Omron CX-Programmer project NewProject (CX-Programmer 9.75)

# PLC NewPLC1: CS1H-H CPU65
I/O table (CPU CS1W-SCB41-V1, CS1H-CPU65H): rack 0 slot 9 CS1W-CLK23

## Global symbols (name address type ; comment)
W134.05 BOOL  ; Kaeser BYPASS

## Program MainProgram (cyclic task 0)

### Section Section1

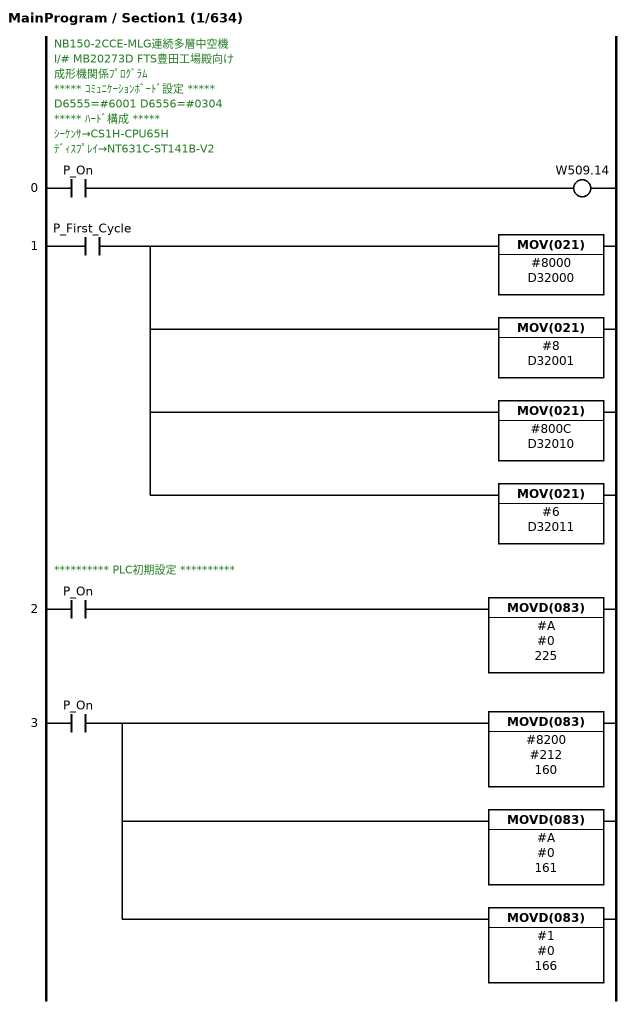
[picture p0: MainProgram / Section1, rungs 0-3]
; rung 0: NB150-2CCE-MLG連続多層中空機 / I/# MB20273D FTS豊田工場殿向け / 成形機関係ﾌﾟﾛｸﾞﾗﾑ / ***** ｺﾐｭﾆｹｰｼｮﾝﾎﾞｰﾄﾞ設定 ***** / D6555=#6001 D6556=#0304 / ***** ﾊｰﾄﾞ構成 ***** / ｼｰｹﾝｻ→CS1H-CPU65H / ﾃﾞｨｽﾌﾟﾚｲ→NT631C-ST141B-V2
LD P_On
OUT W509.14
; rung 1
LD P_First_Cycle
MOV(021) #8000 D32000
MOV(021) #8 D32001
MOV(021) #800C D32010  // 変更前　#851C
MOV(021) #6 D32011  // 変更前　#0000
; rung 2: ********** PLC初期設定 **********
LD P_On
MOVD(083) #A #0 225  // 瞬停検出 10ms
; rung 3
LD P_On
MOVD(083) #8200 #212 160  // NTﾘﾝｸﾓｰﾄﾞ
MOVD(083) #A #0 161  // 高速NTﾘﾝｸ
MOVD(083) #1 #0 166  // 号機数

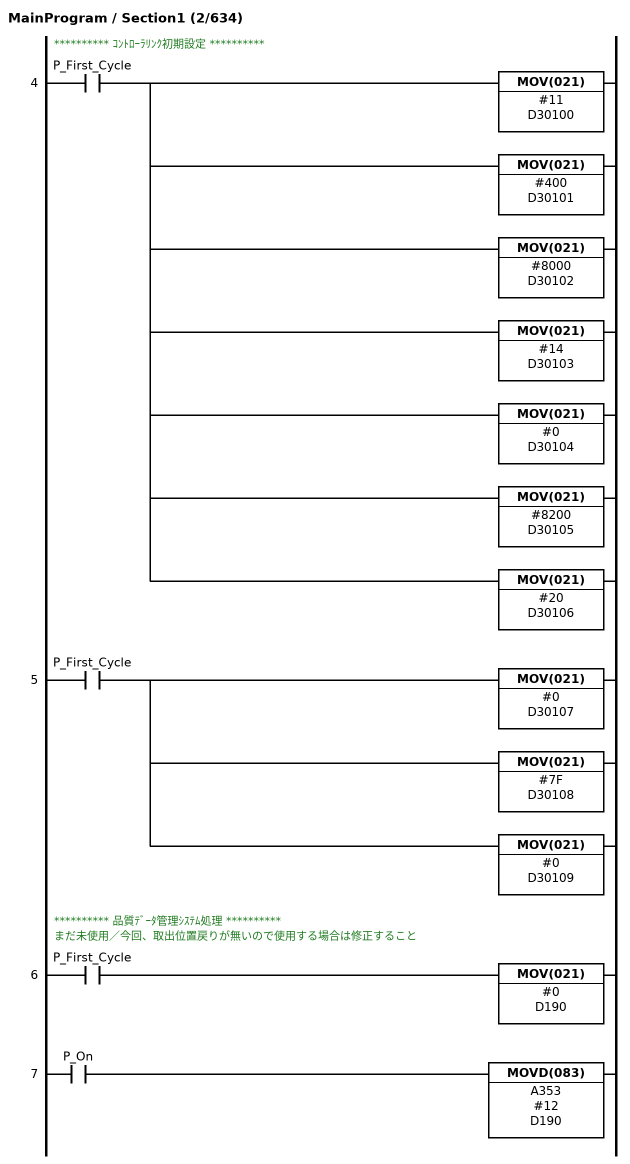
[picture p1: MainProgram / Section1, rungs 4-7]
; rung 4: ********** ｺﾝﾄﾛｰﾗﾘﾝｸ初期設定 **********
LD P_First_Cycle
MOV(021) #11 D30100
MOV(021) #400 D30101
MOV(021) #8000 D30102
MOV(021) #14 D30103
MOV(021) #0 D30104
MOV(021) #8200 D30105
MOV(021) #20 D30106
; rung 5
LD P_First_Cycle
MOV(021) #0 D30107
MOV(021) #7F D30108
MOV(021) #0 D30109
; rung 6: ********** 品質ﾃﾞｰﾀ管理ｼｽﾃﾑ処理 ********** / まだ未使用／今回、取出位置戻りが無いので使用する場合は修正すること
LD P_First_Cycle
MOV(021) #0 D190
; rung 7
LD P_On
MOVD(083) A353 #12 D190

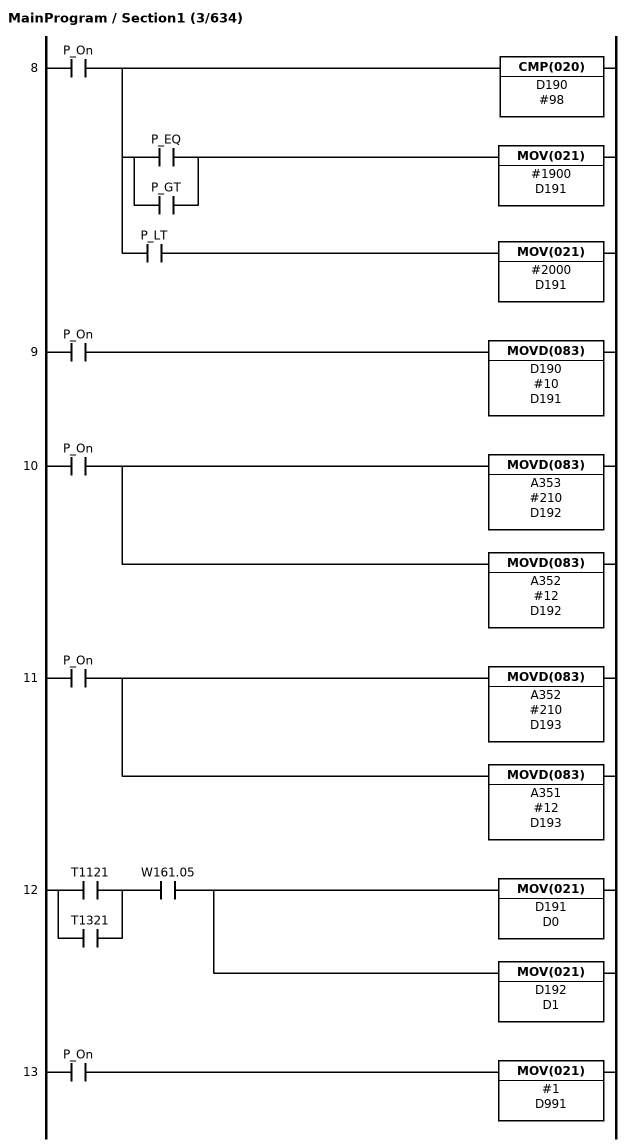
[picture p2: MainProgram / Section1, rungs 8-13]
; rung 8
LD P_On
OUT TR0
CMP(020) D190 #98
LD P_EQ
OR P_GT
ANDLD
MOV(021) #1900 D191
LD TR0
AND P_LT
MOV(021) #2000 D191
; rung 9
LD P_On
MOVD(083) D190 #10 D191
; rung 10
LD P_On
MOVD(083) A353 #210 D192
MOVD(083) A352 #12 D192
; rung 11
LD P_On
MOVD(083) A352 #210 D193
MOVD(083) A351 #12 D193
; rung 12
LD T1121
OR T1321
AND W161.05
MOV(021) D191 D0
MOV(021) D192 D1
; rung 13
LD P_On
MOV(021) #1 D991

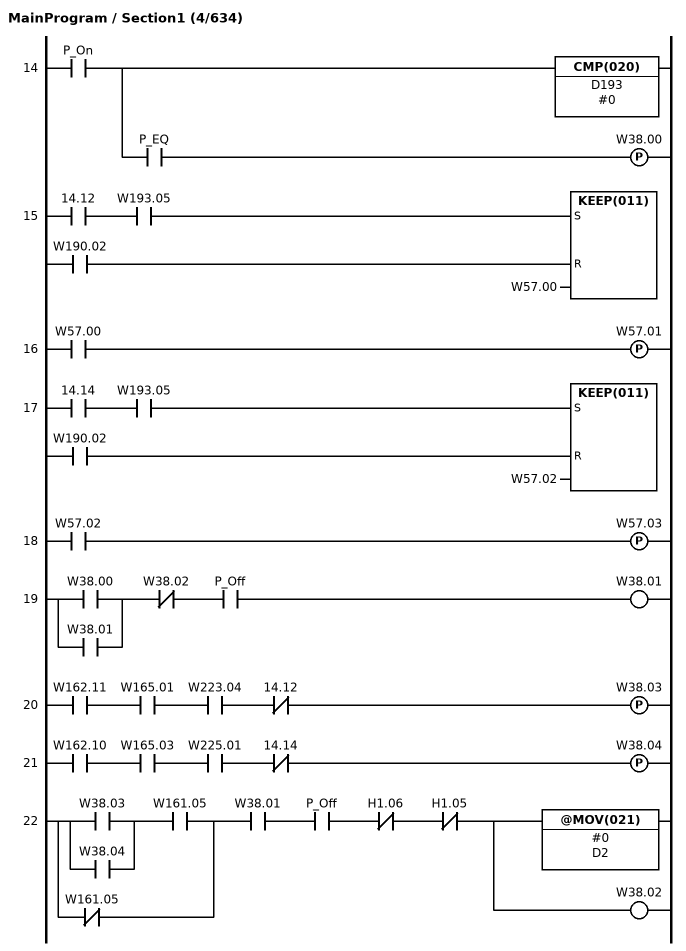
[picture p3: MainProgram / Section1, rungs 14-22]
; rung 14
LD P_On
CMP(020) D193 #0
AND P_EQ
DIFU(013) W38.00
; rung 15
LD 14.12
AND W193.05
LD W190.02
KEEP(011) W57.00
; rung 16
LD W57.00
DIFU(013) W57.01
; rung 17
LD 14.14
AND W193.05
LD W190.02
KEEP(011) W57.02
; rung 18
LD W57.02
DIFU(013) W57.03
; rung 19
LD W38.00
OR W38.01
ANDNOT W38.02
AND P_Off
OUT W38.01
; rung 20
LD W162.11
AND W165.01
AND W223.04
ANDNOT 14.12
DIFU(013) W38.03
; rung 21
LD W162.10
AND W165.03
AND W225.01
ANDNOT 14.14
DIFU(013) W38.04
; rung 22
LD W38.03
OR W38.04
AND W161.05
ORNOT W161.05
AND W38.01
AND P_Off
ANDNOT H1.06
ANDNOT H1.05
@MOV(021) #0 D2
OUT W38.02

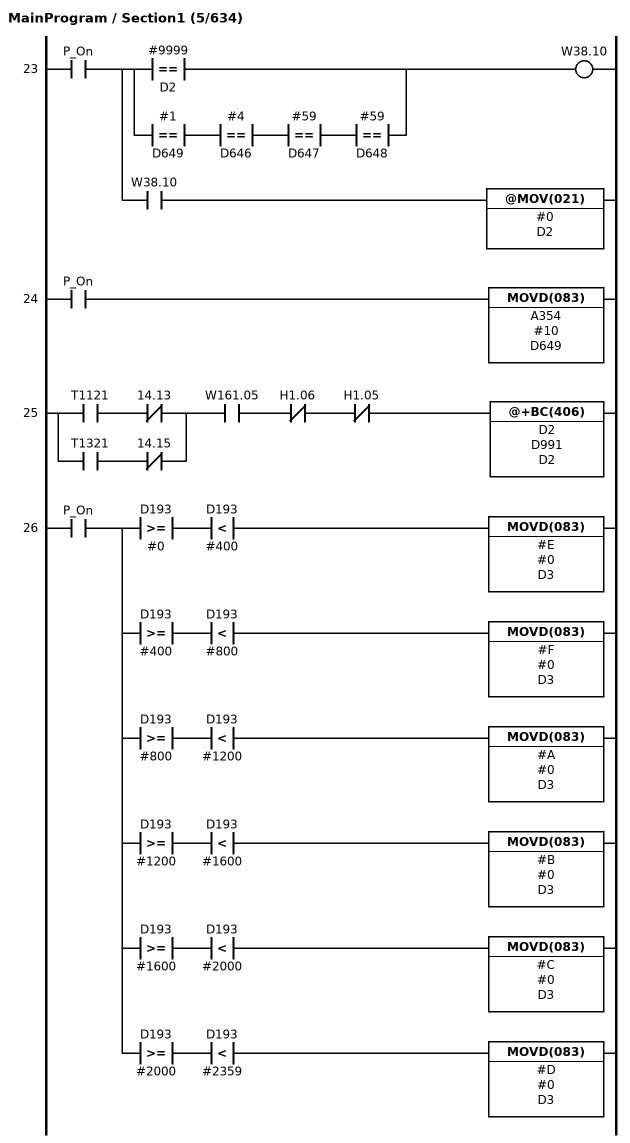
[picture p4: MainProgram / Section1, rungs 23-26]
; rung 23
LD P_On
OUT TR0
LD=(300) #9999 D2
LD=(300) #1 D649
AND=(300) #4 D646
AND=(300) #59 D647
AND=(300) #59 D648
ORLD
ANDLD
OUT W38.10
LD TR0
AND W38.10
@MOV(021) #0 D2
; rung 24
LD P_On
MOVD(083) A354 #10 D649
; rung 25
LD T1121
ANDNOT 14.13
LD T1321
ANDNOT 14.15
ORLD
AND W161.05
ANDNOT H1.06
ANDNOT H1.05
@+BC(406) D2 D991 D2
; rung 26
LD P_On
OUT TR0
AND>=(325) D193 #0
AND<(310) D193 #400
MOVD(083) #E #0 D3
LD TR0
AND>=(325) D193 #400
AND<(310) D193 #800
MOVD(083) #F #0 D3
LD TR0
AND>=(325) D193 #800
AND<(310) D193 #1200
MOVD(083) #A #0 D3
LD TR0
AND>=(325) D193 #1200
AND<(310) D193 #1600
MOVD(083) #B #0 D3
LD TR0
AND>=(325) D193 #1600
AND<(310) D193 #2000
MOVD(083) #C #0 D3
LD TR0
AND>=(325) D193 #2000
AND<(310) D193 #2359
MOVD(083) #D #0 D3

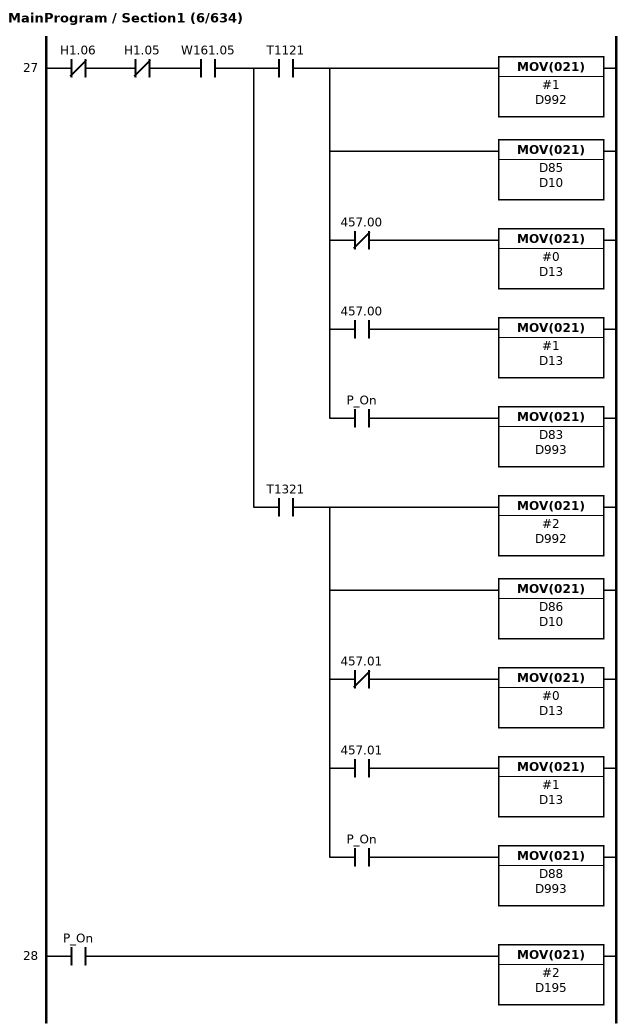
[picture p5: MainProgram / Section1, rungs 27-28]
; rung 27
LDNOT H1.06
ANDNOT H1.05
AND W161.05
OUT TR0
AND T1121
OUT TR1
MOV(021) #1 D992
MOV(021) D85 D10
ANDNOT 457.00
MOV(021) #0 D13
LD TR1
AND 457.00
MOV(021) #1 D13
LD TR1
AND P_On
MOV(021) D83 D993
LD TR0
AND T1321
OUT TR0
MOV(021) #2 D992
MOV(021) D86 D10
ANDNOT 457.01
MOV(021) #0 D13
LD TR0
AND 457.01
MOV(021) #1 D13
LD TR0
AND P_On
MOV(021) D88 D993
; rung 28
LD P_On
MOV(021) #2 D195  // 成型機№　追加　AHT#2　→#2

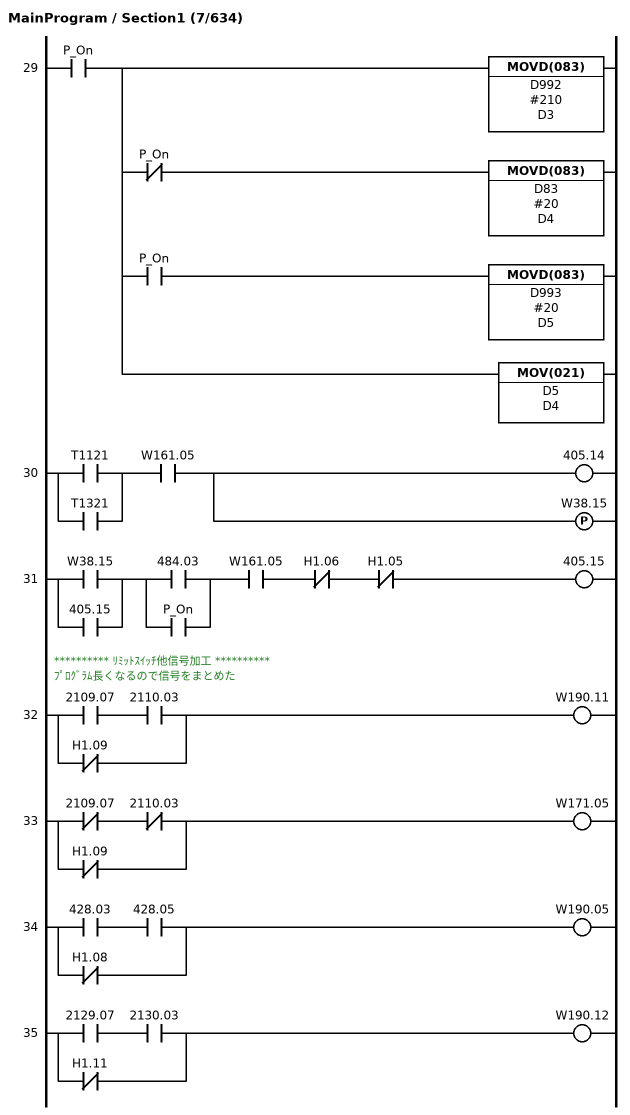
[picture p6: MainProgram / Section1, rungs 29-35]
; rung 29
LD P_On
OUT TR0
MOVD(083) D992 #210 D3
ANDNOT P_On
MOVD(083) D83 #20 D4
LD TR0
AND P_On
MOVD(083) D993 #20 D5  // 変更前　D4　　　変更後D5
LD TR0
MOV(021) D5 D4
; rung 30
LD T1121
OR T1321
AND W161.05
OUT 405.14
DIFU(013) W38.15
; rung 31
LD W38.15
OR 405.15
LD 484.03
OR P_On  // ﾊﾞﾘ切ﾛﾎﾞｯﾄCL無くなるのでﾊﾞｲﾊﾟｽ
ANDLD
AND W161.05
ANDNOT H1.06
ANDNOT H1.05
OUT 405.15
; rung 32: ********** ﾘﾐｯﾄｽｲｯﾁ他信号加工 ********** / ﾌﾟﾛｸﾞﾗﾑ長くなるので信号をまとめた
LD 2109.07
AND 2110.03
ORNOT H1.09
OUT W190.11
; rung 33
LDNOT 2109.07
ANDNOT 2110.03
ORNOT H1.09
OUT W171.05
; rung 34
LD 428.03
AND 428.05
ORNOT H1.08
OUT W190.05
; rung 35
LD 2129.07
AND 2130.03
ORNOT H1.11
OUT W190.12

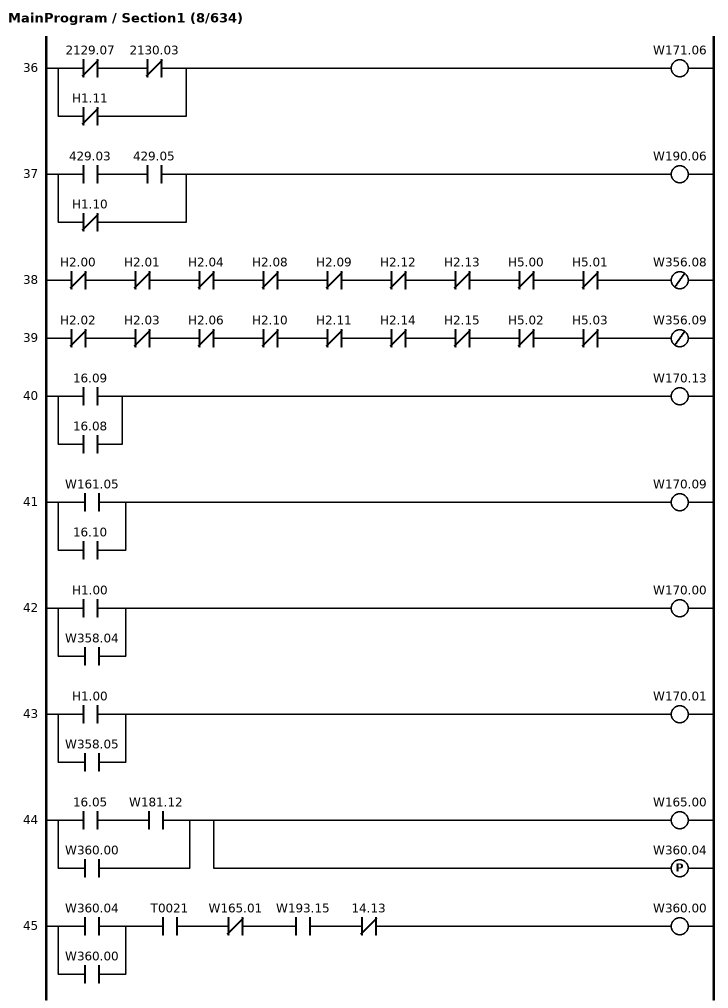
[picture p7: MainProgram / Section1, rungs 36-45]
; rung 36
LDNOT 2129.07
ANDNOT 2130.03
ORNOT H1.11
OUT W171.06
; rung 37
LD 429.03
AND 429.05
ORNOT H1.10
OUT W190.06
; rung 38
LDNOT H2.00
ANDNOT H2.01
ANDNOT H2.04
ANDNOT H2.08
ANDNOT H2.09
ANDNOT H2.12
ANDNOT H2.13
ANDNOT H5.00
ANDNOT H5.01
OUTNOT W356.08
; rung 39
LDNOT H2.02
ANDNOT H2.03
ANDNOT H2.06
ANDNOT H2.10
ANDNOT H2.11
ANDNOT H2.14
ANDNOT H2.15
ANDNOT H5.02
ANDNOT H5.03
OUTNOT W356.09
; rung 40
LD 16.09
OR 16.08
OUT W170.13
; rung 41
LD W161.05
OR 16.10
OUT W170.09
; rung 42
LD H1.00
OR W358.04
OUT W170.00
; rung 43
LD H1.00
OR W358.05
OUT W170.01
; rung 44
LD 16.05
AND W181.12
OR W360.00
OUT W165.00
DIFU(013) W360.04
; rung 45
LD W360.04
OR W360.00
AND T0021
ANDNOT W165.01
AND W193.15
ANDNOT 14.13
OUT W360.00

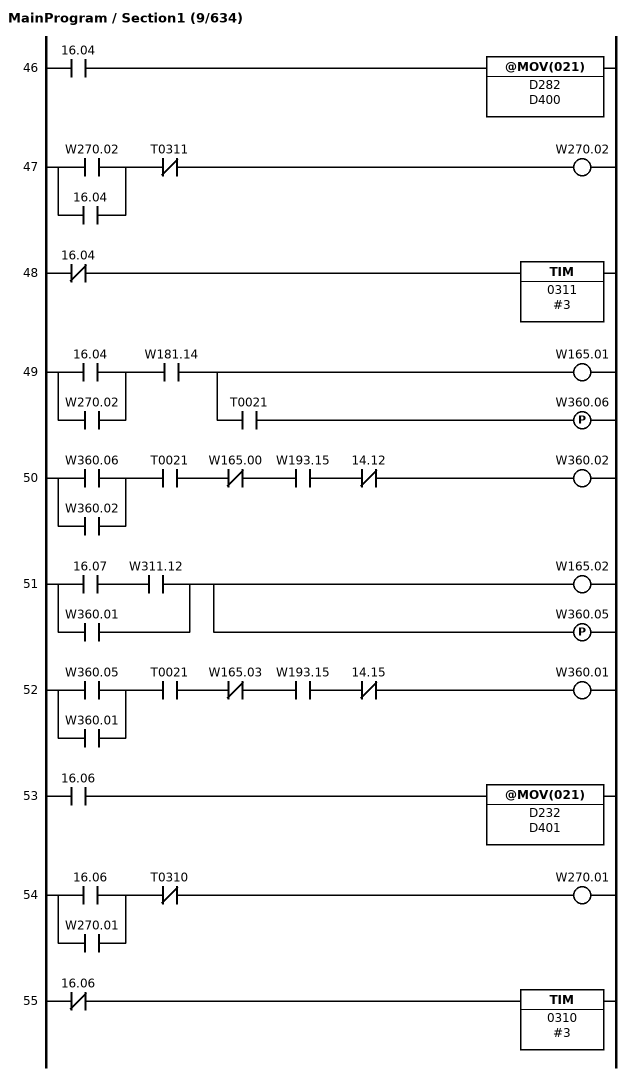
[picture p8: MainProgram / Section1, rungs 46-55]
; rung 46
LD 16.04
@MOV(021) D282 D400
; rung 47
LD W270.02
OR 16.04
ANDNOT T0311
OUT W270.02
; rung 48
LDNOT 16.04
TIM 0311 #3
; rung 49
LD 16.04
OR W270.02
AND W181.14
OUT W165.01
AND T0021
DIFU(013) W360.06
; rung 50
LD W360.06
OR W360.02
AND T0021
ANDNOT W165.00
AND W193.15
ANDNOT 14.12
OUT W360.02
; rung 51
LD 16.07
AND W311.12
OR W360.01
OUT W165.02
DIFU(013) W360.05
; rung 52
LD W360.05
OR W360.01
AND T0021
ANDNOT W165.03
AND W193.15
ANDNOT 14.15
OUT W360.01
; rung 53
LD 16.06
@MOV(021) D232 D401
; rung 54
LD 16.06
OR W270.01
ANDNOT T0310
OUT W270.01
; rung 55
LDNOT 16.06
TIM 0310 #3

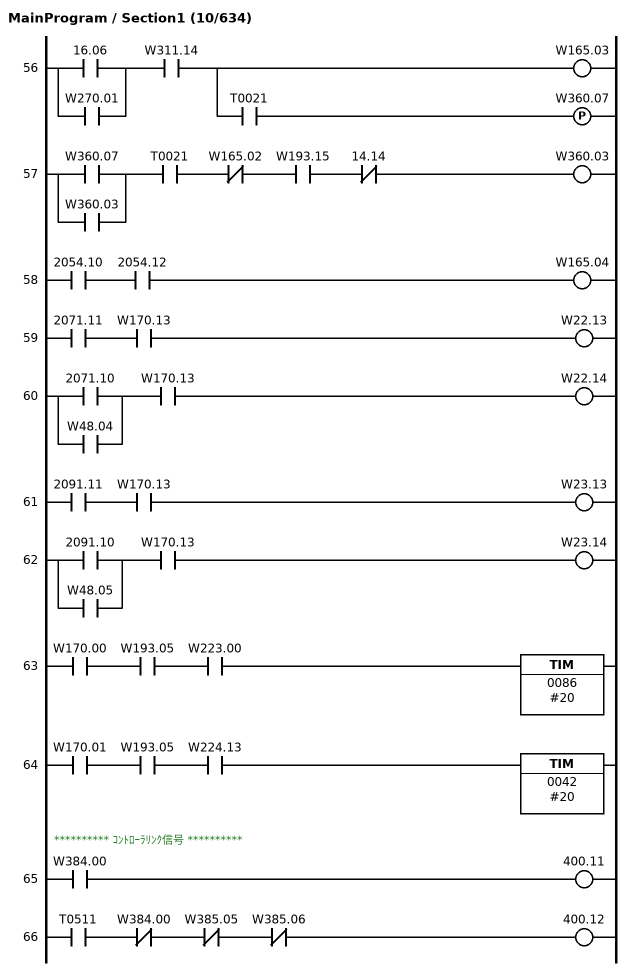
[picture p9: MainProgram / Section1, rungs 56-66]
; rung 56
LD 16.06
OR W270.01
AND W311.14
OUT W165.03
AND T0021
DIFU(013) W360.07
; rung 57
LD W360.07
OR W360.03
AND T0021
ANDNOT W165.02
AND W193.15
ANDNOT 14.14
OUT W360.03
; rung 58
LD 2054.10
AND 2054.12
OUT W165.04
; rung 59
LD 2071.11
AND W170.13
OUT W22.13
; rung 60
LD 2071.10
OR W48.04
AND W170.13
OUT W22.14
; rung 61
LD 2091.11
AND W170.13
OUT W23.13
; rung 62
LD 2091.10
OR W48.05
AND W170.13
OUT W23.14
; rung 63
LD W170.00
AND W193.05
AND W223.00
TIM 0086 #20
; rung 64
LD W170.01
AND W193.05
AND W224.13
TIM 0042 #20
; rung 65: ********** ｺﾝﾄﾛｰﾗﾘﾝｸ信号 **********
LD W384.00
OUT 400.11
; rung 66
LD T0511
ANDNOT W384.00
ANDNOT W385.05
ANDNOT W385.06
OUT 400.12

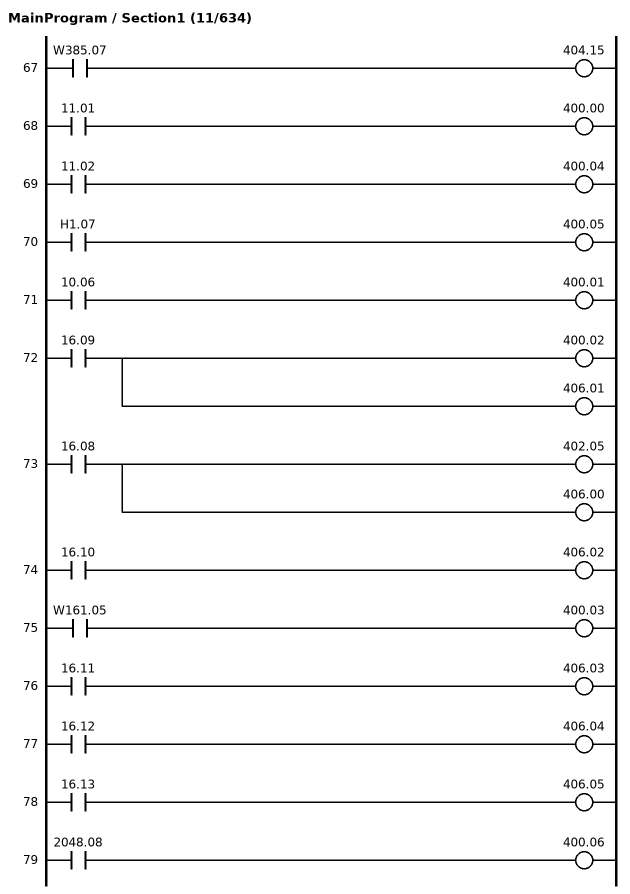
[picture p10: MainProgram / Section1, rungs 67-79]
; rung 67
LD W385.07
OUT 404.15
; rung 68
LD 11.01
OUT 400.00
; rung 69
LD 11.02
OUT 400.04
; rung 70
LD H1.07
OUT 400.05
; rung 71
LD 10.06
OUT 400.01
; rung 72
LD 16.09
OUT 400.02
OUT 406.01
; rung 73
LD 16.08
OUT 402.05
OUT 406.00
; rung 74
LD 16.10
OUT 406.02
; rung 75
LD W161.05
OUT 400.03
; rung 76
LD 16.11
OUT 406.03
; rung 77
LD 16.12
OUT 406.04
; rung 78
LD 16.13
OUT 406.05
; rung 79
LD 2048.08
OUT 400.06

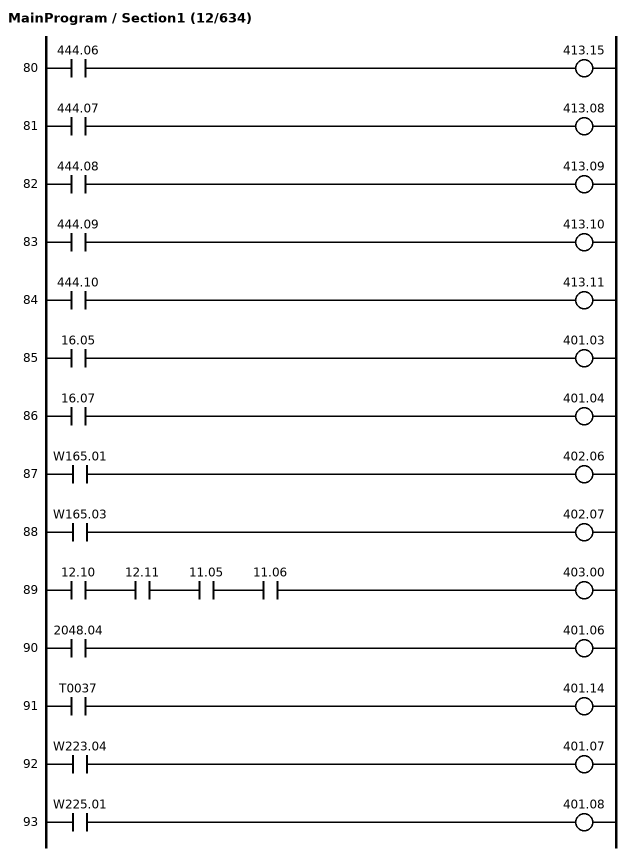
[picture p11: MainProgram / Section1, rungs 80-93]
; rung 80
LD 444.06
OUT 413.15
; rung 81
LD 444.07
OUT 413.08
; rung 82
LD 444.08
OUT 413.09
; rung 83
LD 444.09
OUT 413.10
; rung 84
LD 444.10
OUT 413.11
; rung 85
LD 16.05
OUT 401.03
; rung 86
LD 16.07
OUT 401.04
; rung 87
LD W165.01
OUT 402.06
; rung 88
LD W165.03
OUT 402.07
; rung 89
LD 12.10
AND 12.11
AND 11.05
AND 11.06
OUT 403.00
; rung 90
LD 2048.04
OUT 401.06
; rung 91
LD T0037
OUT 401.14
; rung 92
LD W223.04
OUT 401.07
; rung 93
LD W225.01
OUT 401.08

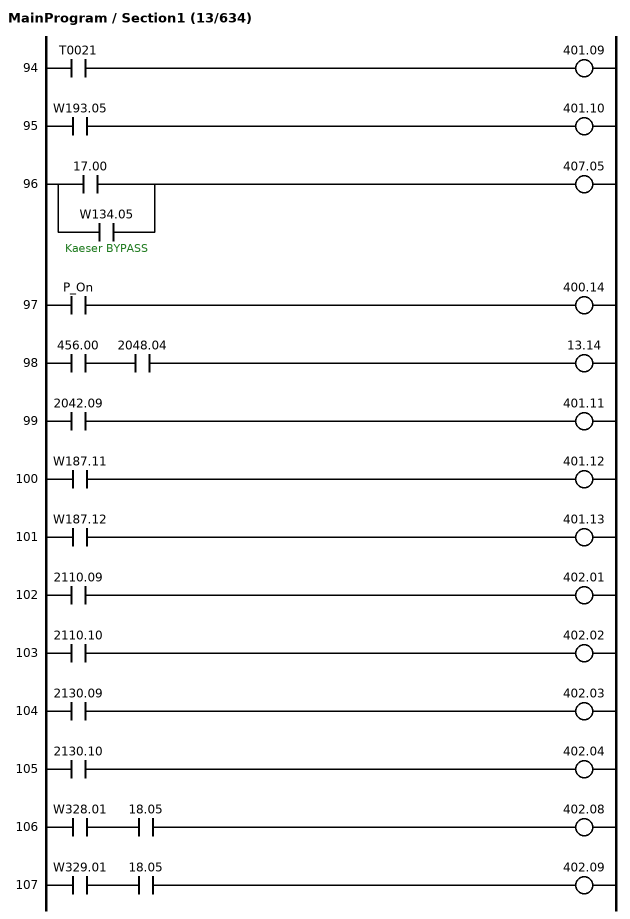
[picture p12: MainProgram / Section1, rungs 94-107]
; rung 94
LD T0021
OUT 401.09
; rung 95
LD W193.05
OUT 401.10
; rung 96
LD 17.00
OR W134.05  ; Kaeser BYPASS
OUT 407.05
; rung 97
LD P_On
OUT 400.14
; rung 98
LD 456.00
AND 2048.04
OUT 13.14
; rung 99
LD 2042.09
OUT 401.11
; rung 100
LD W187.11
OUT 401.12
; rung 101
LD W187.12
OUT 401.13
; rung 102
LD 2110.09
OUT 402.01
; rung 103
LD 2110.10
OUT 402.02
; rung 104
LD 2130.09
OUT 402.03
; rung 105
LD 2130.10
OUT 402.04
; rung 106
LD W328.01
AND 18.05
OUT 402.08
; rung 107
LD W329.01
AND 18.05
OUT 402.09

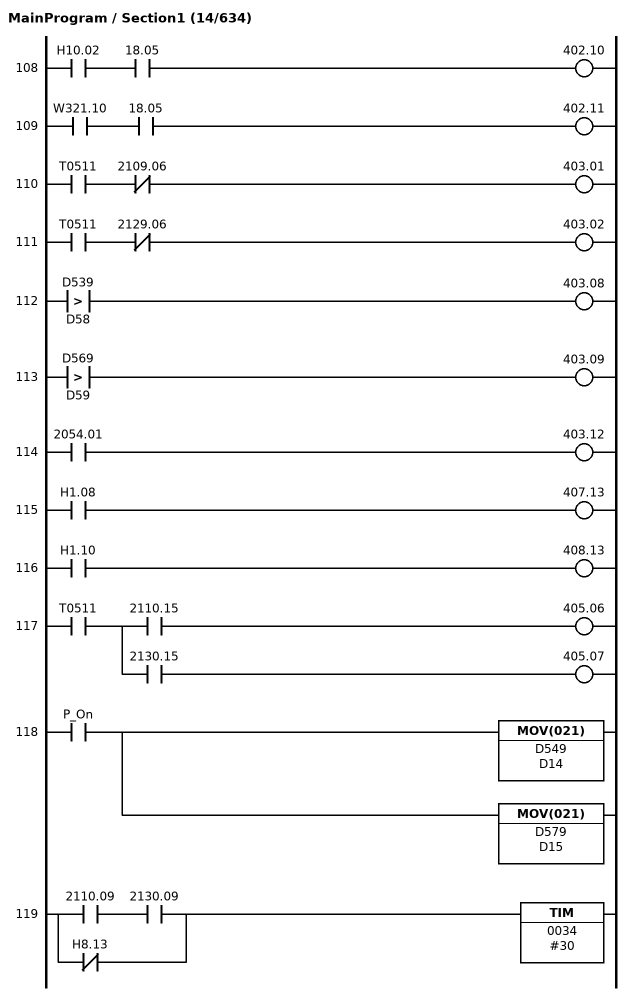
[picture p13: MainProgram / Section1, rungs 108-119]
; rung 108
LD H10.02
AND 18.05
OUT 402.10
; rung 109
LD W321.10
AND 18.05
OUT 402.11
; rung 110
LD T0511
ANDNOT 2109.06
OUT 403.01
; rung 111
LD T0511
ANDNOT 2129.06
OUT 403.02
; rung 112
LD>(320) D539 D58
OUT 403.08
; rung 113
LD>(320) D569 D59
OUT 403.09
; rung 114
LD 2054.01
OUT 403.12
; rung 115
LD H1.08
OUT 407.13
; rung 116
LD H1.10
OUT 408.13
; rung 117
LD T0511
OUT TR0
AND 2110.15
OUT 405.06
LD TR0
AND 2130.15
OUT 405.07
; rung 118
LD P_On
MOV(021) D549 D14
MOV(021) D579 D15
; rung 119
LD 2110.09
AND 2130.09
ORNOT H8.13
TIM 0034 #30

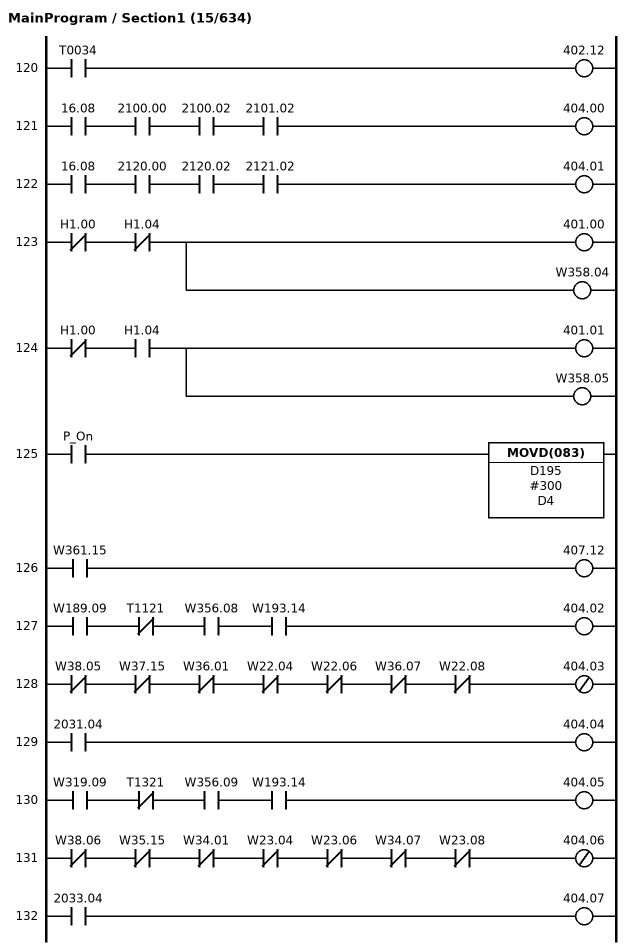
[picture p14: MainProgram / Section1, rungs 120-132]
; rung 120
LD T0034
OUT 402.12
; rung 121
LD 16.08
AND 2100.00
AND 2100.02
AND 2101.02
OUT 404.00
; rung 122
LD 16.08
AND 2120.00
AND 2120.02
AND 2121.02
OUT 404.01
; rung 123
LDNOT H1.00
ANDNOT H1.04
OUT 401.00
OUT W358.04
; rung 124
LDNOT H1.00
AND H1.04
OUT 401.01
OUT W358.05
; rung 125
LD P_On
MOVD(083) D195 #300 D4
; rung 126
LD W361.15
OUT 407.12
; rung 127
LD W189.09
ANDNOT T1121
AND W356.08
AND W193.14
OUT 404.02
; rung 128
LDNOT W38.05
ANDNOT W37.15
ANDNOT W36.01
ANDNOT W22.04
ANDNOT W22.06
ANDNOT W36.07
ANDNOT W22.08
OUTNOT 404.03
; rung 129
LD 2031.04
OUT 404.04
; rung 130
LD W319.09
ANDNOT T1321
AND W356.09
AND W193.14
OUT 404.05
; rung 131
LDNOT W38.06
ANDNOT W35.15
ANDNOT W34.01
ANDNOT W23.04
ANDNOT W23.06
ANDNOT W34.07
ANDNOT W23.08
OUTNOT 404.06
; rung 132
LD 2033.04
OUT 404.07

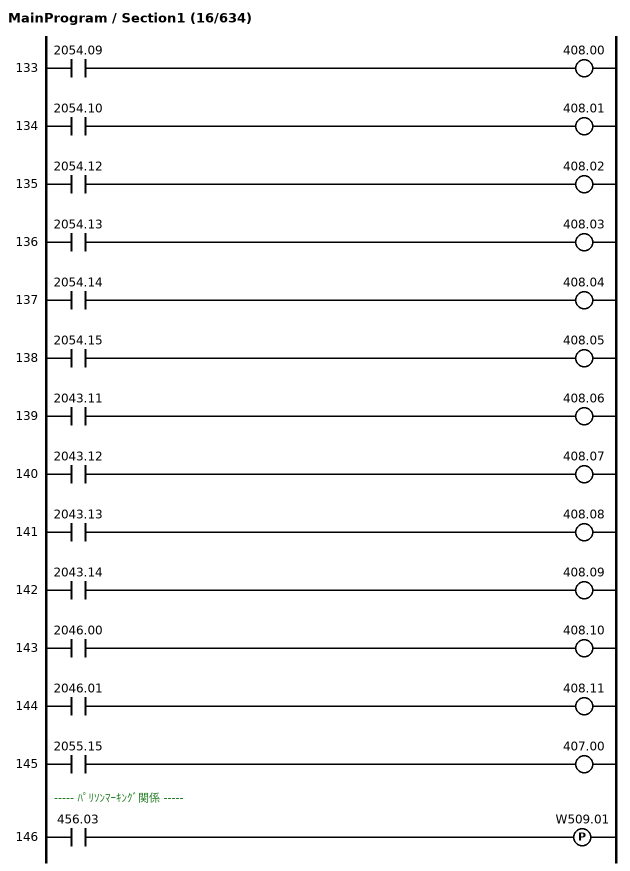
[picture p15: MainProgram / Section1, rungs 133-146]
; rung 133
LD 2054.09
OUT 408.00
; rung 134
LD 2054.10
OUT 408.01
; rung 135
LD 2054.12
OUT 408.02
; rung 136
LD 2054.13
OUT 408.03
; rung 137
LD 2054.14
OUT 408.04
; rung 138
LD 2054.15
OUT 408.05
; rung 139
LD 2043.11
OUT 408.06
; rung 140
LD 2043.12
OUT 408.07
; rung 141
LD 2043.13
OUT 408.08
; rung 142
LD 2043.14
OUT 408.09
; rung 143
LD 2046.00
OUT 408.10
; rung 144
LD 2046.01
OUT 408.11
; rung 145
LD 2055.15
OUT 407.00
; rung 146: ----- ﾊﾟﾘｿﾝﾏｰｷﾝｸﾞ関係 -----
LD 456.03
DIFU(013) W509.01

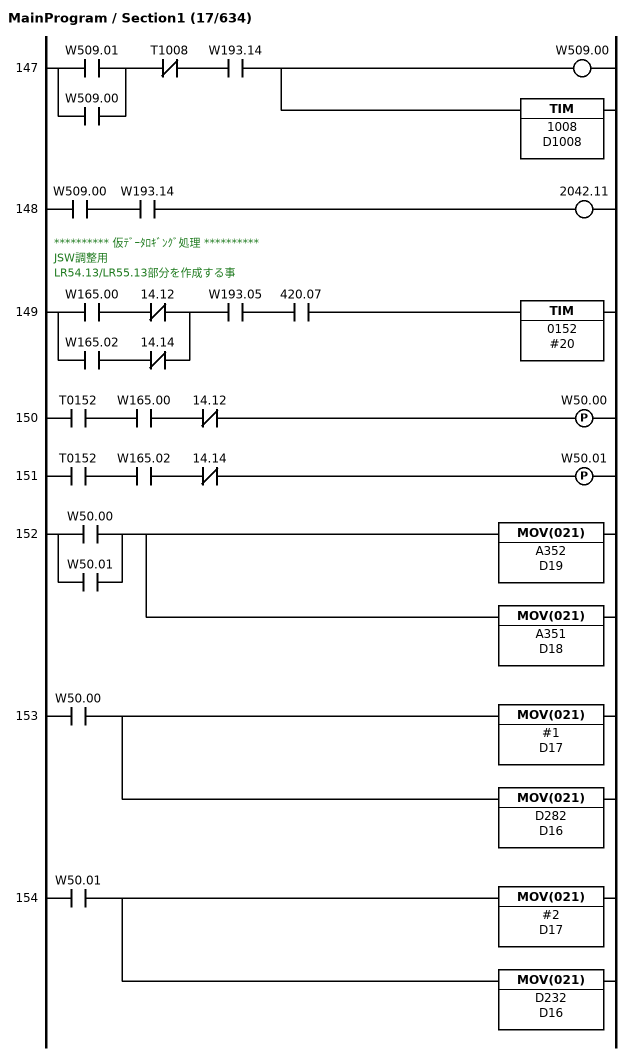
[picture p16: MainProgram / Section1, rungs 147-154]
; rung 147
LD W509.01
OR W509.00
ANDNOT T1008
AND W193.14
OUT W509.00
TIM 1008 D1008
; rung 148
LD W509.00
AND W193.14
OUT 2042.11
; rung 149: ********** 仮ﾃﾞｰﾀﾛｷﾞﾝｸﾞ処理 ********** / JSW調整用 / LR54.13/LR55.13部分を作成する事
LD W165.00
ANDNOT 14.12
LD W165.02
ANDNOT 14.14
ORLD
AND W193.05
AND 420.07
TIM 0152 #20
; rung 150
LD T0152
AND W165.00
ANDNOT 14.12
DIFU(013) W50.00
; rung 151
LD T0152
AND W165.02
ANDNOT 14.14
DIFU(013) W50.01
; rung 152
LD W50.00
OR W50.01
MOV(021) A352 D19
MOV(021) A351 D18
; rung 153
LD W50.00
MOV(021) #1 D17
MOV(021) D282 D16
; rung 154
LD W50.01
MOV(021) #2 D17
MOV(021) D232 D16

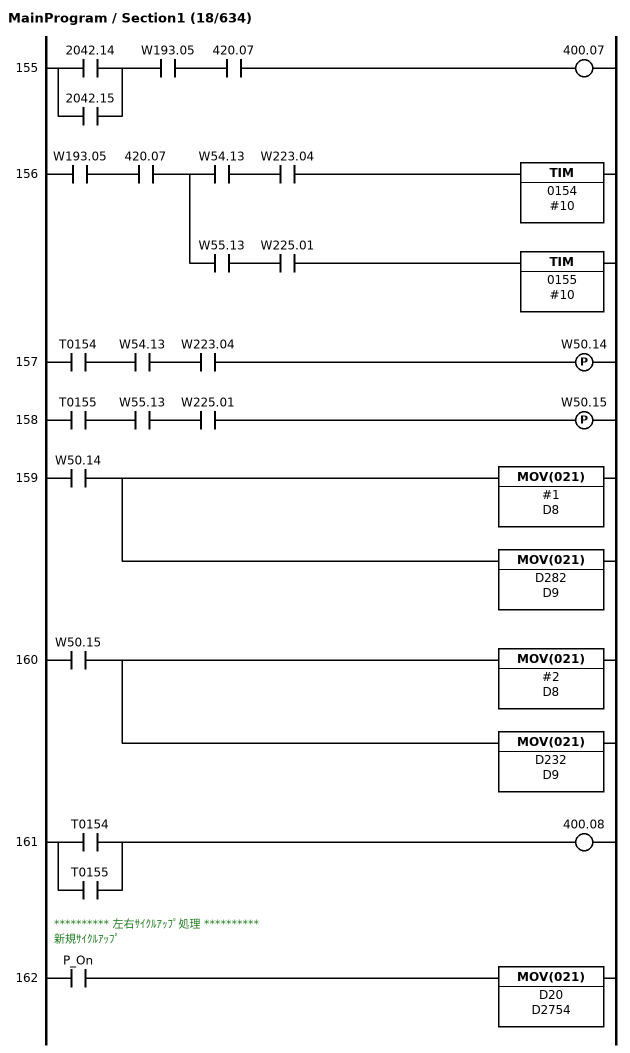
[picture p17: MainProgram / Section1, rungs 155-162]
; rung 155
LD 2042.14
OR 2042.15
AND W193.05
AND 420.07
OUT 400.07
; rung 156
LD W193.05
AND 420.07
OUT TR0
AND W54.13
AND W223.04
TIM 0154 #10
LD TR0
AND W55.13
AND W225.01
TIM 0155 #10
; rung 157
LD T0154
AND W54.13
AND W223.04
DIFU(013) W50.14
; rung 158
LD T0155
AND W55.13
AND W225.01
DIFU(013) W50.15
; rung 159
LD W50.14
MOV(021) #1 D8
MOV(021) D282 D9
; rung 160
LD W50.15
MOV(021) #2 D8
MOV(021) D232 D9
; rung 161
LD T0154
OR T0155
OUT 400.08
; rung 162: ********** 左右ｻｲｸﾙｱｯﾌﾟ処理 ********** / 新規ｻｲｸﾙｱｯﾌﾟ
LD P_On
MOV(021) D20 D2754

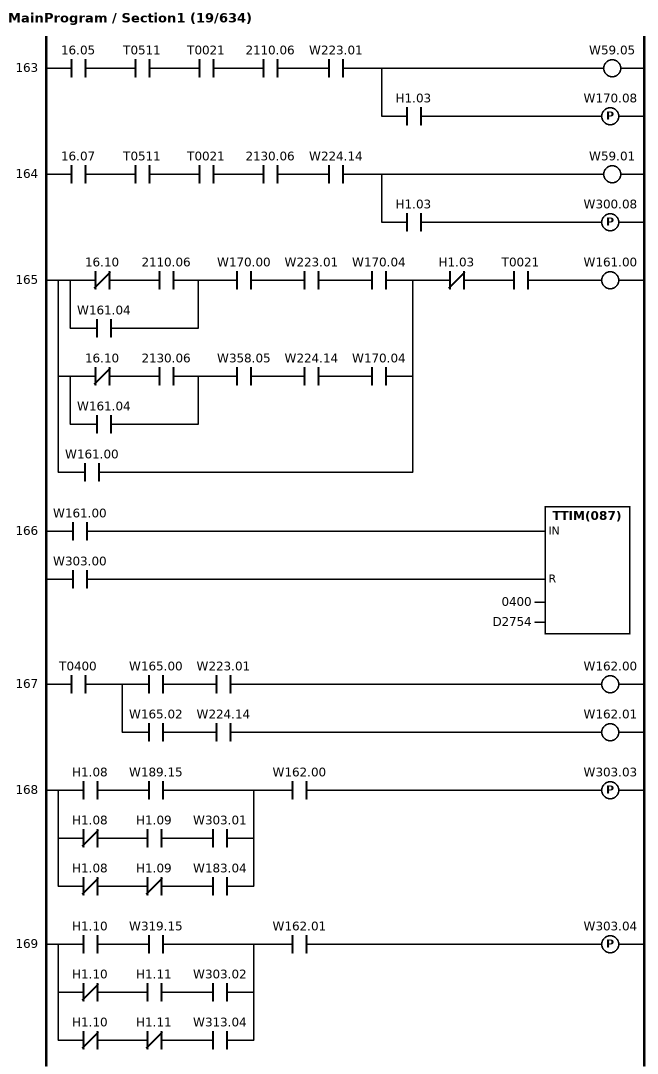
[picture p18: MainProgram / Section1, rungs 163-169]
; rung 163
LD 16.05
AND T0511
AND T0021
AND 2110.06
AND W223.01
OUT W59.05
AND H1.03
DIFU(013) W170.08
; rung 164
LD 16.07
AND T0511
AND T0021
AND 2130.06
AND W224.14
OUT W59.01
AND H1.03
DIFU(013) W300.08
; rung 165
LDNOT 16.10
AND 2110.06
OR W161.04
AND W170.00
AND W223.01
AND W170.04
LDNOT 16.10
AND 2130.06
OR W161.04
AND W358.05
AND W224.14
AND W170.04
ORLD
OR W161.00
ANDNOT H1.03
AND T0021
OUT W161.00
; rung 166
LD W161.00
LD W303.00
TTIM(087) 0400 D2754
; rung 167
LD T0400
OUT TR0
AND W165.00
AND W223.01
OUT W162.00
LD TR0
AND W165.02
AND W224.14
OUT W162.01
; rung 168
LD H1.08
AND W189.15
LDNOT H1.08
AND H1.09
AND W303.01
ORLD
LDNOT H1.08
ANDNOT H1.09
AND W183.04
ORLD
AND W162.00
DIFU(013) W303.03
; rung 169
LD H1.10
AND W319.15
LDNOT H1.10
AND H1.11
AND W303.02
ORLD
LDNOT H1.10
ANDNOT H1.11
AND W313.04
ORLD
AND W162.01
DIFU(013) W303.04

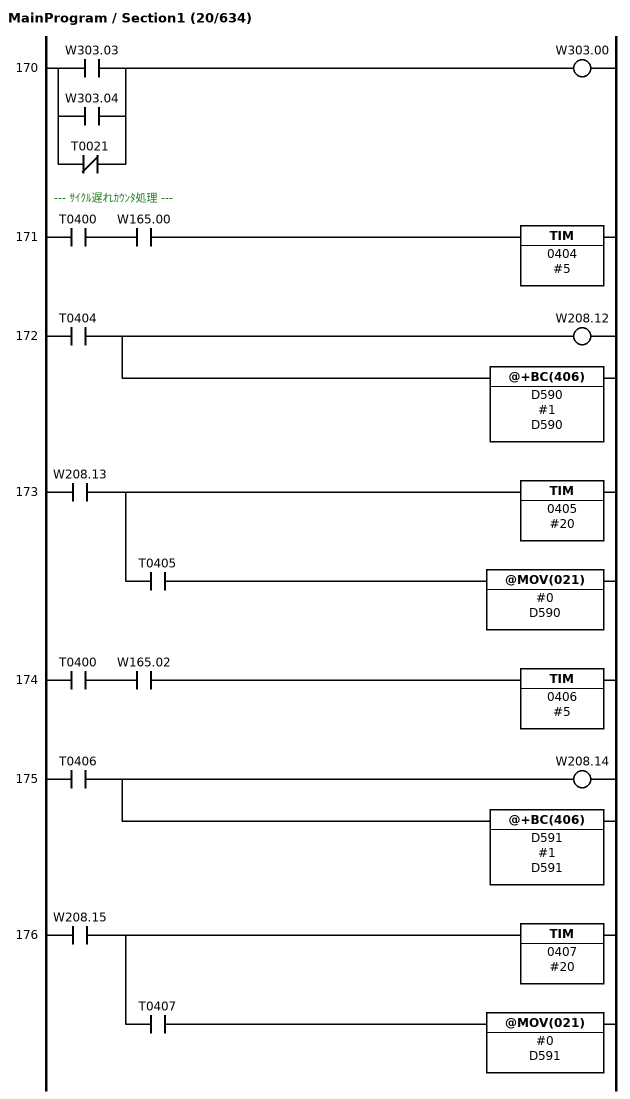
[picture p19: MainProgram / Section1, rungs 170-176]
; rung 170
LD W303.03
OR W303.04
ORNOT T0021
OUT W303.00
; rung 171: --- ｻｲｸﾙ遅れｶｳﾝﾀ処理 ---
LD T0400
AND W165.00
TIM 0404 #5
; rung 172
LD T0404
OUT W208.12
@+BC(406) D590 #1 D590
; rung 173
LD W208.13
TIM 0405 #20
AND T0405
@MOV(021) #0 D590
; rung 174
LD T0400
AND W165.02
TIM 0406 #5
; rung 175
LD T0406
OUT W208.14
@+BC(406) D591 #1 D591
; rung 176
LD W208.15
TIM 0407 #20
AND T0407
@MOV(021) #0 D591

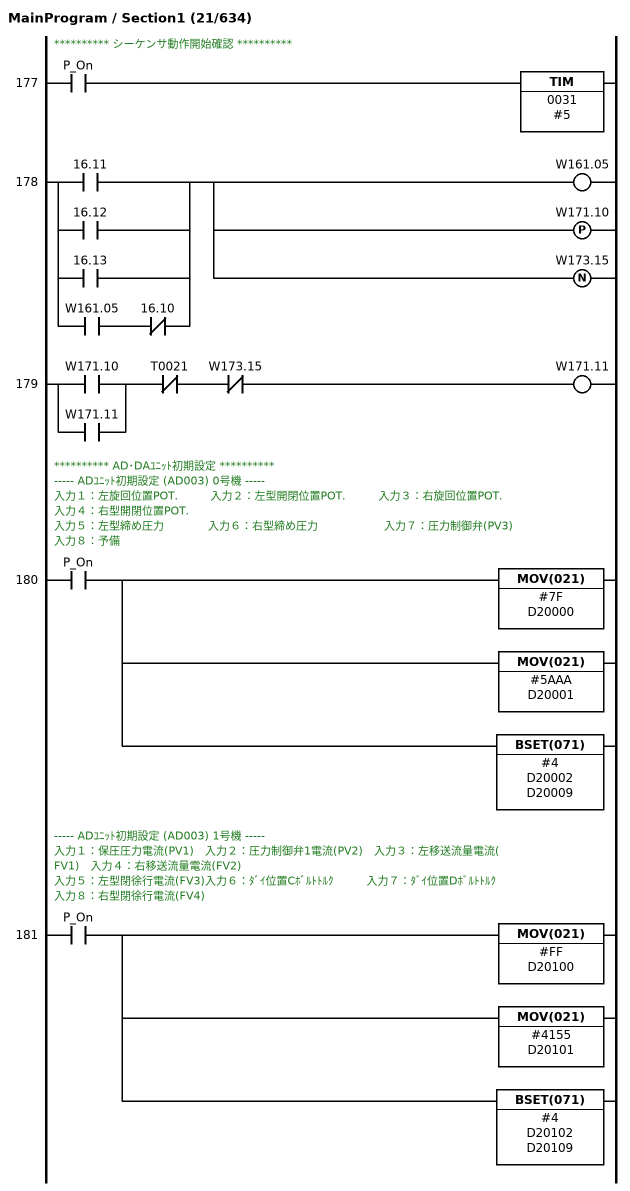
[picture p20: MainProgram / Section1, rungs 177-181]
; rung 177: ********** シーケンサ動作開始確認 **********
LD P_On
TIM 0031 #5
; rung 178
LD 16.11
OR 16.12
OR 16.13
LD W161.05
ANDNOT 16.10
ORLD
OUT W161.05
DIFU(013) W171.10
DIFD(014) W173.15
; rung 179
LD W171.10
OR W171.11
ANDNOT T0021
ANDNOT W173.15
OUT W171.11
; rung 180: ********** AD･DAﾕﾆｯﾄ初期設定 ********** / ----- ADﾕﾆｯﾄ初期設定 (AD003) 0号機 ----- / 入力１：左旋回位置POT.　　　入力２：左型開閉位置POT.　　　入力３：右旋回位置POT.　　　入力４：右型開閉位置POT. / 入力５：左型締め圧力　　　　入力６：右型締め圧力　　　　　　入力７：圧力制御弁(PV3)　　　 入力８：予備
LD P_On
MOV(021) #7F D20000
MOV(021) #5AAA D20001
BSET(071) #4 D20002 D20009
; rung 181: ----- ADﾕﾆｯﾄ初期設定 (AD003) 1号機 ----- / 入力１：保圧圧力電流(PV1)　入力２：圧力制御弁1電流(PV2)　入力３：左移送流量電流(FV1)　入力４：右移送流量電流(FV2) / 入力５：左型閉徐行電流(FV3)入力６：ﾀﾞｲ位置Cﾎﾞﾙﾄﾄﾙｸ　　　入力７：ﾀﾞｲ位置Dﾎﾞﾙﾄﾄﾙｸ　　　 入力８：右型閉徐行電流(FV4)
LD P_On
MOV(021) #FF D20100
MOV(021) #4155 D20101
BSET(071) #4 D20102 D20109

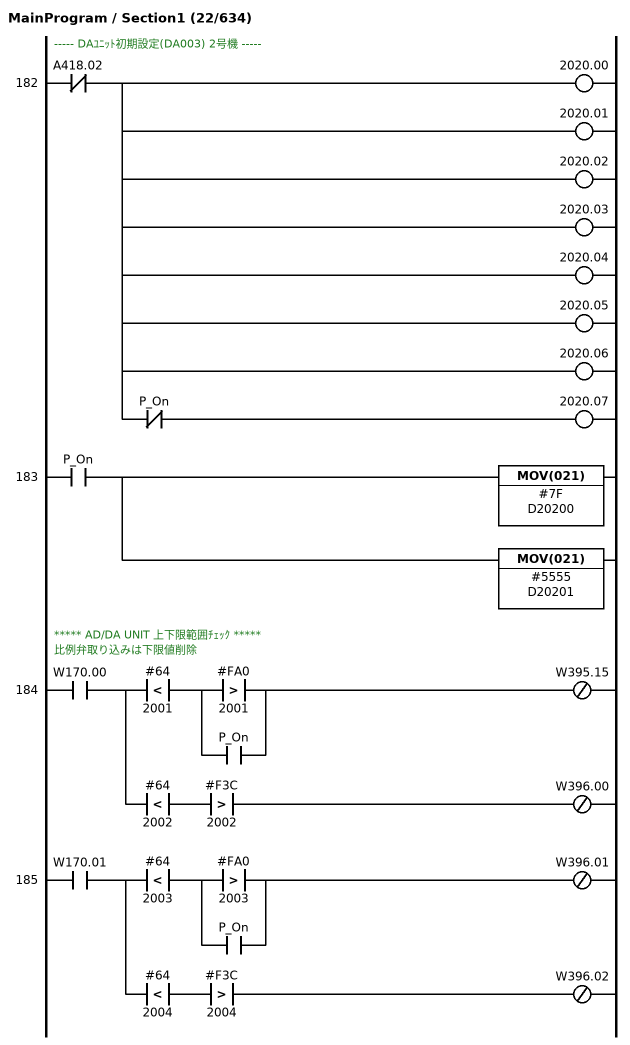
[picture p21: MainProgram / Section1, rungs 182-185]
; rung 182: ----- DAﾕﾆｯﾄ初期設定(DA003) 2号機 -----
LDNOT A418.02
OUT 2020.00
OUT 2020.01
OUT 2020.02
OUT 2020.03
OUT 2020.04
OUT 2020.05
OUT 2020.06
ANDNOT P_On
OUT 2020.07
; rung 183
LD P_On
MOV(021) #7F D20200
MOV(021) #5555 D20201
; rung 184: ***** AD/DA UNIT 上下限範囲ﾁｪｯｸ ***** / 比例弁取り込みは下限値削除
LD W170.00
OUT TR0
AND<(310) #64 2001
LD>(320) #FA0 2001
OR P_On
ANDLD
OUTNOT W395.15
LD TR0
AND<(310) #64 2002
AND>(320) #F3C 2002
OUTNOT W396.00
; rung 185
LD W170.01
OUT TR0
AND<(310) #64 2003
LD>(320) #FA0 2003
OR P_On
ANDLD
OUTNOT W396.01
LD TR0
AND<(310) #64 2004
AND>(320) #F3C 2004
OUTNOT W396.02

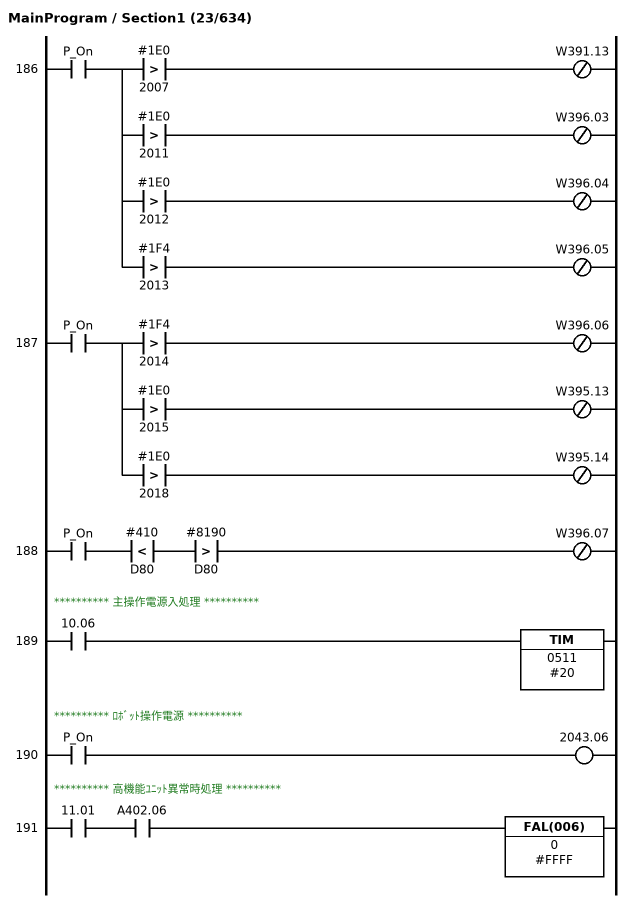
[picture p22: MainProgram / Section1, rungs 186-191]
; rung 186
LD P_On
OUT TR0
AND>S(322) #1E0 2007
OUTNOT W391.13
LD TR0
AND>S(322) #1E0 2011
OUTNOT W396.03
LD TR0
AND>S(322) #1E0 2012
OUTNOT W396.04
LD TR0
AND>S(322) #1F4 2013
OUTNOT W396.05
; rung 187
LD P_On
OUT TR0
AND>S(322) #1F4 2014
OUTNOT W396.06
LD TR0
AND>(320) #1E0 2015
OUTNOT W395.13
LD TR0
AND>(320) #1E0 2018
OUTNOT W395.14
; rung 188
LD P_On
AND<(310) #410 D80
AND>(320) #8190 D80
OUTNOT W396.07
; rung 189: ********** 主操作電源入処理 **********
LD 10.06
TIM 0511 #20
; rung 190: ********** ﾛﾎﾞｯﾄ操作電源 **********
LD P_On
OUT 2043.06
; rung 191: ********** 高機能ﾕﾆｯﾄ異常時処理 **********
LD 11.01
AND A402.06
FAL(006) 0 #FFFF

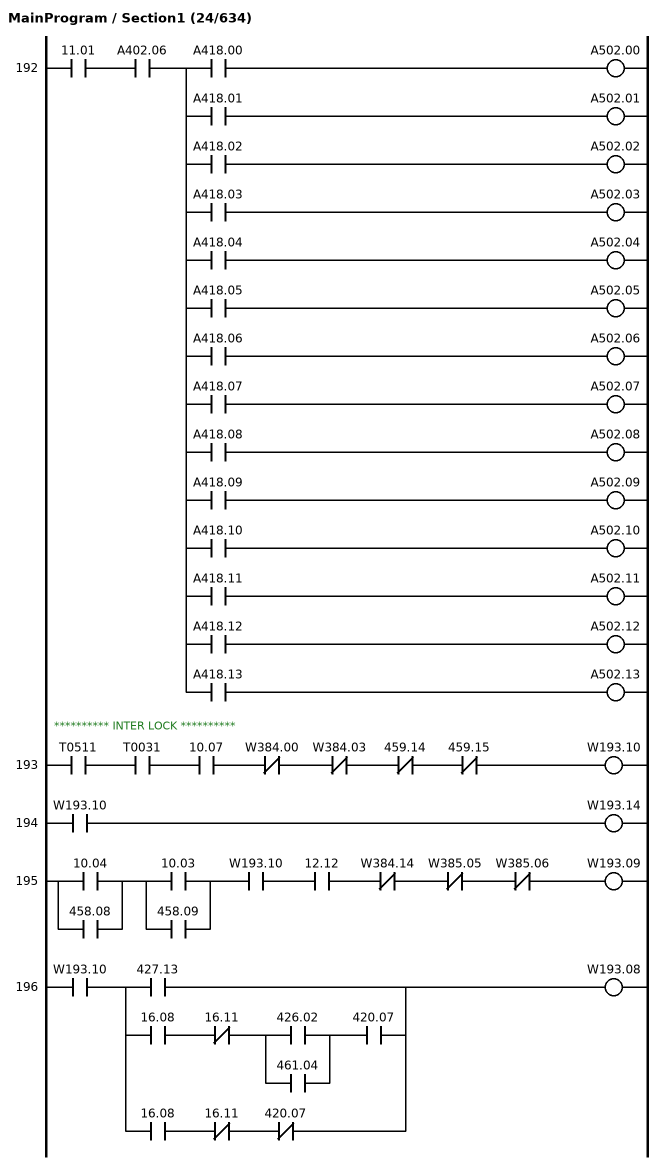
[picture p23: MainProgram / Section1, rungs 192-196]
; rung 192
LD 11.01
AND A402.06
OUT TR0
AND A418.00
OUT A502.00
LD TR0
AND A418.01
OUT A502.01
LD TR0
AND A418.02
OUT A502.02
LD TR0
AND A418.03
OUT A502.03
LD TR0
AND A418.04
OUT A502.04
LD TR0
AND A418.05
OUT A502.05
LD TR0
AND A418.06
OUT A502.06
LD TR0
AND A418.07
OUT A502.07
LD TR0
AND A418.08
OUT A502.08
LD TR0
AND A418.09
OUT A502.09
LD TR0
AND A418.10
OUT A502.10
LD TR0
AND A418.11
OUT A502.11
LD TR0
AND A418.12
OUT A502.12
LD TR0
AND A418.13
OUT A502.13
; rung 193: ********** INTER LOCK **********
LD T0511
AND T0031
AND 10.07
ANDNOT W384.00
ANDNOT W384.03
ANDNOT 459.14
ANDNOT 459.15
OUT W193.10
; rung 194
LD W193.10
OUT W193.14
; rung 195
LD 10.04
OR 458.08
LD 10.03
OR 458.09
ANDLD
AND W193.10
AND 12.12
ANDNOT W384.14
ANDNOT W385.05
ANDNOT W385.06
OUT W193.09
; rung 196
LD W193.10
LD 427.13
LD 16.08
ANDNOT 16.11
LD 426.02
OR 461.04
ANDLD
AND 420.07
ORLD
LD 16.08
ANDNOT 16.11
ANDNOT 420.07
ORLD
ANDLD
OUT W193.08

; rung 197
LD W193.10
AND T0020
ANDNOT H8.13
ANDNOT H8.14
OUT W193.15
OUT W174.13
OUT W193.07
OUT W193.12
OUT W193.11
; rung 198
LD W193.10
AND T0037
AND W165.04
OUT W174.15
; rung 199
LD W193.10
ANDNOT W385.05
ANDNOT W385.06
OUT W171.04
; rung 200
LD W193.10
AND T0036
OUT W193.13
; rung 201
LDNOT W384.00
ANDNOT W385.11
ANDNOT W385.12
ANDNOT W344.07
ANDNOT W385.05
ANDNOT W385.06
ANDNOT W385.07
OUTNOT W174.14
; rung 202
LDNOT T0020
ORNOT W193.15
OR W174.14
OR W191.04
OR W385.10
OR W344.02
OUT W175.08
; rung 203
LDNOT T0020
ORNOT W193.15
OR W174.14
OR W191.05
OR W385.13
OR W344.03
OUT W175.09

; rung 204: ----- 移送ｲﾝﾀｰﾛｯｸ -----
LD P_On
OUT TR0
AND>(320) #900 D712
MOV(021) #900 D712
LD TR0
AND>(320) #900 D713
MOV(021) #900 D713
; rung 205
LD W170.13
OUT TR0
AND>=(325) D282 D712
OUT W22.15
LD TR0
AND>=(325) D232 D713
OUT W23.15
; rung 206
LD W379.03
AND W378.04
ANDNOT W509.15
AND W170.13
OUT TR0
LD W48.06
OR W67.00
ANDLD
OUT W67.00
LD TR0
LD W48.07
OR W67.01
ANDLD
OUT W67.01
; rung 207
LD 11.01
OR W67.00
AND 2071.10
AND W170.13
ANDNOT W165.03
ANDNOT P_On
OUT W67.02
; rung 208
LD 11.01
OR W67.01
AND 2091.10
AND W170.13
ANDNOT W165.01
ANDNOT P_On
OUT W67.03
; rung 209
LD 457.06
AND W165.04
LD W22.14
OR W23.14
ANDNOT 2071.11
ANDNOT 2091.11
ORLD
AND W193.07
ANDNOT W385.12
ANDNOT W344.07
ANDNOT W385.05
ANDNOT W385.06
ANDNOT W385.07
AND 473.02
OUT W358.03  // 当止の為、DC台車前進中、油圧切れると待避位置切れる
; rung 210
LD W165.03
OR W67.02
OR W23.15
LD W22.14
AND W22.15
ORLD
LD 2110.10  // 位置決シリンダ齧り時反対方向へ操作可能
LD W22.13
AND W165.00
AND 16.01
ORLD
LD W22.14
AND W165.01
AND 16.00
ORLD
ANDLD
AND W358.03
AND W170.00
AND 16.14
AND W42.00
ANDNOT W385.10
AND 11.09
AND 420.15
OUT W176.07

; rung 211
LD W165.01
OR W67.03
OR W22.15
LD W23.14
AND W23.15
ORLD
LD 2130.10  // 位置決シリンダ齧り時反対方向へ操作可能
LD W23.13
AND W165.02
AND 16.03
ORLD
LD W23.14
AND W165.03
AND 16.02
ORLD
ANDLD
AND W358.03
AND W170.01
AND 16.15
AND W42.01
ANDNOT W385.13
AND 11.09
AND 420.15
OUT W306.07
; rung 212: ********** 段取り(特別仕様) **********
LD 16.08
AND T0511
OUT W374.12
; rung 213: ********** ｺﾝﾌﾟﾚｯｻ/ｴｱﾄﾞﾗｲﾔ装置処理 ********** / 豊田１号機 / ｺﾝﾌﾟﾚｯｻ起動SS入→ｴｱﾄﾞﾗｲﾔ起動→ｺﾝﾌﾟﾚｯｻ起動 / ｺﾝﾌﾟﾚｯｻ起動SS切→ｺﾝﾌﾟﾚｯｻ停止→ｴｱﾄﾞﾗｲﾔ停止
LD 17.13
AND T0511
ANDNOT W134.05  ; Kaeser BYPASS
OUT W301.07
; rung 214
LDNOT W301.07
TIM 0066 #30
AND T0066
DIFU(013) W301.09
; rung 215
LD W301.09
OR 22.15
ANDNOT T0067
TIM 0067 #10
OUT 22.15
; rung 216
LD W301.07
OR W301.08
AND T0511
ANDNOT W385.01
ANDNOT T0066
OUT W301.08
OUT 22.14
; rung 217
LD 22.14
AND 17.02
TIM 0065 #1800
; rung 218
LD T0065
ANDNOT 17.01
AND W301.07
OUT 14.04

; rung 219: ********** 左右冷却ｴｱ装置処理 ********** / ｺﾝﾌﾟﾚｯｻ運転信号がﾎﾟﾝﾌﾟﾓｰﾀ起動中の信号の為、一定圧に到達すると切れる。 / 今回ｲﾝﾀｰﾛｯｸ無し 00/03/06
LD 17.00
OR W134.05  ; Kaeser BYPASS
AND 17.08
AND 17.04
LD T0065
OR W134.05  ; Kaeser BYPASS
ANDLD
AND T0511
ANDNOT 2110.08
OUT 2103.08
; rung 220
LD 17.00
OR W134.05  ; Kaeser BYPASS
AND 17.09
AND 17.06
LD T0065
OR W134.05  ; Kaeser BYPASS
ANDLD
AND T0511
ANDNOT 2130.08
OUT 2123.08
AND P_Off
OUT W511.15
; rung 221
LD T0511
AND 11.01
OUT TR0
AND 2110.08
OUT 2103.10
LD TR0
AND 2130.08
OUT 2123.10
; rung 222: ********** 機械照明処理 **********
LD 11.12
OUT 2043.01
; rung 223: ********** 左右ｻｲｸﾙ調整ﾓﾆﾀ **********
LD W223.04
AND W193.05
@MOV(021) T144 D2000
@WSFT(016) D2000 D2003 D2007
@WSFT(016) D2000 D5000 D5099
; rung 224
LD P_On
AND 16.11
AND=(300) D2201 #3734
OUT W201.00
; rung 225
LD W201.00
LD>=(325) D2003 D3214
OR<=(315) D2003 D3215
ANDLD
OUT W201.01

; rung 226
LD W201.00
LD>=(325) D2003 D3216
OR<=(315) D2003 D3217
ANDLD
OUT W201.02
; rung 227
LD P_On
+B(404) D1214 D1215 D3214
CLC(041)
-B(414) D1214 D1215 D3215
; rung 228
LD P_On
+B(404) D1414 D1415 D3216
CLC(041)
-B(414) D1414 D1415 D3217
; rung 229
LD W223.00
AND W193.05
@MOV(021) #0 D2000
; rung 230
LD W183.04
OR W59.15
ANDNOT W223.00
ANDNOT 2100.12
AND W193.05
ANDNOT W189.10
OUT W59.15
; rung 231
LD W59.15
LD W223.04
TTIM(087) 0144 #9999

; rung 232
LD W225.01
AND W193.05
@MOV(021) T145 D2001
@WSFT(016) D2001 D2008 D2012
; rung 233
LD W224.13
AND W193.05
@MOV(021) #0 D2001
; rung 234
LD W313.04
OR W59.14
ANDNOT W224.13
ANDNOT 2120.12
AND W193.05
ANDNOT W319.10
OUT W59.14
; rung 235
LD W59.14
LD W225.01
TTIM(087) 0145 #9999
; rung 236
LD W59.13
TIM 0146 #20
; rung 237
LD T0146
@BSET(071) #0 D2003 D2012
; rung 238
LD P_On
AND 2100.12
AND 16.11
LD P_On
AND 473.07
TTIM(087) 0175 #9999

; rung 239
LD P_On
LD 16.11
OR 16.10
ANDLD
AND W223.00
@MOV(021) T175 D2040
@WSFT(016) D2040 D2041 D2045
; rung 240
LD P_On
AND 2120.12
AND 16.11
LD P_On
AND 473.08
TTIM(087) 0176 #9999
; rung 241
LD P_On
LD 16.11
OR 16.10
ANDLD
AND W224.13
@MOV(021) T176 D2051
@WSFT(016) D2051 D2046 D2050
; rung 242
LD W69.00
TIM 0177 #20
; rung 243
LD T0177
@BSET(071) #0 D2041 D2050
; rung 244: ********** ｺｱﾛｯｸ/ｱﾝﾛｯｸ処理 **********
LD 456.04
OR 456.06
LD 456.05
OR 456.07
KEEP(011) H99.02
; rung 245
LDNOT H99.02
AND T0511
OUT 2042.09

; rung 246
LD H99.02
AND T0511
ANDNOT P_On
OUT 2046.08
; rung 247
LD 2048.00
AND 2048.01
OUT W187.11
; rung 248
LD 2048.02
AND 2048.03
OUT W187.12

; rung 249: ********** ｸﾞﾘｰｽ給油処理 **********
LD W193.10
OR T0511
OUT TR0
LD 2073.00
OR 22.00
ANDLD
ANDNOT C0110
OUT 22.00
AND P_1min
LD TR0
ANDNOT 22.00
CNT 0110 #31
LD TR0
LD 2073.01
OR 22.01
ANDLD
ANDNOT C0111
OUT 22.01
AND P_1min
LD TR0
ANDNOT 22.01
CNT 0111 #31
LD TR0
LD 2073.04
OR 22.02
ANDLD
ANDNOT C0112
OUT 22.02
AND P_1min
LD TR0
ANDNOT 22.02
CNT 0112 #31
LD TR0
LD 2073.05
OR 22.03
ANDLD
ANDNOT C0113
OUT 22.03
AND P_1min
LD TR0
ANDNOT 22.03
CNT 0113 #31
LD TR0
LD 2093.00
OR 22.04
ANDLD
ANDNOT C0114
OUT 22.04
AND P_1min
LD TR0
ANDNOT 22.04
CNT 0114 #31
LD TR0
LD 2093.01
OR 22.05
ANDLD
ANDNOT C0115
OUT 22.05
AND P_1min
LD TR0
ANDNOT 22.05
CNT 0115 #31
LD TR0
LD 2093.04
OR 22.06
ANDLD
ANDNOT C0116
OUT 22.06
AND P_1min
LD TR0
ANDNOT 22.06
CNT 0116 #31
LD TR0
LD 2093.05
OR 22.07
ANDLD
ANDNOT C0117
OUT 22.07
AND P_1min
LD TR0
ANDNOT 22.07
CNT 0117 #31

; rung 250: ********** 主油圧ユニット処理 **********
LD 10.08
OR W175.10
AND W193.09
ANDNOT W384.02
AND 10.09
ANDNOT T0038
OUT W175.10
TIM 0038 #50
; rung 251
LD W193.09
ANDNOT W384.02
AND 10.09
OUT TR0
LD W175.10
ANDNOT W394.01
LD 13.08
AND 12.10
ORLD
ANDLD
OUT 13.08
LD TR0
LD W175.10
ANDNOT W394.01
LD 13.09
AND 12.11
ORLD
ANDLD
OUT 13.09
LD TR0
LD W175.10
ANDNOT W394.01
LD 22.12
AND 11.05
ORLD
ANDLD
OUT 22.12
LD TR0
LD W175.10
ANDNOT W394.01
LD 22.13
AND 11.06
ORLD
ANDLD
OUT 22.13
; rung 252
LD 13.08
AND 13.09
AND 22.12
AND 22.13
AND 12.10
AND 12.11
AND 11.05
AND 11.06
AND W193.09
TIM 0020 #30
; rung 253: ********** 肉調用ﾎﾟﾝﾌﾟ処理 **********
LD 10.10
ANDNOT W394.01
LD 2043.00
AND 2048.04
ORLD
AND W193.08
AND 10.11
ANDNOT W384.12
OUT 2043.00
TIM 0454 #50
AND T0454
OUT 2042.12
OUT 2042.13
; rung 254
LD 2043.00
AND 2048.04
AND W193.08
TIM 0036 #30

; rung 255: ********** ｶｯﾀｰ用ﾎﾟﾝﾌﾟ処理 **********
LD W193.10
TIM 0037 #30
; rung 256: ********** ｻｰｼﾞﾀﾝｸ排出ﾎﾟﾝﾌﾟ&補給処理 ********** / 油面上限でﾀﾝｸ排出ﾓｰﾀ起動／油面下限でﾀﾝｸ給油電磁弁ON / ---------- 左成形機 ----------
LDNOT W348.00
AND 2110.11
TIM 0162 #10
; rung 257
LDNOT W348.00
AND 2110.12
TIM 0163 #10
AND T0020
TIM 0171 #600
; rung 258
LD T0162
OR W343.03
ANDNOT T0163
ANDNOT T0187
ANDNOT W343.01
OUT W343.03
LDNOT W223.04
ANDNOT W223.03
ORNOT T0021
ANDLD
OUT 14.05
LD W67.05
TTIM(087) 0187 #1800
; rung 259
LD T0187
OR T0163
OUT W67.05
; rung 260
LD 13.03
AND W343.03
OUT W350.00
; rung 261
LDNOT W348.00
AND W350.00
AND 2110.11
TIM 0250 #250
AND T0250
OUT W350.01

; rung 262
LD T0163
OR W343.05
AND T0020
ANDNOT T0162
LD W311.14
AND W224.13
ORNOT T0021
ANDLD
ANDNOT T1108
ANDNOT W343.03
OUT W343.05
OUT 2103.13
; rung 263
LD W343.05
TIM 1108 D1108
; rung 264: ---------- 右成形機 ----------
LDNOT W348.00
AND 2130.11
TIM 0164 #10
; rung 265
LDNOT W348.00
AND 2130.12
TIM 0165 #10
AND T0020
TIM 0173 #600
; rung 266
LD T0164
OR W343.04
ANDNOT T0165
ANDNOT T0188
ANDNOT W343.02
OUT W343.04
LDNOT W225.00
ANDNOT W225.01
ORNOT T0021
ANDLD
OUT 14.06
LD W67.06
TTIM(087) 0188 #1800
; rung 267
LD T0188
OR T0165
OUT W67.06
; rung 268
LD 13.03
AND W343.04
OUT W350.02
; rung 269
LDNOT W348.00
AND W350.02
AND 2130.11
TIM 0251 #250
AND T0251
OUT W350.03

; rung 270
LD T0165
OR W343.06
AND T0020
ANDNOT T0164
LD W181.14
AND W223.00
ORNOT T0021
ANDLD
ANDNOT T1308
ANDNOT W343.04
OUT W343.06
OUT 2123.13
; rung 271
LD W343.06
TIM 1308 D1308
; rung 272: **********ﾛﾎﾞｯﾄｲﾝﾀｰﾛｯｸ信号/ｲﾝｻｰﾄﾛﾎﾞｯﾄ************
LD H1.06
ANDNOT P_On
OUT W43.15
; rung 273
LD 473.02
OR W43.15
OUT W43.02
; rung 274
LD 473.03
OR W43.15
OUT W43.03
; rung 275
LD 473.04
OR W43.15
OUT W43.04
; rung 276: ********** ﾛﾎﾞｯﾄｲﾝﾀｰﾛｯｸ信号 ********** / ---------- 取出ﾛﾎﾞｯﾄ ----------
LD H1.06
OUT W42.15
; rung 277
LD 25.03
AND 25.14
OUT W42.00
; rung 278
LD 25.07
AND 25.15
OUT W42.01
; rung 279
LD 25.04
OUT W42.02
; rung 280
LD 25.08
OUT W42.03

; rung 281
LD 25.05
OR W42.15
OUT W42.04
; rung 282
LD 25.09
OR W42.15
OUT W42.05
; rung 283: **********ｲﾝｻｰﾄﾛﾎﾞｯﾄ信号処理(左成形機)***********
LDNOT W48.01
ANDNOT H9.08
ANDNOT H9.09
LDNOT 2108.06
AND H9.08
ORLD
LDNOT 2109.02
AND H9.09
ORLD
OR W223.04
LDNOT W193.02
ORNOT 473.02
ANDLD
ANDNOT 405.01
AND 2110.09
AND W165.01
AND W165.03
AND W193.05
AND W170.00
ANDNOT W358.05
AND H1.01
ANDNOT H1.06
OUT W40.06
; rung 284
LD 473.05
OR 473.09
OR W48.01
ANDNOT W181.12
AND T0021
ANDNOT H9.08
ANDNOT H9.09
OUT W48.01
; rung 285
LD 2108.07
ORNOT H9.08
OR W223.04
OR W40.00
AND W40.06
ANDNOT W41.00
OUT W40.00
OUT 409.00
; rung 286
LDNOT W43.02
OR W40.01
LD H99.03
LDNOT W97.09
LD W97.09
AND W223.00
ORLD
AND W161.13
ORLD
ANDLD
AND W40.00
OUT W40.01
OUT 409.02
; rung 287
LD 2108.06
ORNOT H9.08
LD 2109.02
ORNOT H9.09
ANDLD
AND T0511
OUT W40.03

; rung 288
LD 2108.06
ORNOT H9.08
AND T0511
OUT 409.04
; rung 289
LD 2109.02
ORNOT H9.09
AND T0511
OUT 409.06
; rung 290
LD W42.04
OR W39.00
AND W165.01
AND T0021
OUT W39.00
; rung 291
LDNOT H1.01
OR H1.06
LD 2130.09
OR W358.04
ANDLD
ANDNOT W193.02
AND W197.02
AND W193.06
LD 473.07
AND W40.03
LD W197.02
AND W193.06
AND W39.00
AND 405.02
ANDNOT 473.07
AND W170.00
ORLD
OR W40.05
AND W43.03
AND W43.02
AND H1.01
ORLD
AND W165.01
AND T0021
OUT W40.05
; rung 292
LD W40.03
AND W193.05
OR W40.05
LD 2108.07
ORNOT H9.08
LD 2109.03
ORNOT H9.09
ANDLD
ORNOT H1.01
KEEP(011) H99.05
; rung 293: **********ｲﾝｻｰﾄﾛﾎﾞｯﾄ信号処理(右成形機)***********
LDNOT W48.00
ANDNOT H9.10
ANDNOT H9.11
LDNOT 2128.06
AND H9.10
ORLD
LDNOT 2129.02
AND H9.11
ORLD
OR W225.01
LDNOT W193.02
ORNOT 473.02
ANDLD
LD W320.00
OR 2130.09
ANDLD
LD W223.04
OR W358.05
ANDLD
ANDNOT 405.00
AND W165.01
AND W165.03
AND W193.05
ANDNOT W358.04
AND W170.01
AND H1.01
ANDNOT H1.06
OUT W41.06

; rung 294
LD 473.06
OR 473.10
OR W48.00
ANDNOT W311.12
AND T0021
ANDNOT H9.10
ANDNOT H9.11
OUT W48.00
; rung 295
LD 2128.07
ORNOT H9.10
OR W225.01
OR W41.00
AND W41.06
ANDNOT W40.00
OUT W41.00
OUT 409.01
; rung 296
LDNOT W43.02
OR W41.01
LD H99.04
LDNOT W97.09
AND W223.04
LD W97.09
AND W224.13
ORLD
OR W358.05
AND W161.12
ORLD
ANDLD
AND W41.00
OUT W41.01
OUT 409.03
; rung 297
LD 2128.06
ORNOT H9.10
LD 2129.02
ORNOT H9.11
ANDLD
AND T0511
OUT W41.03
; rung 298
LD 2128.06
ORNOT H9.10
AND T0511
OUT 409.05
; rung 299
LD 2129.02
ORNOT H9.11
AND T0511
OUT 409.07
; rung 300
LDNOT W43.02
OR W40.01
LD H99.03
LD W223.00
AND W161.13
ORLD
ANDLD
AND W40.00
OUT 409.08

; rung 301
LDNOT W43.02
OR W41.01
LD H99.04
LD W224.13
OR W358.05
AND W161.12
ORLD
ANDLD
AND W41.00
OUT 409.09
; rung 302
LD 16.04
OUT 409.10
; rung 303
LD 16.06
OUT 409.11
; rung 304
LD H1.01
AND T0511
OUT 409.15
; rung 305
LD W42.05
OR W39.01
AND W165.03
AND T0021
OUT W39.01
; rung 306
LDNOT H1.01
OR H1.06
LD W223.04
AND 2110.09
OR W358.05
ANDLD
ANDNOT W193.02
AND W194.02
AND W191.11
LD 473.08
AND W41.03
LD W194.02
AND W191.11
AND W39.01
AND 405.03
ANDNOT 473.08
AND W170.01
ORLD
OR W41.05
AND W43.04
AND W43.02
AND H1.01
ORLD
AND W165.03
AND T0021
OUT W41.05
; rung 307
LD W41.03
ANDNOT W193.05
OR W41.05
LD 2128.07
ORNOT H9.10
LD 2129.03
ORNOT H9.11
ANDLD
ORNOT H1.01
KEEP(011) H99.06

; rung 308: ********** 取出ﾛﾎﾞｯﾄ信号処理 **********
LD 17.12
OR W59.09
AND W170.09
ANDNOT 26.01
AND H8.15
OUT W59.09
; rung 309
LD T0021
OUT TR0
LD T0546
OR W68.12
ANDLD
ANDNOT W40.11
OUT W68.12
LD TR0
LD T0547
OR W68.13
ANDLD
ANDNOT W41.11
OUT W68.13
LD TR0
LD W68.12
AND W40.08
LD W68.13
AND W41.08
ORLD
OR W68.14
ANDLD
ANDNOT 26.01
OUT W68.14
; rung 310
LD 16.11
OR 16.09
OR W59.09
OR W68.14
LD 484.04
ORNOT 484.05
ORNOT 486.15
AND P_Off  // ﾊﾞﾘ切ﾛﾎﾞｯﾄCL無くなるので遮断
ORLD
OUT 405.04
; rung 311: ---------- 左成形機取出処理 ----------
LD W223.04
OR W40.07
LD W177.11
LD T0534
AND W165.01
ORLD
ORNOT H7.09
ANDLD
LD W165.03
OR H1.00
ANDLD
AND W165.01
AND T0021
ANDNOT H1.06
AND H8.15
OUT W40.07
; rung 312
LD 2103.03
AND T0021
TIM 0534 #50

; rung 313
LD W225.01
OR W193.02
OR W358.04
AND W170.00
AND W40.07
ANDNOT H99.03
ANDNOT W41.08
OUT W40.08
TIM 0023 D220
; rung 314
LD T0023
OUT 405.00
; rung 315
LD W42.04
OR W40.09
AND W42.02
ANDNOT W42.00
AND W40.07
ANDNOT W40.10
OUT W40.09
; rung 316
LD W40.07
ORNOT T0021
AND W190.00
OUT W40.10
OUT 405.02
; rung 317
LD 25.06
OR W40.15
ORNOT H8.15
OR H1.06
OUT W40.11
; rung 318
LD W40.11
LD W165.00
AND T0021
ORNOT T0021
KEEP(011) H99.03
; rung 319: ---------- 右成形機取出処理 ----------
LD W225.01
OR W41.07
LD W177.13
LD T0539
AND W165.03
ORLD
ORNOT H7.11
ANDLD
LD W165.01
OR H1.00
ANDLD
AND W165.03
AND T0021
ANDNOT H1.06
AND H8.15
OUT W41.07
; rung 320
LD 2123.03
AND T0021
TIM 0539 #50

; rung 321
LD W223.04
OR W193.02
OR W358.05
AND W170.01
AND W41.07
ANDNOT H99.04
ANDNOT W40.08
OUT W41.08
TIM 0025 D218
; rung 322
LD T0025
OUT 405.01
; rung 323
LD W42.05
OR W41.09
AND W42.03
ANDNOT W42.01
AND W41.07
ANDNOT W41.10
OUT W41.09
; rung 324
LD W41.07
ORNOT T0021
AND W320.00
OUT W41.10
OUT 405.03
; rung 325
LD 25.10
OR W41.15
ORNOT H8.15
OR H1.06
OUT W41.11
; rung 326
LD W41.11
LD W165.02
AND T0021
ORNOT T0021
KEEP(011) H99.04
; rung 327: ********** 取出ﾛﾎﾞｯﾄﾌﾟﾛｸﾞﾗﾑ ********** / 通常PLC別ﾌﾟﾛｸﾞﾗﾑ / ----- 取出ﾛﾎﾞｯﾄ信号から入力 -----
LD 24.06
OUT TR0
AND 24.01
AND 24.00
OUT W472.14
OUT 411.01
LD TR0
OUT 27.10
; rung 328
LD 20.00
OUT 411.02

; rung 329
LD 20.01
OUT 411.03
; rung 330
LD 20.02
OUT 411.04
; rung 331
LD 20.03
OUT 411.05
; rung 332
LD 20.06
OUT 411.06
; rung 333
LD 20.07
OUT 411.07
; rung 334
LD W344.12
OR W345.10
OR W345.11
OR W345.12
OR W345.13
OUT 411.00
; rung 335: ----- 取出ﾛﾎﾞｯﾄへ出力 -----
LD 405.00
OR 405.01
DIFU(013) W501.02
; rung 336
LD 405.00
OUT 28.12
; rung 337
LD 405.01
OUT 29.00
; rung 338
LD 405.02
OUT 28.13
; rung 339
LD 405.03
OUT 29.01

; rung 340
LD 20.05
OR T0521
ANDNOT T0522
TIM 0521 #50
AND T0521
TIM 0522 #10
; rung 341
LD 405.04
OR T0521
OUT 29.08
; rung 342
LD 405.06
OUT 28.08
; rung 343
LD 405.07
OUT 28.09
; rung 344
LD P_On
OUT 27.02
; rung 345
LD 401.10
DIFD(014) W501.04
; rung 346
LD W501.04
OR W501.05
AND 24.02
OUT W501.05
OUT 29.09
; rung 347
LD 406.02
OUT 29.10
; rung 348
LD 493.00
AND P_Off  // ﾊﾞﾘ切ﾛﾎﾞｯﾄCL無くなるので遮断
OUT 21.04
; rung 349
LD 493.01
AND P_Off  // ﾊﾞﾘ切ﾛﾎﾞｯﾄCL無くなるので遮断
OUT 21.01
; rung 350
LD 493.02
AND P_Off  // ﾊﾞﾘ切ﾛﾎﾞｯﾄCL無くなるので遮断
OUT 21.00
; rung 351
LD 493.03
AND P_Off  // ﾊﾞﾘ切ﾛﾎﾞｯﾄCL無くなるので遮断
OUT 21.03

; rung 352
LD 493.04
AND P_Off  // ﾊﾞﾘ切ﾛﾎﾞｯﾄCL無くなるので遮断
OUT 21.02
; rung 353: ---------- 取出ﾛﾎﾞｯﾄ起動処理 ----------
LD T0511
AND 26.10
OUT TR0
ANDNOT W384.00
ANDNOT W384.03
OUT W501.08
LD TR0
OUT 27.13
; rung 354: ----- ﾛﾎﾞｯﾄ操作電源 -----
LD 26.08
OR 29.13
AND 26.09
LD W501.08
OR T0511
ANDLD
OUT 29.13
OUT 27.12
; rung 355: ----- ｻｰﾎﾞon処理 -----
LD 26.12
OR W501.07
ANDNOT 10.02
OUT W501.07
; rung 356
LD W501.07
LD 26.11
OR 29.14
ANDNOT W345.12
ORLD
LD 26.14
OR P_On
ANDLD
AND H8.15
AND 29.13
ANDNOT W385.07
ANDNOT W345.11
OUT TR0
OUT 29.14
TIM 0512 #10
ANDNOT T0512
OUT W501.06
LD TR0
LD P_1s
OR 24.01
ANDLD
OUT 27.14
OUT 27.15

; rung 357: ---------- 取出ﾛﾎﾞｯﾄﾊｰﾄﾞ信号処理 ---------- / -----ﾌﾟﾛｸﾞﾗﾑＮo.判別 -----
LD P_On
MOV(021) #0 D298
MOV(021) D87 D298
BIN(023) D298 D298
MOV(021) D298 W500
; rung 358: ---------- PNS起動回路 ----------
LD T0511
AND H8.15
AND 29.13
AND 29.14
AND 24.00
AND 24.01
ANDNOT 24.05
ANDNOT 24.02
AND T0513
OUT W501.00
; rung 359
LD 24.06
TIM 0514 #5
OUT 29.12
DIFU(013) W501.03
; rung 360
LD W501.02
OR W501.01
LD 400.03
OR 406.02
ANDLD
AND W501.00
AND T0514
ANDNOT W345.10
OUT W501.01
TIM 0515 #5
TIM 0516 #8
; rung 361
LD W501.01
ANDNOT T0515
OUT 27.07

; rung 362
LD T0516
OUT TR0
AND W500.00
OUT 28.00
LD TR0
AND W500.01
OUT 28.01
LD TR0
AND W500.02
OUT 28.02
LD TR0
AND W500.03
OUT 28.03
LD TR0
AND W500.04
OUT 28.04
LD TR0
AND W500.05
OUT 28.05
LD TR0
AND W500.06
OUT 28.06
LD TR0
AND W500.07
OUT 28.07
LD TR0
TIM 0517 #3
@MOV(021) D298 D301
; rung 363
LD P_On
MOV(021) #0 D302
XFRB(062) #80A 24 D302
; rung 364
LD P_On
AND=(300) D301 D302
AND>(320) D302 #0
OUT W501.09
; rung 365
LD T0517
ANDNOT 24.09
ANDNOT 24.03
ANDNOT 24.02
OUT 27.00
TIM 0518 #3
; rung 366: ---------- 瞬時停止回路 ----------(通常ON) / ｿﾌﾄによる非常停止処理(ｻｰﾎﾞOFF) / ﾛﾎﾞｯﾄ即停止
LD T0511
AND 29.13
ANDNOT W384.00
ANDNOT W345.11
OUT 27.04

; rung 367: ---------- 一時停止回路 ----------(通常ON) / 本信号OFFで一時停止、ｽﾀｰﾄ信号立下で動作再開
LD 400.03
OR 406.02
OR 24.07
ANDNOT W345.10
ANDNOT W502.01
OUT 27.05
TIM 0513 #5
; rung 368: ---------- 安全速度回路 ----------(通常ON)
LDNOT W345.12
OUT 27.06
; rung 369: ---------- 動作許可回路 ----------(通常ON) / 本信号OFF時、ﾛﾎﾞｯﾄ動作、起動が禁止となる。又、動作中に信号OFFになると一時停止となる。
LD P_On
OUT 27.11
; rung 370: ---------- 通常起動回路 ----------
LD T0514
AND T0518
AND W501.09
OR 27.01
ANDNOT W502.01
AND W501.00
ANDNOT W345.10
OUT TR0
ANDNOT T0519
OUT 27.01
LD TR0
TIM 0519 #5
; rung 371: ---------- 再起動回路 ---------- / 一時停止したﾌﾟﾛｸﾞﾗﾑを再起動する / 本信号立下りで再動作開始
LD W502.02
OR 27.09
ANDNOT W502.01
AND W501.00
AND 24.03
ANDNOT W345.10
ANDNOT T0514
OUT TR0
ANDNOT T0520
OUT 27.09
LD TR0
TIM 0520 #5
; rung 372: ---------- ｱﾗｰﾑ解除回路 ---------- / ｱﾗｰﾑ解除する。 / 本信号は立下りで機能
LD 400.00
OR W502.03
OR W501.06
OUT 27.08

; rung 373: ----- 左金型車種No.処理追加 by AHT -----
LD P_On
OUT TR0
ANDNOT 2034.08
ANDNOT 2034.09
ANDNOT 2034.10
ANDNOT 2034.12
MOV(021) #0 D11
LD TR0
AND 2034.08
ANDNOT 2034.09
ANDNOT 2034.10
ANDNOT 2034.12
MOV(021) #1 D11
LD TR0
ANDNOT 2034.08
AND 2034.09
ANDNOT 2034.10
ANDNOT 2034.12
MOV(021) #2 D11
LD TR0
AND 2034.08
AND 2034.09
ANDNOT 2034.10
ANDNOT 2034.12
MOV(021) #3 D11
; rung 374
LD P_On
OUT TR0
ANDNOT 2034.08
ANDNOT 2034.09
AND 2034.10
ANDNOT 2034.12
MOV(021) #4 D11
LD TR0
AND 2034.08
ANDNOT 2034.09
AND 2034.10
ANDNOT 2034.12
MOV(021) #5 D11
LD TR0
ANDNOT 2034.08
AND 2034.09
AND 2034.10
ANDNOT 2034.12
MOV(021) #6 D11
LD TR0
AND 2034.08
AND 2034.09
AND 2034.10
ANDNOT 2034.12
MOV(021) #7 D11
; rung 375
LD P_On
OUT TR0
ANDNOT 2034.08
ANDNOT 2034.09
ANDNOT 2034.10
AND 2034.12
MOV(021) #8 D11
LD TR0
AND 2034.08
ANDNOT 2034.09
ANDNOT 2034.10
AND 2034.12
MOV(021) #9 D11
LD TR0
ANDNOT 2034.08
AND 2034.09
ANDNOT 2034.10
AND 2034.12
MOV(021) #10 D11
LD TR0
AND 2034.08
AND 2034.09
ANDNOT 2034.10
AND 2034.12
MOV(021) #11 D11

; rung 376: ----- 右金型車種No.処理追加 by AHT -----
LD P_On
OUT TR0
ANDNOT 2036.08
ANDNOT 2036.09
ANDNOT 2036.10
ANDNOT 2036.12
MOV(021) #0 D12
LD TR0
AND 2036.08
ANDNOT 2036.09
ANDNOT 2036.10
ANDNOT 2036.12
MOV(021) #1 D12
LD TR0
ANDNOT 2036.08
AND 2036.09
ANDNOT 2036.10
ANDNOT 2036.12
MOV(021) #2 D12
LD TR0
AND 2036.08
AND 2036.09
ANDNOT 2036.10
ANDNOT 2036.12
MOV(021) #3 D12
; rung 377
LD P_On
OUT TR0
ANDNOT 2036.08
ANDNOT 2036.09
AND 2036.10
ANDNOT 2036.12
MOV(021) #4 D12
LD TR0
AND 2036.08
ANDNOT 2036.09
AND 2036.10
ANDNOT 2036.12
MOV(021) #5 D12
LD TR0
ANDNOT 2036.08
AND 2036.09
AND 2036.10
ANDNOT 2036.12
MOV(021) #6 D12
LD TR0
AND 2036.08
AND 2036.09
AND 2036.10
ANDNOT 2036.12
MOV(021) #7 D12
; rung 378
LD P_On
OUT TR0
ANDNOT 2036.08
ANDNOT 2036.09
ANDNOT 2036.10
AND 2036.12
MOV(021) #8 D12
LD TR0
AND 2036.08
ANDNOT 2036.09
ANDNOT 2036.10
AND 2036.12
MOV(021) #9 D12
LD TR0
ANDNOT 2036.08
AND 2036.09
ANDNOT 2036.10
AND 2036.12
MOV(021) #10 D12
LD TR0
AND 2036.08
AND 2036.09
ANDNOT 2036.10
AND 2036.12
MOV(021) #11 D12

; rung 379: ********** 原位置 **********
LD W193.06
ORNOT H1.05
LD W193.06
AND 2110.09
OR P_On
ANDLD
LD W190.05
LD T0021
ANDNOT W193.02
ORLD
ANDLD
LD 2108.07
ORNOT H9.08
ANDLD
LD 2109.03
ORNOT H9.09
ANDLD
AND W190.11
AND W165.01
AND W223.00
OUT W190.00
; rung 380
LD W191.11
ORNOT H1.05
LD W191.11
AND 2130.09
OR P_On
ANDLD
LD W190.06
LD T0021
ANDNOT W193.02
ORLD
ANDLD
LD 2128.07
ORNOT H9.10
ANDLD
LD 2129.03
ORNOT H9.11
ANDLD
AND W190.12
AND W165.03
AND W224.13
OUT W320.00
; rung 381
LD 473.02
AND W190.00
OR T0093
AND W193.02
AND T0022
TIM 0093 #0
; rung 382
LD 473.02
AND W320.00
OR T0094
AND W193.02
AND T0022
TIM 0094 #0
; rung 383: ********** 自動運転処理 **********
LD W161.05
AND T0511
OUT W190.09
; rung 384
LD T0036
OR W193.01
AND T0037
AND T0020
OUT W190.13
; rung 385
LDNOT W384.00
OUT W190.15
; rung 386
LD T0511
OUT W191.00
; rung 387
LDNOT W384.03
AND T0511
OUT W191.01
; rung 388
LDNOT 427.10
AND T0511
OUT W191.10
; rung 389
LD 2054.01
AND T0511
OUT W191.12

; rung 390
LDNOT 427.11
AND T0511
OUT W191.13
; rung 391
LDNOT 427.12
AND T0511
OUT W191.14
; rung 392
LDNOT W385.09
AND T0511
OUT W191.15
; rung 393
LDNOT W385.11
AND T0511
OUT W192.01
; rung 394
LDNOT W385.12
AND T0511
OUT W192.02
; rung 395
LDNOT W344.07
AND T0511
OUT W190.14
; rung 396
LDNOT W385.10
AND T0511
OUT W192.00
; rung 397
LDNOT W385.13
AND T0511
OUT W192.03
; rung 398
LDNOT W344.02
AND T0511
OUT W190.07
; rung 399
LDNOT W344.03
AND T0511
OUT W190.08
; rung 400
LDNOT W384.07
AND T0511
OUT W192.04
; rung 401
LDNOT W384.08
AND T0511
OUT W192.05
; rung 402
LDNOT W191.04
AND T0511
OUT W191.02
; rung 403
LDNOT W191.08
AND T0511
OUT W191.06

; rung 404
LDNOT H2.00
ANDNOT H2.01
ANDNOT H2.04
ANDNOT H2.08
ANDNOT H2.09
ANDNOT H2.12
ANDNOT H2.13
ANDNOT H5.00
ANDNOT H5.01
OUT W192.08
; rung 405
LDNOT W192.08
AND T0511
OUT W192.06
; rung 406
LDNOT W192.12
ANDNOT W192.13
AND T0511
ANDNOT 457.11
ANDNOT 457.12
OUT W192.10
; rung 407
LD W193.06
AND T0511
OUT W177.10
; rung 408
LD 2110.09
AND T0511
OUT W177.11
; rung 409
LDNOT W173.08
OUT W39.12
; rung 410
LDNOT W191.05
AND T0511
OUT W191.03
; rung 411
LDNOT W191.09
AND T0511
OUT W191.07
; rung 412
LDNOT H2.02
ANDNOT H2.03
ANDNOT H2.06
ANDNOT H2.10
ANDNOT H2.11
ANDNOT H2.14
ANDNOT H2.15
ANDNOT H5.02
ANDNOT H5.03
OUT W192.09
; rung 413
LDNOT W192.09
AND T0511
OUT W192.07
; rung 414
LDNOT W192.14
ANDNOT W192.15
AND T0511
ANDNOT 457.13
ANDNOT 457.14
OUT W192.11
; rung 415
LD W191.11
AND T0511
OUT W177.12
; rung 416
LD 2130.09
AND T0511
OUT W177.13
; rung 417
LDNOT W173.09
OUT W39.13

; rung 418
LDNOT H8.14
OUT W49.14
; rung 419
LDNOT H8.13
OUT W49.15
; rung 420
LD W42.00
AND W42.01
AND 473.02
AND 16.14
AND 16.15
AND 11.09
OUT W49.13
; rung 421
LD 17.00
ANDNOT 17.01
OR W134.05  ; Kaeser BYPASS
OUT W175.13
; rung 422
LD T0065
ANDNOT 17.03
OR W134.05  ; Kaeser BYPASS
OUT W175.14
; rung 423
LD W174.09
LDNOT 2130.07
ANDNOT W511.15
ORLD
AND P_On
OUT W174.09
; rung 424
LD W175.14
OUT TR0
LD 2110.07
OR H5.09
ANDLD
TIM 0550 #30
AND T0550
OUT W175.06
LD TR0
LD 2130.07
OR W511.15
OR H5.11
ANDLD
TIM 0551 #30
AND T0551
OUT W175.07
; rung 425
LDNOT P_On
OR W175.06
AND 2110.07
ANDNOT W163.12
AND T0065
AND 17.04
OR H7.08
OUT W52.13

; rung 426
LDNOT P_On
OR W175.07
LD 2130.07
OR W511.15
ANDLD
ANDNOT W163.13
AND T0065
AND 17.06
OR H7.10
OUT W52.12
; rung 427
LDNOT 428.07
ANDNOT 428.09
OUT W39.10
; rung 428
LDNOT 429.07
ANDNOT 429.09
OUT W39.11
; rung 429
LDNOT W345.10
ANDNOT W345.11
OUT W39.14
; rung 430
LDNOT 470.05
AND 474.03
OUT W39.15
; rung 431
LD 458.08
OUT W39.08
; rung 432
LD 458.09
OUT W39.09
; rung 433
LD=(300) D81 D11
OUT W52.00
; rung 434
LD=(300) D82 D12
OUT W52.01
; rung 435: ----- 自動開始条件成立確認 -----
LD W472.14
OR H1.06
AND 473.14
LD 474.08
ORNOT H1.01
ANDLD
AND W190.13
AND 457.06
AND W191.00
AND W49.14
AND W49.15
AND W49.13
AND W39.15
OUT W358.06
; rung 436
LD 2048.08
ORNOT H1.00
AND W42.00
AND W42.01
AND 473.02
AND W165.03
AND W165.01
AND W191.12
AND W165.04
AND 2055.00
AND 2055.12
AND 420.15
OUT W358.07

; rung 437
LD W190.15
AND W191.01
AND W191.10
AND W191.13
AND W191.14
AND W191.15
AND W192.01
AND W192.02
AND W190.14
AND W192.04
AND W192.05
AND 458.08
AND 458.09
OUT W360.11
; rung 438
LD 456.12
LD H1.04
ANDNOT H1.00
ORLD
LD 456.13
LDNOT H1.04
ANDNOT H1.00
ORLD
ANDLD
AND W190.09
AND 427.13
AND 421.03
AND 460.00
OUT W358.08
; rung 439
LD W177.11
ORNOT H7.09
LD 2108.07
ORNOT H9.08
ANDLD
LD 2109.03
ORNOT H9.09
ANDLD
LD W177.10
ORNOT H1.01
ANDLD
AND W190.11
AND W190.05
AND W223.00
AND W191.02
AND W191.06
AND W192.06
AND W192.00
AND W190.07
AND W192.10
AND W52.13
AND W72.00
AND W164.15
AND W52.00
OUT W358.09
; rung 440
LD 2108.11
AND 2108.15
AND 2035.03
AND 2035.05
OUT W72.00
; rung 441
LD P_Off
LD W177.11
AND 2108.07
AND 2109.03
AND W190.11
AND W190.05
AND W197.01
AND W72.00
AND W164.15
ORLD
AND W165.01
OUT 413.00
; rung 442
LD W177.13
ORNOT H7.11
LD 2128.07
ORNOT H9.10
ANDLD
LD 2129.03
ORNOT H9.11
ANDLD
LD W177.12
ORNOT H1.01
ANDLD
AND W190.12
AND W190.06
AND W224.13
AND W191.03
AND W191.07
AND W192.07
AND W192.03
AND W190.08
AND W192.11
AND W52.12
LD 2128.06
ORNOT H7.06
ANDLD
AND W72.01
AND W164.14
AND W52.01
OUT W358.10
; rung 443
LD 2128.11
AND 2128.15
AND 2037.03
AND 2037.05
OUT W72.01
; rung 444
LD P_Off
LD W177.13
AND 2128.07
AND 2129.03
AND W190.12
AND W190.06
AND W194.01
AND W72.01
AND W164.14
ORLD
AND W165.03
OUT 413.01
; rung 445
LD W358.08
OR W193.01
LD W358.09
OR W358.05
ANDLD
LD W358.10
OR W358.04
ANDLD
AND W358.06
AND W358.07
AND W360.11
LDNOT 421.15
ORNOT 462.00
ANDLD
OUT W193.00
; rung 446
LD 10.14
OR W175.03
ANDNOT W193.05
ANDNOT T0478
OUT W175.03
TIM 0478 #5

; rung 447
LD T0478
@MOV(021) #2 W400
; rung 448
LD 13.03
OUT 400.09
; rung 449: ----- 自動運転ｻｲｸﾙ停止条件 ----- / 出力W19303 ONで自動運転ｻｲｸﾙ停止
LDNOT 427.11
ANDNOT 427.12
ANDNOT 427.08
ANDNOT 427.09
OUTNOT W188.14
; rung 450
LDNOT 10.15
OR W188.14
OR H1.05
OR W193.02
AND W193.05
OUT W193.02
; rung 451
LD T0093
OR W358.05
LD T0094
OR W358.04
ANDLD
AND W193.02
AND T0022
OUT W193.03
; rung 452: ----- 自動運転即切条件 ----- / 出力W19304 ONで自動運転即停止
LD W191.04
OR W191.08
OR W385.10
OR W344.02
OR W173.08
LD W57.07
OR W57.08
OR W68.00
OR W68.01
OR W68.03
AND W345.04
ORLD
AND W170.00
OUT W356.14

; rung 453
LD W191.05
OR W191.09
OR W385.13
OR W344.03
OR W173.09
LD W57.09
OR W57.10
OR W68.06
OR W68.07
OR W68.09
AND W345.05
ORLD
AND W170.01
OUT W356.15
; rung 454
LDNOT W384.02
ANDNOT W384.12
ANDNOT W385.09
ANDNOT W385.11
ANDNOT W385.12
ANDNOT W344.07
ANDNOT W384.03
ANDNOT W344.12
OUTNOT W358.11
; rung 455
LDNOT 428.02
ANDNOT 428.07
ANDNOT 429.07
ANDNOT 428.09
ANDNOT 429.09
ANDNOT 428.10
ANDNOT 459.14
ANDNOT 459.15
ANDNOT W345.10
ANDNOT W345.11
ANDNOT W345.09
OUTNOT W171.09
; rung 456
LDNOT W384.00
ANDNOT W385.07
ANDNOT W385.05
ANDNOT W385.06
OUTNOT W175.01
; rung 457
LD W358.11
OR W171.09
OR W175.01
ORNOT 10.07
OR W356.14
OR W356.15
LD 427.10
ANDNOT W193.01
ORLD
OR W394.01
OUT W193.04

; rung 458: ----- 自動運転開始 -----
LDNOT W192.08
OR W358.05
LDNOT W192.09
OR W358.04
ANDLD
AND W170.09
ANDNOT 16.09
ANDNOT W193.04
ANDNOT W374.12
ANDNOT W193.03
AND T0020
AND T0037
OUT W356.13
; rung 459
LD 456.12
ANDNOT H1.04
LD 456.13
AND H1.04
ORLD
ANDNOT H1.00
LD 456.12
AND 456.13
AND H1.00
ORLD
AND T0036
AND 427.13
OUT W356.12
; rung 460
LD W320.00
OR W358.04
LD W190.00
OR W358.05
ANDLD
AND W165.01
AND W165.03
AND W193.00
OUT W356.11
; rung 461
LD 10.14
AND W356.11
OR W193.05
LD W356.12
OR W193.01
ANDLD
AND W356.13
OUT W193.05
TIM 0021 #30
DIFU(013) W190.01
AND T0021
TIM 0022 #50
DIFD(014) W190.02
DIFU(013) W190.03
; rung 462: ----- 初回開始処理 -----
LDNOT H1.00
OR H1.00
ANDNOT H1.04
ANDNOT W223.04
LDNOT H1.00
AND H1.04
ANDNOT W225.01
ORLD
OUT W356.10

; rung 463
LD W190.01
LDNOT W190.02
AND W170.04
ORLD
AND W356.10
OUT W170.04
LD W223.01
OR W224.14
ANDLD
OUT TR0
LDNOT H1.03
ANDNOT 16.10
AND 2110.06
LD W161.04
AND 16.10
ORLD
ANDLD
LD H1.00
ORNOT H1.00
ANDLD
ANDNOT H1.04
DIFU(013) W170.07
LD TR0
LDNOT H1.03
ANDNOT 16.10
AND 2130.06
LD W161.04
AND 16.10
ORLD
ANDLD
ANDNOT H1.00
AND H1.04
DIFU(013) W300.07
; rung 464: ********** 左ﾌﾟﾗﾃﾝﾛｯｸﾋﾟﾝ戻り処理 ********** / 今回、ｲﾝｻｰﾄﾛﾎﾞｯﾄ使用している場合は必ずﾌﾟﾗﾃﾝﾛｯｸﾋﾟﾝを打っているので下記の様に追加
LD 2109.00
AND 2109.01
AND T0511
OUT W186.15
; rung 465
LD 2071.00
AND W170.13
LD T0021
AND H1.05
OR T0021
AND W165.00
ORLD
OR W186.14
ANDNOT W186.15
AND T0511
OUT W186.14
; rung 466: ********** 右ﾌﾟﾗﾃﾝﾛｯｸﾋﾟﾝ戻り処理 *********** / 今回、ｲﾝｻｰﾄﾛﾎﾞｯﾄ使用している場合は必ずﾌﾟﾗﾃﾝﾛｯｸﾋﾟﾝを打っているので下記の様に追加
LD 2129.00
AND 2129.01
AND T0511
OUT W316.15
; rung 467
LD 2091.00
AND W170.13
LD T0021
AND H1.05
OR T0021
AND W165.02
ORLD
OR W316.14
ANDNOT W316.15
AND T0511
OUT W316.14
; rung 468: ********** 左予備型閉行程処理 **********
LD W175.08
OUT W189.00

; rung 469
LD 16.05
AND W181.12
AND W223.00
OR W189.01
AND T0021
LD W170.13
AND 2070.15
ORLD
ANDNOT W182.02
ANDNOT W182.03
ANDNOT W189.00
AND W193.15
AND W186.15
ANDNOT T0093
ANDNOT W223.01
OUT W189.01
TIM 0053 #10
AND T0021
DIFD(014) W189.02
DIFU(013) W189.03
; rung 470
LD W189.01
OR W53.00
ANDNOT W183.00
ANDNOT 2100.12
OUT W53.00
; rung 471: ********** 右予備型閉行程処理 **********
LD W175.09
OUT W319.00
; rung 472
LD 16.07
AND W311.12
AND W224.13
OR W319.01
AND T0021
LD W170.13
AND 2090.15
ORLD
ANDNOT W312.02
ANDNOT W312.03
ANDNOT W319.00
AND W193.15
AND W316.15
ANDNOT T0094
ANDNOT W224.14
OUT W319.01
TIM 0052 #10
AND T0021
DIFD(014) W319.02
DIFU(013) W319.03
; rung 473
LD W319.01
OR W53.01
ANDNOT W313.00
ANDNOT 2120.12
OUT W53.01
; rung 474: ----- 左右初回無効処理 -----
LD W190.01
OR W161.13
AND W170.09
ANDNOT 16.05
OUT W161.13
DIFU(013) W40.15
; rung 475
LD W190.01
OR W161.12
AND W170.09
ANDNOT 16.07
OUT W161.12
DIFU(013) W41.15

; rung 476: ********** 左下ピンチ開閉処理 **********
LD W193.05
AND W170.00
AND H1.09
OUT TR0
LD W170.08
AND H1.03
LD W162.00
OR W170.07
ANDNOT H1.03
ORLD
AND W165.00
ANDNOT H1.08
LD T1119
AND W161.15
AND H1.08
ORLD
OR W187.00
ANDLD
ANDNOT W223.00
ANDNOT W187.01
OUT W187.00
TIM 1116 D1116
LD TR0
LD W187.00
AND T1116
OR W170.10
OR W187.01
ANDLD
ANDNOT W187.02
ANDNOT W223.00
OUT W187.01
TIM 1117 D1117
AND W183.15
TIM 0016 #85
LD TR0
LDNOT T1121
AND T1117
LD T1122
AND T0016
ORLD
AND W187.01
OR W187.02
ANDLD
LDNOT 2109.07
ORNOT 2110.03
ANDLD
ANDNOT W223.00
OUT W187.02
LD TR0
AND W223.00
TIM 0474 #5
ANDNOT T0474
OUT W187.03
; rung 477
LD W170.13
AND H1.09
OUT TR0
AND 2068.13
OUT W187.04
LD TR0
AND 2068.12
AND W197.01
OUT W187.05
; rung 478
LD W187.04
OR W187.01
AND W190.05
AND H1.09
AND W193.14
OUT W162.07
; rung 479
LD W187.05
OR W187.02
OR W187.03
AND H1.09
AND W193.14
OUT W162.06

; rung 480
LD 2110.03
OR 2109.07
ANDNOT 10.07
DIFU(013) W56.00
; rung 481
LD W162.06
OR W56.00
LD W162.07
KEEP(011) H98.13
; rung 482
LD H1.09
AND W193.14
OUT TR0
AND H98.13
OUT 2100.10
LD TR0
ANDNOT H98.13
OUT 2100.11
DIFU(013) W303.01
; rung 483: ----- 左下ﾋﾟﾝﾁ冷却水 -----
LD T0021
ORNOT H1.13
AND H1.12
AND H1.09
AND W170.00
OUT 2031.08

; rung 484: ********** 右下ピンチ開閉処理 **********
LD W193.05
AND W170.01
AND H1.11
OUT TR0
LD W300.08
AND H1.03
LD W162.01
OR W300.07
ANDNOT H1.03
ORLD
AND W165.02
ANDNOT H1.10
LD T1319
AND W161.14
AND H1.10
ORLD
OR W317.00
ANDLD
ANDNOT W224.13
ANDNOT W317.01
OUT W317.00
TIM 1316 D1316
LD TR0
LD W317.00
AND T1316
OR W300.10
OR W317.01
ANDLD
ANDNOT W317.02
ANDNOT W224.13
OUT W317.01
TIM 1317 D1317
AND W313.15
TIM 0017 #85
LD TR0
LDNOT T1321
AND T1317
LD T1322
AND T0017
ORLD
AND W317.01
OR W317.02
ANDLD
LDNOT 2129.07
ORNOT 2130.03
ANDLD
ANDNOT W224.13
OUT W317.02
LD TR0
AND W224.13
TIM 0471 #5
ANDNOT T0471
OUT W317.03
; rung 485
LD W170.13
AND H1.11
OUT TR0
AND 2088.13
OUT W317.04
LD TR0
AND 2088.12
AND W194.01
OUT W317.05
; rung 486
LD W317.04
OR W317.01
AND W190.06
AND H1.11
AND W193.14
OUT W162.05
; rung 487
LD W317.05
OR W317.02
OR W317.03
AND H1.11
AND W193.14
OUT W162.04

; rung 488
LD 2130.03
OR 2129.07
ANDNOT 10.07
DIFU(013) W56.01
; rung 489
LD W162.04
OR W56.01
LD W162.05
KEEP(011) H98.12
; rung 490
LD H1.11
AND W193.14
OUT TR0
AND H98.12
OUT 2120.10
LD TR0
ANDNOT H98.12
OUT 2120.11
DIFU(013) W303.02
; rung 491: ----- 右下ﾋﾟﾝﾁ冷却水 -----
LD T0021
ORNOT H1.15
AND H1.14
AND H1.11
AND W170.01
OUT 2033.08
; rung 492: ********** 左エキスパンダ開閉処理 **********
LD W165.01
OR T0054
AND 428.04
AND 428.06
AND W190.11
AND W223.00
AND T0021
ANDNOT W181.12
ANDNOT W161.13
TIM 0054 #1
; rung 493
LD W165.01
AND W223.00
AND T0021
AND W190.11
AND H1.08
ANDNOT W161.13
ANDNOT 14.12
ANDNOT 14.13
DIFU(013) W52.02
; rung 494
LD W52.02
OR W52.03
LDNOT 428.04
ORNOT 428.06
ANDLD
AND W171.04
AND T0021
LDNOT W193.02
OR 409.00
OR 409.02
ANDLD
OUT W52.03
TIM 1118 D1118

; rung 495
LD W170.13
AND 2068.01
ANDNOT W223.01
LD 428.03
OR 428.05
AND W189.02
AND W223.01
LD H99.03
OR H1.06
AND T1118
ANDNOT T0093
ORLD
OR W189.12
AND T0021
ORLD
AND W190.11
AND W171.04
AND H1.08
ANDNOT W189.15
OUT W189.12
DIFU(013) W189.13
; rung 496
LD W170.13
AND 2068.00
LD W170.08
AND H1.03
LD W162.00
OR W170.07
ANDNOT H1.03
ORLD
AND W165.00
OR W189.14
AND T0021
ORLD
AND W171.04
AND H1.08
ANDNOT W189.13
OUT TR0
OUT W189.14
ANDNOT 16.09
ANDNOT 16.08
TIM 1119 D1119
LD TR0
DIFU(013) W189.15
; rung 497
LDNOT 428.04
ORNOT 428.06
AND W171.04
AND W190.11
AND W189.12
ANDNOT 406.10
ANDNOT 432.01
OUT 406.11
; rung 498
LDNOT 428.03
ORNOT 428.05
LD T1119
OR W170.13
ANDLD
AND W189.14
ANDNOT 406.11
AND W171.04
ANDNOT 432.00
OUT 406.10
; rung 499
LD T0021
AND 428.03
AND 428.05
DIFU(013) W161.15
; rung 500: ********** 右エキスパンダ開閉処理 **********
LD W165.03
OR T0055
AND 429.04
AND 429.06
AND W190.12
AND W224.13
AND T0021
ANDNOT W311.12
ANDNOT W161.12
TIM 0055 #1
; rung 501
LD W165.03
AND W224.13
AND T0021
AND W190.12
AND H1.10
ANDNOT W161.12
ANDNOT 14.14
ANDNOT 14.15
DIFU(013) W52.04

; rung 502
LD W52.04
OR W52.05
LDNOT 429.04
ORNOT 429.06
ANDLD
AND T0021
AND W171.04
LDNOT W193.02
OR 409.01
OR 409.03
ANDLD
OUT W52.05
TIM 1318 D1318
; rung 503
LD W170.13
AND 2088.01
ANDNOT W224.14
LD 429.03
OR 429.05
AND W319.02
AND W224.14
LD H99.04
OR H1.06
AND T1318
ANDNOT T0094
ORLD
OR W319.12
AND T0021
ORLD
AND W190.12
AND W171.04
AND H1.10
ANDNOT W319.15
OUT W319.12
DIFU(013) W319.13
; rung 504
LD W170.13
AND 2088.00
LD W300.08
AND H1.03
LD W162.01
OR W300.07
ANDNOT H1.03
ORLD
AND W165.02
OR W319.14
AND T0021
ORLD
AND W171.04
AND H1.10
ANDNOT W319.13
OUT TR0
OUT W319.14
ANDNOT 16.09
ANDNOT 16.08
TIM 1319 D1319
LD TR0
DIFU(013) W319.15
; rung 505
LDNOT 429.04
ORNOT 429.06
AND W171.04
AND W190.12
AND W319.12
ANDNOT 406.12
ANDNOT 432.03
OUT 406.13
; rung 506
LDNOT 429.03
ORNOT 429.05
LD T1319
OR W170.13
ANDLD
AND W319.14
ANDNOT 406.13
AND W171.04
ANDNOT 432.02
OUT 406.12
; rung 507
LD T0021
AND 429.03
AND 429.05
DIFU(013) W161.14

; rung 508: ********** 左本型閉行程処理 ********** / 本型閉開始はｴｷｽﾊﾟﾝﾀﾞ開及び下ﾋﾟﾝﾁ閉確認するまでしないこと
LD W170.08
AND H1.03
LD W162.00
OR W170.07
ANDNOT H1.03
ORLD
ANDNOT H1.08
LD T1119
AND W190.05
AND H1.08
ORLD
AND T0021
LD W223.01
LDNOT P_On
AND>(320) D600 #750
AND<(310) D600 #850
ORLD
ANDLD
ANDNOT W182.02
ANDNOT W182.03
AND W356.08
ANDNOT T1121
AND W186.15
AND W193.15
OUT W183.00
TIM 1101 D1101
; rung 509
LD W170.13
AND W193.15
OUT TR0
AND W223.01
TIM 0026 #10
LD TR0
AND 2070.15
AND T0026
AND W186.15
AND W190.05
OUT W183.01
; rung 510
LD W175.08
ORNOT W186.15
OUT W183.02
; rung 511
LD W190.05
AND W171.05
AND W186.15
OUT W171.07
; rung 512
LD T1101
OR W183.03
AND T0021
OR W183.01
ANDNOT W223.03
ANDNOT W182.02
ANDNOT W182.03
ANDNOT W183.02
AND W171.07
AND W193.15
OUT W183.03
TIM 0056 #10
DIFU(013) W183.04
; rung 513: ********** 右本型閉行程処理 ********** / 本型閉開始はｴｷｽﾊﾟﾝﾀﾞ開及び下ﾋﾟﾝﾁ閉確認するまでしないこと
LD W300.08
AND H1.03
LD W162.01
OR W300.07
ANDNOT H1.03
ORLD
ANDNOT H1.10
LD T1319
AND W190.06
AND H1.10
ORLD
OR W313.00
AND T0021
LD W224.14
LDNOT P_On
AND>(320) D606 #500
AND<(310) D606 #1000
ORLD
ANDLD
ANDNOT W312.02
ANDNOT W312.03
AND W356.09
ANDNOT T1321
AND W316.15
AND W193.15
OUT W313.00
TIM 1301 D1301

; rung 514
LD W170.13
AND W193.15
OUT TR0
AND W224.14
TIM 0024 #10
LD TR0
AND 2090.15
AND T0024
AND W316.15
AND W190.06
OUT W313.01
; rung 515
LD W175.09
ORNOT W316.15
OUT W313.02
; rung 516
LD W190.06
AND W171.06
AND W316.15
OUT W171.08
; rung 517
LD T1301
OR W313.03
AND T0021
OR W313.01
ANDNOT W225.00
ANDNOT W312.02
ANDNOT W312.03
ANDNOT W313.02
AND W171.08
AND W193.15
OUT W313.03
TIM 0057 #10
DIFU(013) W313.04
; rung 518: ********** 左型閉徐行行程処理 **********
LD W175.08
OUT W183.06
; rung 519
LD T1101
OR W183.07
AND T0021
AND W356.08
ANDNOT T1121
OR W183.01
AND W223.03
ANDNOT W182.02
ANDNOT W182.03
ANDNOT W183.14
ANDNOT W183.06
AND W190.05
AND W193.15
AND W186.15
ANDNOT T0506
OUT W183.07
; rung 520: ********** 右型閉徐行行程処理 **********
LD W175.09
OUT W313.06
; rung 521
LD T1301
OR W313.07
AND T0021
AND W356.09
ANDNOT T1321
OR W313.01
AND W225.00
ANDNOT W312.02
ANDNOT W312.03
ANDNOT W313.14
ANDNOT W313.06
AND W190.06
AND W193.15
AND W316.15
ANDNOT T0505
OUT W313.07

; rung 522: ********** ｶｯﾀｰ動作処理 ********** / ｶｯﾀｰ2度切りする為OUT(8106)保持とした
LD 2110.10
OR P_On
ANDNOT W181.14
ANDNOT 16.04
AND W170.00
OUT W356.06
; rung 523
LD 2130.10
OR P_On
ANDNOT W311.14
ANDNOT 16.06
AND W170.01
OUT W356.07
; rung 524
LD 2100.02
OR W193.01
LD 16.05
OR W360.00
ANDLD
AND W223.04
OR W181.06
AND W356.06
LD 2120.02
OR W193.01
LD 16.07
OR W360.01
ANDLD
AND W225.01
OR W181.06
AND W356.07
ORLD
AND T0021
OUT W181.06
TIM 1009 D1009
; rung 525
LD 2043.04
ANDNOT 2055.06
LDNOT 2054.02
AND 2055.06
ORLD
AND 2044.06
AND 2055.00
AND 2054.00
TIM 1005 D1005
OUT W51.13
; rung 526
LD T1009
AND T0021
LDNOT 2055.00
AND 2055.05
OR T1005
AND 2044.06
ORLD
DIFU(013) W181.07
OUT 401.02
; rung 527
LD T0021
OR W170.13
OR 2055.00
LD W181.07
AND 2048.08
OR 2042.14
ANDLD
ANDNOT 2048.09
ANDNOT 2042.15
AND W174.15
OUT 2042.14
DIFD(014) W170.06

; rung 528
LD W170.13
OR 2055.00
LD 2048.09
LDNOT 2048.08
ANDNOT 2048.09
ORLD
AND W181.07
OR 2042.15
ANDLD
ANDNOT 2048.08
ANDNOT 2042.14
AND W174.15
OUT 2042.15
DIFD(014) W170.05
; rung 529: ********** ﾊﾟﾘｿﾝｶｯﾀｰ移動処理 ********** / 成形位置ﾛｯｸﾋﾟﾝは成形位置、退避位置ﾛｯｸﾋﾟﾝは退避位置でのみﾛｯｸ可/成形位置及び退避位置移動はﾛｯｸﾋﾟﾝｱﾝﾛｯｸしていないと不可 / 全押出機停止以外ｶｯﾀｰ装置移動不可
LDNOT 2054.12
AND 2054.13
ANDNOT 2054.14
AND 2054.15
AND 420.06
AND W193.14
AND 16.08
AND W187.11
AND 2048.09
OUT W499.15
; rung 530
LD 460.04
AND W499.15
ANDNOT 2043.12
OUT 2043.11
; rung 531
LD 460.05
AND W499.15
ANDNOT 2043.11
OUT 2043.12
; rung 532: ----- ｶｯﾀｰ装置ﾛｯｸﾋﾟﾝ処理 ----- / 電源OFFでSVﾌﾘｰになりﾋﾟﾝが動く可能性があるのでHRﾘﾚｰでｷｰﾌﾟしている
LD 420.06
AND W193.14
AND 16.08
OUT W499.14
; rung 533
LD 460.06
AND W499.14
AND 2054.10
ANDNOT W499.13
OUT W499.12
; rung 534
LD 460.07
AND W499.14
ANDNOT W499.12
OUT W499.13
; rung 535
LD W499.13
LD W499.12
KEEP(011) H99.14
; rung 536
LD H99.14
AND W193.14
OUT 2046.01
; rung 537
LDNOT H99.14
AND W193.14
OUT 2046.00
; rung 538
LD 460.08
AND W499.14
AND 2054.09
ANDNOT W499.11
OUT W499.10
; rung 539
LD 460.09
AND W499.14
ANDNOT W499.10
OUT W499.11

; rung 540
LD W499.11
LD W499.10
KEEP(011) H99.15
; rung 541
LD H99.15
AND W193.14
OUT 2043.14
; rung 542
LDNOT H99.15
AND W193.14
OUT 2043.13
; rung 543: ********** 上プリブロー処理 ********** / 上排気は排気時間経過しなくても旋回開始で強制的に切れる
LD W165.00
AND T1116
OR W189.04
AND T0021
AND H8.09
ANDNOT W175.11
OUT W189.04
TIM 1104 D1104
AND T1104
OUT W189.05
TIM 1105 D1105
LDNOT T1106
ORNOT H8.08
ANDLD
ANDNOT T1105
OUT W189.06
; rung 544
LD W223.03
OR W359.14
LD P_Off
AND<=(315) D310 D600
ORLD
AND W189.05
OUT W359.14
TIM 1106 D1106
AND T1106
TIM 1107 D1107
ANDNOT T1107
OUT W359.15

; rung 545
LD W165.02
AND T1316
OR W301.04
AND T0021
AND H8.09
ANDNOT W305.11
OUT W301.04
TIM 1304 D1304
AND T1304
OUT W301.05
TIM 1305 D1305
LDNOT T1306
ORNOT H8.08
ANDLD
ANDNOT T1305
OUT W301.06
; rung 546
LD W225.00
OR W498.14
AND W301.05
OUT W498.14
TIM 1306 D1306
AND T1306
TIM 1307 D1307
ANDNOT T1307
OUT W498.15
; rung 547
LD W170.13
LD 2055.08
LD W134.01
AND H6.00
ORLD
ANDLD
AND H8.09
AND W193.14
OUT W189.07
; rung 548
LD 2048.09
AND 16.05
LD 2048.08
AND 16.07
ORLD
OR W186.00
AND 13.03
ANDNOT T1290
OUT W186.00
; rung 549
LD W189.07
OR W189.06
OR W301.06
OR W202.02
OR W203.02
AND H8.09
AND W193.14
OUT 2042.10
OUT 404.08
TIM 1290 #1

; rung 550
LD W359.15
OR W498.15
LD W170.13
AND H6.01
AND W134.03
ORLD
AND H8.09
AND H8.08
AND W193.14
OUT 2043.08
; rung 551
LD W189.05
ANDNOT T1107
LD W301.05
ANDNOT T1307
ORLD
LD W170.13
AND H6.04
AND W134.09
ORLD
AND H8.09
AND H8.08
AND H8.12
AND W193.14
OUT 2043.09
; rung 552
LD P_On
LD 401.09
OR 406.02
ANDLD
AND H3.05
AND W223.04
AND 14.13
OUT W202.00
TIM 1146 D1146
AND T1146
OUT W202.01
TIM 1147 D1147
ANDNOT T1147
OUT W202.02
; rung 553
LD P_On
LD 401.09
OR 406.02
ANDLD
AND H3.07
AND W225.01
AND 14.15
OUT W203.00
TIM 1346 D1346
AND T1346
OUT W203.01
TIM 1347 D1347
ANDNOT T1347
OUT W203.02

; rung 554: ********** 左プリブロー処理 ********** / 注意：ＪＰＯ機ﾃｽﾄで行った下吹込を行う場合はﾊｰﾄﾞ追加及びﾌﾟﾛｸﾞﾗﾑ変更要
LD W165.00
AND W223.01
OR W187.06
AND T0021
AND H3.00
ANDNOT W223.00
OUT W187.06
TIM 1138 D1138
AND T1138
OUT W187.07
TIM 1139 D1139
ANDNOT T1139
OUT W187.08
; rung 555
LD W170.13
AND 2068.14
AND H3.00
AND W193.14
OUT W187.09
; rung 556
LD W187.08
OR W187.09
AND H3.00
AND W193.14
OUT 2101.11
; rung 557: ********** 右プリブロー処理 ********** / 注意：ＪＰＯ機ﾃｽﾄで行った下吹込を行う場合はﾊｰﾄﾞ追加及びﾌﾟﾛｸﾞﾗﾑ変更要
LD W165.02
AND W224.14
OR W317.06
AND T0021
AND H3.02
ANDNOT W224.13
OUT W317.06
TIM 1338 D1338
AND T1338
OUT W317.07
TIM 1339 D1339
ANDNOT T1339
OUT W317.08
; rung 558
LD W170.13
AND 2088.14
AND H3.02
AND W193.14
OUT W317.09
; rung 559
LD W317.08
OR W317.09
AND H3.02
AND W193.14
OUT 2121.11

; rung 560: ----- 左下吹込処理 ----- / 下ﾌﾟﾘﾌﾞﾛｰを選択した場合、吹込遅延と繋がりが無いのでﾌﾟﾘﾌﾞﾛｰ時間を調整する。 / 注意：ＪＰＯ機ﾃｽﾄで行った下吹込を行う場合はﾊｰﾄﾞ追加及びﾌﾟﾛｸﾞﾗﾑ変更要
LD W189.09
ANDNOT T1121
LD W170.13
AND 2068.15
ORLD
AND H3.04
AND W193.14
OUT 2031.07
; rung 561: ----- 右下吹込処理 ----- / 下ﾌﾟﾘﾌﾞﾛｰを選択した場合、吹込遅延と繋がりが無いのでﾌﾟﾘﾌﾞﾛｰ時間を調整する。 / 注意：ＪＰＯ機ﾃｽﾄで行った下吹込を行う場合はﾊｰﾄﾞ追加及びﾌﾟﾛｸﾞﾗﾑ変更要
LD W319.09
ANDNOT T1321
LD W170.13
AND 2088.15
ORLD
AND H3.06
AND W193.14
OUT 2033.07
; rung 562: ********** 左保圧行程処理 ********** / 保圧は手動時かけない
LD W175.08
OUT W183.09
; rung 563
LD W223.04
OR W183.10
AND W170.00
AND W356.08
ANDNOT T1122
AND T0021
AND W193.15
ANDNOT W183.09
AND W186.15
AND W190.05
TIM 0029 #1
OUT W183.10
TIM 0506 #30
; rung 564
LD T0029
OR W183.11
ANDNOT T1102
AND T0021
OUT W183.11
; rung 565: ********** 右保圧行程処理 ********** / 保圧は手動時かけない
LD W175.09
OUT W313.09
; rung 566
LD W225.01
OR W313.10
AND W170.01
AND W356.09
ANDNOT T1322
AND T0021
AND W193.15
ANDNOT W313.09
AND W316.15
AND W190.06
TIM 0032 #1
OUT W313.10
TIM 0505 #30

; rung 567
LD T0032
OR W313.11
ANDNOT T1302
AND T0021
OUT W313.11
; rung 568: ********** 左型開行程処理 **********
LD W40.09
OR H1.06
LDNOT H8.15
ANDNOT H1.06
ORLD
AND W165.01
OR H1.05
OR W170.13
AND W165.03
OUT W361.12
; rung 569
LD W183.11
ANDNOT T0029
AND W186.15
AND W193.15
AND W361.12
OUT TR0
OUT W183.13
TIM 0030 #30
AND T0030
TIM 1102 D1102
LD TR0
ANDNOT T1102
OUT W183.14
; rung 570
LD W223.00
TIM 0000 #5
; rung 571
LD T1102
OR W183.15
AND W186.15
ANDNOT T0000
AND T0021
OUT W183.15
; rung 572
LD W186.15
OR W197.00
AND W170.13
AND 2070.14
ANDNOT W223.00
AND W193.15
LDNOT 457.11
ANDNOT 457.12
OR 460.01
ANDLD
OUT W182.00

; rung 573
LD W175.08
OR W189.01
OR W183.03
OR W183.07
OR T0029
OR W183.14
OR W226.13
OUT W182.01
; rung 574
LD W223.05
OR W165.14
AND H7.13
AND W183.15
AND W193.15
ANDNOT W223.00
OUT W165.14
TIM 1109 D1109
ANDNOT T1109
OUT W165.15
; rung 575
LD W183.15
OR W182.00
ANDNOT W165.15
ANDNOT W182.01
AND W193.15
OUT TR0
LDNOT W223.02
LD T0159
ANDNOT T0161
ORLD
ANDLD
OUT W182.02
LD TR0
AND W223.02
OUT TR0
AND T0159
AND T0161
OUT W182.03
LD TR0
TIM 0159 #0
AND W197.03
OUT W182.04
DIFU(013) W48.14
LD TR0
DIFU(013) W182.05
OUT W182.06
AND T0159
TIM 0161 #0
; rung 576
LD W183.15
AND T0021
OUT TR0
AND H1.05
OUT W322.15
LD TR0
DIFD(014) W170.14

; rung 577: --- 手動圧抜処理 --- / 自動運転保圧中、自動運転停止した場合、圧抜していない為、圧力に負けﾌﾟﾚﾌｨﾙ開出来なくなるので、 / 手動で型閉時圧抜1sec→ﾌﾟﾚﾌｨﾙ開→型開とした。
LD W182.00
AND W182.02
AND W223.04
TIM 0050 #10
ANDNOT T0050
OUT W165.07
; rung 578: ********** 右型開行程処理 **********
LD W41.09
LDNOT H8.15
ANDNOT H1.06
ORLD
OR H1.06
AND W165.03
OR H1.05
OR W170.13
AND W165.01
OUT W361.13
; rung 579
LD W313.11
ANDNOT T0032
AND W316.15
AND W193.15
AND W361.13
OUT TR0
OUT W313.13
TIM 0033 #30
AND T0033
TIM 1302 D1302
LD TR0
ANDNOT T1302
OUT W313.14
; rung 580
LD W224.13
TIM 0002 #5
; rung 581
LD T1302
OR W313.15
AND T0021
AND W316.15
ANDNOT T0002
OUT W313.15
; rung 582
LD W316.15
OR W194.00
AND W170.13
AND 2090.14
ANDNOT T0002
AND W193.15
LDNOT 457.14
ANDNOT 457.13
OR 461.00
ANDLD
OUT W312.00

; rung 583
LD W175.09
OR W319.01
OR W313.03
OR W313.07
OR T0032
OR W313.14
OR W226.11
OUT W312.01
; rung 584
LD W225.02
OR W166.14
AND H7.15
AND W313.15
AND W193.15
ANDNOT W224.13
OUT W166.14
TIM 1309 D1309
ANDNOT T1309
OUT W166.15
; rung 585
LD W313.15
OR W312.00
ANDNOT W166.15
ANDNOT W312.01
AND W193.15
OUT TR0
LDNOT W224.15
LD T0157
ANDNOT T0160
ORLD
ANDLD
OUT W312.02
LD TR0
AND W224.15
OUT TR0
AND T0157
AND T0160
OUT W312.03
LD TR0
TIM 0157 #0
AND W194.03
OUT W312.04
DIFU(013) W48.15
LD TR0
DIFU(013) W312.05
OUT W312.06
AND T0157
TIM 0160 #0
; rung 586
LD W313.15
AND T0021
OUT TR0
AND H1.05
OUT W322.14
LD TR0
DIFD(014) W170.15

; rung 587: --- 手動圧抜処理 --- / 自動運転保圧中、自動運転停止した場合、圧抜していない為、圧力に負けﾌﾟﾚﾌｨﾙ開出来なくなるので、 / 手動で型閉時圧抜1sec→ﾌﾟﾚﾌｨﾙ開→型開とした。
LD W312.00
AND W312.02
AND W225.01
TIM 0051 #10
ANDNOT T0051
OUT W165.08
; rung 588: ********** 左ﾌﾟﾗﾃﾝﾛｯｸ打込処理 **********
LD 2108.12
AND 2108.13
AND T0511
OUT W193.06
; rung 589
LD 2071.01
AND W170.13
LD H1.05
AND W322.15
ORLD
LD H1.01
ORNOT H1.01
OR H1.06
OR 16.10
AND T0021
AND H1.01
AND W183.15
ORLD
OR W187.13
AND W223.00
AND W197.02
ANDNOT W186.14
AND T0511
OUT W187.13
; rung 590
LD W187.13
LD W186.14
KEEP(011) H99.01
; rung 591
LD H99.01
AND T0511
OUT 2100.08
; rung 592
LDNOT H99.01
AND T0511
OUT 2100.09
; rung 593: ********** 右ﾌﾟﾗﾃﾝﾛｯｸ打込処理 **********
LD 2128.12
AND 2128.13
AND T0511
OUT W191.11

; rung 594
LD 2091.01
AND W170.13
LD H1.05
AND W322.14
ORLD
LD H1.01
ORNOT H1.01
OR H1.06
OR 16.10
AND T0021
AND H1.01
AND W313.15
ORLD
OR W317.13
AND W224.13
AND W194.02
ANDNOT W316.14
AND T0511
OUT W317.13
; rung 595
LD W317.13
LD W316.14
KEEP(011) H98.01
; rung 596
LD H98.01
AND T0511
OUT 2120.08
; rung 597
LDNOT H98.01
AND T0511
OUT 2120.09
; rung 598: ********** 左No.1針ノズル打込処理 *********
LD W170.00
AND H2.00
AND T0021
OUT TR0
LD W223.06
OR W188.00
ANDLD
ANDNOT W223.00
ANDNOT T1121
OUT W188.00
TIM 1130 D1130
LD TR0
LD W188.00
AND T1130
OR W188.01
ANDLD
ANDNOT W188.03
ANDNOT W223.00
OUT W188.01
LD TR0
LD W188.01
AND T1121
OR W188.02
ANDLD
ANDNOT W223.00
OUT W188.02
TIM 1131 D1131
LD TR0
AND W188.02
AND T1131
ANDNOT W223.00
OUT W188.03
LD TR0
AND W223.00
ANDNOT T0086
OUT W188.04

; rung 599
LD W170.13
AND H2.00
OUT TR0
AND 2068.07
OUT W188.05
LD TR0
AND 2068.06
OUT W188.06
; rung 600
LD W188.05
OR W188.01
ANDNOT W167.01
AND W193.14
AND H2.00
OUT W167.00
; rung 601
LD W188.06
OR W188.03
OR W188.04
ANDNOT W167.00
AND W193.14
AND H2.00
OUT W167.01
; rung 602
LD W167.00
LD W167.01
LD W190.01
ANDNOT W358.05
ORLD
KEEP(011) H79.00
; rung 603
LD H2.00
AND W193.14
OUT TR0
AND H79.00
OUT 2102.06
LD TR0
ANDNOT H79.00
OUT 2102.10
; rung 604: ********** 左No.2針ノズル打込処理 **********
LD W170.00
AND H2.01
AND T0021
OUT TR0
LD W223.06
OR W188.07
ANDLD
ANDNOT W223.00
ANDNOT T1121
OUT W188.07
TIM 1132 D1132
LD TR0
LD W188.07
AND T1132
OR W188.08
ANDLD
ANDNOT W188.10
ANDNOT W223.00
OUT W188.08
LD TR0
LD W188.08
AND T1121
OR W188.09
ANDLD
ANDNOT W223.00
OUT W188.09
TIM 1133 D1133
LD TR0
AND W188.09
AND T1133
ANDNOT W223.00
OUT W188.10
LD TR0
AND W223.00
ANDNOT T0086
OUT W188.11

; rung 605
LD W170.13
AND H2.01
OUT TR0
AND 2068.09
OUT W188.12
LD TR0
AND 2068.08
OUT W188.13
; rung 606
LD W188.12
OR W188.08
ANDNOT W167.03
AND W193.14
AND H2.01
OUT W167.02
; rung 607
LD W188.13
OR W188.10
OR W188.11
ANDNOT W167.02
AND W193.14
AND H2.01
OUT W167.03
; rung 608
LD W167.02
LD W167.03
LD W190.01
ANDNOT W358.05
ORLD
KEEP(011) H79.02
; rung 609
LD H2.01
AND W193.14
OUT TR0
AND H79.02
OUT 2102.07
LD TR0
ANDNOT H79.02
OUT 2102.11
; rung 610: ********** 左No.3針ノズル打込処理 **********
LD W170.00
AND H2.04
AND T0021
OUT TR0
LD W223.06
OR W166.00
ANDLD
ANDNOT W223.00
ANDNOT T1121
OUT W166.00
TIM 1134 D1134
LD TR0
LD W166.00
AND T1134
OR W166.01
ANDLD
ANDNOT W166.03
ANDNOT W223.00
OUT W166.01
LD TR0
LD W166.01
AND T1121
OR W166.02
ANDLD
ANDNOT W223.00
OUT W166.02
TIM 1135 D1135
LD TR0
AND W166.02
AND T1135
ANDNOT W223.00
OUT W166.03
LD TR0
AND W223.00
ANDNOT T0086
OUT W166.04

; rung 611
LD W170.13
AND H2.04
OUT TR0
AND 2068.11
OUT W166.05
LD TR0
AND 2068.10
OUT W166.06
; rung 612
LD W166.05
OR W166.01
ANDNOT W167.05
AND W193.14
AND H2.04
OUT W167.04
; rung 613
LD W166.06
OR W166.03
OR W166.04
ANDNOT W167.04
AND W193.14
AND H2.04
OUT W167.05
; rung 614
LD W167.04
LD W167.05
LD W190.01
ANDNOT W358.05
ORLD
KEEP(011) H79.04
; rung 615
LD H2.04
AND W193.14
OUT TR0
AND H79.04
OUT 2102.08
LD TR0
ANDNOT H79.04
OUT 2103.05
; rung 616: ********** 左No.4針ノズル打込処理 *********
LD W170.00
AND H2.08
AND T0021
OUT TR0
LD W223.06
OR W156.00
ANDLD
ANDNOT W223.00
ANDNOT T1121
OUT W156.00
TIM 1170 D1170
LD TR0
LD W156.00
AND T1170
OR W156.01
ANDLD
ANDNOT W156.03
ANDNOT W223.00
OUT W156.01
LD TR0
LD W156.01
AND T1121
OR W156.02
ANDLD
ANDNOT W223.00
OUT W156.02
TIM 1171 D1171
LD TR0
AND W156.02
AND T1171
ANDNOT W223.00
OUT W156.03
LD TR0
AND W223.00
ANDNOT T0086
OUT W156.04

; rung 617
LD W170.13
AND H2.08
OUT TR0
AND 2070.01
OUT W156.05
LD TR0
AND 2070.00
OUT W156.06
; rung 618
LD W156.05
OR W156.01
ANDNOT W160.01
AND W193.14
AND H2.08
OUT W160.00
; rung 619
LD W156.06
OR W156.03
OR W156.04
ANDNOT W160.00
AND W193.14
AND H2.08
OUT W160.01
; rung 620
LD W160.00
LD W160.01
LD W190.01
ANDNOT W358.05
ORLD
KEEP(011) H79.06
; rung 621
LD H2.08
AND W193.14
OUT TR0
AND H79.06
OUT 2104.04
LD TR0
ANDNOT H79.06
OUT 2104.08
; rung 622: ********** 左No.5針ノズル打込処理 *********
LD W170.00
AND H2.09
AND T0021
OUT TR0
LD W223.06
OR W156.07
ANDLD
ANDNOT W223.00
ANDNOT T1121
OUT W156.07
TIM 1172 D1172
LD TR0
LD W156.07
AND T1172
OR W156.08
ANDLD
ANDNOT W156.10
ANDNOT W223.00
OUT W156.08
LD TR0
LD W156.08
AND T1121
OR W156.09
ANDLD
ANDNOT W223.00
OUT W156.09
TIM 1173 D1173
LD TR0
AND W156.09
AND T1173
ANDNOT W223.00
OUT W156.10
LD TR0
AND W223.00
ANDNOT T0086
OUT W156.11

; rung 623
LD W170.13
AND H2.09
OUT TR0
AND 2070.03
OUT W156.12
LD TR0
AND 2070.02
OUT W156.13
; rung 624
LD W156.12
OR W156.08
ANDNOT W160.03
AND W193.14
AND H2.09
OUT W160.02
; rung 625
LD W156.13
OR W156.10
OR W156.11
ANDNOT W160.02
AND W193.14
AND H2.09
OUT W160.03
; rung 626
LD W160.02
LD W160.03
LD W190.01
ANDNOT W358.05
ORLD
KEEP(011) H79.07
; rung 627
LD H2.09
AND W193.14
OUT TR0
AND H79.07
OUT 2104.05
LD TR0
ANDNOT H79.07
OUT 2104.09
; rung 628: ********** 左No.6針ノズル打込処理 *********
LD W170.00
AND H2.12
AND T0021
OUT TR0
LD W223.06
OR W156.14
ANDLD
ANDNOT W223.00
ANDNOT T1121
OUT W156.14
TIM 1174 D1174
LD TR0
LD W156.14
AND T1174
OR W156.15
ANDLD
ANDNOT W157.01
ANDNOT W223.00
OUT W156.15
LD TR0
LD W156.15
AND T1121
OR W157.00
ANDLD
ANDNOT W223.00
OUT W157.00
TIM 1175 D1175
LD TR0
AND W157.00
AND T1175
ANDNOT W223.00
OUT W157.01
LD TR0
AND W223.00
ANDNOT T0086
OUT W157.02

; rung 629
LD W170.13
AND H2.12
OUT TR0
AND 2072.05
OUT W157.03
LD TR0
AND 2072.04
OUT W157.04
; rung 630
LD W157.03
OR W156.15
ANDNOT W160.05
AND W193.14
AND H2.12
OUT W160.04
; rung 631
LD W157.04
OR W157.01
OR W157.02
ANDNOT W160.04
AND W193.14
AND H2.12
OUT W160.05
; rung 632
LD W160.04
LD W160.05
LD W190.01
ANDNOT W358.05
ORLD
KEEP(011) H79.08
; rung 633
LD H2.12
AND W193.14
OUT TR0
AND H79.08
OUT 2104.06
LD TR0
ANDNOT H79.08
OUT 2104.10
; rung 634: ********** 左No.7針ノズル打込処理 *********
LD W170.00
AND H2.13
AND T0021
OUT TR0
LD W223.06
OR W154.00
ANDLD
ANDNOT W223.00
ANDNOT T1121
OUT W154.00
TIM 1176 D1176
LD TR0
LD W154.00
AND T1176
OR W154.01
ANDLD
ANDNOT W154.03
ANDNOT W223.00
OUT W154.01
LD TR0
LD W154.01
AND T1121
OR W154.02
ANDLD
ANDNOT W223.00
OUT W154.02
TIM 1177 D1177
LD TR0
AND W154.02
AND T1177
ANDNOT W223.00
OUT W154.03
LD TR0
AND W223.00
ANDNOT T0086
OUT W154.04

; rung 635
LD W170.13
AND H2.13
OUT TR0
AND 2072.07
OUT W154.05
LD TR0
AND 2072.06
OUT W154.06
; rung 636
LD W154.05
OR W154.01
ANDNOT W158.11
AND W193.14
AND H2.13
OUT W158.10
; rung 637
LD W154.06
OR W154.03
OR W154.04
ANDNOT W158.10
AND W193.14
AND H2.13
OUT W158.11
; rung 638
LD W158.10
LD W158.11
LD W190.01
ANDNOT W358.05
ORLD
KEEP(011) H79.12
; rung 639
LD H2.13
AND W193.14
OUT TR0
AND H79.12
OUT 2104.07
LD TR0
ANDNOT H79.12
OUT 2104.11
; rung 640: ********** 右No.1針ノズル打込処理 **********
LD W170.01
AND H2.02
AND T0021
OUT TR0
LD W225.03
OR W318.00
ANDLD
ANDNOT W224.13
ANDNOT T1321
OUT W318.00
TIM 1330 D1330
LD TR0
LD W318.00
AND T1330
OR W318.01
ANDLD
ANDNOT W318.03
ANDNOT W224.13
OUT W318.01
LD TR0
LD W318.01
AND T1321
OR W318.02
ANDLD
ANDNOT W224.13
OUT W318.02
TIM 1331 D1331
LD TR0
AND W318.02
AND T1331
ANDNOT W224.13
OUT W318.03
LD TR0
AND W224.13
ANDNOT T0042
OUT W318.04

; rung 641
LD W170.13
AND H2.02
OUT TR0
AND 2088.07
OUT W318.05
LD TR0
AND 2088.06
OUT W318.06
; rung 642
LD W318.05
OR W318.01
ANDNOT W167.07
AND W193.14
AND H2.02
OUT W167.06
; rung 643
LD W318.06
OR W318.03
OR W318.04
ANDNOT W167.06
AND W193.14
AND H2.02
OUT W167.07
; rung 644
LD W167.06
LD W167.07
LD W190.01
ANDNOT W358.04
ORLD
KEEP(011) H79.01
; rung 645
LD H2.02
AND W193.14
OUT TR0
AND H79.01
OUT 2122.06
LD TR0
ANDNOT H79.01
OUT 2122.10
; rung 646: ********** 右No.2針ノズル打込処理 **********
LD W170.01
AND H2.03
AND T0021
OUT TR0
LD W225.03
OR W318.07
ANDLD
ANDNOT W224.13
ANDNOT T1321
OUT W318.07
TIM 1332 D1332
LD TR0
LD W318.07
AND T1332
OR W318.08
ANDLD
ANDNOT W318.10
ANDNOT W224.13
OUT W318.08
LD TR0
LD W318.08
AND T1321
OR W318.09
ANDLD
ANDNOT W224.13
OUT W318.09
TIM 1333 D1333
LD TR0
AND W318.09
AND T1333
ANDNOT W224.13
OUT W318.10
LD TR0
AND W224.13
ANDNOT T0042
OUT W318.11

; rung 647
LD W170.13
AND H2.03
OUT TR0
AND 2088.09
OUT W318.12
LD TR0
AND 2088.08
OUT W318.13
; rung 648
LD W318.12
OR W318.08
ANDNOT W167.09
AND W193.14
AND H2.03
OUT W167.08
; rung 649
LD W318.13
OR W318.10
OR W318.11
ANDNOT W167.08
AND W193.14
AND H2.03
OUT W167.09
; rung 650
LD W167.08
LD W167.09
LD W190.01
ANDNOT W358.04
ORLD
KEEP(011) H79.03
; rung 651
LD H2.03
AND W193.14
OUT TR0
AND H79.03
OUT 2122.07
LD TR0
ANDNOT H79.03
OUT 2122.11
; rung 652: ********** 右No.3針ノズル打込処理 **********
LD W170.01
AND H2.06
AND T0021
OUT TR0
LD W225.03
OR W166.07
ANDLD
ANDNOT W224.13
ANDNOT T1321
OUT W166.07
TIM 1334 D1334
LD TR0
LD W166.07
AND T1334
OR W166.08
ANDLD
ANDNOT W166.10
ANDNOT W224.13
OUT W166.08
LD TR0
LD W166.08
AND T1321
OR W166.09
ANDLD
ANDNOT W224.13
OUT W166.09
TIM 1335 D1335
LD TR0
AND W166.09
AND T1335
ANDNOT W224.13
OUT W166.10
LD TR0
AND W224.13
ANDNOT T0042
OUT W166.11

; rung 653
LD W170.13
AND H2.06
OUT TR0
AND 2088.11
OUT W166.12
LD TR0
AND 2088.10
OUT W166.13
; rung 654
LD W166.12
OR W166.08
ANDNOT W167.11
AND W193.14
AND H2.06
OUT W167.10
; rung 655
LD W166.13
OR W166.10
OR W166.11
ANDNOT W167.10
AND W193.14
AND H2.06
OUT W167.11
; rung 656
LD W167.10
LD W167.11
LD W190.01
ANDNOT W358.04
ORLD
KEEP(011) H79.05
; rung 657
LD H2.06
AND W193.14
OUT TR0
AND H79.05
OUT 2122.08
LD TR0
ANDNOT H79.05
OUT 2123.05
; rung 658: ********** 右No.4針ノズル打込処理 **********
LD W170.01
AND H2.10
AND T0021
OUT TR0
LD W225.03
OR W157.05
ANDLD
ANDNOT W224.13
ANDNOT T1321
OUT W157.05
TIM 1370 D1370
LD TR0
LD W157.05
AND T1370
OR W157.06
ANDLD
ANDNOT W157.08
ANDNOT W224.13
OUT W157.06
LD TR0
LD W157.06
AND T1321
OR W157.07
ANDLD
ANDNOT W224.13
OUT W157.07
TIM 1371 D1371
LD TR0
AND W157.07
AND T1371
ANDNOT W224.13
OUT W157.08
LD TR0
AND W224.13
ANDNOT T0042
OUT W157.09

; rung 659
LD W170.13
AND H2.10
OUT TR0
AND 2090.01
OUT W157.10
LD TR0
AND 2090.00
OUT W157.11
; rung 660
LD W157.10
OR W157.06
ANDNOT W160.07
AND W193.14
AND H2.10
OUT W160.06
; rung 661
LD W157.11
OR W157.08
OR W157.09
ANDNOT W160.06
AND W193.14
AND H2.10
OUT W160.07
; rung 662
LD W160.06
LD W160.07
LD W190.01
ANDNOT W358.04
ORLD
KEEP(011) H79.09
; rung 663
LD H2.10
AND W193.14
OUT TR0
AND H79.09
OUT 2124.04
LD TR0
ANDNOT H79.09
OUT 2124.08
; rung 664: ********** 右No.5針ノズル打込処理 **********
LD W170.01
AND H2.11
AND T0021
OUT TR0
LD W225.03
OR W157.12
ANDLD
ANDNOT W224.13
ANDNOT T1321
OUT W157.12
TIM 1372 D1372
LD TR0
LD W157.12
AND T1372
OR W157.13
ANDLD
ANDNOT W157.15
ANDNOT W224.13
OUT W157.13
LD TR0
LD W157.13
AND T1321
OR W157.14
ANDLD
ANDNOT W224.13
OUT W157.14
TIM 1373 D1373
LD TR0
AND W157.14
AND T1373
ANDNOT W224.13
OUT W157.15
LD TR0
AND W224.13
ANDNOT T0042
OUT W158.00

; rung 665
LD W170.13
AND H2.11
OUT TR0
AND 2090.03
OUT W158.01
LD TR0
AND 2090.02
OUT W158.02
; rung 666
LD W158.01
OR W157.13
ANDNOT W160.09
AND W193.14
AND H2.11
OUT W160.08
; rung 667
LD W158.02
OR W157.15
OR W158.00
ANDNOT W160.08
AND W193.14
AND H2.11
OUT W160.09
; rung 668
LD W160.08
LD W160.09
LD W190.01
ANDNOT W358.04
ORLD
KEEP(011) H79.10
; rung 669
LD H2.11
AND W193.14
OUT TR0
AND H79.10
OUT 2124.05
LD TR0
ANDNOT H79.10
OUT 2124.09
; rung 670: ********** 右No.6針ノズル打込処理 **********
LD W170.01
AND H2.14
AND T0021
OUT TR0
LD W225.03
OR W158.03
ANDLD
ANDNOT W224.13
ANDNOT T1321
OUT W158.03
TIM 1374 D1374
LD TR0
LD W158.03
AND T1374
OR W158.04
ANDLD
ANDNOT W158.06
ANDNOT W224.13
OUT W158.04
LD TR0
LD W158.04
AND T1321
OR W158.05
ANDLD
ANDNOT W224.13
OUT W158.05
TIM 1375 D1375
LD TR0
AND W158.05
AND T1375
ANDNOT W224.13
OUT W158.06
LD TR0
AND W224.13
ANDNOT T0042
OUT W158.07

; rung 671
LD W170.13
AND H2.14
OUT TR0
AND 2092.05
OUT W158.08
LD TR0
AND 2092.04
OUT W158.09
; rung 672
LD W158.08
OR W158.04
ANDNOT W160.11
AND W193.14
AND H2.14
OUT W160.10
; rung 673
LD W158.09
OR W158.06
OR W158.07
ANDNOT W160.10
AND W193.14
AND H2.14
OUT W160.11
; rung 674
LD W160.10
LD W160.11
LD W190.01
ANDNOT W358.04
ORLD
KEEP(011) H79.11
; rung 675
LD H2.14
AND W193.14
OUT TR0
AND H79.11
OUT 2124.06
LD TR0
ANDNOT H79.11
OUT 2124.10
; rung 676: ********** 右No.7針ノズル打込処理 **********
LD W170.01
AND H2.15
AND T0021
OUT TR0
LD W225.03
OR W154.07
ANDLD
ANDNOT W224.13
ANDNOT T1321
OUT W154.07
TIM 1376 D1376
LD TR0
LD W154.07
AND T1376
OR W154.08
ANDLD
ANDNOT W154.10
ANDNOT W224.13
OUT W154.08
LD TR0
LD W154.08
AND T1321
OR W154.09
ANDLD
ANDNOT W224.13
OUT W154.09
TIM 1377 D1377
LD TR0
AND W154.09
AND T1377
ANDNOT W224.13
OUT W154.10
LD TR0
AND W224.13
ANDNOT T0042
OUT W154.11

; rung 677
LD W170.13
AND H2.15
OUT TR0
AND 2092.07
OUT W154.12
LD TR0
AND 2092.06
OUT W154.13
; rung 678
LD W154.12
OR W154.08
ANDNOT W158.13
AND W193.14
AND H2.15
OUT W158.12
; rung 679
LD W154.13
OR W154.10
OR W154.11
ANDNOT W158.12
AND W193.14
AND H2.15
OUT W158.13
; rung 680
LD W158.12
LD W158.13
LD W190.01
ANDNOT W358.04
ORLD
KEEP(011) H79.13
; rung 681
LD H2.15
AND W193.14
OUT TR0
AND H79.13
OUT 2124.07
LD TR0
ANDNOT H79.13
OUT 2124.11
; rung 682
LD P_On
AND 13.03
AND H8.00
AND W223.04
TIM 1144 D1144
; rung 683
LD T1144
AND>(320) D1145 #0
LDNOT T1144
TTIM(087) 1145 D1145

; rung 684: ********** 左上ﾊﾞﾘ冷却処理 **********
LD T1144
OR 2103.06
AND W193.05
ANDNOT W223.00
OR W170.13
AND W170.00
AND W193.14
AND H8.00
OUT TR0
LD 2069.01
ANDNOT T1121
LD W170.09
ANDNOT T1121
ORLD
ANDLD
OUT 2103.06
LD TR0
LD 2069.00
OR W170.09
ANDLD
OUT TR0
ANDNOT T1121
OUT 2103.07
LD TR0
ANDNOT P_On
OUT 2101.10
; rung 685
LDNOT 2101.10
OUT 2101.09
; rung 686
LD P_On
AND 13.03
AND H8.02
AND W225.01
TIM 1344 D1344
; rung 687
LD T1344
AND>(320) D1345 #0
LDNOT T1344
TTIM(087) 1345 D1345
; rung 688: ********** 右上ﾊﾞﾘ冷却処理 **********
LD T1344
OR 2123.06
AND W193.05
ANDNOT W224.13
OR W170.13
AND W170.01
AND W193.14
AND H8.02
OUT TR0
LD 2089.01
ANDNOT T1321
LD W170.09
LDNOT T1321
OR T1345
ANDLD
ORLD
ANDLD
OUT 2123.06
LD TR0
LD 2089.00
OR W170.09
ANDLD
OUT TR0
LDNOT T1321
OR T1345
ANDLD
OUT 2123.07
LD TR0
ANDNOT P_On
OUT 2121.10
; rung 689
LDNOT 2121.10
OUT 2121.09
; rung 690: ********** 吹込/排気処理 **********
LD W175.13
AND W175.14
OR W264.12
OUT W175.15

; rung 691
LD 2030.06
OUT 410.00
; rung 692
LD 2030.07
OUT 410.01
; rung 693
LD 2030.08
OUT 410.02
; rung 694
LD 2030.00
OUT 410.03
; rung 695
LD 2030.01
OUT 410.04
; rung 696
LD 2030.02
OUT 410.05
; rung 697
LD 2032.06
OUT 410.06
; rung 698
LD 2032.07
OUT 410.07
; rung 699
LD 2032.08
OUT 410.08
; rung 700
LD 2032.00
OUT 410.09
; rung 701
LD 2032.01
OUT 410.10
; rung 702
LD 2032.02
OUT 410.11

; rung 703: ********** 左吹込処理 **********
LD W223.07
OR W189.08
AND W170.00
AND W356.08
AND T0021
ANDNOT W223.00
OUT W189.08
DIFU(013) W175.04
TIM 1120 D1120
AND T1120
OUT W189.09
TIM 1121 D1121
AND T1121
OUT W189.10
DIFU(013) W170.10
TIM 1122 D1122
; rung 704
LD W48.14
LD W48.12
ANDNOT T1113
ORLD
AND H5.05
AND T0021
ANDNOT W189.01
OUT W48.12
TIM 1112 D1112
AND T1112
TIM 1113 D1113
; rung 705
LD T1112
ANDNOT T1113
AND H5.05
OUT W48.10
; rung 706: --- 手動吹込/排気処理 ---
LD W170.13
AND W193.14
OUT TR0
AND H2.00
OUT TR1
AND 2069.03
OUT W37.00
LD TR1
AND 2069.02
OUT W37.01
LD TR0
AND H2.01
OUT TR1
AND 2069.05
OUT W37.02
LD TR1
AND 2069.04
OUT W37.03
LD TR0
AND H2.04
OUT TR0
AND 2069.07
OUT W37.04
LD TR0
AND 2069.06
OUT W37.05

; rung 707
LD W170.13
AND W193.14
OUT TR0
AND H2.08
OUT TR1
AND 2072.09
OUT W36.10
LD TR1
AND 2072.08
OUT W36.02
LD TR0
AND H2.09
OUT TR1
AND 2072.11
OUT W36.11
LD TR1
AND 2072.10
OUT W36.03
LD TR0
AND H2.12
OUT TR1
AND 2072.13
OUT W36.04
LD TR1
AND 2072.12
OUT W36.05
LD TR0
AND H2.13
OUT TR0
AND 2072.15
OUT W36.12
LD TR0
AND 2072.14
OUT W36.13
; rung 708
LDNOT W37.00
ANDNOT W37.02
ANDNOT W37.04
ANDNOT W36.10
ANDNOT W36.11
ANDNOT W36.04
ANDNOT W36.12
OUTNOT W37.06
; rung 709
LDNOT W37.01
ANDNOT W37.03
ANDNOT W37.05
ANDNOT W36.02
ANDNOT W36.03
ANDNOT W36.05
ANDNOT W36.13
OUTNOT W37.07
; rung 710: ----- 左冷却吹込処理 ----- / 冷却吹込電磁弁は冷却ｴｱｰを流し配管を冷やして置く。 / 吹込開始直前まで吹込、吹込遅延中停止。吹込開始で吹込、排気開始で停止。排気完了遅延後また吹込開始。
LD W175.04
OR W37.08
AND T0021
ANDNOT T0045
OUT TR0
OUT W37.08
ANDNOT T1120
OUT W37.09
LD TR0
AND T1121
OUT W37.10
LD TR0
AND T1122
TIM 0045 #30
; rung 711
LD W37.08
ANDNOT T1121
OR W37.06
OR W48.10
AND W356.08
AND W193.14
OUT W37.11
; rung 712
LD W37.11
LDNOT W37.09
ANDNOT W37.10
AND W175.06
ORLD
AND W356.08
AND W175.15
OUT 2102.04

; rung 713: --- 左No.1針ﾉｽﾞﾙ吹込処理 --- / 排気中も吹込電磁弁ONし配管内ｴｱｰを抜く
LD W223.07
OR W37.12
AND T1101
ANDNOT W223.00
OUT W37.12
TIM 1123 D1123
; rung 714
LDNOT T1122
AND W189.10
LD W37.00
LD T1123
ANDNOT T1121
ANDNOT 2030.09
ORLD
OR W48.10
AND W175.15
ORLD
AND W193.14
ANDNOT W283.00
AND H2.00
OUT 2030.06
; rung 715
LD P_On
ANDNOT 16.11
AND 16.10
AND W193.05
AND H3.01
OUT W283.00
; rung 716
LD T1123
ANDNOT T1121
LDNOT T1122
AND W189.10
ORLD
AND W193.14
AND T0021
AND H2.00
AND H4.00
TIM 1126 D1126
AND T1126
AND W223.04
OUT W38.05
; rung 717: --- 左No.2針ﾉｽﾞﾙ吹込処理 --- / 排気中も吹込電磁弁ONし配管内ｴｱｰを抜く
LD W223.07
OR W37.14
AND T1101
ANDNOT W223.00
OUT W37.14
TIM 1124 D1124
; rung 718
LDNOT T1122
AND W189.10
LD W37.02
LD T1124
ANDNOT T1121
ANDNOT 2030.10
ORLD
OR W48.10
AND W175.15
ORLD
AND W193.14
ANDNOT W283.00
AND H2.01
OUT 2030.07
; rung 719
LD T1124
ANDNOT T1121
LDNOT T1122
AND W189.10
ORLD
AND W193.14
AND T0021
AND H2.01
AND H4.02
TIM 1127 D1127
AND T1127
AND W223.04
OUT W37.15

; rung 720: --- 左No.3針ﾉｽﾞﾙ吹込処理 --- / 排気中も吹込電磁弁ONし配管内ｴｱｰを抜く
LD W223.07
OR W36.00
AND T1101
ANDNOT W223.00
OUT W36.00
TIM 1125 D1125
; rung 721
LDNOT T1122
AND W189.10
LD W37.04
LD T1125
ANDNOT T1121
ANDNOT 2030.11
ORLD
OR W48.10
AND W175.15
ORLD
AND W193.14
ANDNOT W283.00
AND H2.04
OUT 2030.08
; rung 722
LD T1125
ANDNOT T1121
LDNOT T1122
AND W189.10
ORLD
AND W193.14
AND T0021
AND H2.04
AND H4.04
TIM 1128 D1128
AND T1128
AND W223.04
OUT W36.01
; rung 723: --- 左No.4針ﾉｽﾞﾙ吹込処理 --- / 排気中も吹込電磁弁ONし配管内ｴｱｰを抜く
LD W223.07
OR W22.03
AND T1101
ANDNOT W223.00
OUT W22.03
TIM 1180 D1180
; rung 724
LDNOT T1122
AND W189.10
LD W36.10
LD T1180
ANDNOT T1121
ANDNOT 2030.12
ORLD
OR W48.10
AND W175.15
ORLD
AND W193.14
ANDNOT W283.00
AND H2.08
OUT 2030.00
; rung 725
LD T1180
ANDNOT T1121
LDNOT T1122
AND W189.10
ORLD
AND W193.14
AND T0021
AND H2.08
AND H4.06
TIM 1184 D1184
AND T1184
AND W223.04
OUT W22.04

; rung 726: --- 左No.5針ﾉｽﾞﾙ吹込処理 --- / 排気中も吹込電磁弁ONし配管内ｴｱｰを抜く
LD W223.07
OR W22.05
AND T1101
ANDNOT W223.00
OUT W22.05
TIM 1181 D1181
; rung 727
LDNOT T1122
AND W189.10
LD W36.11
LD T1181
ANDNOT T1121
ANDNOT 2030.13
ORLD
OR W48.10
AND W175.15
ORLD
AND W193.14
AND H2.09
OUT 2030.01
; rung 728
LD T1181
ANDNOT T1121
LDNOT T1122
AND W189.10
ORLD
AND W193.14
AND T0021
AND H2.09
AND H4.08
TIM 1185 D1185
AND T1185
AND W223.04
OUT W22.06
; rung 729: --- 左No.6針ﾉｽﾞﾙ吹込処理 --- / 排気中も吹込電磁弁ONし配管内ｴｱｰを抜く
LD W223.07
OR W36.06
AND T1101
ANDNOT W223.00
OUT W36.06
TIM 1182 D1182
; rung 730
LDNOT T1122
AND W189.10
LD W36.04
LD T1182
ANDNOT T1121
ANDNOT 2030.14
ORLD
OR W48.10
AND W175.15
ORLD
AND W193.14
AND H2.12
OUT 2030.02
; rung 731
LD T1182
ANDNOT T1121
LDNOT T1122
AND W189.10
ORLD
AND W193.14
AND T0021
AND H2.12
AND H4.10
TIM 1186 D1186
AND T1186
AND W223.04
OUT W36.07

; rung 732: --- 左No.7針ﾉｽﾞﾙ吹込処理 --- / 排気中も吹込電磁弁ONし配管内ｴｱｰを抜く
LD W223.07
OR W22.07
AND T1101
ANDNOT W223.00
OUT W22.07
TIM 1183 D1183
; rung 733
LDNOT T1122
AND W189.10
LD W36.12
LD T1183
ANDNOT T1121
ANDNOT 2030.15
ORLD
OR W48.10
AND W175.15
ORLD
AND W193.14
AND H2.13
OUT 2030.03
; rung 734
LD T1183
ANDNOT T1121
LDNOT T1122
AND W189.10
ORLD
AND W193.14
AND T0021
AND H2.13
AND H4.12
TIM 1187 D1187
AND T1187
AND W223.04
OUT W22.08
; rung 735: --- 左No.1針ﾉｽﾞﾙ排気処理 ---
LDNOT T1122
AND W189.10
ANDNOT H5.12
LD W38.05
AND H4.00
ANDNOT H5.12
ORLD
LDNOT W38.12
AND W38.05
AND H5.12
ORLD
OR W37.01
AND W193.14
AND H2.00
OUT 2030.09
; rung 736: --- 左No.2針ﾉｽﾞﾙ排気処理 ---
LDNOT T1122
AND W189.10
LD W37.15
AND H4.02
ORLD
OR W37.03
AND W193.14
AND H2.01
OUT 2030.10

; rung 737: --- 左No.3針ﾉｽﾞﾙ排気処理 ---
LDNOT T1122
AND W189.10
ANDNOT H5.12
LD W36.01
AND H4.04
ANDNOT W38.12
ANDNOT H5.12
ORLD
LD W36.01
AND H4.04
AND W38.12
AND H5.12
ORLD
OR W37.05
AND W193.14
AND H2.04
OUT 2030.11
; rung 738
LD H5.12
AND W36.01
ANDNOT W189.10
ANDNOT T0293
TIM 0292 #450
AND T0292
OUT W38.12
TIM 0293 #450
; rung 739: --- 左No.4針ﾉｽﾞﾙ排気処理 ---
LDNOT T1122
AND W189.10
LD W22.04
AND H4.06
ORLD
OR W36.02
AND W193.14
AND H2.08
OUT 2030.12
; rung 740: --- 左No.5針ﾉｽﾞﾙ排気処理 ---
LDNOT T1122
AND W189.10
LD W22.06
AND H4.08
ORLD
OR W36.03
AND W193.14
AND H2.09
OUT 2030.13
; rung 741: --- 左No.6針ﾉｽﾞﾙ排気処理 ---
LDNOT T1122
AND W189.10
LD W36.07
AND H4.10
ORLD
OR W36.05
AND W193.14
AND H2.12
OUT 2030.14

; rung 742: --- 左No.7針ﾉｽﾞﾙ排気処理 ---
LDNOT T1122
AND W189.10
LD W22.08
AND H4.12
ORLD
OR W36.13
AND W193.14
AND H2.13
OUT 2030.15
; rung 743: --- 左排気/冷却排気処理 ---
LDNOT T1122
AND W189.10
AND W356.08
AND W193.14
OUT 2102.05
; rung 744
LD 2030.09
OR 2030.10
OR 2030.11
OR 2030.12
OR 2030.13
OR 2030.14
OR 2030.15
OR 2102.05
AND W193.14
OUT 2031.04
; rung 745: --- 左ﾊﾞｲﾊﾟｽ排気 --- / ﾊﾞｲﾊﾟｽ排気弁はｴｱ冷却装置の配管ﾗｲﾝが暖まらない様に排気弁を吹込遅延前及び吹込時以外常時開く。 / ｴｱ冷却装置が停止するとﾊﾞｲﾊﾟｽ弁が閉じる為、吹込圧力検出している配管に圧が残ってしまう。 / 残圧を無くす為ﾊﾞｲﾊﾟｽ弁切遅延を追加。但しﾊﾟｲﾛｯﾄ圧が無いと電磁弁ONしても動かない。
LDNOT W175.06
TIM 0047 #30
; rung 746
LD W175.06
ORNOT T0047
ANDNOT W37.09
LDNOT W37.11
OR W283.00
ANDLD
OR 2102.05
AND W193.14
OUT 2031.05

; rung 747: ********** 右吹込処理 **********
LD W225.04
OR W319.08
AND W170.01
AND W356.09
AND T0021
ANDNOT W224.13
OUT W319.08
DIFU(013) W175.05
TIM 1320 D1320
AND T1320
OUT W319.09
TIM 1321 D1321
AND T1321
OUT W319.10
DIFU(013) W300.10
TIM 1322 D1322
; rung 748
LD W48.15
LD W48.13
ANDNOT T1313
ORLD
AND H5.07
AND T0021
ANDNOT W319.01
OUT W48.13
TIM 1312 D1312
AND T1312
TIM 1313 D1313
; rung 749
LD T1312
ANDNOT T1313
AND H5.07
OUT W48.11
; rung 750: --- 手動吹込/排気処理 ---
LD W170.13
AND W193.14
OUT TR0
AND H2.02
OUT TR1
AND 2089.03
OUT W35.00
LD TR1
AND 2089.02
OUT W35.01
LD TR0
AND H2.03
OUT TR1
AND 2089.05
OUT W35.02
LD TR1
AND 2089.04
OUT W35.03
LD TR0
AND H2.06
OUT TR0
AND 2089.07
OUT W35.04
LD TR0
AND 2089.06
OUT W35.05

; rung 751
LD W170.13
AND W193.14
OUT TR0
AND H2.10
OUT TR1
AND 2092.09
OUT W34.10
LD TR1
AND 2092.08
OUT W34.02
LD TR0
AND H2.11
OUT TR1
AND 2092.11
OUT W34.11
LD TR1
AND 2092.10
OUT W34.03
LD TR0
AND H2.14
OUT TR1
AND 2092.13
OUT W34.04
LD TR1
AND 2092.12
OUT W34.05
LD TR0
AND H2.15
OUT TR0
AND 2092.15
OUT W34.12
LD TR0
AND 2092.14
OUT W34.13
; rung 752
LDNOT W35.00
ANDNOT W35.02
ANDNOT W35.04
ANDNOT W34.10
ANDNOT W34.11
ANDNOT W34.04
ANDNOT W34.12
OUTNOT W35.06
; rung 753
LDNOT W35.01
ANDNOT W35.03
ANDNOT W35.05
ANDNOT W34.02
ANDNOT W34.03
ANDNOT W34.05
ANDNOT W34.13
OUTNOT W35.07
; rung 754: ----- 右冷却吹込処理 ----- / 冷却吹込電磁弁は冷却ｴｱｰを流し配管を冷やして置く。 / 吹込開始直前まで吹込、吹込遅延中停止。吹込開始で吹込、排気開始で停止。排気完了遅延後また吹込開始。
LD W175.05
OR W35.08
AND T0021
ANDNOT T0062
OUT TR0
OUT W35.08
ANDNOT T1320
OUT W35.09
LD TR0
AND T1321
OUT W35.10
LD TR0
AND T1322
TIM 0062 #30
; rung 755
LD W35.08
ANDNOT T1321
OR W35.06
OR W48.11
AND W356.09
AND W193.14
OUT W35.11
; rung 756
LD W35.11
LDNOT W35.09
ANDNOT W35.10
LD W175.07
OR P_Off
ANDLD
ORLD
AND W356.09
AND W175.15
OUT 2122.04

; rung 757: --- 右No.1針ﾉｽﾞﾙ吹込処理 --- / 排気中も吹込電磁弁ONし配管内ｴｱｰを抜く
LD W225.04
OR W35.12
AND T1301
ANDNOT W224.13
OUT W35.12
TIM 1323 D1323
; rung 758
LDNOT T1322
AND W319.10
LD W35.00
LD T1323
ANDNOT T1321
ANDNOT 2032.09
ORLD
OR W48.11
AND W175.15
ORLD
AND W193.14
ANDNOT W283.01
AND H2.02
OUT 2032.06
; rung 759
LD P_On
ANDNOT 16.11
AND 16.10
AND W193.05
AND H3.03
OUT W283.01
; rung 760
LD T1323
ANDNOT T1321
LDNOT T1322
AND W319.10
ORLD
AND W193.14
AND T0021
AND H2.02
AND H4.01
TIM 1326 D1326
AND T1326
AND W225.01
OUT W38.06
; rung 761: --- 右No.2針ﾉｽﾞﾙ吹込処理 --- / 排気中も吹込電磁弁ONし配管内ｴｱｰを抜く
LD W225.04
OR W35.14
AND T1301
ANDNOT W224.13
OUT W35.14
TIM 1324 D1324
; rung 762
LDNOT T1322
AND W319.10
LD W35.02
LD T1324
ANDNOT T1321
ANDNOT 2032.10
ORLD
OR W48.11
AND W175.15
ORLD
AND W193.14
ANDNOT W283.01
AND H2.03
OUT 2032.07
; rung 763
LD T1324
ANDNOT T1321
LDNOT T1322
AND W319.10
ORLD
AND W193.14
AND T0021
AND H2.03
AND H4.03
TIM 1327 D1327
AND T1327
AND W225.01
OUT W35.15

; rung 764: --- 右No.3針ﾉｽﾞﾙ吹込処理 --- / 排気中も吹込電磁弁ONし配管内ｴｱｰを抜く
LD W225.04
OR W34.00
AND T1301
ANDNOT W224.13
OUT W34.00
TIM 1325 D1325
; rung 765
LDNOT T1322
AND W319.10
LD W35.04
LD T1325
ANDNOT T1321
ANDNOT 2032.11
ORLD
OR W48.11
AND W175.15
ORLD
AND W193.14
ANDNOT W283.01
AND H2.06
OUT 2032.08
; rung 766
LD T1325
ANDNOT T1321
LDNOT T1322
AND W319.10
ORLD
AND W193.14
AND T0021
AND H2.06
AND H4.05
TIM 1328 D1328
AND T1328
AND W225.01
OUT W34.01
; rung 767: --- 右No.4針ﾉｽﾞﾙ吹込処理 --- / 排気中も吹込電磁弁ONし配管内ｴｱｰを抜く
LD W225.04
OR W23.03
AND T1301
ANDNOT W224.13
OUT W23.03
TIM 1380 D1380
; rung 768
LD=(300) D2200 #30
AND 16.11
ANDNOT T1441
AND 2122.12
AND 2130.09
AND 2128.13
AND 2128.12
AND W190.12
OR W24.10
ANDNOT T1441
OUT W24.10
TIM 1440 #30
AND T1440
TIM 1441 #30
; rung 769
LD=(300) D2200 #30
AND 2122.03
AND 2128.13
AND 2130.09
OR W24.11
ANDNOT T1443
OUT W24.11
TIM 1442 #40
AND T1442
TIM 1443 #100

; rung 770
LDNOT T1322
AND W319.10
LD W34.10
LD T1380
ANDNOT T1321
ANDNOT 2032.12
ORLD
OR W48.11
AND W175.15
ORLD
AND W193.14
ANDNOT W283.01
AND H2.10
LD<>(305) D2200 #30
AND=(300) D2200 #30
LD T1440
OR T1442
ANDLD
ORLD
OUT 2032.00
; rung 771
LD T1380
ANDNOT T1321
LDNOT T1322
AND W319.10
ORLD
AND W193.14
AND T0021
AND H2.10
AND H4.07
TIM 1384 D1384
AND T1384
AND W225.01
OUT W23.04
; rung 772: --- 右No.5針ﾉｽﾞﾙ吹込処理 --- / 排気中も吹込電磁弁ONし配管内ｴｱｰを抜く
LD W225.04
OR W23.05
AND T1301
ANDNOT W224.13
OUT W23.05
TIM 1381 D1381
; rung 773
LDNOT T1322
AND W319.10
LD W34.11
LD T1381
ANDNOT T1321
ANDNOT 2032.13
ORLD
OR W48.11
AND W175.15
ORLD
AND W193.14
AND H2.11
OUT 2032.01
; rung 774
LD T1381
ANDNOT T1321
LDNOT T1322
AND W319.10
ORLD
AND W193.14
AND T0021
AND H2.11
AND H4.09
TIM 1385 D1385
AND T1385
AND W225.01
OUT W23.06
; rung 775: --- 右No.6針ﾉｽﾞﾙ吹込処理 --- / 排気中も吹込電磁弁ONし配管内ｴｱｰを抜く
LD W225.04
OR W34.06
AND T1301
ANDNOT W224.13
OUT W34.06
TIM 1382 D1382

; rung 776
LDNOT T1322
AND W319.10
LD W34.04
LD T1382
ANDNOT T1321
ANDNOT 2032.14
ORLD
OR W48.11
AND W175.15
ORLD
AND W193.14
AND H2.14
OUT 2032.02
; rung 777
LD T1382
ANDNOT T1321
LDNOT T1322
AND W319.10
ORLD
AND W193.14
AND T0021
AND H2.14
AND H4.11
TIM 1386 D1386
AND T1386
AND W225.01
OUT W34.07
; rung 778: --- 右No.7針ﾉｽﾞﾙ吹込処理 --- / 排気中も吹込電磁弁ONし配管内ｴｱｰを抜く
LD W225.04
OR W23.07
AND T1301
ANDNOT W224.13
OUT W23.07
TIM 1383 D1383
; rung 779
LDNOT T1322
AND W319.10
LD W34.12
LD T1383
ANDNOT T1321
ANDNOT 2032.15
ORLD
OR W48.11
AND W175.15
ORLD
AND W193.14
AND H2.15
OUT 2032.03
; rung 780
LD T1383
ANDNOT T1321
LDNOT T1322
AND W319.10
ORLD
AND W193.14
AND T0021
AND H2.15
AND H4.13
TIM 1387 D1387
AND T1387
AND W225.01
OUT W23.08
; rung 781: --- 右No.1針ﾉｽﾞﾙ排気処理 ---
LDNOT T1322
AND W319.10
ANDNOT H5.14
LD W38.06
AND H4.01
ANDNOT H5.14
ORLD
LDNOT W38.11
AND W38.06
AND H5.14
ORLD
OR W35.01
AND W193.14
AND H2.02
OUT 2032.09

; rung 782: --- 右No.2針ﾉｽﾞﾙ排気処理 ---
LDNOT T1322
AND W319.10
LD W35.15
AND H4.03
ORLD
OR W35.03
AND W193.14
AND H2.03
OUT 2032.10
; rung 783: --- 右No.3針ﾉｽﾞﾙ排気処理 ---
LDNOT T1322
AND W319.10
ANDNOT H5.14
LD W34.01
AND H4.05
ANDNOT W38.11
ANDNOT H5.14
ORLD
LD W34.01
AND H4.05
AND W38.11
AND H5.14
ORLD
OR W35.05
AND W193.14
AND H2.06
OUT 2032.11
; rung 784
LD H5.14
AND W34.01
ANDNOT W319.10
ANDNOT T0283
TIM 0282 #450
AND T0282
OUT W38.11
TIM 0283 #450
; rung 785: --- 右No.4針ﾉｽﾞﾙ排気処理 ---
LDNOT T1322
AND W319.10
LD W23.04
AND H4.07
ORLD
OR W34.02
AND W193.14
AND H2.10
OUT 2032.12
; rung 786: --- 右No.5針ﾉｽﾞﾙ排気処理 ---
LDNOT T1322
AND W319.10
LD W23.06
AND H4.09
ORLD
OR W34.03
AND W193.14
AND H2.11
OUT 2032.13

; rung 787: --- 右No.6針ﾉｽﾞﾙ排気処理 ---
LDNOT T1322
AND W319.10
LD W34.07
AND H4.11
ORLD
OR W34.05
AND W193.14
AND H2.14
OUT 2032.14
; rung 788: --- 右No.7針ﾉｽﾞﾙ排気処理 ---
LDNOT T1322
AND W319.10
LD W23.08
AND H4.13
ORLD
OR W34.13
AND W193.14
AND H2.15
OUT 2032.15
; rung 789: --- 右排気/冷却排気処理 ---
LDNOT T1322
AND W319.10
AND W356.09
AND W193.14
OUT 2122.05
; rung 790
LD 2032.09
OR 2032.10
OR 2032.11
OR 2032.12
OR 2032.13
OR 2032.14
OR 2032.15
OR 2122.05
AND W193.14
OUT 2033.04
; rung 791: --- 右ﾊﾞｲﾊﾟｽ排気 --- / ﾊﾞｲﾊﾟｽ排気弁はｴｱ冷却装置の配管ﾗｲﾝが暖まらない様に排気弁を吹込遅延前及び吹込時以外常時開く。 / ｴｱ冷却装置が停止するとﾊﾞｲﾊﾟｽ弁が閉じる為、吹込圧力検出している配管に圧が残ってしまう。 / 残圧を無くす為ﾊﾞｲﾊﾟｽ弁切遅延を追加。但しﾊﾟｲﾛｯﾄ圧が無いと電磁弁ONしても動かない。
LDNOT W175.07
TIM 0064 #30

; rung 792
LD W175.07
OR P_Off
ORNOT T0064
ANDNOT W35.09
LDNOT W35.11
OR W283.01
ANDLD
OR 2122.05
AND W193.14
OUT 2033.05
; rung 793: ********** 金型ﾁﾗｰ冷却水処理 **********
LD H8.05
AND T0021
ANDNOT W193.01
ORNOT H8.05
AND W170.00
AND H8.04
OUT 2101.07
OUT 2101.08
; rung 794
LD H8.07
AND T0021
ANDNOT W193.01
ORNOT H8.07
AND W170.01
AND H8.06
OUT 2121.07
OUT 2121.08
; rung 795: ********** 左前ﾉｽﾞﾙ打込処理 **********
LD H5.00
OR H1.08
AND T0021
AND W170.00
OUT TR0
LD H5.00
AND W223.06
LD H1.08
AND W165.00
ORLD
OR W184.00
ANDLD
ANDNOT W223.00
ANDNOT W184.01
OUT W184.00
TIM 1110 D1110
LD TR0
LD W184.00
AND T1110
OR W184.01
ANDLD
ANDNOT W184.03
ANDNOT W223.00
OUT W184.01
DIFU(013) W184.05
LD TR0
LD H5.00
AND W183.15
LD H1.08
AND W223.04
ORLD
AND W184.01
OR W184.02
ANDLD
ANDNOT W223.00
OUT W184.02
TIM 1111 D1111
LD TR0
AND W184.02
AND T1111
ANDNOT W223.00
OUT W184.03
LD TR0
AND W223.00
ANDNOT T0086
OUT W184.04
; rung 796
LD H5.00
OR H1.08
ANDNOT T1122
AND T0021
AND W184.01
OUT W184.06

; rung 797
LD W190.05
AND T0511
TIM 0027 #3
; rung 798
LD H5.00
OR H1.08
AND W170.13
AND W193.14
OUT TR0
AND 2068.03
AND T0027
OUT W184.09
LD TR0
AND 2068.02
OUT W184.15
; rung 799
LD W184.06
OR W184.09
LD T0027
OR W184.06
ANDLD
LD H5.00
OR H1.08
ANDLD
AND W193.14
ANDNOT 2101.05
OUT 2101.04
; rung 800
LD W184.15
LD W184.03
OR W184.04
AND T0021
ORLD
LD H5.00
OR H1.08
ANDLD
ANDNOT 2101.04
ANDNOT W189.01
AND W193.14
OUT 2101.05
; rung 801: ********** 右前ﾉｽﾞﾙ打込処理 **********
LD H5.02
OR H1.10
AND T0021
AND W170.01
OUT TR0
LD H5.02
AND W225.03
LD H1.10
AND W165.02
ORLD
OR W314.00
ANDLD
ANDNOT W224.13
ANDNOT W314.01
OUT W314.00
TIM 1310 D1310
LD TR0
LD W314.00
AND T1310
OR W314.01
ANDLD
ANDNOT W314.03
ANDNOT W224.13
OUT W314.01
DIFU(013) W314.05
LD TR0
LD H5.02
AND W313.15
LD H1.10
AND W225.01
ORLD
AND W314.01
OR W314.02
ANDLD
ANDNOT W224.13
OUT W314.02
TIM 1311 D1311
LD TR0
AND W314.02
AND T1311
ANDNOT W224.13
OUT W314.03
LD TR0
AND W224.13
ANDNOT T0042
OUT W314.04
; rung 802
LD H5.02
OR H1.10
ANDNOT T1322
AND T0021
AND W314.01
OUT W314.06

; rung 803
LD W190.06
AND T0511
TIM 0028 #3
; rung 804
LD H5.02
OR H1.10
AND W170.13
AND W193.14
OUT TR0
AND 2088.03
AND T0028
OUT W314.09
LD TR0
AND 2088.02
OUT W314.15
; rung 805
LD W314.06
OR W314.09
LD T0028
OR W314.06
ANDLD
LD H5.02
OR H1.10
ANDLD
AND W193.14
ANDNOT 2121.05
OUT 2121.04
; rung 806
LD W314.15
LD W314.03
OR W314.04
AND T0021
ORLD
LD H5.02
OR H1.10
ANDLD
ANDNOT 2121.04
ANDNOT W319.01
AND W193.14
OUT 2121.05
; rung 807: ********** 左後ﾉｽﾞﾙ打込処理 **********
LD H5.01
OR H1.08
AND T0021
AND W170.00
OUT TR0
LD H5.01
AND W223.06
LD H1.08
AND W165.00
ORLD
OR W185.00
ANDLD
ANDNOT W223.00
ANDNOT W185.01
OUT W185.00
TIM 1114 D1114
LD TR0
LD W185.00
AND T1114
OR W185.01
ANDLD
ANDNOT W185.03
ANDNOT W223.00
OUT W185.01
LD TR0
LD H5.01
AND W183.15
LD H1.08
AND W223.04
ORLD
AND W185.01
OR W185.02
ANDLD
ANDNOT W223.00
OUT W185.02
TIM 1115 D1115
LD TR0
AND W185.02
AND T1115
ANDNOT W223.00
OUT W185.03
LD TR0
AND W223.00
ANDNOT T0086
OUT W185.04
; rung 808
LD H5.01
OR H1.08
ANDNOT T1122
AND T0021
AND W185.01
OUT W185.06

; rung 809
LD H5.01
OR H1.08
AND W170.13
AND W193.14
OUT TR0
AND 2068.05
AND T0027
OUT W185.09
LD TR0
AND 2068.04
OUT W185.15
; rung 810
LD W185.06
OR W185.09
LD T0027
OR W185.06
ANDLD
LD H5.01
OR H1.08
ANDLD
AND W193.14
ANDNOT 2103.04
OUT 2101.06
; rung 811
LD W185.15
LD W185.03
OR W185.04
AND T0021
ORLD
LD H5.01
OR H1.08
ANDLD
ANDNOT 2101.06
ANDNOT W189.01
AND W193.14
OUT 2103.04
; rung 812: ********** 右後ﾉｽﾞﾙ打込処理 **********
LD H5.03
OR H1.10
AND T0021
AND W170.01
OUT TR0
LD H5.03
AND W225.03
LD H1.10
AND W165.02
ORLD
OR W315.00
ANDLD
ANDNOT W224.13
ANDNOT W315.01
OUT W315.00
TIM 1314 D1314
LD TR0
LD W315.00
AND T1314
OR W315.01
ANDLD
ANDNOT W315.03
ANDNOT W224.13
OUT W315.01
LD TR0
LD H5.03
AND W313.15
LD H1.10
AND W225.01
ORLD
AND W315.01
OR W315.02
ANDLD
ANDNOT W224.13
OUT W315.02
TIM 1315 D1315
LD TR0
AND W315.02
AND T1315
ANDNOT W224.13
OUT W315.03
LD TR0
AND W224.13
ANDNOT T0042
OUT W315.04
; rung 813
LD H5.03
OR H1.10
ANDNOT T1322
AND T0021
AND W315.01
OUT W315.06
; rung 814
LD H5.03
OR H1.10
AND W170.13
AND W193.14
OUT TR0
AND 2088.05
AND T0028
OUT W315.09
LD TR0
AND 2088.04
OUT W315.15

; rung 815
LD W315.06
OR W315.09
LD T0028
OR W315.06
ANDLD
LD H5.03
OR H1.10
ANDLD
AND W193.14
ANDNOT 2123.04
OUT 2121.06
; rung 816
LD W315.15
LD W315.03
OR W315.04
AND T0021
ORLD
LD H5.03
OR H1.10
ANDLD
ANDNOT 2121.06
ANDNOT W319.01
AND W193.14
OUT 2123.04
; rung 817: ********** 左ｲﾝｻｰﾄｸﾗﾝﾌﾟ1処理 ********** / ﾛﾎﾞｯﾄからｲﾝｻｰﾄﾁｬｯｸ閉信号が来たら自動に関係なく閉する。
LD 473.05
LDNOT H1.01
ORNOT 2108.06
AND W165.00
AND T0021
ORLD
AND H9.08
DIFU(013) W159.12
; rung 818
LD W159.12
OR W160.12
AND H9.08
ANDNOT 2108.06
ANDNOT W223.04
AND W193.15
LDNOT W189.01
OR P_On
ANDLD
OUT W160.12
TIM 1150 D1150
; rung 819
LD T1150
LD W170.13
AND 2069.09
ORLD
AND W193.15
AND H9.08
ANDNOT 2108.06
OUT W58.01
; rung 820
LD T1122
OR W160.13
AND H9.08
ANDNOT 2108.07
AND T0021
ANDNOT W189.01
OUT W160.13
TIM 1151 D1151
; rung 821
LD T1151
LD W170.13
AND 2069.08
ORLD
AND W193.15
AND H9.08
ANDNOT 2108.07
OUT W58.03

; rung 822
LD W58.01
LD W58.03
%OR W193.15
KEEP(011) H13.00
; rung 823
LD H13.00
AND W193.15
OUT 2102.03
OUT 2105.09
; rung 824
LDNOT H13.00
AND W193.15
OUT 2102.12
OUT 2105.10
; rung 825: ********** 右ｲﾝｻｰﾄｸﾗﾝﾌﾟ1処理 ********** / ﾛﾎﾞｯﾄからｲﾝｻｰﾄﾁｬｯｸ閉信号が来たら自動に関係なく閉する。
LD 473.06
LDNOT H1.01
ORNOT 2128.06
AND W165.02
AND T0021
ORLD
AND H9.10
DIFU(013) W159.13
; rung 826
LD W159.13
OR W160.14
AND H9.10
ANDNOT 2128.06
ANDNOT W225.01
AND W193.15
LDNOT W319.01
OR P_On
ANDLD
OUT W160.14
TIM 1350 D1350
; rung 827
LD T1350
LD W170.13
AND 2089.09
ORLD
AND W193.15
AND H9.10
ANDNOT 2128.06
OUT W58.05
; rung 828
LD T1322
OR W160.15
AND H9.10
ANDNOT 2128.07
AND T0021
ANDNOT W319.01
AND W193.15
OUT W160.15
TIM 1351 D1351
; rung 829
LD T1351
LD W170.13
AND 2089.08
ORLD
AND W193.15
AND H9.10
ANDNOT 2128.07
OUT W58.07

; rung 830
LD W58.05
LD W58.07
%OR W193.15
KEEP(011) H13.01
; rung 831
LD H13.01
AND W193.15
OUT 2122.03
OUT 2125.09
; rung 832
LDNOT H13.01
AND W193.15
OUT 2122.12
OUT 2125.10
; rung 833: ********** 左ｲﾝｻｰﾄｸﾗﾝﾌﾟ2処理 ********** / ﾛﾎﾞｯﾄからｲﾝｻｰﾄﾁｬｯｸ閉信号が来たら自動に関係なく閉する。
LD 473.09
LDNOT H1.01
ORNOT 2109.02
AND W165.00
AND T0021
ORLD
AND H9.09
DIFU(013) W56.02
; rung 834
LD W56.02
OR W56.03
AND H9.09
ANDNOT 2109.02
ANDNOT W223.04
LDNOT W189.01
OR P_On
ANDLD
OUT W56.03
TIM 1152 D1152
; rung 835
LD T1152
LD W170.13
AND 2070.05
ORLD
AND W193.15
AND H9.09
ANDNOT 2109.02
OUT W56.04
; rung 836
LD T1122
OR W56.06
AND H9.09
ANDNOT 2109.03
AND T0021
ANDNOT W189.01
OUT W56.06
TIM 1153 D1153
; rung 837
LD T1153
LD W170.13
AND 2070.04
ORLD
AND W193.15
AND H9.09
ANDNOT 2109.03
OUT W56.07

; rung 838
LD W56.04
LD W56.07
KEEP(011) H13.02
; rung 839
LD H13.02
AND W193.15
OUT 2103.01
OUT 2105.11
; rung 840
LDNOT H13.02
AND W193.15
OUT 2103.02
OUT 2105.12
; rung 841: ********** 右ｲﾝｻｰﾄｸﾗﾝﾌﾟ1処理 ********** / ﾛﾎﾞｯﾄからｲﾝｻｰﾄﾁｬｯｸ閉信号が来たら自動に関係なく閉する。
LD 473.10
LDNOT H1.01
ORNOT 2129.02
AND W165.02
AND T0021
ORLD
AND H9.11
DIFU(013) W56.09
; rung 842
LD W56.09
OR W56.10
AND H9.11
ANDNOT 2129.02
ANDNOT W225.01
LDNOT W319.01
OR P_On
ANDLD
OUT W56.10
TIM 1352 D1352
; rung 843
LD T1352
LD W170.13
AND 2090.05
ORLD
AND W193.15
AND H9.11
ANDNOT 2129.02
OUT W56.11
; rung 844
LD T1322
OR W56.13
AND H9.11
ANDNOT 2129.03
AND T0021
ANDNOT W319.01
OUT W56.13
TIM 1353 D1353
; rung 845
LD T1353
LD W170.13
AND 2090.04
ORLD
AND W193.15
AND H9.11
ANDNOT 2129.03
OUT W56.14

; rung 846
LD W56.11
LD W56.14
KEEP(011) H13.03
; rung 847
LD H13.03
AND W193.15
OUT 2123.01
OUT 2125.11
; rung 848
LDNOT H13.03
AND W193.15
OUT 2123.02
OUT 2125.12
; rung 849: ********** 補機共通信号 **********
LD W170.00
AND T0021
AND W165.01
AND W223.00
DIFU(013) W50.04
; rung 850
LD W170.01
AND T0021
AND W165.03
AND W224.13
DIFU(013) W50.05
; rung 851
LD W170.00
AND T0021
AND W165.00
OUT TR0
AND W223.07
DIFU(013) W50.08
LD TR0
DIFU(013) W50.10
; rung 852
LD W170.01
AND T0021
AND W165.02
OUT TR0
AND W225.04
DIFU(013) W50.09
LD TR0
DIFU(013) W50.11
; rung 853
LD W170.00
OUT TR0
AND T1122
DIFU(013) W50.06
LD TR0
AND W183.15
DIFU(013) W50.12
; rung 854
LD W170.01
OUT TR0
AND T1322
DIFU(013) W50.07
LD TR0
AND W313.15
DIFU(013) W50.13
; rung 855
LD W170.09
ANDNOT 16.09
ANDNOT W193.04
OUT W51.15

; rung 856: ********** 左ｽﾀﾝﾄﾞｵﾌ1処理 ********** / 電磁弁はLS　ONしてもSV OFFしない/回路は残す
LD H9.00
AND W170.00
AND W193.05
OUT TR0
LD T1101
OR W30.00
ANDLD
ANDNOT W30.01
OUT W30.00
TIM 1190 D1190
LD TR0
LD W30.00
AND T1190
OR W30.01
ANDLD
ANDNOT W30.02
OUT W30.01
LD TR0
LD W30.01
AND W50.06
OR W30.02
ANDLD
ANDNOT W223.00
OUT W30.02
TIM 1191 D1191
LD TR0
AND W30.02
AND T1191
ANDNOT W223.00
OUT W30.03
LD TR0
AND W223.00
ANDNOT T0086
OUT W30.04
; rung 857
LD W170.13
AND 2069.15
OR W30.01
LDNOT 2034.04
OR P_On
ANDLD
AND H9.00
AND W193.15
ANDNOT 2102.02
OUT 2102.01
; rung 858
LD W170.13
AND 2069.14
OR W30.03
OR W30.04
LDNOT 2034.05
OR P_On
ANDLD
AND H9.00
AND W193.15
ANDNOT 2102.01
OUT 2102.02

; rung 859: ********** 左ｽﾀﾝﾄﾞｵﾌ2処理 ********** / 電磁弁はLS　ONしてもSV OFFしない/回路は残す
LD H9.01
AND W170.00
AND W193.05
OUT TR0
LD T1101
OR W30.07
ANDLD
ANDNOT W30.08
OUT W30.07
TIM 1192 D1192
LD TR0
LD W30.07
AND T1192
OR W30.08
ANDLD
ANDNOT W30.09
OUT W30.08
LD TR0
LD W30.08
AND W50.06
OR W30.09
ANDLD
ANDNOT W223.00
OUT W30.09
TIM 1193 D1193
LD TR0
AND W30.09
AND T1193
ANDNOT W223.00
OUT W30.10
LD TR0
AND W223.00
ANDNOT T0086
OUT W30.11
; rung 860
LD W170.13
AND 2070.11
OR W30.08
LDNOT 2035.14
OR P_On
ANDLD
AND H9.01
AND W193.15
ANDNOT 2102.00
OUT 2101.15
; rung 861
LD W170.13
AND 2070.10
OR W30.10
OR W30.11
LDNOT 2035.15
OR P_On
ANDLD
AND H9.01
AND W193.15
ANDNOT 2101.15
OUT 2102.00

; rung 862: ********** 左ｽﾀﾝﾄﾞｵﾌ3処理 ********** / 電磁弁はLS　ONしてもSV OFFしない/回路は残す
LD H9.04
AND W170.00
AND W193.05
OUT TR0
LD T1101
OR W32.09
ANDLD
ANDNOT W32.10
OUT W32.09
TIM 1194 D1194
LD TR0
LD W32.09
AND T1194
OR W32.10
ANDLD
ANDNOT W32.11
OUT W32.10
LD TR0
LD W32.10
AND W50.06
OR W32.11
ANDLD
ANDNOT W223.00
OUT W32.11
TIM 1195 D1195
LD TR0
AND W32.11
AND T1195
ANDNOT W223.00
OUT W32.12
LD TR0
AND W223.00
ANDNOT T0086
OUT W32.15
; rung 863
LD W32.10
LD W170.13
AND 2069.13
ORLD
LDNOT 2034.00
OR P_On
ANDLD
AND H9.04
AND W193.15
ANDNOT 2101.01
OUT 2100.15
; rung 864
LD W32.12
OR W32.15
LD W170.13
AND 2069.12
ORLD
LDNOT 2034.01
OR P_On
ANDLD
AND H9.04
AND W193.15
ANDNOT 2100.15
OUT 2101.01

; rung 865: ********** 左ｽﾀﾝﾄﾞｵﾌ4処理 ********** / 電磁弁はLS　ONしてもSV OFFしない/回路は残す
LD H9.05
AND W170.00
AND W193.05
OUT TR0
LD T1101
OR W33.09
ANDLD
ANDNOT W33.10
OUT W33.09
TIM 1196 D1196
LD TR0
LD W33.09
AND T1196
OR W33.10
ANDLD
ANDNOT W33.11
OUT W33.10
LD TR0
LD W33.10
AND W50.06
OR W33.11
ANDLD
ANDNOT W223.00
OUT W33.11
TIM 1197 D1197
LD TR0
AND W33.11
AND T1197
ANDNOT W223.00
OUT W33.12
LD TR0
AND W223.00
ANDNOT T0086
OUT W33.15
; rung 866
LD W33.10
LD W170.13
AND 2070.09
ORLD
LDNOT 2034.02
OR P_On
ANDLD
AND H9.05
AND W193.15
ANDNOT 2101.12
OUT 2101.03
; rung 867
LD W33.12
OR W33.15
LD W170.13
AND 2070.08
ORLD
LDNOT 2034.03
OR P_On
ANDLD
AND H9.05
AND W193.15
ANDNOT 2101.03
OUT 2101.12

; rung 868: ********** 右ｽﾀﾝﾄﾞｵﾌ1処理 ********** / 電磁弁はLS　ONしてもSV OFFしない/回路は残す
LD H9.02
AND W170.01
AND W193.05
OUT TR0
LD T1301
OR W44.00
ANDLD
ANDNOT W44.01
OUT W44.00
TIM 1390 D1390
LD TR0
LD W44.00
AND T1390
OR W44.01
ANDLD
ANDNOT W44.02
OUT W44.01
LD TR0
LD W44.01
AND W50.07
OR W44.02
ANDLD
ANDNOT W224.13
OUT W44.02
TIM 1391 D1391
LD TR0
AND W44.02
AND T1391
ANDNOT W224.13
OUT W44.03
LD TR0
AND W224.13
ANDNOT T0042
OUT W44.04
; rung 869
LD W170.13
AND 2089.15
OR W44.01
LDNOT 2036.04
OR P_On
ANDLD
AND H9.02
AND W193.15
ANDNOT 2122.02
OUT 2122.01
; rung 870
LD W170.13
AND 2089.14
OR W44.03
OR W44.04
LDNOT 2036.05
OR P_On
ANDLD
AND H9.02
AND W193.15
ANDNOT 2122.01
OUT 2122.02

; rung 871: ********** 右ｽﾀﾝﾄﾞｵﾌ2処理 ********** / 電磁弁はLS　ONしてもSV OFFしない/回路は残す
LD H9.03
AND W170.01
AND W193.05
OUT TR0
LD T1301
OR W44.07
ANDLD
ANDNOT W44.08
OUT W44.07
TIM 1392 D1392
LD TR0
LD W44.07
AND T1392
OR W44.08
ANDLD
ANDNOT W44.09
OUT W44.08
LD TR0
LD W44.08
AND W50.07
OR W44.09
ANDLD
ANDNOT W224.13
OUT W44.09
TIM 1393 D1393
LD TR0
AND W44.09
AND T1393
ANDNOT W224.13
OUT W44.10
LD TR0
AND W224.13
ANDNOT T0042
OUT W44.11
; rung 872
LD W170.13
AND 2090.11
OR W44.08
LDNOT 2037.14
OR P_On
ANDLD
AND H9.03
AND W193.15
ANDNOT 2122.00
OUT 2121.15
; rung 873
LD W170.13
AND 2090.10
OR W44.10
OR W44.11
LDNOT 2037.15
OR P_On
ANDLD
AND H9.03
AND W193.15
ANDNOT 2121.15
OUT 2122.00

; rung 874: ********** 右ｽﾀﾝﾄﾞｵﾌ3処理 ********** / 電磁弁はLS　ONしてもSV OFFしない/回路は残す
LD H9.06
AND W170.01
AND W193.05
OUT TR0
LD T1301
OR W46.09
ANDLD
ANDNOT W46.10
OUT W46.09
TIM 1394 D1394
LD TR0
LD W46.09
AND T1394
OR W46.10
ANDLD
ANDNOT W46.11
OUT W46.10
LD TR0
LD W46.10
AND W50.07
OR W46.11
ANDLD
ANDNOT W224.13
OUT W46.11
TIM 1395 D1395
LD TR0
AND W46.11
AND T1395
ANDNOT W224.13
OUT W46.12
LD TR0
AND W224.13
ANDNOT T0042
OUT W46.15
; rung 875
LD W46.10
LD W170.13
AND 2089.13
ORLD
LDNOT 2036.00
OR P_On
ANDLD
AND H9.06
AND W193.15
ANDNOT 2121.01
OUT 2120.15
; rung 876
LD W46.12
OR W46.15
LD W170.13
AND 2089.12
ORLD
LDNOT 2036.01
OR P_On
ANDLD
AND H9.06
AND W193.15
ANDNOT 2120.15
OUT 2121.01

; rung 877: ********** 右ｽﾀﾝﾄﾞｵﾌ4処理 ********** / 電磁弁はLS　ONしてもSV OFFしない/回路は残す
LD H9.07
AND W170.01
AND W193.05
OUT TR0
LD T1301
OR W25.09
ANDLD
ANDNOT W25.10
OUT W25.09
TIM 1396 D1396
LD TR0
LD W25.09
AND T1396
OR W25.10
ANDLD
ANDNOT W25.11
OUT W25.10
LD TR0
LD W25.10
AND W50.07
OR W25.11
ANDLD
ANDNOT W224.13
OUT W25.11
TIM 1397 D1397
LD TR0
AND W25.11
AND T1397
ANDNOT W224.13
OUT W25.12
LD TR0
AND W224.13
ANDNOT T0042
OUT W25.15
; rung 878
LD W25.10
LD W170.13
AND 2090.09
ORLD
LDNOT 2036.02
OR P_On
ANDLD
AND H9.07
AND W193.15
ANDNOT 2121.12
OUT 2121.03
; rung 879
LD W25.12
OR W25.15
LD W170.13
AND 2090.08
ORLD
LDNOT 2036.03
OR P_On
ANDLD
AND H9.07
AND W193.15
ANDNOT 2121.03
OUT 2121.12
; rung 880: ********** 左ｴｼﾞｪｸﾀ1処理 **********
LD H3.08
AND W51.15
OUT TR0
LD W50.06
OR W30.14
ANDLD
ANDNOT W30.15
OUT W30.14
TIM 1160 D1160
LD TR0
LD W30.14
AND T1160
OR W30.15
ANDLD
ANDNOT W31.00
OUT W30.15
TIM 1161 D1161
LD TR0
LD W30.15
AND T1161
OR W31.00
ANDLD
ANDNOT W30.14
OUT W31.00

; rung 881
LD W170.13
AND 2071.03
OR W30.15
AND H3.08
AND W193.14
ANDNOT 2031.10
OUT 2031.09
; rung 882
LD W170.13
AND 2071.02
OR W31.00
AND H3.08
AND W193.14
ANDNOT 2031.09
OUT 2031.10
; rung 883: ********** 左ｴｼﾞｪｸﾀ2処理 **********
LD H3.09
AND W51.15
OUT TR0
LD W50.06
OR W31.01
ANDLD
ANDNOT W31.02
OUT W31.01
TIM 1162 D1162
LD TR0
LD W31.01
AND T1162
OR W31.02
ANDLD
ANDNOT W31.03
OUT W31.02
TIM 1163 D1163
LD TR0
LD W31.02
AND T1163
OR W31.03
ANDLD
ANDNOT W31.01
OUT W31.03
; rung 884
LD W170.13
AND 2071.05
OR W31.02
AND H3.09
AND W193.14
ANDNOT 2031.12
OUT 2031.11
; rung 885
LD W170.13
AND 2071.04
OR W31.03
AND H3.09
AND W193.14
ANDNOT 2031.11
OUT 2031.12

; rung 886: ********** 左ｴｼﾞｪｸﾀ3処理 **********
LD H3.12
AND W51.15
OUT TR0
LD W50.06
OR W31.04
ANDLD
ANDNOT W31.05
OUT W31.04
TIM 1164 D1164
LD TR0
LD W31.04
AND T1164
OR W31.05
ANDLD
ANDNOT W31.06
OUT W31.05
TIM 1165 D1165
LD TR0
LD W31.05
AND T1165
OR W31.06
ANDLD
ANDNOT W31.04
OUT W31.06
; rung 887
LD W170.13
AND 2071.07
OR W31.05
AND H3.12
AND W193.14
ANDNOT 2100.05
OUT 2100.04
; rung 888
LD W170.13
AND 2071.06
OR W31.06
AND H3.12
AND W193.14
ANDNOT 2100.04
OUT 2100.05
; rung 889: ********** 左ｴｼﾞｪｸﾀ4処理 **********
LD H3.13
AND W51.15
OUT TR0
LD W50.06
OR W31.07
ANDLD
ANDNOT W31.08
OUT W31.07
TIM 1166 D1166
LD TR0
LD W31.07
AND T1166
OR W31.08
ANDLD
ANDNOT W31.09
OUT W31.08
TIM 1167 D1167
LD TR0
LD W31.08
AND T1167
OR W31.09
ANDLD
ANDNOT W31.07
OUT W31.09
; rung 890
LD W170.13
AND 2071.09
OR W31.08
AND H3.13
AND W193.14
ANDNOT 2100.07
OUT 2100.06

; rung 891
LD W170.13
AND 2071.08
OR W31.09
AND H3.13
AND W193.14
ANDNOT 2100.06
OUT 2100.07
; rung 892: ********** 右ｴｼﾞｪｸﾀ1処理 **********
LD H3.10
AND W51.15
OUT TR0
LD W50.07
OR W44.14
ANDLD
ANDNOT W44.15
OUT W44.14
TIM 1360 D1360
LD TR0
LD W44.14
AND T1360
OR W44.15
ANDLD
ANDNOT W45.00
OUT W44.15
TIM 1361 D1361
LD TR0
LD W44.15
AND T1361
OR W45.00
ANDLD
ANDNOT W44.14
OUT W45.00
; rung 893
LD W170.13
AND 2091.03
OR W44.15
AND H3.10
AND W193.14
ANDNOT 2033.10
OUT 2033.09
; rung 894
LD W170.13
AND 2091.02
OR W45.00
AND H3.10
AND W193.14
ANDNOT 2033.09
OUT 2033.10
; rung 895: ********** 右ｴｼﾞｪｸﾀ2処理 **********
LD H3.11
AND W51.15
OUT TR0
LD W50.07
OR W45.01
ANDLD
ANDNOT W45.02
OUT W45.01
TIM 1362 D1362
LD TR0
LD W45.01
AND T1362
OR W45.02
ANDLD
ANDNOT W45.03
OUT W45.02
TIM 1363 D1363
LD TR0
LD W45.02
AND T1363
OR W45.03
ANDLD
ANDNOT W45.01
OUT W45.03

; rung 896
LD W170.13
AND 2091.05
OR W45.02
AND H3.11
AND W193.14
ANDNOT 2033.12
OUT 2033.11
; rung 897
LD W170.13
AND 2091.04
OR W45.03
AND H3.11
AND W193.14
ANDNOT 2033.11
OUT 2033.12
; rung 898: ********** 右ｴｼﾞｪｸﾀ3処理 **********
LD H3.14
AND W51.15
OUT TR0
LD W50.07
OR W45.04
ANDLD
ANDNOT W45.05
OUT W45.04
TIM 1364 D1364
LD TR0
LD W45.04
AND T1364
OR W45.05
ANDLD
ANDNOT W45.06
OUT W45.05
TIM 1365 D1365
LD TR0
LD W45.05
AND T1365
OR W45.06
ANDLD
ANDNOT W45.04
OUT W45.06
; rung 899
LD W170.13
AND 2091.07
OR W45.05
AND H3.14
AND W193.14
ANDNOT 2120.05
OUT 2120.04
; rung 900
LD W170.13
AND 2091.06
OR W45.06
AND H3.14
AND W193.14
ANDNOT 2120.04
OUT 2120.05

; rung 901: ********** 右ｴｼﾞｪｸﾀ4処理 **********
LD H3.15
AND W51.15
OUT TR0
LD W50.07
OR W45.07
ANDLD
ANDNOT W45.08
OUT W45.07
TIM 1366 D1366
LD TR0
LD W45.07
AND T1366
OR W45.08
ANDLD
ANDNOT W45.09
OUT W45.08
TIM 1367 D1367
LD TR0
LD W45.08
AND T1367
OR W45.09
ANDLD
ANDNOT W45.07
OUT W45.09
; rung 902
LD W170.13
AND 2091.09
OR W45.08
AND H3.15
AND W193.14
ANDNOT 2120.07
OUT 2120.06
; rung 903
LD W170.13
AND 2091.08
OR W45.09
AND H3.15
AND W193.14
ANDNOT 2120.06
OUT 2120.07
; rung 904: ********** 左ﾎｰｽｸﾗﾝﾌﾟ処理 ********** / 電磁弁はLS　ONしてもSV OFFしない/回路は残す
LD H7.01
AND W193.05
OUT TR0
LD W50.06
OR W31.10
ANDLD
ANDNOT W31.11
OUT W31.10
TIM 1168 D1168
LD TR0
LD W31.10
AND T1168
OR W31.11
ANDLD
ANDNOT W31.12
OUT W31.11
TIM 1169 D1169
LD TR0
LD W31.11
AND T1169
OR W31.12
ANDLD
ANDNOT W31.10
OUT W31.12
; rung 905
LD W170.13
AND 2070.12
OR W31.11
LDNOT 2034.15
OR P_On
ANDLD
AND H7.01
AND W193.15
ANDNOT 2101.13
OUT 2101.14

; rung 906
LD W170.13
AND 2070.13
OR W31.12
LDNOT 2034.14
OR P_On
ANDLD
AND H7.01
AND W193.15
ANDNOT 2101.14
OUT 2101.13
; rung 907: ********** 右ﾎｰｽｸﾗﾝﾌﾟ処理 ********** / 電磁弁はLS　ONしてもSV OFFしない/回路は残す
LD H7.03
AND W193.05
OUT TR0
LD W50.07
OR W45.10
ANDLD
ANDNOT W45.11
OUT W45.10
TIM 1368 D1368
LD TR0
LD W45.10
AND T1368
OR W45.11
ANDLD
ANDNOT W45.12
OUT W45.11
TIM 1369 D1369
LD TR0
LD W45.11
AND T1369
OR W45.12
ANDLD
ANDNOT W45.10
OUT W45.12
; rung 908
LD W170.13
AND 2090.12
OR W45.11
LDNOT 2036.15
OR P_On
ANDLD
AND H7.03
AND W193.15
ANDNOT 2121.13
OUT 2121.14
; rung 909
LD W170.13
AND 2090.13
OR W45.12
LDNOT 2036.14
OR P_On
ANDLD
AND H7.03
AND W193.15
ANDNOT 2121.14
OUT 2121.13
; rung 910: ********** 左ｺﾝﾌﾟﾚｯｼｮﾝ1処理 ********** / 電磁弁はLS　ONしてもSV OFFしない/回路は残す
LD H9.12
AND W193.05
OUT TR0
LD W50.04
OR W32.00
ANDLD
ANDNOT W32.02
OUT W32.00
LD TR0
LD W32.00
AND W50.08
OR W32.01
ANDLD
ANDNOT W32.02
ANDNOT W223.00
OUT W32.01
TIM 1140 D1140
LD TR0
LD W32.01
AND T1140
OR W32.02
ANDLD
ANDNOT W32.04
ANDNOT W223.00
OUT W32.02

; rung 911
LD H9.12
AND W193.05
OUT TR0
LD W32.02
AND W50.06
OR W32.03
ANDLD
ANDNOT W32.04
ANDNOT W223.00
OUT W32.03
TIM 1141 D1141
LD TR0
LD W32.03
AND T1141
OR W32.04
ANDLD
ANDNOT W223.00
OUT W32.04
; rung 912
LD W32.02
LD W170.13
AND 2069.11
ORLD
LDNOT 2108.08
OR P_On
ANDLD
AND H9.12
AND W193.15
ANDNOT 2102.14
OUT 2102.13
; rung 913
LD W32.00
OR W32.04
LD W170.13
AND 2069.10
ORLD
LDNOT 2108.09
OR P_On
ANDLD
AND H9.12
AND W193.15
ANDNOT 2102.13
OUT 2102.14
; rung 914: ********** 右ｺﾝﾌﾟﾚｯｼｮﾝ1処理 ********** / 電磁弁はLS　ONしてもSV OFFしない/回路は残す
LD H9.14
AND W193.05
OUT TR0
LD W50.05
OR W46.00
ANDLD
ANDNOT W46.02
OUT W46.00
LD TR0
LD W46.00
AND W50.09
OR W46.01
ANDLD
ANDNOT W46.02
ANDNOT W224.13
OUT W46.01
TIM 1340 D1340
LD TR0
LD W46.01
AND T1340
OR W46.02
ANDLD
ANDNOT W46.04
ANDNOT W224.13
OUT W46.02
; rung 915
LD H9.14
AND W193.05
OUT TR0
LD W46.02
AND W50.07
OR W46.03
ANDLD
ANDNOT W46.04
ANDNOT W224.13
OUT W46.03
TIM 1341 D1341
LD TR0
LD W46.03
AND T1341
OR W46.04
ANDLD
ANDNOT W224.13
OUT W46.04

; rung 916
LD W46.02
LD W170.13
AND 2089.11
ORLD
LDNOT 2128.08
OR P_On
ANDLD
AND H9.14
AND W193.15
ANDNOT 2122.14
OUT 2122.13
; rung 917
LD W46.00
OR W46.04
LD W170.13
AND 2089.10
ORLD
LDNOT 2128.09
OR P_On
ANDLD
AND H9.14
AND W193.15
ANDNOT 2122.13
OUT 2122.14
; rung 918: ********** 左ｺﾝﾌﾟﾚｯｼｮﾝ2処理 ********** / 電磁弁はLS　ONしてもSV OFFしない/回路は残す
LD H9.13
AND W193.05
OUT TR0
LD W50.04
OR W33.00
ANDLD
ANDNOT W33.02
OUT W33.00
LD TR0
LD W33.00
AND W50.08
OR W33.01
ANDLD
ANDNOT W33.02
ANDNOT W223.00
OUT W33.01
TIM 1142 D1142
LD TR0
LD W33.01
AND T1142
OR W33.02
ANDLD
ANDNOT W33.04
ANDNOT W223.00
OUT W33.02
; rung 919
LD H9.13
AND W193.05
OUT TR0
LD W33.02
AND W50.06
OR W33.03
ANDLD
ANDNOT W33.04
ANDNOT W223.00
OUT W33.03
TIM 1143 D1143
LD TR0
LD W33.03
AND T1143
OR W33.04
ANDLD
ANDNOT W223.00
OUT W33.04
; rung 920
LD W33.02
LD W170.13
AND 2070.07
ORLD
LDNOT 2110.00
OR P_On
ANDLD
AND H9.13
AND W193.15
ANDNOT 2103.15
OUT 2103.14
; rung 921
LD W33.00
OR W33.04
LD W170.13
AND 2070.06
ORLD
LDNOT 2110.01
OR P_On
ANDLD
AND H9.13
AND W193.15
ANDNOT 2103.14
OUT 2103.15

; rung 922: ********** 右ｺﾝﾌﾟﾚｯｼｮﾝ2処理 ********** / 電磁弁はLS　ONしてもSV OFFしない/回路は残す
LD H9.15
AND W193.05
OUT TR0
LD W50.05
OR W25.00
ANDLD
ANDNOT W25.02
OUT W25.00
LD TR0
LD W25.00
AND W50.09
OR W25.01
ANDLD
ANDNOT W25.02
ANDNOT W224.13
OUT W25.01
TIM 1342 D1342
LD TR0
LD W25.01
AND T1342
OR W25.02
ANDLD
ANDNOT W25.04
ANDNOT W224.13
OUT W25.02
; rung 923
LD H9.15
AND W193.05
OUT TR0
LD W25.02
AND W50.07
OR W25.03
ANDLD
ANDNOT W25.04
ANDNOT W224.13
OUT W25.03
TIM 1343 D1343
LD TR0
LD W25.03
AND T1343
OR W25.04
ANDLD
ANDNOT W224.13
OUT W25.04
; rung 924
LD W25.02
LD W170.13
AND 2090.07
ORLD
LDNOT 2130.00
OR P_On
ANDLD
AND H9.15
AND W193.15
ANDNOT 2123.15
OUT 2123.14
; rung 925
LD W25.00
OR W25.04
LD W170.13
AND 2090.06
ORLD
LDNOT 2130.01
OR P_On
ANDLD
AND H9.15
AND W193.15
ANDNOT 2123.14
OUT 2123.15

; rung 926: ********** 左ｺﾝﾊﾞﾑ吸着処理 **********
LD H2.05
AND W193.05
OUT TR0
LD W183.04
OR W340.00
ANDLD
ANDNOT W340.01
OUT W340.00
TIM 1136 D1136
LD TR0
LD W340.00
AND T1136
OR W340.01
ANDLD
ANDNOT W340.02
OUT W340.01
TIM 1137 D1137
LD TR0
LD W340.01
AND T1137
OR W340.02
ANDLD
ANDNOT W223.00
OUT W340.02
; rung 927
LD W340.01
LD W170.13
AND 2073.01
ORLD
AND H2.05
AND W193.14
ANDNOT 2030.05
AND P_Off
OUT 2030.04
; rung 928
LD W340.02
LD W170.13
AND 2073.00
ORLD
AND H2.05
AND W193.14
ANDNOT 2030.04
AND P_Off
OUT 2030.05
; rung 929: ********** 右ｺﾝﾊﾞﾑ吸着処理 **********
LD H2.07
AND W193.05
OUT TR0
LD W313.04
OR W340.03
ANDLD
ANDNOT W340.04
OUT W340.03
TIM 1336 D1336
LD TR0
LD W340.03
AND T1336
OR W340.04
ANDLD
ANDNOT W340.05
OUT W340.04
TIM 1337 D1337
LD TR0
LD W340.04
AND T1337
OR W340.05
ANDLD
ANDNOT W224.13
OUT W340.05
; rung 930
LD W340.04
LD W170.13
AND 2093.01
ORLD
AND H2.07
AND W193.14
ANDNOT 2032.05
AND P_Off
OUT 2032.04

; rung 931
LD W340.05
LD W170.13
AND 2093.00
ORLD
AND H2.07
AND W193.14
ANDNOT 2032.04
AND P_Off
OUT 2032.05
; rung 932: ********** 左ﾈｼﾞ入子1処理 ********** / ﾀｲﾏ設定次第では自動終了しても回っている / 入子出時間を長く設定した場合、戻りタイマとラップするので注意する事
LDNOT P_On
AND W50.06
OR W223.00
OR W66.00
LD H60.08
ANDNOT 2109.09
LDNOT H60.08
ANDNOT T1201
ORLD
ANDLD
AND H7.04
AND W51.15
OUT W66.00
TIM 1200 D1200
AND T1200
OUT W66.01
TIM 1201 D1201
; rung 933
LDNOT P_On
AND W50.12
OR W50.06
OR W66.02
LD H60.08
ANDNOT 2109.12
LDNOT H60.08
ANDNOT T1203
ORLD
ANDLD
AND H7.04
AND W51.15
OUT W66.02
TIM 1202 D1202
AND T1202
OUT W66.03
TIM 1203 D1203
; rung 934
LD W170.13
AND 2073.03
OR W66.01
ANDNOT 2109.09
AND W193.14
ANDNOT 2104.01
OUT 2104.00
; rung 935
LD W170.13
AND 2073.02
OR W66.03
ANDNOT 2109.12
AND W193.14
ANDNOT 2104.00
OUT 2104.01

; rung 936: ********** 左ﾈｼﾞ入子2処理 ********** / ﾀｲﾏ設定次第では自動終了しても回っている / 入子出時間を長く設定した場合、戻りタイマとラップするので注意する事
LDNOT P_On
AND W50.06
OR W223.00
OR W66.04
LD H60.09
ANDNOT 2034.06
LDNOT H60.09
ANDNOT T1205
ORLD
ANDLD
AND H7.05
AND W51.15
OUT W66.04
TIM 1204 D1204
AND T1204
OUT W66.05
TIM 1205 D1205
; rung 937
LDNOT P_On
AND W50.12
OR W50.06
OR W66.06
LD H60.09
ANDNOT 2034.07
LDNOT H60.09
ANDNOT T1207
ORLD
ANDLD
AND H7.05
AND W51.15
OUT W66.06
TIM 1206 D1206
AND T1206
OUT W66.07
TIM 1207 D1207
; rung 938
LD W170.13
AND 2073.05
OR W66.05
ANDNOT 2034.06
AND W193.14
ANDNOT 2104.03
AND P_Off
OUT 2104.02
; rung 939
LD W170.13
AND 2073.04
OR W66.07
ANDNOT 2034.07
AND W193.14
ANDNOT 2104.02
AND P_Off
OUT 2104.03
; rung 940: ********** 右ﾈｼﾞ入子1処理 ********** / ﾀｲﾏ設定次第では自動終了しても回っている / 入子出時間を長く設定した場合、戻りタイマとラップするので注意する事
LDNOT P_On
AND W50.07
OR W224.13
OR W66.08
LD H70.08
ANDNOT 2129.09
LDNOT H70.08
ANDNOT T1401
ORLD
ANDLD
AND H7.06
AND W51.15
OUT W66.08
TIM 1400 D1400
AND T1400
OUT W66.09
TIM 1401 D1401

; rung 941
LDNOT P_On
AND W50.13
OR W50.07
OR W66.10
LD H70.08
ANDNOT 2129.12
LDNOT H70.08
ANDNOT T1403
ORLD
ANDLD
AND H7.06
AND W51.15
OUT W66.10
TIM 1402 D1402
AND T1402
OUT W66.11
TIM 1403 D1403
; rung 942
LD W170.13
AND 2093.03
OR W66.09
LDNOT P_On
AND W170.09
ANDNOT T0021
AND 2128.07
ANDNOT 2128.06
ORLD
ANDNOT 2129.09
AND W193.14
ANDNOT 2124.01
OUT 2124.00
; rung 943
LD W170.13
AND 2093.02
OR W66.11
ANDNOT 2129.12
AND W193.14
ANDNOT 2124.00
OUT 2124.01
; rung 944: ********** 右ﾈｼﾞ入子2処理 ********** / ﾀｲﾏ設定次第では自動終了しても回っている / 入子出時間を長く設定した場合、戻りタイマとラップするので注意する事
LDNOT P_On
AND W50.07
OR W224.13
OR W66.12
LD H70.09
ANDNOT 2036.06
LDNOT H70.09
ANDNOT T1405
ORLD
ANDLD
AND H7.07
AND W51.15
OUT W66.12
TIM 1404 D1404
AND T1404
OUT W66.13
TIM 1405 D1405
; rung 945
LDNOT P_On
AND W50.13
OR W50.07
OR W66.14
LD H70.09
ANDNOT 2036.07
LDNOT H70.09
ANDNOT T1407
ORLD
ANDLD
AND H7.07
AND W51.15
OUT W66.14
TIM 1406 D1406
AND T1406
OUT W66.15
TIM 1407 D1407

; rung 946
LD W170.13
AND 2093.05
OR W66.13
ANDNOT 2036.06
AND W193.14
ANDNOT 2124.03
AND P_Off
OUT 2124.02
; rung 947
LD W170.13
AND 2093.04
OR W66.15
ANDNOT 2036.07
AND W193.14
ANDNOT 2124.02
AND P_Off
OUT 2124.03
; rung 948: ********** 左下ﾉｽﾞﾙ(ｴｱ）処理 **********
LD H5.04
AND T0021
OUT TR0
LD W189.01
OR W155.00
ANDLD
ANDNOT W223.00
ANDNOT W155.01
OUT W155.00
TIM 1178 D1178
LD TR0
LD W155.00
AND T1178
OR W155.01
ANDLD
ANDNOT W223.00
ANDNOT W155.03
OUT W155.01
LD TR0
LD W155.01
AND W223.04
OR W155.02
ANDLD
ANDNOT W223.00
OUT W155.02
TIM 1179 D1179
LD TR0
AND W155.02
AND T1179
ANDNOT W223.00
OUT W155.03
LD TR0
AND W223.00
ANDNOT T0086
OUT W155.04
; rung 949
LD W170.13
AND H5.04
OUT TR0
AND 2073.07
OUT W155.05
LD TR0
AND 2073.06
OUT W155.06

; rung 950: ********** 右下ﾉｽﾞﾙ(ｴｱ）処理 **********
LD H5.06
AND T0021
OUT TR0
LD W319.01
OR W155.07
ANDLD
ANDNOT W224.13
ANDNOT W155.08
OUT W155.07
TIM 1378 D1378
LD TR0
LD W155.07
AND T1378
OR W155.08
ANDLD
ANDNOT W224.13
ANDNOT W155.10
OUT W155.08
LD TR0
LD W155.08
AND W225.01
OR W155.09
ANDLD
ANDNOT W224.13
OUT W155.09
TIM 1379 D1379
LD TR0
AND W155.09
AND T1379
ANDNOT W224.13
OUT W155.10
LD TR0
AND W224.13
ANDNOT T0042
OUT W155.11
; rung 951
LD W170.13
AND H5.06
OUT TR0
AND 2093.07
OUT W155.12
LD TR0
AND 2093.06
OUT W155.13
; rung 952: ********** 旋回ﾊﾞｲﾊﾟｽ処理 ********** / 差圧で旋回動く可能性があるのでｽﾀｰﾄｱｯﾌﾟ条件に旋回位置決めﾋﾟﾝ打込追加 / またｽﾀｰﾄｱｯﾌﾟ完了後、左右使用切り替える可能性があるので必ず制御は両方入れる / 旋回ﾊﾞｲﾊﾟｽ制御入で旋回ﾊﾞｲﾊﾟｽ電磁弁ON及び比例弁#0FA0出力後、２秒後に旋回電磁弁ON / 旋回ﾊﾞｲﾊﾟｽ制御切で旋回電磁弁OFF、２秒後にﾊﾞｲﾊﾟｽ電磁弁OFFし比例弁#0000出力
LD W165.01
AND T0020
ANDNOT T0021
AND 2110.09
OUT W49.00
; rung 953
LD W165.03
AND T0020
ANDNOT T0021
AND 2130.09
OUT W49.01
; rung 954
LD H8.13
AND T0020
DIFU(013) W49.02
DIFD(014) W49.03
; rung 955
LD W49.02
OR W49.10
ANDNOT W49.09
AND T0020
OUT W49.10
DIFU(013) W49.04
TIM 0500 #20
AND T0500
DIFU(013) W49.05

; rung 956
LD W49.03
OR W49.06
LD 14.10
OR 14.11
ANDLD
AND T0020
OUT W49.06
TIM 0501 #20
AND T0501
DIFU(013) W49.07
; rung 957
LD W49.04
LD W49.08
ANDNOT W49.07
ORLD
AND T0020
OUT W49.08
; rung 958
LD W49.05
LD W49.09
ANDNOT W49.03
ORLD
AND T0020
OUT TR0
OUT W49.09
AND W49.00
OUT W49.11
LD TR0
AND W49.01
OUT W49.12
; rung 959
LD 2103.03
TIM 1157 D1157
; rung 960
LD P_Off
OUT W240.03
; rung 961
LD W57.15
AND H8.14
OR W240.00
ANDNOT W240.02
ANDNOT T0021
AND W240.03
OUT W240.00
; rung 962
LD W240.00
ANDNOT T0256
TIM 0255 #50
ANDNOT T0255
OUT W240.01
; rung 963
LD T0255
TIM 0256 #30

; rung 964
LD W240.01
LD W57.14
OR W259.10
CNT 0100 #2
; rung 965
LD C0100
DIFU(013) W240.02
; rung 966
LD W49.08
AND W49.00
LD 2103.03
ANDNOT 2110.09
ANDNOT P_On
ORLD
LDNOT P_On
AND 2110.09
OR T1157
LD T0021
OR P_On
ANDLD
ORLD
OUT 14.10
; rung 967
LD 2123.03
TIM 1357 D1357
; rung 968
LD W49.08
AND W49.01
LD 2123.03
ANDNOT 2130.09
ANDNOT P_On
ORLD
LDNOT P_On
AND 2130.09
OR T1357
LD T0021
OR P_On
ANDLD
ORLD
OUT 14.11
; rung 969: ********** 左ｴｷｽﾊﾟﾝﾀﾞ昇降処理 **********
LD 2071.15
DIFU(013) W187.14
; rung 970
LD 2071.14
DIFU(013) W187.15

; rung 971
LD 16.08
CMP(020) D58 D6072
LD P_EQ
OR P_GT
ANDLD
DIFU(013) W162.15
; rung 972
LD W162.15
OR W162.13
AND 2071.15
OUT W162.13
; rung 973
LD W170.13
AND W193.10
AND H8.01
ANDNOT 428.12
ANDNOT 428.13
OUT TR0
LD W187.14
OR 407.14
ANDLD
AND 2071.15
ANDNOT 428.14
ANDNOT 407.15
ANDNOT W162.13
OUT 407.14
LD TR0
LD W187.15
OR 407.15
ANDLD
AND 2071.14
ANDNOT 428.15
ANDNOT 407.14
OUT 407.15
; rung 974
LD P_On
+BC(406) D6072 #10 D676
-BC(416) D6072 #10 D677
; rung 975
LD>=(325) D58 D677
AND<=(315) D58 D676
OUT W164.15
; rung 976
LD P_On
AND>=(325) D58 D6072
OUT W293.01
; rung 977: ********** 右ｴｷｽﾊﾟﾝﾀﾞ昇降処理 **********
LD 2091.15
DIFU(013) W317.14
; rung 978
LD 2091.14
DIFU(013) W317.15

; rung 979
LD 16.08
CMP(020) D59 D6073
LD P_EQ
OR P_GT
ANDLD
DIFU(013) W162.14
; rung 980
LD W162.14
OR W162.12
AND 2091.15
OUT W162.12
; rung 981
LD W170.13
AND W193.10
AND H8.03
ANDNOT 429.12
ANDNOT 429.13
OUT TR0
LD W317.14
OR 408.14
ANDLD
AND 2091.15
ANDNOT 429.14
ANDNOT 408.15
ANDNOT W162.12
OUT 408.14
LD TR0
LD W317.15
OR 408.15
ANDLD
AND 2091.14
ANDNOT 429.15
ANDNOT 408.14
OUT 408.15
; rung 982
LD P_On
+BC(406) D6073 #10 D678
-BC(416) D6073 #10 D679
; rung 983
LD>=(325) D59 D679
AND<=(315) D59 D678
OR P_On
OUT W164.14
; rung 984
LD P_On
AND>=(325) D59 D6073
OUT W293.00
; rung 985: ********** 取出機部分ｼｬｯﾀｰ処理 ********** / ｼｬｯﾀｰ開は取出機前進開始前&後退開始前に開し、前進限到達&後退限到達にてｼｬｯﾀｰ閉する。 / 手動時、取出機前進限又は後退限にいない場合、ｼｬｯﾀｰ閉出来ない。
LD 2043.04
ANDNOT 2046.05
OUT W47.15

; rung 986
LD W47.15
OR W499.03
AND W193.14
AND 2055.00
ANDNOT 2054.08
ANDNOT 2054.01
ANDNOT 2055.11
ANDNOT W499.07
OUT W499.03
; rung 987
LD 2046.05
AND 2054.08
OR W499.07
AND W193.14
AND 2055.00
ANDNOT 2055.12
OUT W499.07
; rung 988
LD 2055.09
ANDNOT 2055.00
LD W499.03
AND 2055.00
ORLD
AND W193.14
ANDNOT 2055.11
ANDNOT 2045.01
OUT 2045.00
; rung 989
LD W499.07
AND 2055.00
LD 2054.00
OR 2054.01
AND 2055.10
ANDNOT 2055.00
ORLD
AND W193.14
ANDNOT 2055.12
ANDNOT 2045.00
AND 12.13
LDNOT 12.15
OR H1.02
ANDLD
OUT 2045.01
; rung 990
LDNOT 12.15
OUT 2045.04
; rung 991: ********** ﾊﾟﾘｿﾝ取出機処理 ********** 自動ｼｬｯﾀｰ特殊仕様 / ﾊﾟﾘｿﾝ取出機のﾁｬｯｸ閉は以前画面タイマ設定で動作していたが光電管検知に変更 / ﾌﾟﾛｸﾞﾗﾑは残してある。取出位置-5.0以下の時、取出機進入不可 但し40.0%以下にしない事 / 取出機前進&後退は自動ｼｬｯﾀｰ開限でなければ移動せず
LD P_On
OUT TR0
CLC(041)
-BC(416) D3073 #50 D2013
AND>(320) D2013 D282
OUT W50.02
LD TR0
AND>=(325) D282 #400
OUT W170.02

; rung 992
LD P_On
OUT TR0
CLC(041)
-BC(416) D3066 #50 D2014
AND>(320) D2014 D232
OUT W50.03
LD TR0
AND>=(325) D232 #400
OUT W170.03
; rung 993
LDNOT T0021
OR W193.02
AND W193.10
AND W170.02
AND W170.03
AND 457.06
AND W181.09
AND W311.09
OUT 2044.06
; rung 994
LD 2054.04
LDNOT P_Off
AND 2054.11
ORLD
AND 2054.00
AND 2055.06
AND 2055.00
AND W177.00
AND 2044.06
DIFU(013) W301.00
; rung 995
LD 17.15
OR W161.09
AND W177.00
OUT W161.09
; rung 996
LD 2054.01
ANDNOT 2043.04
OR W161.08
AND W161.09
OUT W161.08
; rung 997
LD 420.00
OR 420.01
OR 420.02
OR 420.03
OR 420.04
OR 420.05
AND 2044.06
ANDNOT T0021
DIFU(013) W172.15

; rung 998
LD W190.00
OR W358.05
ANDNOT W358.04
AND W225.01
AND W165.03
LD W320.00
OR W358.04
ANDNOT W358.05
AND W223.04
AND W165.01
ORLD
AND W193.02
AND 473.02
ANDNOT 16.10
TIM 0468 #5
AND T0468
DIFU(013) W301.01
; rung 999
LD 17.14
OR 2055.13
ANDNOT 16.10
OR W172.15
OR W301.01
AND 2054.01
LD W177.00
ANDNOT W161.08
ORLD
AND 2055.00
AND 2044.06
OUT W177.00
; rung 1000
LD 2054.01
AND 2054.02
OR W177.01
AND W177.00
AND 2055.00
ANDNOT 2054.00
ANDNOT W177.03
AND 2044.06
OUT W177.01
TIM 1003 D1003
; rung 1001
LD 2055.02
ANDNOT 2055.00
LD T1003
OR T0093
OR T0094
AND W177.01
AND 2055.00
ORLD
AND 2044.06
ANDNOT 2054.00
AND 2054.02
ANDNOT 2046.05
OUT 2046.04
; rung 1002
LD W170.05
OR W170.06
OR W177.03
AND 2043.04
AND 2055.00
AND 2044.06
ANDNOT 2054.01
ANDNOT W177.01
OUT W177.03
; rung 1003
LD W177.03
AND 2055.00
LD 2055.01
ANDNOT 2055.00
ORLD
AND 2044.06
ANDNOT 2054.01
ANDNOT 2046.04
OUT 2046.05
; rung 1004
LD T0511
AND 10.07
ANDNOT W384.00
OUT 2043.02

; rung 1005
LD 2046.04
OR 2046.05
AND 2043.02
ANDNOT W344.01
OUT W57.11
DIFD(014) W57.12
; rung 1006
LD W57.12
OR W57.13
ANDNOT T0488
OUT W57.13
TIM 0488 #10
; rung 1007
LD W57.11
OR W57.13
OUT 2043.03
; rung 1008
LD 2046.05
AND 2054.08
LD 2046.04
AND 2054.07
ORLD
OR 2054.01
OR 2054.00
LD 2046.04
AND 2054.08
LD 2046.05
AND 2054.00
ORLD
KEEP(011) H99.13
; rung 1009
LD W57.11
OUT TR0
AND H99.13
OUT 2046.07
LD TR0
ANDNOT H99.13
OUT 2046.06
; rung 1010
LD 2055.04
OR W177.04
ANDNOT 2055.00
ANDNOT 2055.03
LD W301.00
AND 2055.06
LD 2055.07
ANDNOT 2055.06
ORLD
AND 2054.00
OR W177.04
AND 2055.00
ORLD
AND 2044.06
ANDNOT T0466
OUT W177.04
DIFU(013) W177.05
TIM 1002 D1002

; rung 1011
LD 2046.05
OR W177.07
ANDNOT 2055.00
LD 2054.01
OR W177.07
AND 2055.00
ORLD
ANDNOT T0467
AND 2044.06
ANDNOT W177.05
OUT W177.07
AND 2054.01
TIM 0466 #20
; rung 1012
LD 2054.01
AND 2044.06
TIM 0467 #40
; rung 1013
LD T1002
AND 2044.06
OUT W162.09
; rung 1014
LD T0466
LD 2055.03
ANDNOT 2055.00
ORLD
AND 2044.06
OUT W162.08
; rung 1015
LD W162.09
LD W162.08
KEEP(011) H98.14
; rung 1016
LD H98.14
AND W193.14
OUT 2043.04
; rung 1017
LDNOT H98.14
AND W193.14
OUT 2046.09
; rung 1018
LD 2043.04
OR 2046.05
OUT 2043.05
; rung 1019: ********** 左旋回位置決めﾋﾟﾝ出/戻処理 ********** / 旋回位置決めｼﾘﾝﾀﾞは旋回ﾊﾞｲﾊﾟｽ制御中、手動で戻り不可にした / 当て止めでは取出ロボットがある為、必ず待避側でピンを打込必要がある
LD W193.15
AND W170.13
OUT TR0
LD W165.00
OR W165.01
ANDLD
AND 2071.13
OUT W158.14
LD TR0
AND 2071.12
OUT W158.15

; rung 1020
LD W54.15
OR W165.00
OR W65.08
AND T0021
ANDNOT W161.13
AND H7.09
AND W170.00
OUT TR0
AND W165.01
OUT W65.08
TIM 1159 D1159
AND T1159
DIFU(013) W65.09
LD TR0
AND W165.00
OUT W363.00
TIM 1158 D1158
AND T1158
DIFU(013) W363.01
; rung 1021
LD W170.00
OUT TR0
AND W165.01
OUT TR1
AND W54.12
DIFU(013) W54.14
LD TR1
AND W54.01
DIFU(013) W54.02
LD TR1
AND W193.02
ANDNOT P_On
DIFU(013) W53.02
LD TR0
AND W165.00
AND T1009
DIFU(013) W363.02
; rung 1022
LD W53.02
OR W65.09
OR W363.01
LDNOT T0093
AND W54.02
OR W54.14
OR W363.02
LD W170.13
ANDNOT P_On
ORLD
KEEP(011) H98.10
; rung 1023
LD W158.14
LD H98.10
AND T0021
AND W170.00
ORLD
ANDNOT 2110.09
OUT 2103.03
OUT 2105.13
; rung 1024
LD W158.15
AND 2130.09
AND 16.06
LDNOT H98.10
AND T0021
AND W165.03
AND W170.00
LDNOT H1.01
LD H1.01
AND 2102.03
ORLD
ANDLD
ORLD
ANDNOT 2110.10
OUT 2103.12
OUT 2105.14

; rung 1025: ********** 右旋回位置決めﾋﾟﾝ出/戻処理 ********** / 旋回位置決めｼﾘﾝﾀﾞは旋回ﾊﾞｲﾊﾟｽ制御中、手動で戻り不可にした / 当て止めでは取出ロボットがある為、必ず待避側でピンを打込必要がある
LD W193.15
AND W170.13
OUT TR0
LD W165.02
OR W165.03
ANDLD
AND 2091.13
OUT W159.14
LD TR0
AND 2091.12
OUT W159.15
; rung 1026
LD W55.15
OR W165.02
OR W65.10
AND T0021
ANDNOT W161.12
AND H7.11
AND W170.01
OUT TR0
AND W165.03
OUT W65.10
TIM 1359 D1359
AND T1359
DIFU(013) W65.11
LD TR0
AND W165.02
OUT W363.03
TIM 1358 D1358
AND T1358
DIFU(013) W363.04
; rung 1027
LD W170.01
OUT TR0
AND W165.03
OUT TR1
AND W55.12
DIFU(013) W55.14
LD TR1
AND W55.01
DIFU(013) W55.02
LD TR1
AND W193.02
ANDNOT P_On
DIFU(013) W53.03
LD TR0
AND W165.02
AND T1009
DIFU(013) W363.05
; rung 1028
LD W53.03
OR W65.11
OR W363.04
LDNOT T0094
AND W55.01
OR W55.14
OR W363.05
LD W170.13
ANDNOT P_On
ORLD
KEEP(011) H98.11

; rung 1029
LD W159.14
LD H98.11
AND T0021
AND W170.01
ORLD
ANDNOT 2130.09
OUT 2123.03
OUT 2125.13
; rung 1030
LD W159.15
AND 2110.09
AND 16.04
LDNOT H98.11
AND T0021
AND W165.01
LD W223.04
ORNOT H1.00
ANDLD
LDNOT H1.01
LD H1.01
AND 2122.03
ORLD
ANDLD
AND W170.01
ORLD
ANDNOT 2130.10
OUT 2123.12
OUT 2125.14
; rung 1031: ********** 当て止め処理/旋回停止電磁弁処理 ********** / 前例では押当電磁弁と停止電磁弁同じタイミングとなっていたので遅延タイマで変更可能にした / ----- 左成形機当て止め処理 -----
LD W170.09
OR W22.13
OR W39.04
ANDNOT W175.12
ANDNOT W47.07
AND W193.15
AND W165.00
TIM 0530 D685
AND T0530
OUT W39.04
; rung 1032
LD W170.09
OR W22.14
LD 16.09
ANDNOT H8.13
ORLD
OR W39.05
ANDNOT W175.11
ANDNOT W47.06
AND W193.15
AND W165.01
TIM 0531 D686
AND T0531
OUT W39.05
; rung 1033
LD W39.04
OR W39.05
ANDNOT 14.12
ANDNOT 14.13
AND W193.15
LD 2110.10
OR P_On
ANDLD
LDNOT 2110.09
OR P_On
ANDLD
ANDNOT W394.01
OUT TR0
AND W181.12
ANDNOT W181.14
OUT 22.08
LD TR0
AND W181.14
ANDNOT W181.12
LDNOT T0091
OR P_On
ANDLD
OUT 22.09
DIFU(013) W54.15
; rung 1034: ---------- 左成形機旋回停止処理 ----------
LD W170.09
OR W22.13
OR W47.00
ANDNOT W175.12
ANDNOT W47.07
AND W193.15
AND W165.00
TIM 0390 D706
AND T0390
OUT W47.00

; rung 1035
LD W170.09
OR W22.14
LD 16.09
ANDNOT H8.13
ORLD
OR W47.02
ANDNOT W175.11
AND W193.15
AND W165.01
ANDNOT W47.06
TIM 0392 D707
AND T0392
OUT W47.02
; rung 1036
LD W170.13
AND W48.02
OR W47.00
OR W47.02
ANDNOT 14.12
ANDNOT 14.13
AND W193.15
ANDNOT W394.01
OUT 14.08
; rung 1037: ---------- 右成形機当て止め処理 ----------
LD W170.09
OR W23.13
OR W39.06
ANDNOT W305.12
ANDNOT W47.09
AND W193.15
AND W165.02
TIM 0532 D687
AND T0532
OUT W39.06
; rung 1038
LD W170.09
OR W23.14
LD 16.09
ANDNOT H8.13
ORLD
OR W39.07
ANDNOT W305.11
ANDNOT W47.08
AND W193.15
AND W165.03
TIM 0533 D688
AND T0533
OUT W39.07
; rung 1039
LD W39.06
OR W39.07
ANDNOT 14.14
ANDNOT 14.15
AND W193.15
LD 2130.10
OR P_On
ANDLD
LDNOT 2130.09
OR P_On
ANDLD
ANDNOT W394.01
OUT TR0
AND W311.12
ANDNOT W311.14
OUT 22.10
LD TR0
AND W311.14
ANDNOT W311.12
LDNOT T0096
OR P_On
ANDLD
OUT 22.11
DIFU(013) W55.15
; rung 1040
@LD 16.06
MOV(021) D223 D410
MOV(021) D232 D412

; rung 1041
LD 14.14
MOV(021) #0 D410
MOV(021) #0 D412
; rung 1042
@LD 16.04
MOV(021) D273 D411
; rung 1043
LD 14.12
MOV(021) #0 D411
; rung 1044
LDNOT W305.11
LD 2123.03
KEEP(011) W70.00
; rung 1045
LDNOT W47.08
LD 2123.03
KEEP(011) W70.01
; rung 1046
LD W193.15
LD 2123.03
KEEP(011) W70.02
; rung 1047
LD 16.06
LD 2123.03
KEEP(011) W70.03
; rung 1048
LD W311.14
LD 2123.03
KEEP(011) W70.04

; rung 1049
LD W39.07
LD 2123.03
KEEP(011) W70.05
; rung 1050
LDNOT 14.14
LD 2123.03
KEEP(011) W70.06
; rung 1051
LDNOT 14.15
LD 2123.03
KEEP(011) W70.07
; rung 1052
LD W193.15
LD 2123.03
KEEP(011) W70.08
; rung 1053
LDNOT 2130.09
LD 2123.03
KEEP(011) W70.09
; rung 1054
LDNOT W394.01
LD 2123.03
KEEP(011) W70.10
; rung 1055
LDNOT W311.12
LD 2123.03
KEEP(011) W70.11
; rung 1056
LD W55.15
LD 2123.03
KEEP(011) W70.12

; rung 1057: ---------- 右成形機旋回停止 ----------
LD W170.09
OR W23.13
OR W47.03
ANDNOT W305.12
ANDNOT W47.09
AND W193.15
AND W165.02
TIM 0393 D708
AND T0393
OUT W47.03
; rung 1058
LD W170.09
OR W23.14
LD 16.09
ANDNOT H8.13
ORLD
OR W47.05
ANDNOT W305.11
ANDNOT W47.08
AND W193.15
AND W165.03
TIM 0395 D709
AND T0395
OUT W47.05
; rung 1059
LD W170.13
AND W48.03
OR W47.03
OR W47.05
ANDNOT 14.14
ANDNOT 14.15
AND W193.15
ANDNOT W394.01
OUT 14.09
; rung 1060: ********** 左成形機　旋回／戻り処理 ********** / ----- 左成形機旋回処理(成形位置から待避位置へ) -----
LDNOT W176.00
ANDNOT W176.03
OR W174.00
ANDNOT W174.01
OUT W174.00
; rung 1061
LD P_On
AND<(310) D669 #10
OUT W174.01
; rung 1062: ***** 左旋回処理（待避位置方面） *****
LD 2110.10
ANDNOT P_On
OR P_On
OUT W57.04
; rung 1063
LD 16.05
OR W360.00
LD W170.05
OR W170.06
ANDLD
OR W54.00
AND T0021
LD 16.05
OR P_On
ANDLD
AND W223.04
AND W170.00
ANDNOT W176.02
OUT W54.00

; rung 1064
LD W54.00
AND W57.04
OR W176.02
ANDNOT 16.04
AND W165.03
AND W176.07
AND T0021
ANDNOT T0093
OUT W176.02
TIM 1129 D1129
; rung 1065: ---　移送調整入の時位置条件無し ---
LDNOT W181.14
ORNOT 16.04
OR W182.13
LD 16.08
AND 16.00
ORLD
OR P_On  // 当て止めに付き常時ON
OUT W175.00
; rung 1066
LD W176.02
AND T1129
LD 2071.10
LD W48.04
AND W22.15
ORLD
LD W182.13
AND W182.07
ORLD
AND W170.13
ORLD
AND W175.00
AND W193.15
AND W176.07
OUT W176.00
DIFU(013) W175.11
; rung 1067
LD W176.00
LDNOT W174.01
ORNOT W181.14
ORNOT 16.04
AND W174.00
ORLD
ANDNOT W174.03
OUT W174.04
; rung 1068
LDNOT W174.04
TIM 0004 #2
; rung 1069
LDNOT T0004
OUT W174.05

; rung 1070: --- 左成形機旋回電磁弁処理 ---
LD W165.03
OR W67.02
OR W22.15
ANDNOT 14.12
AND W176.07
AND W193.15
ANDNOT W394.01
ANDNOT W173.08
OUT W54.10
; rung 1071
LD W49.11
LD W174.04
LD T0021
AND 14.13
ANDNOT W54.07
ORLD
AND W54.10
ORLD
OUT W47.07
ANDNOT 14.08
LDNOT 16.04
OR W49.11
ANDLD
ANDNOT W47.02
OUT 14.13
ANDNOT W49.11
OUT W54.08
; rung 1072: ***** 左成形機旋回戻り処理(待避位置から成形位置へ) ***** / 前回下記処理により取出位置戻り遅延時間算出していたが、今回取出機進入許可遅延とした
LD P_On
OUT TR0
CMP(020) D1121 #200
LD P_GT
OR P_EQ
ANDLD
CLC(041)
-BC(416) D1121 #200 D221
LD TR0
AND P_LT
MOV(021) #20 D221
; rung 1073
LD P_On
OUT TR0
AND H1.00
MOV(021) #10 D220
LD TR0
AND W358.04
OUT TR0
ANDNOT P_On
MOV(021) D221 D220
LD TR0
MOV(021) #10 D220
; rung 1074
LD W225.01
OR W193.02
AND H1.00
OR W358.04
ANDNOT H1.05
AND W223.04
AND T0021
AND W165.01
TIM 0092 D220
AND T0092
DIFU(013) W176.06

; rung 1075
LD W176.06
OR W162.11
ANDNOT W223.00
AND T0021
OUT W162.11
; rung 1076: ----- 左成形機旋回戻り条件 ----- / OUT LR5403は自動運転初回時旋回戻り条件     OUT LR5404は2回目以降の旋回戻り条件
LD W224.13
OR W358.04
AND W161.13
AND W42.00
LD W40.05
ORNOT H1.01
ANDLD
AND 473.02
AND 11.09
AND W223.00
LD W165.01
OR W360.02
ANDLD
OUT TR0
AND 2110.10
OUT W54.03
LD TR0
OUT W54.01
; rung 1077
LD T0054
ORNOT H1.08
AND H99.03
AND W42.00
LD W40.05
ORNOT H1.01
ANDLD
AND 473.02
AND 11.09
ANDNOT T0093
AND W223.00
LD W165.01
OR W360.02
ANDLD
OUT TR0
AND 2110.10
OUT W54.04
LD TR0
OUT W54.12
; rung 1078
LD W54.03
OR W54.04
OR 14.12
OR W176.05
AND W223.00
AND W170.00
AND W176.07
ANDNOT 16.05
ANDNOT T0093
AND W165.03
AND W47.05
AND T0021
OUT W176.05
TIM 0091 #3
; rung 1079: ----- 左成形機旋回戻り行程 -----
LD W176.05
AND T0091
OUT W54.05
; rung 1080
LD W182.13
AND W182.08
LD 2054.01
OR W181.09
ORNOT W181.13
AND 2071.11
ORLD
LDNOT 16.05
ORNOT W181.12
OR W182.13
OR P_On  // 当て止めに付き常時ON
ANDLD
AND W170.13
OUT W54.06
; rung 1081
LD W54.05
OR W54.06
AND W193.15
AND W176.07
OUT W176.03
DIFU(013) W175.12

; rung 1082
LD W176.03
LDNOT W174.01
ORNOT W181.12
ORNOT 16.05
AND W174.00
ORLD
ANDNOT W174.05
OUT W174.02
; rung 1083
LDNOT W174.02
TIM 0003 #2
; rung 1084
LDNOT T0003
OUT W174.03
; rung 1085: --- 左成形機旋回戻り電磁弁処理 ---
LD W170.13
LDNOT 16.05
AND W223.00
ORLD
AND W174.02
OUT W54.07
; rung 1086
LD 2054.01
AND W165.04
OR W181.09
ORNOT W181.13
ANDNOT W173.08
AND W165.03
AND W176.07
ANDNOT 14.13
AND W193.15
ANDNOT W394.01
OUT W54.11
; rung 1087
LD W54.07
LD T0021
AND 14.12
ANDNOT W174.04
ORLD
AND W54.11
OUT W47.06
ANDNOT 14.08
ANDNOT 16.05
ANDNOT W47.00
OUT 14.12
OUT W54.09
; rung 1088: ********** 右成形機　旋回／戻り処理 ********** / ----- 右成形機旋回処理(成形位置から待避位置へ) -----
LDNOT W306.00
ANDNOT W306.03
OR W304.00
ANDNOT W304.01
OUT W304.00
; rung 1089
LD P_On
AND<(310) D2889 #10
OUT W304.01

; rung 1090: ***** 右旋回処理（待避位置方面） *****
LD 2130.10
ANDNOT P_On
OR P_On
OUT W57.05
; rung 1091
LD 16.07
OR W360.01
LD W170.05
OR W170.06
ANDLD
OR W55.00
AND T0021
LD 16.07
OR P_On
ANDLD
AND W225.01
AND W170.01
ANDNOT W306.02
OUT W55.00
; rung 1092
LD W55.00
AND W57.05
OR W306.02
ANDNOT 16.06
AND W306.07
AND W165.01
AND T0021
ANDNOT T0094
OUT W306.02
TIM 1329 D1329
; rung 1093
LDNOT T0020
ORNOT W193.15
ORNOT W306.07
OUT W306.01
; rung 1094
LDNOT W311.14
ORNOT 16.06
OR W182.13
LD 16.08
AND 16.02
ORLD
OR P_On  // 当て止めに付き常時ON
OUT W305.00
; rung 1095
LD W306.02
AND T1329
LD 2091.10
LD W48.05
AND W23.15
ORLD
LD W182.13
AND W312.07
ORLD
AND W170.13
ORLD
AND W305.00
ANDNOT W306.01
AND W306.07
OUT W306.00
DIFU(013) W305.11

; rung 1096
LD W306.00
LDNOT W304.01
ORNOT 16.06
ORNOT W311.14
AND W304.00
ORLD
ANDNOT W304.03
OUT W304.04
; rung 1097
LDNOT W304.04
TIM 0012 #2
; rung 1098
LDNOT T0012
OUT W304.05
; rung 1099: --- 右成形機旋回電磁弁処理 ---
LD W165.01
OR W67.03
OR W23.15
ANDNOT 14.14
AND W306.07
AND W193.15
ANDNOT W394.01
ANDNOT W173.09
OUT W55.10
; rung 1100
LD W49.12
LD W304.04
LD T0021
AND 14.15
ANDNOT W55.07
ORLD
AND W55.10
ORLD
OUT W47.09
ANDNOT 14.09
LDNOT 16.06
OR W49.12
ANDLD
ANDNOT W47.05
OUT 14.15
ANDNOT W49.12
OUT W55.08
; rung 1101: ***** 右成形機旋回戻り処理(待避位置から成形位置へ) ***** / 前回下記処理により取出位置戻り遅延時間算出していたが、今回取出機進入許可遅延とした
LD P_On
OUT TR0
CMP(020) D1321 #200
LD P_GT
OR P_EQ
ANDLD
CLC(041)
-BC(416) D1321 #200 D219
LD TR0
AND P_LT
MOV(021) #20 D219

; rung 1102
LD P_On
OUT TR0
AND H1.00
MOV(021) #10 D218
LD TR0
AND W358.05
OUT TR0
ANDNOT P_On
MOV(021) D219 D218
LD TR0
MOV(021) #10 D218
; rung 1103
LD W223.04
OR W193.02
OR W358.05
AND W170.01
ANDNOT H1.05
AND W225.01
AND T0021
AND W165.03
TIM 0097 D218
AND T0097
DIFU(013) W306.06
; rung 1104
LD W306.06
OR W162.10
ANDNOT W224.13
AND T0021
OUT W162.10
; rung 1105: ----- 右成形機旋回戻り条件 -----
LD W165.01
AND W223.04
OR W358.05
LD W161.12
OR H1.00
ANDLD
AND W42.01
LD W41.05
ORNOT H1.01
ANDLD
AND 473.02
AND 11.09
AND W224.13
LD W165.03
OR W360.03
ANDLD
OUT TR0
AND 2130.10
OUT W55.03
LD TR0
OUT W55.01
; rung 1106
LD T0055
ORNOT H1.10
AND H99.04
AND W42.01
LD W41.05
ORNOT H1.01
ANDLD
AND 473.02
AND 11.09
ANDNOT T0094
AND W224.13
LD W165.03
OR W360.03
ANDLD
OUT TR0
AND 2130.10
OUT W55.04
LD TR0
OUT W55.12
; rung 1107
LD W55.03
OR W55.04
OR 14.14
OR W306.05
AND W224.13
AND W170.01
AND W306.07
ANDNOT 16.07
ANDNOT T0094
AND W165.01
AND W47.02
AND T0021
OUT W306.05
TIM 0096 #3
; rung 1108: ----- 右成形機旋回戻り行程 -----
LD W306.05
AND T0096
OUT W55.05

; rung 1109
LD W182.13
AND W312.08
LD 2054.01
OR W311.09
ORNOT W311.13
AND 2091.11
ORLD
LDNOT 16.07
ORNOT W311.12
OR W182.13
OR P_On  // 当て止めに付き常時ON
ANDLD
AND W170.13
OUT W55.06
; rung 1110
LD W55.05
OR W55.06
AND W193.15
AND W306.07
OUT W306.03
DIFU(013) W305.12
; rung 1111
LD W306.03
LDNOT W304.01
ORNOT W311.12
ORNOT 16.07
AND W304.00
ORLD
ANDNOT W304.05
OUT W304.02
; rung 1112
LDNOT W304.02
TIM 0011 #2
; rung 1113
LDNOT T0011
OUT W304.03
; rung 1114: --- 右成形機旋回戻り電磁弁処理 ---
LD W170.13
LDNOT 16.07
AND W224.13
ORLD
AND W304.02
OUT W55.07
; rung 1115
LD 2054.01
AND W165.04
OR W311.09
ORNOT W311.13
ANDNOT W173.09
AND W165.01
AND W306.07
ANDNOT 14.15
AND W193.15
ANDNOT W394.01
OUT W55.11

; rung 1116
LD W55.07
LD T0021
AND 14.14
ANDNOT W304.04
ORLD
AND W55.11
OUT W47.08
ANDNOT 14.09
ANDNOT 16.07
ANDNOT W47.03
OUT 14.14
OUT W55.09
; rung 1117: ********** 左電磁弁処理 **********
LD W42.02
OR W343.07
ANDNOT 2100.12
ANDNOT 459.02
ANDNOT W9.09
AND W193.15
ANDNOT W394.01
ANDNOT W175.08
AND 473.03
OUT W177.15
; rung 1118
LD 457.04
AND 16.08
AND W223.04
TIM 0464 #20
; rung 1119
LD W189.01
AND T0053
LD W183.03
AND T0056
ORLD
OR W183.07
OR W343.07
ANDNOT W397.00
LD W396.12
AND W397.00
ORLD
LD 457.04
ANDNOT W422.00
AND 16.08
ANDNOT T0464
ORLD
AND W177.15
AND W186.15
OUT 2100.03
OUT 2105.03
; rung 1120
LD W343.07
ANDNOT T0166
ANDNOT W397.00
LDNOT P_On
AND 457.04
AND 16.08
ANDNOT T0464
ORLD
AND W177.15
AND W186.15
OUT 2101.00
OUT 2105.07
; rung 1121: 型閉高速電磁弁は型閉電磁弁を入れる前にONする事。（型閉衝撃を無くす為）
LD W189.01
AND T0082
ANDNOT W180.15
LD W183.03
AND T0085
ANDNOT W181.10
ORLD
ANDNOT W394.01
AND W186.15
AND W193.15
ANDNOT W175.08
ANDNOT W182.02
ANDNOT W182.03
OUT 2100.13
OUT 2105.05
AND W183.07
DIFD(014) W181.11
; rung 1122
LD W396.12
OUT W397.02

; rung 1123
LDNOT 2100.03
AND W193.15
ANDNOT W9.06
AND W42.02
ANDNOT W394.01
ANDNOT W175.08
AND 473.03
OUT W177.14
; rung 1124
LD W182.02
AND T0167
LD 2101.02
OR T0021
AND W182.03
ORLD
ANDNOT W397.00
LD W396.13
AND W397.00
AND T0167
ORLD
LD W186.15
LD W170.13
AND W197.00
ORLD
ANDLD
AND W177.14
OUT 2100.12
OUT 2105.04
; rung 1125
LD W396.13
OUT W397.03
; rung 1126
LDNOT W193.01
AND T0029
ANDNOT 2100.00
AND W193.15
AND W186.15
ANDNOT W394.01
ANDNOT W175.08
OUT 2100.01
OUT 2105.01
OUT W343.07
TIM 0166 #10
; rung 1127
LD W183.14
ANDNOT W397.00
OR W165.07
LD W396.13
ANDNOT 2100.12
ANDNOT W397.00
ORLD
LD 16.08
AND 459.00
ORLD
AND W193.15
ANDNOT W394.01
ANDNOT 2100.01
ANDNOT W175.08
OUT 2100.00
OUT 2105.00
; rung 1128
LD W183.07
LD P_On
ANDNOT 16.08
ORLD
ANDNOT W223.04
LD W182.02
AND T0167
ORLD
LD T0021
OR T0167
AND W182.03
ORLD
ANDNOT W397.00
LD W396.13
AND W397.00
AND T0167
ORLD
LD W186.15
LD W170.13
AND W197.00
ORLD
ANDLD
AND W193.15
ANDNOT 2100.01
ANDNOT W394.01
ANDNOT W175.08
OUT 2100.14
OUT 2105.06

; rung 1129
LD W182.03
OR W182.02
LD T0021
LD W170.13
AND 2070.14
ANDNOT W165.07
ORLD
ANDLD
ANDNOT W397.00
LD 16.08
AND 459.00
ORLD
LD W396.13
AND W397.00
ORLD
LD W186.15
LD W170.13
AND W197.00
ORLD
ANDLD
AND W193.15
ANDNOT W394.01
ANDNOT W175.08
OUT 2101.02
OUT 2105.08
TIM 0167 #20
; rung 1130
LD W343.07
AND T0021
LD 16.08
AND 459.00
ORLD
AND W193.15
AND W186.15
ANDNOT W394.01
ANDNOT W175.08
OUT 2100.02
OUT 2105.02
; rung 1131: ********** 右電磁弁処理 **********
LD W42.03
OR W343.08
ANDNOT 2120.12
AND W193.15
ANDNOT W394.01
ANDNOT 459.03
ANDNOT W15.02
ANDNOT W175.09
AND 473.04
OUT W307.15
; rung 1132
LD 457.05
AND 16.08
AND W225.01
TIM 0465 #20
; rung 1133
LD W319.01
AND T0052
LD W313.03
AND T0057
ORLD
OR W313.07
OR W343.08
ANDNOT W397.12
LD W397.08
AND W397.12
ORLD
LD 457.05
ANDNOT W422.01
AND 16.08
ANDNOT T0465
ORLD
AND W307.15
AND W316.15
OUT 2120.03
OUT 2125.03
; rung 1134
LD W343.08
ANDNOT T0168
ANDNOT W397.12
LDNOT P_On
AND 457.05
AND 16.08
ANDNOT T0465
ORLD
AND W307.15
AND W316.15
OUT 2121.00
OUT 2125.07

; rung 1135: 型閉高速電磁弁は型閉電磁弁を入れる前にONする事。（型閉衝撃を無くす為）
LD W319.01
AND T0076
ANDNOT W310.15
LD W313.03
AND T0079
ANDNOT W311.10
ORLD
ANDNOT W394.01
AND W316.15
AND W193.15
ANDNOT W175.09
ANDNOT W312.02
ANDNOT W312.03
OUT 2120.13
OUT 2125.05
AND W313.07
DIFD(014) W311.11
; rung 1136
LD W397.08
OUT W397.14
; rung 1137
LDNOT 2120.03
AND W193.15
ANDNOT W394.01
ANDNOT W15.05
AND W42.03
ANDNOT W175.09
AND 473.04
OUT W307.14
; rung 1138
LD W312.02
AND T0169
LD T0021
OR 2121.02
AND W312.03
ORLD
ANDNOT W397.12
LD W397.09
AND W397.12
AND T0169
ORLD
LD W316.15
LD W170.13
AND W194.00
ORLD
ANDLD
AND W307.14
OUT 2120.12
OUT 2125.04
; rung 1139
LD W397.09
OUT W397.15
; rung 1140
LDNOT W193.01
AND T0032
ANDNOT 2120.00
AND W193.15
AND W316.15
ANDNOT W394.01
ANDNOT W175.09
OUT 2120.01
OUT 2125.01
OUT W343.08
TIM 0168 #10
; rung 1141
LD W313.14
ANDNOT W397.12
OR W165.08
LD W397.09
ANDNOT 2120.12
AND W397.12
ORLD
LD 16.08
AND 459.01
ORLD
AND W193.15
ANDNOT 2120.01
ANDNOT W394.01
ANDNOT W175.09
OUT 2120.00
OUT 2125.00

; rung 1142
LD W313.07
LD P_On
ANDNOT 16.08
ORLD
ANDNOT W225.01
LD W312.02
AND T0169
ORLD
LD T0021
OR T0169
AND W312.03
ORLD
ANDNOT W397.12
LD W397.12
AND W397.09
ORLD
LD W316.15
LD W170.13
AND W194.00
ORLD
ANDLD
AND W193.15
ANDNOT 2120.01
ANDNOT W394.01
ANDNOT W175.09
OUT 2120.14
OUT 2125.06
; rung 1143
LD W312.03
OR W312.02
LD T0021
LD W170.13
AND 2090.14
ANDNOT W165.08
ORLD
ANDLD
ANDNOT W397.12
LD 16.08
AND 459.01
ORLD
LD W397.09
AND W397.12
ORLD
LD W316.15
LD W170.13
AND W194.00
ORLD
ANDLD
AND W193.15
ANDNOT W394.01
ANDNOT W175.09
OUT 2121.02
OUT 2125.08
TIM 0169 #20
; rung 1144
LD W343.08
AND T0021
LD 16.08
AND 459.01
ORLD
AND W193.15
AND W316.15
ANDNOT W394.01
ANDNOT W175.09
OUT 2120.02
OUT 2125.02
; rung 1145: ********** ﾎﾟﾝﾌﾟｵﾝﾛｰﾄﾞ処理 **********
LDNOT 13.10
ANDNOT 13.11
AND W174.13
OUT 13.15
; rung 1146
LDNOT W189.01
ANDNOT W183.03
ANDNOT W183.07
ANDNOT W343.07
ANDNOT W182.02
ANDNOT W182.03
ANDNOT W54.08
ANDNOT W54.09
OUTNOT W167.13
; rung 1147
LDNOT W319.01
ANDNOT W313.03
ANDNOT W313.07
ANDNOT W343.08
ANDNOT W312.02
ANDNOT W312.03
ANDNOT W55.08
ANDNOT W55.09
OUTNOT W167.14
; rung 1148
LDNOT W167.13
ANDNOT W167.14
OUTNOT W167.15
; rung 1149
LD W167.15
AND W174.13
ANDNOT H8.14
LD H8.14
AND T0020
ORLD
OUT 13.10

; rung 1150
LD W167.15
AND W174.13
ANDNOT H8.14
LD H8.14
AND T0020
ORLD
OUT 13.11
; rung 1151
LDNOT H8.14
AND W174.13
LD H8.14
AND T0020
ANDNOT 16.08
ORLD
OUT 13.12
; rung 1152: ********** 左圧力設定値転送 ********** / ----- 左成形機動作時保圧圧力比例弁(PV1) -----
LD W193.15
AND T0029
OUT TR0
AND T0021
ANDNOT W193.01
AND 427.13
OUT TR1
OUT W180.10
ANDNOT W224.04
OUT W224.03
LD TR1
@MOV(021) D550 D979
TIM 1103 D1103
AND T1103
@MOV(021) D551 D979
OUT W224.04
LD TR0
AND W193.01
MOV(021) #300 D979
; rung 1153
LDNOT W180.10
ANDNOT W310.10
AND W170.00
AND T0020
MOV(021) #0 D979

; rung 1154: ----- 左成形機動作時圧力比例弁１(PV2) ----- / ・型閉徐行時100kgf/cm2以上設定→上限100kgf/cm2にSCL / ・今回補機圧力削除
LD P_On
MOV(021) #0 D2020
MOV(021) #0 D2021
MOV(021) #400 D2022
MOV(021) #3E7 D2023
; rung 1155
LD P_On
BIN(023) D553 D2024
SCL(194) D2024 D2020 D2025
; rung 1156
LD W193.12
ANDNOT W180.14
AND W183.07
TIM 0452 #2
OUT W180.12
OUT W224.06
AND T0452
@MOV(021) D2025 D978

; rung 1157
LD W189.01
OR W183.03
OR W182.02
OR W182.03
AND W193.12
ANDNOT W180.12
TIM 0453 #3
OUT W180.13
OUT W224.05
LD W180.13
LD T0453
ANDNOT P_On
ORLD
ANDLD
OUT TR0
ANDNOT T0453
ANDNOT P_On
@MOV(021) #0 D978
LD TR0
ANDNOT W182.04
@MOV(021) D552 D978
LD TR0
AND W182.04
@MOV(021) #350 D978
; rung 1158
LDNOT P_On
AND W193.11
ANDNOT W180.13
ANDNOT W180.12
ANDNOT W182.10
OUT W180.14
OUT W224.07
@MOV(021) D554 D978
; rung 1159: --- 位置到達までの移送圧力 ---
LD 14.12
AND W176.03
ANDNOT W181.12
LD W176.05
AND H13.04
ORLD
OR 14.13
LD W176.02
AND H13.04
ORLD
AND W193.12
OUT W182.10
OUT W224.08
AND W170.09
@MOV(021) D555 D978
; rung 1160
LD W193.12
AND W170.13
OUT TR0
AND 14.12
OUT W65.00  // 手動時移送圧力も裏画面で設定可能にした
MOV(021) D2716 D978
LD TR0
AND 14.13
OUT W65.02
MOV(021) D2718 D978

; rung 1161: --- 加速完了から減速開始までの移送圧力 --- / 成形機がズドーンと移送を行い加速が完了したところで、圧力を下げてやる。これにより成形機移送の加速完了後の速度低下がなくなる。
LD 14.12
OR 14.13
AND W193.12
AND W170.09
AND W179.08
AND H13.04
@MOV(021) D2724 D978
; rung 1162: --- 減速開始からの移送圧力 --- / これをやることにより、成形機移送減速時の絞り側の圧力を低く抑えることができる。
LD 14.12
AND W178.12
LD 14.13
AND W178.13
ORLD
AND W193.12
AND W170.09
AND H13.04
@MOV(021) D2725 D978
; rung 1163: --- 位置到達後の移送圧力 ---
LD W182.10
OUT TR0
AND 14.13
AND W181.14
OUT TR1
AND T0021
OUT W64.04  // 各押当時圧力設定を調整画面にて設定可能にした
MOV(021) D2704 D978
LD TR1
AND W170.13
OUT W64.06
MOV(021) D2706 D978
LD TR0
AND 14.12
AND W181.12
OUT TR0
AND T0021
OUT W64.00
MOV(021) D2700 D978
LD TR0
AND W170.13
OUT W64.02
MOV(021) D2702 D978

; rung 1164: ********** 右圧力設定値転送 ********** / ----- 右成形機動作時保圧圧力比例弁(PV1) -----
LD W193.15
AND T0032
OUT TR0
AND T0021
ANDNOT W193.01
AND 427.13
OUT TR1
OUT W310.10
ANDNOT W226.01
OUT W226.00
LD TR1
@MOV(021) D580 D979
TIM 1303 D1303
AND T1303
@MOV(021) D581 D979
OUT W226.01
LD TR0
AND W193.01
MOV(021) #300 D979
; rung 1165
LDNOT W310.10
ANDNOT W180.10
AND W170.01
AND T0020
MOV(021) #0 D979
; rung 1166: ----- 右成形機動作時圧力比例弁１(PV2) ----- / ・型閉徐行時100kgf/cm2以上設定→上限100kgf/cm2にSCL / ・今回補機圧力削除
LD P_On
MOV(021) #0 D2026
MOV(021) #0 D2027
MOV(021) #400 D2028
MOV(021) #3E7 D2029
; rung 1167
LD P_On
BIN(023) D583 D2030
SCL(194) D2030 D2026 D2031

; rung 1168
LD W193.12
ANDNOT W310.14
AND W313.07
TIM 0450 #2
OUT W310.12
OUT W226.03
AND T0450
@MOV(021) D2031 D978
; rung 1169
LD W319.01
OR W313.03
OR W312.02
OR W312.03
AND W193.12
ANDNOT W310.12
TIM 0451 #3
OUT W310.13
OUT W226.02
LD W310.13
LD T0451
ANDNOT P_On
ORLD
ANDLD
OUT TR0
ANDNOT T0451
ANDNOT P_On
@MOV(021) #0 D978
LD TR0
ANDNOT W312.04
@MOV(021) D582 D978
LD TR0
AND W312.04
@MOV(021) #350 D978
; rung 1170
LDNOT P_On
AND W193.11
ANDNOT W310.13
ANDNOT W310.12
ANDNOT W312.10
OUT W310.14
OUT W226.04
@MOV(021) D584 D978
; rung 1171: --- 位置到達までの移送圧力 ---
LD 14.14
AND W306.03
ANDNOT W311.12
LD W306.05
AND H13.04
ORLD
OR 14.15
LD W306.02
AND H13.04
ORLD
AND W193.12
OUT W312.10
OUT W226.05
AND W170.09
@MOV(021) D585 D978

; rung 1172
LD W193.12
AND W170.13
OUT TR0
AND 14.14
OUT W65.04  // 手動時移送圧力も裏画面で設定可能にした
MOV(021) D2720 D978
LD TR0
AND 14.15
OUT W65.06
MOV(021) D2722 D978
; rung 1173: --- 加速完了から減速開始までの移送圧力 --- / 成形機がズドーンと移送を行い加速が完了したところで、圧力を下げてやる。これにより成形機移送加速完了後の速度低下がなくなる。
LD 14.14
OR 14.15
AND W193.12
AND W170.09
AND W179.09
AND H13.04
@MOV(021) D2726 D978
; rung 1174: --- 減速開始からの移送圧力 --- / これをやることにより、成形機移送減速時の絞り側の圧力を低く抑えることができる。
LD 14.14
AND W179.12
LD 14.15
AND W179.13
ORLD
AND W193.12
AND W170.09
AND H13.04
@MOV(021) D2727 D978
; rung 1175: --- 位置到達後の移送圧力 ---
LD W312.10
OUT TR0
AND 14.15
AND W311.14
OUT TR1
AND T0021
OUT W64.12
MOV(021) D2712 D978
LD TR1
AND W170.13
OUT W64.14
MOV(021) D2714 D978
LD TR0
AND 14.14
AND W311.12
OUT TR0
AND T0021
OUT W64.08
MOV(021) D2708 D978
LD TR0
AND W170.13
OUT W64.10
MOV(021) D2710 D978

; rung 1176: ********** 左速度設定値転送 **********
LD W193.12
AND 2101.00
OUT W180.05
OUT W223.15
@MOV(021) D545 D977
; rung 1177
LDNOT P_On
AND W193.12
AND 2101.00
ANDNOT 2100.12
OUT W180.06
OUT W224.00
@MOV(021) D546 D977
; rung 1178
LD 14.12
OR 14.13
AND W193.12
OUT TR0
OUT W180.08
OUT W224.02
AND W170.09
@MOV(021) D548 D977
LD TR0
AND W170.13
@MOV(021) #350 D977
; rung 1179
LD W193.12
AND W182.03
OUT TR0
OUT W180.04
OUT W223.14
ANDNOT W197.03
@MOV(021) D544 D977
LD TR0
AND W197.03
@MOV(021) #350 D977
; rung 1180
LD W193.12
AND W182.02
ANDNOT W180.05
ANDNOT W180.04
OUT W180.03
OUT W223.13
@MOV(021) D543 D977

; rung 1181
LD W193.12
AND W183.07
ANDNOT W180.08
ANDNOT W180.04
ANDNOT W180.03
OUT W180.02
OUT W223.12
@MOV(021) D542 D977
; rung 1182
LD W193.12
AND W183.03
ANDNOT W180.04
ANDNOT W180.03
ANDNOT W180.02
OUT W180.01
OUT W223.11
@MOV(021) D541 D977
TIM 0083 #1
TIM 0084 #4
TIM 0085 #4
; rung 1183
LD W193.12
AND W189.01
ANDNOT W180.04
ANDNOT W180.03
ANDNOT W180.02
ANDNOT W180.01
OUT W180.00
OUT W223.10
@MOV(021) D540 D977
TIM 0080 #1
TIM 0081 #4
TIM 0082 #4
; rung 1184
LDNOT P_On
ANDNOT W180.04
ANDNOT W180.03
ANDNOT W180.02
ANDNOT W180.01
ANDNOT W180.00
AND W193.11
ANDNOT W180.08
OUT W180.07
OUT W224.01
@MOV(021) D547 D977

; rung 1185: ********** 右速度設定値転送 **********
LD W193.12
AND 2121.00
OUT W310.05
OUT W225.12
@MOV(021) D575 D977
; rung 1186
LDNOT P_On
AND W193.12
AND 2121.00
ANDNOT 2120.12
OUT W310.06
OUT W225.13
@MOV(021) D576 D977
; rung 1187
LD 14.14
OR 14.15
AND W193.12
OUT TR0
OUT W310.08
OUT W225.15
AND W170.09
@MOV(021) D578 D977
LD TR0
AND W170.13
@MOV(021) #350 D977
; rung 1188
LD W193.12
AND W312.03
OUT TR0
OUT W310.04
OUT W225.11
ANDNOT W194.03
@MOV(021) D574 D977
LD TR0
AND W194.03
@MOV(021) #350 D977
; rung 1189
LD W193.12
AND W312.02
ANDNOT W310.05
ANDNOT W310.04
OUT W310.03
OUT W225.10
@MOV(021) D573 D977

; rung 1190
LD W193.12
AND W313.07
ANDNOT W310.08
ANDNOT W310.04
ANDNOT W310.03
OUT W310.02
OUT W225.09
@MOV(021) D572 D977
; rung 1191
LD W193.12
AND W313.03
ANDNOT W310.04
ANDNOT W310.03
ANDNOT W310.02
OUT W310.01
OUT W225.08
@MOV(021) D571 D977
TIM 0077 #1
TIM 0078 #4
TIM 0079 #4
; rung 1192
LD W193.12
AND W319.01
ANDNOT W310.04
ANDNOT W310.03
ANDNOT W310.02
ANDNOT W310.01
OUT W310.00
OUT W225.07
@MOV(021) D570 D977
TIM 0074 #1
TIM 0075 #4
TIM 0076 #4
; rung 1193
LDNOT P_On
ANDNOT W310.04
ANDNOT W310.03
ANDNOT W310.02
ANDNOT W310.01
ANDNOT W310.00
AND W193.11
ANDNOT W310.08
OUT W310.07
OUT W225.14
@MOV(021) D577 D977

; rung 1194
LD W49.08
ANDNOT T0021
MOV(021) #500 D977
; rung 1195: ********** 左型閉徐行流量(FV3)設定値転送 ********** / 型閉徐行時のみ設定値転送し、通常は比例弁全開
LD W193.12
AND W183.07
OUT W360.15
OUT W224.09
@MOV(021) D556 D981
; rung 1196: ********** 右型閉徐行流量(FV4)設定値転送 ********** / 型閉徐行時のみ設定値転送し、通常は比例弁全開
LD W193.12
AND W313.07
OUT W360.14
OUT W226.06
@MOV(021) D586 D982
; rung 1197: ********** 各設定値をDA出力に変換 ********** / 段取り時、補機速度・圧力のみ転送したいのでPV2はそのままのｲﾝﾀﾛｯｸにした
LD P_On
MOV(021) #0 D2901
MOV(021) #0 D2902
MOV(021) #4000 D2903
MOV(021) #3E7 D2904

; rung 1198: ----- 保圧圧力比例弁(PV1)データ変換 -----
LD W193.15
BIN(023) D979 D2900
SCL(194) D2900 D2901 D278
BIN(023) D278 D279
; rung 1199: ----- 主回路圧力比例弁(PV2)データ変換 -----
LDNOT H8.14
AND W174.13
LD H8.14
AND T0020
ORLD
BIN(023) D978 D2900
SCL(194) D2900 D2901 D242
BIN(023) D242 D243
; rung 1200: ----- 主回路流量比例弁(FV11)データ変換 -----
LDNOT H8.14
AND W174.13
LD H8.14
AND T0020
ORLD
BIN(023) D977 D2900
SCL(194) D2900 D2901 D2976
BIN(023) D2976 D2977

; rung 1201: ----- 左移送流量比例弁(FV1)データ変換 -----
LD W193.15
BIN(023) D976 D2900
SCL(194) D2900 D2901 D286
BIN(023) D286 D287
; rung 1202: ----- 右移送流量比例弁(FV2)データ変換 -----
LD W193.15
BIN(023) D980 D2900
SCL(194) D2900 D2901 D236
BIN(023) D236 D237
; rung 1203: ----- 左型閉徐行流量比例弁(FV3)データ変換 -----
LD W193.15
BIN(023) D981 D2900
SCL(194) D2900 D2901 D2960
BIN(023) D2960 D2961

; rung 1204: ----- 右型閉徐行流量比例弁(FV4)データ変換 -----
LD W193.15
BIN(023) D982 D2900
SCL(194) D2900 D2901 D2964
BIN(023) D2964 D2965
; rung 1205: ----- 当止時流量設定値ﾃﾞｰﾀ変換 -----
LD W379.04
AND W378.03
ANDNOT W509.15
OR P_First_Cycle
OR W358.00
OUT W361.11
; rung 1206
LD W361.11
BIN(023) D2701 D2755  // 自動時左成形機旋回戻側押当流量
SCL(194) D2755 D2901 D2756
BIN(023) D2756 D2757
BIN(023) D2703 D2755  // 手動時左成形機旋回戻側押当流量
SCL(194) D2755 D2901 D2756
BIN(023) D2756 D2758

; rung 1207
LD W361.11
BIN(023) D2705 D2755  // 自動時左成形機旋回側押当流量
SCL(194) D2755 D2901 D2756
BIN(023) D2756 D2759
BIN(023) D2707 D2755  // 手動時左成形機旋回側押当流量
SCL(194) D2755 D2901 D2756
BIN(023) D2756 D2760
; rung 1208
LD W361.11
BIN(023) D2709 D2755  // 自動時右成形機旋回戻側押当流量
SCL(194) D2755 D2901 D2756
BIN(023) D2756 D2761
BIN(023) D2711 D2755  // 手動時右成形機旋回戻側押当流量
SCL(194) D2755 D2901 D2756
BIN(023) D2756 D2762

; rung 1209
LD W361.11
BIN(023) D2713 D2755  // 自動時右成形機旋回側押当流量
SCL(194) D2755 D2901 D2756
BIN(023) D2756 D2763
BIN(023) D2715 D2755  // 手動時右成形機旋回側押当流量
SCL(194) D2755 D2901 D2756
BIN(023) D2756 D2764
; rung 1210
LD W361.11
BIN(023) D2717 D2755  // 手動時左成形機旋回戻側通常流量
SCL(194) D2755 D2901 D2756
BIN(023) D2756 D2765
BIN(023) D2719 D2755  // 手動時左成形機旋回側通常流量
SCL(194) D2755 D2901 D2756
BIN(023) D2756 D2766

; rung 1211
LD W361.11
BIN(023) D2721 D2755  // 手動時右成形機旋回戻側通常流量
SCL(194) D2755 D2901 D2756
BIN(023) D2756 D2767
BIN(023) D2723 D2755  // 手動時右成形機旋回側通常流量
SCL(194) D2755 D2901 D2756
BIN(023) D2756 D2768
; rung 1212: ----- 調整時、主回路圧力(PV2) 30%固定 ----- / 但し移送調整時は 10%固定
LD W397.00
ANDNOT W396.12
ANDNOT W396.13
ORNOT W397.00
LD W182.13
ANDNOT W182.07
ANDNOT W182.08
ORNOT W182.13
ANDLD
LD W397.12
ANDNOT W397.08
ANDNOT W397.09
ORNOT W397.12
ANDLD
LD W182.13
ANDNOT W312.07
ANDNOT W312.08
ORNOT W182.13
ANDLD
LD W193.15
LD H8.14
AND T0020
ORLD
ANDLD
MOV(021) D243 D6083
MOV(021) D2977 D6065
; rung 1213
LD W396.12
OR W396.13
AND W397.00
LD W397.08
OR W397.09
AND W397.12
ORLD
AND W193.15
MOV(021) #4B0 D6083
MOV(021) #4B0 D6065
; rung 1214
LD P_On
AND 16.08
OUT TR0
AND>(320) D58 D6072
AND W422.02
OUT W422.00
LD TR0
AND>(320) D59 D6073
AND W422.03
OUT W422.01

; rung 1215
LD P_On
AND 16.08
+BC(406) D6072 #10 D6200
AND>(320) D58 D6200
OUT W422.02
; rung 1216
LD P_On
AND 16.08
+BC(406) D6073 #10 D6210
AND>(320) D59 D6210
OUT W422.03
; rung 1217
LD 2070.15
OR 2070.14
OR 2090.15
OR 2090.14
OR 457.04
OR 457.05
AND 16.08
AND W193.15
MOV(021) #640 D6083
MOV(021) #300 D6065
; rung 1218
LD W182.07
OR W182.08
OR W312.07
OR W312.08
AND W182.13
AND W193.15
MOV(021) #190 D6083
MOV(021) #190 D6065
; rung 1219: ----- 移送流量比例弁処置 ----- / 設定位置到達まではSINｶｰﾌﾞで出力
LD W193.15
AND W170.09
MOV(021) D287 D6081
MOV(021) D237 D6137

; rung 1220: --- 自動時位置到達後は押当流量設定 ---
LD T0021
OUT TR0
AND 14.13
AND W181.14
OUT W64.05
MOV(021) D2759 D6081
LD TR0
AND 14.12
AND W181.12
OUT W64.01
MOV(021) D2757 D6081
; rung 1221
LD T0021
OUT TR0
AND 14.15
AND W311.14
OUT W64.13
MOV(021) D2763 D6137
LD TR0
AND 14.14
AND W311.12
OUT W64.09
MOV(021) D2761 D6137
; rung 1222: --- 手動時移送流量処理 ---
LD W193.15
AND W170.13
OUT TR0
AND 14.13
OUT TR1
ANDNOT W181.14
OUT W64.07
MOV(021) D2766 D6081
LD TR1
AND W181.14
OUT W65.03
MOV(021) D2760 D6081
LD TR0
AND 14.12
OUT TR0
ANDNOT W181.12
OUT W64.03
MOV(021) D2765 D6081
LD TR0
AND W181.12
OUT W65.01
MOV(021) D2758 D6081

; rung 1223
LD W193.15
AND W170.13
OUT TR0
AND 14.15
OUT TR1
ANDNOT W311.14
OUT W64.15
MOV(021) D2768 D6137
LD TR1
AND W311.14
OUT W65.07
MOV(021) D2764 D6137
LD TR0
AND 14.14
OUT TR0
ANDNOT W311.12
OUT W64.11
MOV(021) D2767 D6137
LD TR0
AND W311.12
OUT W65.05
MOV(021) D2762 D6137
; rung 1224: ----- 左右型閉徐行流量は調整時も関係なく転送 -----
LD W193.15
MOV(021) D2961 D6053
; rung 1225
LD W193.15
MOV(021) D2965 D6054
; rung 1226
LDNOT 14.15
ANDNOT 14.14
MOV(021) #0 D6137
; rung 1227
LDNOT 14.13
ANDNOT 14.12
MOV(021) #0 D6081
; rung 1228
LD W193.15
MOV(021) D279 D6082

; rung 1229
LDNOT T0020
MOV(021) #0 D979
; rung 1230
LD T0020
ANDNOT W176.00
ANDNOT W176.03
ANDNOT W306.00
ANDNOT W306.03
ANDNOT W183.07
ANDNOT W189.01
ANDNOT W183.03
ANDNOT W397.00
ANDNOT W182.02
ANDNOT W182.03
ANDNOT W313.07
ANDNOT W319.01
ANDNOT W313.03
ANDNOT W397.12
ANDNOT W312.02
ANDNOT W312.03
ANDNOT H8.14
MOV(021) #200 D978  // 初期圧20.0%→40kgf/cm2
; rung 1231
LD H8.14
AND T0020
ANDNOT H8.13
MOV(021) #600 D978
; rung 1232
LD H8.13
AND T0020
MOV(021) #200 D978
; rung 1233
LDNOT W180.04
ANDNOT W180.03
ANDNOT W180.02
ANDNOT W180.01
ANDNOT W180.00
ANDNOT W180.07
ANDNOT W180.05
ANDNOT W180.06
ANDNOT W180.08
ANDNOT W182.13
ANDNOT W310.04
ANDNOT W310.03
ANDNOT W310.02
ANDNOT W310.01
ANDNOT W310.00
ANDNOT W310.07
ANDNOT W310.05
ANDNOT W310.06
ANDNOT W310.08
ANDNOT W397.00
ANDNOT W397.12
MOV(021) #0 D977
; rung 1234
LD W193.12
ANDNOT W360.15
@MOV(021) #0 D981
; rung 1235
LD W193.12
ANDNOT W360.14
@MOV(021) #0 D982
; rung 1236: ********** 油圧暖気、旋回ﾊﾞｲﾊﾟｽ自動ﾀｲﾏ処理 **********
LD P_1s
LD C0489
OR P_First_Cycle
CNT 0489 #6

; rung 1237
LDNOT H8.14
OR H8.13
MOV(021) #0 D406
; rung 1238
LD H8.14
OUT TR0
AND C0489
ANDNOT W109.06
@++B(594) D406
LD TR0
CMP(020) D406 D1006
LD P_EQ
OR P_GT
OR W109.06
ANDLD
OUT W109.06
DIFU(013) W57.15
MOV(021) D1006 D406
; rung 1239
LDNOT H8.14
ANDNOT H8.13
MOV(021) #0 D407
; rung 1240
LD H8.14
AND H8.13
OUT TR0
AND C0489
ANDNOT W109.07
@++B(594) D407
LD TR0
CMP(020) D407 D1007
LD P_EQ
OR P_GT
OR W109.07
ANDLD
OUT W109.07
DIFU(013) W57.14
MOV(021) D1007 D407

; rung 1241: ********** 旋回コントロール処理 **********
LD P_First_Cycle
MOV(021) #0 D2990
MOV(021) #0 D2991
MOV(021) #2000 D2992
MOV(021) #3E7 D2993
; rung 1242
LD P_First_Cycle
MOV(021) #0 D2994
MOV(021) #0 D2995
MOV(021) #4000 D2996
MOV(021) #3E7 D2997

; rung 1243: ********** 左旋回ｺﾝﾄﾛｰﾙ処理 ********** / ----- 移送調整の場合 -----
LD W182.13
MOV(021) #200 D698
MOV(021) #400 D653
MOV(021) #400 D657
MOV(021) #800 D659
MOV(021) #400 D661
MOV(021) #800 D663
MOV(021) #400 D665
; rung 1244: ----- 左移送速度設定が移送調整以外 -----
LD W170.09
ANDNOT W182.13
MOV(021) D547 D698
BIN(023) D547 D2998
SCL(194) D2998 D2990 D2999
MOV(021) D2999 D653
MOV(021) D2999 D657
MOV(021) D2999 D661
MOV(021) D2999 D665

; rung 1245
LD W170.09
ANDNOT W182.13
SCL(194) D2998 D2994 D2999
MOV(021) D2999 D659
MOV(021) D2999 D663
; rung 1246: ----- 左成形機旋回位置算出 ----- / 旋回は移動立上時は傾きは固定にして立ち上がり鋭くし、移動位置到達する場合は画面設定傾きによる。 / 成形位置(D200)と傾きより左成形可変位置(D743),左成形中間位置(D758)を求める
LD W190.03
OR W300.14
ANDNOT 16.05
ANDNOT W190.02
OUT W300.14
; rung 1247
LD P_On
MOVD(083) D698 #130 D3075
; rung 1248
LD W170.09
OUT TR0
AND 14.12
/B(434) D3075 D3068 D741
LD TR0
AND 14.13
/B(434) D698 #30 D741
; rung 1249
LD W170.09
CLC(041)
+BC(406) D200 D741 D743
BIN(023) D743 D747
; rung 1250
LD W170.09
CLC(041)
-BC(416) D743 D200 D744

; rung 1251
LD W170.09
/B(434) D744 #2 D745
CLC(041)
+BC(406) D745 D200 D758
BIN(023) D758 D748
; rung 1252
LD W170.09
BIN(023) D200 D749
; rung 1253: 待避位置(D202)と傾きより左待避可変位置(D723),左待避中間位置(D738)を求める
LD W170.09
OUT TR0
AND 14.13
OUT TR1
LDNOT W193.02
OR W223.04
ANDLD
/B(434) D3075 D3070 D721
LD TR1
AND W193.02
AND W223.00
/B(434) D3075 D3071 D721
LD TR0
AND 14.12
/B(434) D698 #30 D721
; rung 1254
LD W170.09
CLC(041)
-BC(416) D202 D721 D723
BIN(023) D723 D727

; rung 1255
LD W170.09
CLC(041)
-BC(416) D202 D723 D724
; rung 1256
LD W170.09
/B(434) D724 #2 D725
CLC(041)
+BC(406) D725 D723 D738
BIN(023) D738 D728
; rung 1257
LD W170.09
BIN(023) D202 D729
; rung 1258: 取出位置(D201)と取出位置傾き(D3069)より左取出減速開始位置(D763),左取出減速中間位置(D778) / (自動時待避位置から旋回戻りし取出位置で減速停止する)←今回不要につき固定値
LD W170.09
OUT TR0
AND 14.12
/B(434) D3075 #30 D761
LD TR0
AND 14.13
AND W193.05
AND W223.00
/B(434) D698 #30 D761
; rung 1259
LD W170.09
CLC(041)
+BC(406) D201 D761 D763
BIN(023) D763 D767

; rung 1260
LD W170.09
CLC(041)
-BC(416) D763 D201 D764
/B(434) D764 #2 D765
CLC(041)
+BC(406) D765 D201 D778
BIN(023) D778 D768
; rung 1261
LD W170.09
BIN(023) D201 D769
; rung 1262: 取出位置(D201)と取出位置傾き(3.0%固定)より左成形増速限位置(D783),左成形増速中間位置(D798) / (取出位置より成形位置に旋回戻りする場合)
LD W170.09
/B(434) D698 #30 D781
; rung 1263
LD W170.09
CLC(041)
-BC(416) D201 D781 D783
BIN(023) D783 D787

; rung 1264
LD W170.09
CLC(041)
-BC(416) D201 D783 D784
/B(434) D784 #2 D785
CLC(041)
+BC(406) D785 D783 D798
BIN(023) D798 D788
; rung 1265: 左成形可変位置(D747(BIN))＞左待避可変位置(D727(BIN))の時切換位置(D823(BIN))
LD W170.09
AND<(310) D727 D747
OUT W172.08
CLC(041)
-C(412) D747 D727 D820
/U(432) D820 #2 D821
CLC(041)
+C(402) D727 D821 D823

; rung 1266: 左待避位置(D727(BIN))＜左取出減速位置(D767(BIN))の時切換位置(D827(BIN))
LD W170.09
AND<(310) D727 D767
OUT W172.09
CLC(041)
-C(412) D767 D727 D824
/U(432) D824 #2 D825
CLC(041)
+C(402) D825 D727 D827
; rung 1267: 左成形増速位置(D787(BIN))＜左成形可変位置(D747(BIN))の時切換位置(D831(BIN))
LD W170.09
AND<(310) D787 D747
OUT W172.10
CLC(041)
-C(412) D747 D787 D828
/U(432) D828 #2 D829
CLC(041)
+C(402) D787 D829 D831
; rung 1268: ----- 左成形機旋回入力ﾃﾞｰﾀ(D650)の変更過程 -----
LD W170.09
BIN(023) D282 D739

; rung 1269: ----- 成形位置からの増速(成形位置から待避位置へ旋回) ----- / 左成形位置から成形中間位置
LD W170.09
MOV(021) #0 D810
MOV(021) D749 D811
MOV(021) #900 D812
MOV(021) D748 D813
; rung 1270
LD W170.09
AND 14.13
AND W172.08
AND<(310) D739 D823
OUT W169.00
; rung 1271
LD W169.00
ORNOT W172.08
AND W170.09
AND 14.13
AND<(310) D739 D748
SCL(194) D739 D810 D650
SCL(194) D652 D653 D669
; rung 1272: 成形中間位置から成形可変位置
LD W170.09
MOV(021) #0 D814
MOV(021) D747 D815
MOV(021) #900 D816
MOV(021) D748 D817
; rung 1273
LD W170.09
AND 14.13
AND W172.08
AND<(310) D739 D823
OUT W169.01

; rung 1274
LD W169.01
ORNOT W172.08
AND W170.09
AND 14.13
AND<=(315) D748 D739
OUT W172.00
; rung 1275
LD W169.01
ORNOT W172.08
AND W170.09
AND 14.13
AND W172.00
AND<(310) D739 D727
SCL(194) D739 D814 D650
SCL(194) D652 D657 D669
; rung 1276: ----- 待避位置への減速 ----- / 待避可変位置から待避中間位置
LD W170.09
MOV(021) #0 D730
MOV(021) D727 D731
MOV(021) #900 D732
MOV(021) D728 D733
; rung 1277
LD W170.09
AND 14.13
AND W172.08
AND>(320) D739 D823
OUT W169.02
; rung 1278
LD W169.02
ORNOT W172.08
AND W170.09
AND 14.13
AND<=(315) D727 D739
OUT W172.01
; rung 1279
LD W169.02
ORNOT W172.08
AND W170.09
AND 14.13
AND W172.01
AND<(310) D739 D728
SCL(194) D739 D730 D650
SCL(194) D652 D661 D669

; rung 1280: 待避中間位置から待避位置
LD W170.09
MOV(021) #0 D734
MOV(021) D729 D735
MOV(021) #900 D736
MOV(021) D728 D737
; rung 1281
LD W170.09
AND 14.13
AND W172.08
AND>(320) D739 D823
OUT W169.03
; rung 1282
LD W169.03
ORNOT W172.08
AND W170.09
AND 14.13
AND<=(315) D728 D739
SCL(194) D739 D734 D650
SCL(194) D652 D665 D669
; rung 1283: ----- 待避位置からの増速 ----- / 待避位置から待避中間位置
LD W170.09
MOV(021) #0 D800
MOV(021) D729 D801
MOV(021) #900 D802
MOV(021) D728 D803
; rung 1284
LD W170.09
AND 14.12
AND W172.09
AND>(320) D739 D827
OUT W169.04

; rung 1285
LD W169.04
LDNOT W172.08
ANDNOT W172.09
ORLD
AND W170.09
AND 14.12
AND<(310) D728 D739
SCL(194) D739 D800 D650
SCL(194) D652 D653 D669
; rung 1286: 待避中間位置から待避可変位置
LD W170.09
MOV(021) #0 D804
MOV(021) D727 D805
MOV(021) #900 D806
MOV(021) D728 D807
; rung 1287
LD W170.09
AND 14.12
AND W172.09
AND>(320) D739 D827
OUT W169.05
; rung 1288
LD W169.05
LDNOT W172.08
ANDNOT W172.09
ORLD
AND W170.09
AND 14.12
AND<(310) D747 D739
OUT W172.02
; rung 1289
LD W169.05
LDNOT W172.08
ANDNOT W172.09
ORLD
AND W170.09
AND 14.12
AND W172.02
AND<=(315) D739 D728
SCL(194) D739 D804 D650
SCL(194) D652 D657 D669

; rung 1290: ----- 成形位置への減速 ----- / 成形可変位置から成形中間位置
LD W170.09
MOV(021) #0 D750
MOV(021) D747 D751
MOV(021) #900 D752
MOV(021) D748 D753
; rung 1291
LD W170.09
AND 14.12
AND W172.10
AND<(310) D739 D831
OUT W169.10
; rung 1292
LD W169.10
LDNOT W172.08
ANDNOT W172.10
ORLD
AND W170.09
AND 14.12
AND<(310) D748 D739
OUT W172.07
; rung 1293
LD W169.10
LDNOT W172.08
ANDNOT W172.10
ORLD
AND W170.09
AND 14.12
AND W172.07
AND<=(315) D739 D747
SCL(194) D739 D750 D650
SCL(194) D652 D661 D669
; rung 1294: 成形中間位置から成形位置
LD W170.09
MOV(021) #0 D754
MOV(021) D749 D755
MOV(021) #900 D756
MOV(021) D748 D757

; rung 1295
LD W170.09
AND 14.12
AND W172.10
AND<(310) D739 D831
OUT W169.11
; rung 1296
LD W169.11
LDNOT W172.08
ANDNOT W172.10
ORLD
AND W170.09
AND 14.12
AND<=(315) D739 D748
SCL(194) D739 D754 D650
SCL(194) D652 D665 D669
; rung 1297
LDNOT 14.12
ANDNOT 14.13
MOV(021) #0 D650
MOV(021) #0 D669
; rung 1298: ----- 新方式の移送流量制御 ----- / 旋回開始からいきなり絞り側流量比例弁を設定値までズドンと上げる。 / 減速は従来通り、傾きから決定された位置から減速開始する。
LD P_On
OUT TR0
AND<(310) D282 D2728
AND>(320) D282 D2729
OUT W179.08
LD TR0
AND<(310) D282 D2734
OUT W178.12
LD TR0
AND<(310) D282 D2735
OUT W178.14
LD TR0
AND>(320) D282 D2736
OUT W178.13
LD TR0
AND>(320) D282 D2737
OUT W178.15
; rung 1299
LD 14.12
LD W176.05
AND H13.04
ORLD
ANDNOT W178.12
LD 14.13
LD W176.02
AND H13.04
ORLD
ANDNOT W178.13
ORLD
AND W193.12
AND W170.09
AND H13.04
BIN(023) D698 D2732
SCL(194) D2732 D2901 D669

; rung 1300
LD W178.12
AND 14.12
AND W193.12
AND W170.09
AND H13.04
OUT TR0
BIN(023) D2734 D2771
BIN(023) D2735 D2773
MOV(021) D698 D2770
MOV(021) D2701 D2772
SCL(194) D739 D2770 D2774
AND<(310) D2774 #30
MOV(021) #30 D2774  // ｽｹｰﾘﾝｸﾞによって、あまりにも小さな流量になるのを防ぐ為
LD TR0
BIN(023) D2774 D2738
SCL(194) D2738 D2901 D669

; rung 1301
LD W178.13
AND 14.13
AND W193.12
AND W170.09
AND H13.04
OUT TR0
BIN(023) D2736 D2776
BIN(023) D2737 D2778
MOV(021) D698 D2775
MOV(021) D2705 D2777
SCL(194) D739 D2775 D2779
AND<(310) D2779 #30
MOV(021) #30 D2779  // ｽｹｰﾘﾝｸﾞによって、あまりにも小さな値になるのを防ぐ為
LD TR0
BIN(023) D2779 D2739
SCL(194) D2739 D2901 D669
; rung 1302: APR(#0001)はCOS計算0ﾟ～90ﾟ(1～0だが出力ﾃﾞｰﾀは9999～0000) / D650(#0000～#0900),D651(#9999～#0000),D652(#270F～#0000)
LD W170.09
APR(069) #1 D650 D651
BIN(023) D651 D652
; rung 1303: 各旋回用ｽｹｰﾘﾝｸﾞﾃﾞｰﾀ
LD W170.09
MOV(021) #0 D654
MOV(021) #0 D655
MOV(021) #270F D656

; rung 1304
LD W170.09
MOV(021) #0 D658
MOV(021) #270F D660
; rung 1305
LD W170.09
MOV(021) #0 D662
MOV(021) #270F D664
; rung 1306
LD W170.09
MOV(021) #0 D666
MOV(021) #0 D667
MOV(021) #270F D668
; rung 1307: ----- 旋回ｸﾞﾗﾌより流量設定値にｽｹｰﾘﾝｸﾞする ----- / 旋回ｸﾞﾗﾌは0～4000で0～99.9%を表す
LD W170.09
BIN(023) D669 D670
; rung 1308
LD W170.09
MOV(021) #0 D672
MOV(021) #0 D673
MOV(021) #999 D674
MOV(021) #FA0 D675

; rung 1309
LD W170.09
SCL(194) D670 D672 D976
; rung 1310
LDNOT W180.08
ANDNOT W182.13
MOV(021) #0 D976
; rung 1311: ********** 右旋回ｺﾝﾄﾛｰﾙ処理 **********
LD W182.13
MOV(021) #200 D699
MOV(021) #400 D2873
MOV(021) #400 D2877
MOV(021) #800 D2879
MOV(021) #400 D2881
MOV(021) #800 D2883
MOV(021) #400 D2885

; rung 1312: ----- 右移送速度設定が移送調整以外 -----
LD W170.09
ANDNOT W182.13
MOV(021) D577 D699
BIN(023) D577 D2998
SCL(194) D2998 D2990 D2999
MOV(021) D2999 D2873
MOV(021) D2999 D2877
MOV(021) D2999 D2881
MOV(021) D2999 D2885
; rung 1313
LD W170.09
ANDNOT W182.13
SCL(194) D2998 D2994 D2999
MOV(021) D2999 D2879
MOV(021) D2999 D2883
; rung 1314: ----- 右成形機旋回位置算出 ----- / 成形位置と傾きより右成形可変位置(D863),右成形中間位置(D878)を求める
LD W190.03
OR W300.15
ANDNOT 16.07
ANDNOT W190.02
OUT W300.15
; rung 1315
LD P_On
MOVD(083) D699 #130 D3074

; rung 1316
LD W170.09
OUT TR0
AND 14.14
/B(434) D3074 D3061 D861
LD TR0
AND 14.15
/B(434) D699 #30 D861
; rung 1317
LD W170.09
CLC(041)
+BC(406) D205 D861 D863
BIN(023) D863 D867
; rung 1318
LD W170.09
CLC(041)
-BC(416) D863 D205 D864
; rung 1319
LD W170.09
/B(434) D864 #2 D865
CLC(041)
+BC(406) D865 D205 D878
BIN(023) D878 D868
; rung 1320
LD W170.09
BIN(023) D205 D869

; rung 1321: 待避位置と傾きより右待避可変位置(D843),右待避中間位置(D858)を求める
LD W170.09
OUT TR0
AND 14.15
OUT TR1
LDNOT W193.02
OR W225.01
ANDLD
/B(434) D3074 D3063 D841
LD TR1
AND W193.02
AND W224.13
/B(434) D3074 D3064 D841
LD TR0
AND 14.14
/B(434) D699 #30 D841
; rung 1322
LD W170.09
CLC(041)
-BC(416) D207 D841 D843
BIN(023) D843 D847
; rung 1323
LD W170.09
CLC(041)
-BC(416) D207 D843 D844
; rung 1324
LD W170.09
/B(434) D844 #2 D845
CLC(041)
+BC(406) D845 D843 D858
BIN(023) D858 D848

; rung 1325
LD W170.09
BIN(023) D207 D849
; rung 1326: 取出位置と取出位置傾きより右取出減速開始位置(D883),右取出減速中間位置(D898) / 今回不要につき固定値
LD W170.09
OUT TR0
AND 14.14
/B(434) D3074 #30 D881
LD TR0
AND 14.15
AND W193.05
AND W224.13
/B(434) D699 #30 D881
; rung 1327
LD W170.09
CLC(041)
+BC(406) D206 D881 D883
BIN(023) D883 D887
; rung 1328
LD W170.09
CLC(041)
-BC(416) D883 D206 D884
/B(434) D884 #2 D885
CLC(041)
+BC(406) D885 D206 D898
BIN(023) D898 D888
; rung 1329
LD W170.09
BIN(023) D206 D889

; rung 1330: 取出位置と取出位置傾き(3.0%固定)より右成形増速限位置(D903),右成形増速中間位置(D918)を求める
LD W170.09
/B(434) D699 #30 D901
; rung 1331
LD W170.09
CLC(041)
-BC(416) D206 D901 D903
BIN(023) D903 D907
; rung 1332
LD W170.09
CLC(041)
-BC(416) D206 D903 D904
/B(434) D904 #2 D905
CLC(041)
+BC(406) D905 D903 D918
BIN(023) D918 D908

; rung 1333: 右成形可変位置(D867(BIN))＞右待避可変位置(D847(BIN))の時切換位置(D953(BIN))
LD W170.09
AND<(310) D847 D867
OUT W302.08
CLC(041)
-C(412) D867 D847 D940
/U(432) D940 #2 D941
CLC(041)
+C(402) D847 D941 D943
; rung 1334: 右待避位置(D847(BIN))＜右取出減速位置(D887(BIN))の時切換位置(D947(BIN))
LD W170.09
AND<(310) D847 D887
OUT W302.09
CLC(041)
-C(412) D887 D847 D944
/U(432) D944 #2 D945
CLC(041)
+C(402) D945 D847 D947

; rung 1335: 右成形増速限位置(D907(BIN))<右成形可変位置(D0867(BIN))の時切替位置
LD W170.09
AND<(310) D907 D867
OUT W302.10
CLC(041)
-C(412) D867 D907 D948
/U(432) D948 #2 D949
CLC(041)
+C(402) D907 D949 D951
; rung 1336: ----- 右成形機旋回入力ﾃﾞｰﾀ(D2870)の変更過程 -----
LD W170.09
BIN(023) D232 D859
; rung 1337: ----- 成形位置からの増速(成形位置から待避位置へ旋回) ----- / 成形位置から成形中間位置
LD W170.09
MOV(021) #0 D930
MOV(021) D869 D931
MOV(021) #900 D932
MOV(021) D868 D933
; rung 1338
LD W170.09
AND 14.15
AND W302.08
AND<(310) D859 D943
OUT W168.00

; rung 1339
LD W168.00
ORNOT W302.08
AND W170.09
AND 14.15
AND<(310) D859 D868
SCL(194) D859 D930 D2870
SCL(194) D2872 D2873 D2889
; rung 1340: 成形中間位置から成形可変位置
LD W170.09
MOV(021) #0 D934
MOV(021) D867 D935
MOV(021) #900 D936
MOV(021) D868 D937
; rung 1341
LD W170.09
AND 14.15
AND W302.08
AND<(310) D859 D943
OUT W168.01
; rung 1342
LD W168.01
ORNOT W302.08
AND W170.09
AND 14.15
AND<=(315) D868 D859
OUT W302.00
; rung 1343
LD W168.01
ORNOT W302.08
AND W170.09
AND 14.15
AND W302.00
AND<(310) D859 D847
SCL(194) D859 D934 D2870
SCL(194) D2872 D2877 D2889

; rung 1344: ----- 待避位置への減速 ----- / 待避可変位置から待避中間位置
LD W170.09
MOV(021) #0 D850
MOV(021) D847 D851
MOV(021) #900 D852
MOV(021) D848 D853
; rung 1345
LD W170.09
AND 14.15
AND W302.08
AND>(320) D859 D943
OUT W168.02
; rung 1346
LD W168.02
ORNOT W302.08
AND W170.09
AND 14.15
AND<=(315) D847 D859
OUT W302.01
; rung 1347
LD W168.02
ORNOT W302.08
AND W170.09
AND 14.15
AND W302.01
AND<(310) D859 D848
SCL(194) D859 D850 D2870
SCL(194) D2872 D2881 D2889
; rung 1348: 待避中間位置から待避位置
LD W170.09
MOV(021) #0 D854
MOV(021) D849 D855
MOV(021) #900 D856
MOV(021) D848 D857

; rung 1349
LD W170.09
AND 14.15
AND W302.08
AND>(320) D859 D943
OUT W168.03
; rung 1350
LD W168.03
ORNOT W302.08
AND W170.09
AND 14.15
AND<=(315) D848 D859
SCL(194) D859 D854 D2870
SCL(194) D2872 D2885 D2889
; rung 1351: ----- 待避位置からの増速 ----- / 待避位置から待避中間位置
LD W170.09
MOV(021) #0 D920
MOV(021) D849 D921
MOV(021) #900 D922
MOV(021) D848 D923
; rung 1352
LD W170.09
AND 14.14
AND W302.09
AND>(320) D859 D947
OUT W168.04
; rung 1353
LD W168.04
LDNOT W302.08
ANDNOT W302.09
ORLD
AND W170.09
AND 14.14
AND<(310) D848 D859
SCL(194) D859 D920 D2870
SCL(194) D2872 D2873 D2889

; rung 1354: 待避中間位置から待避可変位置
LD W170.09
MOV(021) #0 D924
MOV(021) D847 D925
MOV(021) #900 D926
MOV(021) D848 D927
; rung 1355
LD W170.09
AND 14.14
AND W302.09
AND>(320) D859 D947
OUT W168.05
; rung 1356
LD W168.05
LDNOT W302.08
ANDNOT W302.09
ORLD
AND W170.09
AND 14.14
AND<(310) D867 D859
OUT W302.02
; rung 1357
LD W168.05
LDNOT W302.08
ANDNOT W302.09
ORLD
AND W170.09
AND 14.14
AND W302.02
AND<=(315) D859 D848
SCL(194) D859 D924 D2870
SCL(194) D2872 D2877 D2889
; rung 1358: ----- 成形位置への減速 ----- / 成形可変位置から成形中間位置
LD W170.09
MOV(021) #0 D870
MOV(021) D867 D871
MOV(021) #900 D872
MOV(021) D868 D873

; rung 1359
LD W170.09
AND 14.14
AND W302.10
AND<(310) D859 D951
OUT W168.10
; rung 1360
LD W168.10
LDNOT W302.08
ANDNOT W302.10
ORLD
AND W170.09
AND 14.14
AND<(310) D868 D859
OUT W302.07
; rung 1361
LD W168.10
LDNOT W302.08
ANDNOT W302.10
ORLD
AND W170.09
AND 14.14
AND W302.07
AND<=(315) D859 D867
SCL(194) D859 D870 D2870
SCL(194) D2872 D2881 D2889
; rung 1362: 成形中間位置から成形位置
LD W170.09
MOV(021) #0 D874
MOV(021) D869 D875
MOV(021) #900 D876
MOV(021) D868 D877
; rung 1363
LD W170.09
AND 14.14
AND W302.10
AND<(310) D859 D951
OUT W168.11
; rung 1364
LD W168.11
LDNOT W302.08
ANDNOT W302.10
ORLD
AND W170.09
AND 14.14
AND<=(315) D859 D868
SCL(194) D859 D874 D2870
SCL(194) D2872 D2885 D2889

; rung 1365
LDNOT 14.14
ANDNOT 14.15
MOV(021) #0 D2870
MOV(021) #0 D2889
; rung 1366: ----- 新方式の移送流量制御 ----- / 旋回開始からいきなり絞り側流量比例弁を設定値までズドンと上げる。 / 減速は従来通り、傾きから決定された位置から減速開始する。
LD P_On
OUT TR0
AND<(310) D232 D2730
AND>(320) D232 D2731
OUT W179.09
LD TR0
AND<(310) D232 D2744
OUT W179.12
LD TR0
AND<(310) D232 D2745
OUT W179.14
LD TR0
AND>(320) D232 D2746
OUT W179.13
LD TR0
AND>(320) D232 D2747
OUT W179.15
; rung 1367
LD 14.14
LD W306.05
AND H13.04
ORLD
ANDNOT W179.12
LD 14.15
LD W306.02
AND H13.04
ORLD
ANDNOT W179.13
ORLD
AND W193.12
AND W170.09
AND H13.04
BIN(023) D699 D2733
SCL(194) D2733 D2901 D2889

; rung 1368
LD W179.12
AND 14.14
AND W193.12
AND W170.09
AND H13.04
OUT TR0
BIN(023) D2744 D2781
BIN(023) D2745 D2783
MOV(021) D699 D2780
MOV(021) D2709 D2782
SCL(194) D859 D2780 D2784
AND<(310) D2784 #30
MOV(021) #30 D2784  // ｽｹｰﾘﾝｸﾞによって、あまりにも小さな流量になるのを防ぐ為
LD TR0
BIN(023) D2784 D2748
SCL(194) D2748 D2901 D2889

; rung 1369
LD W179.13
AND 14.15
AND W193.12
AND W170.09
AND H13.04
OUT TR0
BIN(023) D2746 D2786
BIN(023) D2747 D2788
MOV(021) D699 D2785
MOV(021) D2713 D2787
SCL(194) D859 D2785 D2789
AND<(310) D2789 #30
MOV(021) #30 D2789  // ｽｹｰﾘﾝｸﾞによって、あまりにも小さな流量になるのを防ぐ為
LD TR0
BIN(023) D2789 D2749
SCL(194) D2749 D2901 D2889
; rung 1370: APR(#0001)はCOS計算 / D2870(#0000～#0900),D2871(#9999～#0000),D2872(#270F～#0000)
LD W170.09
APR(069) #1 D2870 D2871
BIN(023) D2871 D2872
; rung 1371: 各旋回用ｽｹｰﾘﾝｸﾞﾃﾞｰﾀ
LD W170.09
MOV(021) #0 D2874
MOV(021) #0 D2875
MOV(021) #270F D2876

; rung 1372
LD W170.09
MOV(021) #0 D2878
MOV(021) #270F D2880
; rung 1373
LD W170.09
MOV(021) #0 D2882
MOV(021) #270F D2884
; rung 1374
LD W170.09
MOV(021) #0 D2886
MOV(021) #0 D2887
MOV(021) #270F D2888
; rung 1375: ----- 旋回ｸﾞﾗﾌより流量設定値にｽｹｰﾘﾝｸﾞする ----- / 旋回ｸﾞﾗﾌは0～4000で0～99.9%を表す
LD W170.09
BIN(023) D2889 D2890
; rung 1376
LD W170.09
MOV(021) #0 D2892
MOV(021) #0 D2893
MOV(021) #999 D2894
MOV(021) #FA0 D2895

; rung 1377
LD W170.09
SCL(194) D2890 D2892 D980
; rung 1378
LDNOT W310.08
ANDNOT W182.13
MOV(021) #0 D980
; rung 1379: ********** DAﾕﾆｯﾄ出力 ********** / 比例弁調整で自動又は手動結果出力によりDA出力 / (最終的なDA出力) / ----- 左移送流量 FV1 -----
LDNOT W394.01
SCL(194) D6081 D2916 2021
BIN(023) 2021 2021
; rung 1380: ----- 保圧圧力 PV1 -----
LDNOT W394.01
SCL(194) D6082 D2920 2022
BIN(023) 2022 2022
; rung 1381: ----- 主回路圧力 PV2 -----
LDNOT W394.01
SCL(194) D6083 D2924 2023
BIN(023) 2023 2023
; rung 1382: ----- 右移送流量 FV2 -----
LDNOT W394.01
SCL(194) D6137 D2966 2024
BIN(023) 2024 2024

; rung 1383: ----- 左型閉徐行流量 FV3 -----
LDNOT W394.01
SCL(194) D6053 D2939 2025
BIN(023) 2025 2025
; rung 1384: ----- 右型閉徐行流量 FV4 -----
LDNOT W394.01
SCL(194) D6054 D2947 2026
BIN(023) 2026 2026
; rung 1385: ----- 主回路流量比例弁 FV11 -----
LDNOT W394.01
SCL(194) D6065 D2970 2027
BIN(023) 2027 2027
; rung 1386: '
LDNOT W394.01
ANDNOT W193.15
OR W384.00
MOV(021) #0 2021
MOV(021) #0 D6081
; rung 1387
LDNOT W394.01
ANDNOT W193.15
OR W384.00
MOV(021) #0 2022
MOV(021) #0 D6082

; rung 1388
LDNOT H8.14
ANDNOT W394.01
ANDNOT W193.15
OR W384.00
MOV(021) #0 2023
MOV(021) #0 D6083
; rung 1389
LDNOT H8.14
ANDNOT W394.01
ANDNOT W193.15
OR W384.00
MOV(021) #0 2027
MOV(021) #0 D6065
; rung 1390
LDNOT W394.01
ANDNOT W193.15
OR W384.00
MOV(021) #0 2024
MOV(021) #0 D6137
; rung 1391
LDNOT W394.01
ANDNOT W193.15
OR W384.00
MOV(021) #0 2025
MOV(021) #0 D6053
; rung 1392
LDNOT W394.01
ANDNOT W193.15
OR W384.00
MOV(021) #0 2026
MOV(021) #0 D6054

; rung 1393: ********** 画面の圧力、流量現在値ﾓﾆﾀ ********** / 0～FA0で0～99.9%表示
LD P_On
MOV(021) #0 D6077
MOV(021) #0 D6078
MOV(021) #999 D6079
MOV(021) #FA0 D6080
; rung 1394
LD P_On
SCL(194) D6081 D6077 D6074
SCL(194) D6082 D6077 D6075
SCL(194) D6083 D6077 D6076
SCL(194) D6065 D6077 D6064
; rung 1395
LD P_On
SCL(194) D6137 D6077 D6136
SCL(194) D6053 D6077 D6042
SCL(194) D6054 D6077 D6052

; rung 1396: ********** 比例弁調整処理 **********
LDNOT W509.15
AND W379.03
OUT TR0
AND W378.09
OUT W360.12
LD TR0
AND W378.10
OUT W360.13
; rung 1397
LD W394.00
OR W394.01
LD W360.12
OR W360.13
ANDLD
ANDNOT W394.02
ANDNOT W193.05
ANDNOT W384.00
ANDNOT W384.03
OUT W394.01
; rung 1398
LD W360.12
OR W360.13
ANDNOT W394.01
OUT W394.03
; rung 1399: ----- 比例弁調整画面MONITORの指令(%)表示 -----
LD W360.12
MOV(021) D6074 D6103
MOV(021) D6075 D6104
MOV(021) D6076 D6105
MOV(021) D6136 D6128
MOV(021) D6042 D6034
MOV(021) D6052 D6044
; rung 1400
LD W360.13
MOV(021) D6064 D6056

; rung 1401: ----- 比例弁調整画面MONITORの電流値表示 ----- / 電流値ｽｹｰﾘﾝｸﾞﾃﾞｰﾀは、1996.8.20(MB60034D FV1)にて実測.理論値は、実測より5%大きくでた。補正済み / 2.0V(320H)→2000mAを2.2V(360H)→2000mAに変更
LD W360.12
OR W360.13
@MOV(021) #0 D6084
@MOV(021) #0 D6085
@MOV(021) #2000 D6086
@MOV(021) #360 D6087
; rung 1402
LD P_On
SCL(194) 2013 D6084 D6100
SCL(194) 2011 D6084 D6101
SCL(194) 2012 D6084 D6102
SCL(194) 2007 D6084 D6055
; rung 1403
LD P_On
SCL(194) 2014 D6084 D6127
SCL(194) 2015 D6084 D6033
SCL(194) 2018 D6084 D6043

; rung 1404: ----- 比例弁調整画面表示時、手動SCLﾃﾞｰﾀ2及び4ｾｯﾄ -----
LD W360.12
@MOV(021) #0 D2917
@MOV(021) #0 D2921
@MOV(021) #0 D2925
@MOV(021) #FA0 D2919
@MOV(021) #FA0 D2923
@MOV(021) #FA0 D2927
; rung 1405
LD W360.12
@MOV(021) #0 D2967
@MOV(021) #0 D2940
@MOV(021) #0 D2948
@MOV(021) #FA0 D2969
@MOV(021) #FA0 D2942
@MOV(021) #FA0 D2950
; rung 1406
LD W360.13
@MOV(021) #0 D2971
@MOV(021) #FA0 D2973

; rung 1407: ***** 左移送流量比例弁(FV1)調整処理 ***** / ----- 手動設定 -----
LD W360.12
BIN(023) D6121 D2800
SCL(194) D2800 D2901 D2916
BIN(023) D6122 D2801
SCL(194) D2801 D2901 D2918
; rung 1408: ----- 強制出力 -----
LD W394.04
AND W394.09
OR W394.10
AND W394.01
ANDNOT W394.11
OUT W394.10
@MOV(021) #0 D6112
BIN(023) D6112 D2814
SCL(194) D2814 D2901 D2932
BIN(023) D2932 2021
; rung 1409
LDNOT W394.10
OUT W394.12
; rung 1410
LD W394.11
@MOV(021) #0 2021
; rung 1411
LD W49.08
ANDNOT T0021
BIN(023) D2918 D2989
MOV(021) D2989 2021

; rung 1412: ***** 保圧圧力比例弁(PV1)調整処理 ***** / ----- 手動設定 -----
LD W360.12
BIN(023) D6123 D2802
SCL(194) D2802 D2901 D2920
BIN(023) D6124 D2803
SCL(194) D2803 D2901 D2922
; rung 1413: ----- 強制出力 -----
LD W394.04
AND W395.01
OR W395.02
AND W394.01
ANDNOT W395.03
OUT W395.02
@MOV(021) #0 D6113
BIN(023) D6113 D2815
SCL(194) D2815 D2901 D2933
BIN(023) D2933 2022
; rung 1414
LDNOT W395.02
OUT W395.04
; rung 1415
LD W395.03
@MOV(021) #0 2022

; rung 1416: ***** 主回路圧力比例弁(PV2)調整処理 ***** / ----- 手動設定 -----
LD W360.12
BIN(023) D6125 D2804
SCL(194) D2804 D2901 D2924
BIN(023) D6126 D2805
SCL(194) D2805 D2901 D2926
; rung 1417: ----- 強制出力 -----
LD W394.04
AND W393.01
OR W393.02
AND W394.01
ANDNOT W393.03
OUT W393.02
@MOV(021) #0 D6114
BIN(023) D6114 D2816
SCL(194) D2816 D2901 D2934
BIN(023) D2934 2023
; rung 1418
LDNOT W393.02
OUT W393.04
; rung 1419
LD W393.03
@MOV(021) #0 2023

; rung 1420: ***** 右移送流量比例弁(FV2)調整処理 ***** / ----- 手動設定 -----
LD W360.12
BIN(023) D6134 D2806
SCL(194) D2806 D2901 D2966
BIN(023) D6135 D2807
SCL(194) D2807 D2901 D2968
; rung 1421: ----- 強制出力 -----
LD W394.04
AND W391.09
OR W391.10
AND W394.01
ANDNOT W391.11
OUT W391.10
@MOV(021) #0 D6131
BIN(023) D6131 D2817
SCL(194) D2817 D2901 D2982
BIN(023) D2982 2024
; rung 1422
LDNOT W391.10
OUT W391.12
; rung 1423
LD W391.11
@MOV(021) #0 2024
; rung 1424
LD W49.08
ANDNOT T0021
BIN(023) D2968 D2988
MOV(021) D2988 2024

; rung 1425: ***** 左型閉徐行流量比例弁(FV3)調整処理 ***** / ----- 手動設定 -----
LD W360.12
BIN(023) D6040 D2808
SCL(194) D2808 D2901 D2939
BIN(023) D6041 D2809
SCL(194) D2809 D2901 D2941
; rung 1426: ----- 強制出力 -----
LD W394.04
AND W361.02
OR W362.02
AND W394.01
ANDNOT W361.03
OUT W362.02
@MOV(021) #0 D6037
BIN(023) D6037 D2818
SCL(194) D2818 D2901 D2951
BIN(023) D2951 2025
; rung 1427
LDNOT W362.02
OUT W362.03
; rung 1428
LD W361.03
@MOV(021) #0 2025

; rung 1429: ***** 右型閉徐行流量比例弁(FV4)調整処理 ***** / ----- 手動設定 -----
LD W360.12
BIN(023) D6050 D2810
SCL(194) D2810 D2901 D2947
BIN(023) D6051 D2811
SCL(194) D2811 D2901 D2949
; rung 1430: ----- 強制出力 -----
LD W394.04
AND W361.08
OR W362.08
AND W394.01
ANDNOT W361.09
OUT W362.08
@MOV(021) #0 D6047
BIN(023) D6047 D2819
SCL(194) D2819 D2901 D2952
BIN(023) D2952 2026
; rung 1431
LDNOT W362.08
OUT W362.09
; rung 1432
LD W361.09
@MOV(021) #0 2026

; rung 1433: ***** 主回路流量比例弁(FV11)調整処理 ***** / ----- 手動設定 -----
LD W360.13
BIN(023) D6062 D2812
SCL(194) D2812 D2901 D2970
BIN(023) D6063 D2813
SCL(194) D2813 D2901 D2972
; rung 1434: ----- 強制出力 -----
LD W394.04
AND W391.14
OR W392.14
AND W394.01
ANDNOT W391.15
OUT W392.14
@MOV(021) #0 D6059
BIN(023) D6059 D2820
SCL(194) D2820 D2901 D2953
BIN(023) D2953 2027
; rung 1435
LDNOT W392.14
OUT W392.15
; rung 1436
LD W391.15
@MOV(021) #0 2027

; rung 1437: ********** 型締圧力ﾓﾆﾀ処理 ********** / 4～20mA(1～5V)/0～50.0MPa / ADは3.2～20.8mA(0.8～5.2V)まで測定可能→ -2.5～52.5MPa / --- 生値桁上SCLﾃﾞｰﾀ ---
LD P_On
MOV(021) #0 D620
MOV(021) #0 D621
MOV(021) #4400 D622
MOV(021) #1130 D623
; rung 1438: --- 型締圧負数SCLﾃﾞｰﾀ ---
LD P_On
MOV(021) #25 D624
MOV(021) #0 D625
MOV(021) #0 D626
MOV(021) #C8 D627
; rung 1439: --- 型締圧正数SCLﾃﾞｰﾀ ---
LD P_On
MOV(021) #0 D628
MOV(021) #C8 D629
MOV(021) #500 D630
MOV(021) #1068 D631

; rung 1440: --- 左型締圧桁上 ---
LD P_On
CLC(041)
+C(402) 2005 #C8 D632
SCL(194) D632 D620 D633
; rung 1441: --- 左型締圧力正負判別 ---
LD P_On
AND>(320) #200 D633
OUT W165.11
; rung 1442: --- 左型締圧力負数表示 ---
LD W165.11
BIN(023) D633 D634
SCL(194) D634 D624 D635
MOVD(083) #FFFF #303 D635
; rung 1443: ---左型締圧力正数処理 ----
LDNOT W165.11
OUT TR0
AND<(310) #4200 D633
MOV(021) #4200 D633
LD TR0
BIN(023) D633 D634
SCL(194) D634 D628 D635

; rung 1444: --- 右型締圧桁上 ---
LD P_On
CLC(041)
+C(402) 2006 #C8 D632
SCL(194) D632 D620 D633
; rung 1445: --- 右型締圧力正負判別 ---
LD P_On
AND>(320) #200 D633
OUT W165.10
; rung 1446: --- 右型締圧力負数表示 ---
LD W165.10
BIN(023) D633 D634
SCL(194) D634 D624 D636
MOVD(083) #FFFF #303 D636
; rung 1447: ---右型締圧力正数処理 ----
LDNOT W165.10
OUT TR0
AND<(310) #4200 D633
MOV(021) #4200 D633
LD TR0
BIN(023) D633 D634
SCL(194) D634 D628 D636

; rung 1448: ********** 左カウンタ処理 **********
LD W207.00
OR H6.12
ANDNOT W207.01
OUT H6.12
; rung 1449
LD H6.12
OUT W207.12
; rung 1450
LDNOT H6.12
OUT W207.13
; rung 1451
LD W207.03
OR H6.13
ANDNOT W207.04
OUT H6.13
; rung 1452
LD H6.13
OUT W207.15
; rung 1453
LDNOT H6.13
OUT W208.00
; rung 1454
LD P_On
MOV(021) #0 D289
MOV(021) #1 D288
; rung 1455
LD W356.08
AND T1121
OUT TR0
AND H6.12
CLC(041)
@+BCL(407) D522 D288 D522
LD TR0
AND H6.13
CLC(041)
@+BCL(407) D526 D288 D526

; rung 1456: 左トータルカウンタリセット処理
LD W207.02
TIM 0040 #20
OUT W207.14
; rung 1457
LD T0040
@MOV(021) #0 D522
@MOV(021) #0 D523
; rung 1458: 左直毎カウンタリセット処理
LD W207.05
TIM 0041 #20
OUT W208.01
; rung 1459
LD T0041
@MOV(021) #0 D526
@MOV(021) #0 D527
; rung 1460: ********** 右カウンタ処理 **********
LD W207.06
OR H6.14
ANDNOT W207.07
OUT H6.14
; rung 1461
LD H6.14
OUT W208.02
; rung 1462
LDNOT H6.14
OUT W208.03

; rung 1463
LD W207.09
OR H6.15
ANDNOT W207.10
OUT H6.15
; rung 1464
LD H6.15
OUT W208.05
; rung 1465
LDNOT H6.15
OUT W208.06
; rung 1466
LD P_On
MOV(021) #0 D294
MOV(021) #1 D293
; rung 1467
LD W356.09
AND T1321
OUT TR0
AND H6.14
CLC(041)
@+BCL(407) D524 D293 D524
LD TR0
AND H6.15
CLC(041)
@+BCL(407) D528 D293 D528
; rung 1468: 右トータルカウンタリセット処理
LD W207.08
TIM 0043 #20
OUT W208.04
; rung 1469
LD T0043
@MOV(021) #0 D524
@MOV(021) #0 D525

; rung 1470: 右直毎カウンタリセット処理
LD W207.11
TIM 0044 #20
OUT W208.07
; rung 1471
LD T0044
@MOV(021) #0 D528
@MOV(021) #0 D529
; rung 1472: ********** 左サイクル監視処理 **********
LD W223.00
OR W176.10
AND T0021
ANDNOT W223.01
OUT W176.10
TIM 0048 #5
ANDNOT T0048
OUT W176.11
; rung 1473
LD W176.11
ORNOT T0021
DIFU(013) W176.12
; rung 1474
LD T0021
OR W190.02
OUT TR0
AND W183.14
DIFU(013) W176.13
LD TR0
LD W176.13
OR W176.14
ANDLD
ANDNOT W176.15
OUT W176.14
LD TR0
AND W176.14
AND W223.00
DIFU(013) W176.15
; rung 1475
LD T0021
OR W190.02
OUT TR0
AND W176.15
@MOV(021) T1100 D520
LD TR0
AND W170.00
LD W176.12
TTIM(087) 1100 D1100

; rung 1476: ***** 右サイクル監視処理 *****
LD W224.13
OR W306.10
AND T0021
ANDNOT W224.14
OUT W306.10
TIM 0049 #5
ANDNOT T0049
OUT W306.11
; rung 1477
LD W306.11
ORNOT T0021
DIFU(013) W306.12
; rung 1478
LD T0021
OR W190.02
OUT TR0
AND W313.14
DIFU(013) W306.13
LD TR0
LD W306.13
OR W306.14
ANDLD
ANDNOT W306.15
OUT W306.14
LD TR0
AND W306.14
AND W224.13
DIFU(013) W306.15
; rung 1479
LD T0021
OR W190.02
OUT TR0
AND W306.15
@MOV(021) T1300 D521
LD TR0
ANDNOT W161.12
AND W170.01
LD W306.12
TTIM(087) 1300 D1300
; rung 1480: ********** 警報処理 ********** / 警報画面追加により接点節約の為ﾘｾｯﾄ回路変更
LD 11.01
DIFU(013) W374.14
; rung 1481
LD W63.15
TIM 0035 #30
; rung 1482
LD T0035
OUT W447.00

; rung 1483
LD 11.02
ORNOT H1.07
OUT W385.14
; rung 1484: ********** 警報１処理 ********** / ----- 警報1 -----
LD T0511
OUT TR0
LD T0031
ANDNOT 10.00
OR W384.00
ANDLD
ANDNOT W374.14
OUT W384.00
LD TR0
LD W384.00
AND W385.14
OR W386.00
ANDLD
ANDNOT W374.14
OUT W386.00
LD TR0
LD P_1s
OR W386.00
ANDLD
AND W384.00
OUT W398.00
; rung 1485: ----- 警報2 -----
LD T0511
OUT TR0
AND W170.00
AND W396.00
TIM 0422 #5
LD TR0
AND W170.01
AND W396.02
TIM 0423 #5
; rung 1486
LD T0511
OUT TR0
LD T0422
OR T0423
OR W384.01
ANDLD
ANDNOT W374.14
OUT W384.01
LD TR0
LD W384.01
AND W385.14
OR W386.01
ANDLD
ANDNOT W374.14
OUT W386.01
LD TR0
LD P_1s
OR W386.01
ANDLD
AND W384.01
OUT W398.01

; rung 1487
LD W384.01
OUT TR0
LD T0422
OR W191.04
ANDLD
AND W170.00
OUT W191.04
LD TR0
LD T0423
OR W191.05
ANDLD
AND W170.01
OUT W191.05
; rung 1488: ----- 警報3 -----
LD T0511
OUT TR0
LD 12.08
OR 12.09
OR 11.03
OR 11.04
OR W384.02
ANDLD
ANDNOT W374.14
OUT W384.02
LD TR0
LD W384.02
AND W385.14
OR W386.02
ANDLD
ANDNOT W374.14
OUT W386.02
LD TR0
LD P_1s
OR W386.02
ANDLD
AND W384.02
OUT W398.02
; rung 1489
LD W384.02
OUT TR0
LD 12.08
OR W173.10
ANDLD
OUT W173.10
LD TR0
LD 12.09
OR W173.11
ANDLD
OUT W173.11
LD TR0
LD 11.03
OR W173.12
ANDLD
OUT W173.12
LD TR0
LD 11.04
OR W173.13
ANDLD
OUT W173.13

; rung 1490: ----- 警報4 -----
LDNOT W384.03
ANDNOT A418.00
ANDNOT A418.01
ANDNOT A418.02
ANDNOT A418.03
ANDNOT A418.04
ANDNOT A418.05
ANDNOT A418.06
ANDNOT A418.07
ANDNOT A418.08
ANDNOT A418.09
ANDNOT A418.10
ANDNOT A418.11
ANDNOT A418.12
ANDNOT A418.13
OUT W385.15
MOV(021) #8140 D270
; rung 1491
LD P_On
OUT TR0
AND A418.09
MOV(021) #8258 D270
LD TR0
AND A418.08
MOV(021) #8257 D270
LD TR0
AND A418.07
MOV(021) #8256 D270
LD TR0
AND A418.06
MOV(021) #8255 D270
LD TR0
AND A418.05
MOV(021) #8254 D270
LD TR0
AND A418.04
MOV(021) #8253 D270
LD TR0
AND A418.03
MOV(021) #8252 D270
LD TR0
AND A418.02
MOV(021) #8251 D270
LD TR0
AND A418.01
MOV(021) #8250 D270
LD TR0
AND A418.00
MOV(021) #824F D270

; rung 1492
LD P_On
OUT TR0
AND A418.10
MOV(021) #8260 D270
LD TR0
AND A418.11
MOV(021) #8261 D270
LD TR0
AND A418.12
MOV(021) #8262 D270
LD TR0
AND A418.13
MOV(021) #8263 D270
; rung 1493
LD P_On
OUT TR0
LD T0031
ANDNOT W385.15
OR W384.03
ANDLD
ANDNOT W374.14
OUT W384.03
LD TR0
LD W384.03
AND W385.14
OR W386.03
ANDLD
ANDNOT W374.14
OUT W386.03
LD TR0
LD P_1s
OR W386.03
ANDLD
AND W384.03
OUT W398.03
; rung 1494: ----- 警報5 ----- / 1回目はｷｬﾝｾﾙする様に変更
LD W170.00
AND T0021
OUT TR0
LD W190.03
OR W22.00
ANDLD
ANDNOT W22.02
OUT W22.00
LD TR0
LD W223.04
OR W22.01
ANDLD
AND W22.00
OUT W22.01
LD TR0
AND W22.01
AND W176.12
OUT W22.02
; rung 1495
LD W170.01
AND T0021
OUT TR0
LD W190.03
OR W23.00
ANDLD
ANDNOT W23.02
OUT W23.00
LD TR0
LD W225.01
OR W23.01
ANDLD
AND W23.00
OUT W23.01
LD TR0
AND W23.01
AND W306.12
OUT W23.02

; rung 1496
LD T0511
OUT TR0
LD T1100
ANDNOT W22.00
LD T1300
ANDNOT W23.00
ORLD
OR W384.04
ANDLD
ANDNOT W374.14
OUT W384.04
LD TR0
LD W384.04
AND W385.14
OR W386.04
ANDLD
ANDNOT W374.14
OUT W386.04
LD TR0
LD P_1s
OR W386.04
ANDLD
AND W384.04
OUT W398.04
; rung 1497
LD W384.04
OUT TR0
LD T1100
OR W191.08
ANDLD
OUT W191.08
LD TR0
LD T1300
OR W191.09
ANDLD
OUT W191.09
; rung 1498: ----- 警報6 -----
LDNOT P_On
OUT TR0
LD P_On
OR W384.05
ANDLD
ANDNOT W374.14
OUT W384.05
LD TR0
LD W384.05
AND W385.14
OR W386.05
ANDLD
ANDNOT W374.14
OUT W386.05
LD TR0
LD P_1s
OR W386.05
ANDLD
AND W384.05
OUT W398.05
; rung 1499: ----- 警報7 -----
LD P_On
OUT TR0
LD P_Low_Battery
OR W384.06
ANDLD
ANDNOT W374.14
OUT W384.06
LD TR0
LD W384.06
AND W385.14
OR W386.06
ANDLD
ANDNOT W374.14
OUT W386.06
LD TR0
LD P_1s
OR W386.06
ANDLD
AND W384.06
OUT W398.06

; rung 1500: ----- 警報8 -----
LD T0511
OUT TR0
LDNOT 11.14
ORNOT 2048.07
OR W384.07
ANDLD
ANDNOT W374.14
OUT W384.07
LD TR0
LD W384.07
AND W385.14
OR W386.07
ANDLD
ANDNOT W374.14
OUT W386.07
LD TR0
LD P_1s
OR W386.07
ANDLD
AND W384.07
OUT W398.07
; rung 1501
LD W384.07
OUT TR0
LDNOT 11.14
OR W173.02
ANDLD
OUT W173.02
LD TR0
LDNOT 2048.07
OR W173.03
ANDLD
OUT W173.03
; rung 1502: ----- 警報9 -----
LD T0511
OUT TR0
LDNOT 11.13
ORNOT 2048.06
OR W384.08
ANDLD
ANDNOT W374.14
OUT W384.08
LD TR0
LD W384.08
AND W385.14
OR W386.08
ANDLD
ANDNOT W374.14
OUT W386.08
LD TR0
LD P_1s
OR W386.08
ANDLD
AND W384.08
OUT W398.08
; rung 1503
LD W384.08
OUT TR0
LDNOT 11.13
OR W173.04
ANDLD
OUT W173.04
LD TR0
LDNOT 2048.06
OR W173.05
ANDLD
OUT W173.05

; rung 1504: ----- 警報10 -----
LD 10.07
OUT TR0
LD 2109.06
OR 2129.06
OR W384.09
ANDLD
ANDNOT W374.14
OUT W384.09
LD TR0
LD W384.09
AND W385.14
OR W386.09
ANDLD
ANDNOT W374.14
OUT W386.09
LD TR0
LD P_1s
OR W386.09
ANDLD
AND W384.09
OUT W398.09
; rung 1505
LD W384.09
OUT TR0
LD 2109.06
OR W173.06
ANDLD
OUT W173.06
LD TR0
LD 2129.06
OR W173.07
ANDLD
OUT W173.07
; rung 1506: ----- 警報11 -----
LDNOT 457.12
TIM 0068 #200
; rung 1507
LDNOT 457.11
TIM 0069 #200
; rung 1508
LDNOT 457.14
TIM 0071 #200
; rung 1509
LDNOT 457.13
TIM 0072 #200

; rung 1510
LD P_On
OUT TR0
LD T0068
ANDNOT 2109.05
LD T0069
ANDNOT 2109.04
ORLD
AND W170.00
LD T0071
ANDNOT 2129.05
LD T0072
ANDNOT 2129.04
ORLD
AND W170.01
ORLD
OR W384.10
ANDLD
ANDNOT W374.14
OUT W384.10
LD TR0
LD W384.10
AND W385.14
OR W386.10
ANDLD
ANDNOT W374.14
OUT W386.10
LD TR0
LD P_1s
OR W386.10
ANDLD
AND W384.10
OUT W398.10
; rung 1511
LD W384.10
OUT TR0
LD T0068
ANDNOT 2109.05
OR W192.13
ANDLD
OUT W192.13
LD TR0
LD T0069
ANDNOT 2109.04
OR W192.12
ANDLD
OUT W192.12
LD TR0
LD T0071
ANDNOT 2129.05
OR W192.15
ANDLD
OUT W192.15
LD TR0
LD T0072
ANDNOT 2129.04
OR W192.14
ANDLD
OUT W192.14
; rung 1512: ----- 警報12 -----
LD T0511
OUT TR0
AND W395.15
AND W170.00
TIM 0425 #5
LD TR0
AND W396.01
AND W170.01
TIM 0426 #5

; rung 1513
LD T0511
OUT TR0
LD T0425
OR T0426
OR W384.11
ANDLD
ANDNOT W374.14
OUT W384.11
LD TR0
LD W384.11
AND W385.14
OR W386.11
ANDLD
ANDNOT W374.14
OUT W386.11
LD TR0
LD P_1s
OR W386.11
ANDLD
AND W384.11
OUT W398.11
; rung 1514
LD W384.11
OUT TR0
LD T0425
OR W173.08
ANDLD
OUT W173.08
LD TR0
LD T0426
OR W173.09
ANDLD
OUT W173.09
; rung 1515: ----- 警報13 -----
LD T0511
OUT TR0
LD 2048.05
OR W384.12
ANDLD
ANDNOT W374.14
OUT W384.12
LD TR0
LD W384.12
AND W385.14
OR W386.12
ANDLD
ANDNOT W374.14
OUT W386.12
LD TR0
LD P_1s
OR W386.12
ANDLD
AND W384.12
OUT W398.12

; rung 1516: ----- 警報14 -----
LDNOT 16.08
AND T0511
OUT TR0
LD W187.12
OR P_On
ANDNOT W187.11
OR W384.13
ANDLD
ANDNOT W374.14
OUT W384.13
LD TR0
LD W384.13
AND W385.14
OR W386.13
ANDLD
ANDNOT W374.14
OUT W386.13
LD TR0
LD P_1s
OR W386.13
ANDLD
AND W384.13
OUT W398.13
; rung 1517: ----- 警報15 -----
LDNOT 16.08
AND T0511
OUT TR0
LDNOT 16.00
ORNOT 16.01
ORNOT 16.02
ORNOT 16.03
OR W384.14
ANDLD
ANDNOT W374.14
OUT W384.14
LD TR0
LD W384.14
AND W385.14
OR W386.14
ANDLD
ANDNOT W374.14
OUT W386.14
LD TR0
LD P_1s
OR W386.14
ANDLD
AND W384.14
OUT W398.14
; rung 1518
LD W384.14
OUT TR0
LDNOT 16.00
OR W163.00
ANDLD
OUT W163.00
LD TR0
LDNOT 16.01
OR W163.01
ANDLD
OUT W163.01
LD TR0
LDNOT 16.02
OR W163.02
ANDLD
OUT W163.02
LD TR0
LDNOT 16.03
OR W163.03
ANDLD
OUT W163.03

; rung 1519: ----- 警報16 -----
LD T0511
OUT TR0
LD 2110.08
OR 2130.08
OR W384.15
ANDLD
ANDNOT W374.14
OUT W384.15
LD TR0
LD W384.15
AND W385.14
OR W386.15
ANDLD
ANDNOT W374.14
OUT W386.15
LD TR0
LD P_1s
OR W386.15
ANDLD
AND W384.15
OUT W398.15
; rung 1520
LD W384.15
OUT TR0
LD 2110.08
OR W163.12
ANDLD
OUT W163.12
LD TR0
LD 2130.08
OR W163.13
ANDLD
OUT W163.13
; rung 1521: ----- 警報17 -----
LD T0511
OUT TR0
LD 17.01
ORNOT 12.02
ORNOT 12.03
OR W385.00
ANDLD
ANDNOT W374.14
ANDNOT W134.05  ; Kaeser BYPASS
OUT W385.00
LD TR0
LD W385.00
AND W385.14
OR W387.00
ANDLD
ANDNOT W374.14
OUT W387.00
LD TR0
LD P_1s
OR W387.00
ANDLD
AND W385.00
OUT W399.00

; rung 1522
LD W385.00
OUT TR0
LD 17.01
OR W163.09
ANDLD
ANDNOT W134.05  ; Kaeser BYPASS
OUT W163.09
LD TR0
LDNOT 12.02
OR W163.10
ANDLD
OUT W163.10
LD TR0
LDNOT 12.03
OR W163.11
ANDLD
OUT W163.11
; rung 1523: ----- 警報18 -----
LD T0511
OUT TR0
LD 17.03
OR W385.01
ANDLD
ANDNOT W374.14
ANDNOT W134.05  ; Kaeser BYPASS
OUT W385.01
LD TR0
LD W385.01
AND W385.14
OR W387.01
ANDLD
ANDNOT W374.14
OUT W387.01
LD TR0
LD P_1s
OR W387.01
ANDLD
AND W385.01
OUT W399.01
; rung 1524: ----- 警報19 -----
LD T0511
OUT TR0
AND 17.04
AND 17.05
TIM 0058 #30
LD TR0
AND 17.06
AND 17.07
TIM 0059 #30
; rung 1525
LDNOT 12.04
ORNOT 12.05
ORNOT 430.01
AND W170.00
LDNOT 12.06
ORNOT 12.07
ORNOT 430.00
AND W170.01
ORLD
OUT W163.04

; rung 1526
LD T0511
OUT TR0
LD T0058
OR T0059
OR W163.04
OR W385.02
ANDLD
ANDNOT W374.14
OUT W385.02
LD TR0
LD W385.02
AND W385.14
OR W387.02
ANDLD
ANDNOT W374.14
OUT W387.02
LD TR0
LD P_1s
OR W387.02
ANDLD
AND W385.02
OUT W399.02
; rung 1527
LD W385.02
OUT TR0
LD T0058
OR W163.14
ANDLD
OUT W163.14
LD TR0
LD T0059
OR W163.15
ANDLD
OUT W163.15
; rung 1528
LD W385.02
OUT TR0
AND W170.00
OUT TR1
LDNOT 12.04
OR W163.05
ANDLD
OUT W163.05
LD TR1
LDNOT 12.05
ORNOT 430.01
OR W163.06
ANDLD
OUT W163.06
LD TR0
AND W170.01
OUT TR0
LDNOT 12.06
OR W163.07
ANDLD
OUT W163.07
LD TR0
LDNOT 12.07
ORNOT 430.00
OR W163.08
ANDLD
OUT W163.08

; rung 1529: ----- 警報20 -----
LD T0511
OUT TR0
AND 2042.14
LD TR0
AND 2048.08
TTIM(087) 0019 #80
LD TR0
AND 2048.09
@MOV(021) T19 D247
LD TR0
AND 2042.15
LD TR0
AND 2048.09
TTIM(087) 0018 #80
LD TR0
AND 2048.08
@MOV(021) T18 D248
LD TR0
ANDNOT 2048.08
ANDNOT 2048.09
TIM 0015 #80
; rung 1530
LD T0511
OUT TR0
LD T0019
OR T0018
OR T0015
OR W385.03
ANDLD
ANDNOT W374.14
OUT W385.03
LD TR0
LD W385.03
AND W385.14
OR W387.03
ANDLD
ANDNOT W374.14
OUT W387.03
LD TR0
LD P_1s
OR W387.03
ANDLD
AND W385.03
OUT W399.03
; rung 1531: ----- 警報21 -----
LD 18.07
AND T0511
TIM 0061 #40

; rung 1532
LD T0511
OUT TR0
LD T0061
OR W385.04
ANDLD
ANDNOT W374.14
OUT W385.04
LD TR0
LD W385.04
AND W385.14
OR W387.04
ANDLD
ANDNOT W374.14
ANDNOT 18.07
OUT W387.04
LD TR0
LD P_1s
OR W387.04
ANDLD
AND W385.04
OUT W399.04
; rung 1533: ----- 警報22 -----
LD 2055.14
AND T0511
OR P_First_Cycle
OUT 15.11
; rung 1534
LD T0511
OUT TR0
LD 12.15
ANDNOT H1.02
OR W385.05
ANDLD
ANDNOT W374.14
ANDNOT 2055.14
OUT W385.05
LD TR0
LD W385.05
AND W385.14
OR W387.05
ANDLD
ANDNOT W374.14
ANDNOT 2055.14
OUT W387.05
LD TR0
LD P_1s
OR W387.05
ANDLD
AND W385.05
OUT W399.05
; rung 1535: ----- 警報23 -----
LD 2046.05
OR 2055.14
AND T0511
OR P_First_Cycle
LD 10.06
ANDNOT T0511
ORLD
OUT 15.10

; rung 1536
LD T0511
OUT TR0
LDNOT 12.13
ANDNOT 2055.12
OR W385.06
ANDLD
ANDNOT W374.14
ANDNOT 2055.14
OUT W385.06
LD TR0
LD W385.06
AND W385.14
OR W387.06
ANDLD
ANDNOT W374.14
ANDNOT 2055.14
OUT W387.06
LD TR0
LD P_1s
OR W387.06
ANDLD
AND W385.06
OUT W399.06
; rung 1537
LD 2055.12
OUT 15.13
; rung 1538: ----- 警報24 -----
LD T0511
OUT TR0
LDNOT 10.01
OR W385.07
ANDLD
ANDNOT W374.14
OUT W385.07
LD TR0
LD W385.07
AND W385.14
OR W387.07
ANDLD
ANDNOT W374.14
OUT W387.07
LD TR0
LD P_1s
OR W387.07
ANDLD
AND W385.07
OUT W399.07
; rung 1539
LDNOT 10.01
OR W162.02
AND W385.07
OUT W162.02

; rung 1540: ----- 警報25 -----
LD T0511
OUT TR0
LDNOT 2048.14
ORNOT 2049.03
ORNOT 2049.08
ORNOT 2049.13
OR W331.15
AND T0115
OR W150.02
OR W385.08
ANDLD
ANDNOT W374.14
OUT W385.08
LD TR0
LD W385.08
AND W385.14
OR W387.08
ANDLD
ANDNOT W374.14
OUT W387.08
LD TR0
LD P_1s
OR W387.08
ANDLD
AND W385.08
OUT W399.08
; rung 1541
LD W385.08
OUT TR0
LDNOT 2048.14
OR W356.02
ANDLD
OUT W356.02
LD TR0
LDNOT 2049.03
OR W356.03
ANDLD
OUT W356.03
LD TR0
LDNOT 2049.08
OR W356.04
ANDLD
OUT W356.04
LD TR0
LDNOT 2049.13
OR W356.05
ANDLD
OUT W356.05
; rung 1542: ----- 警報26 -----
LD T0511
AND W396.07
TIM 0427 #20

; rung 1543
LD T0511
OUT TR0
LD T0427
OR W385.09
ANDLD
ANDNOT W374.14
OUT W385.09
LD TR0
LD W385.09
AND W385.14
OR W387.09
ANDLD
ANDNOT W374.14
OUT W387.09
LD TR0
LD P_1s
OR W387.09
ANDLD
AND W385.09
OUT W399.09
; rung 1544: ----- 警報27 -----
LD T0511
AND W396.05
TIM 0417 #30
; rung 1545
LD T0511
OUT TR0
LD T0417
OR W385.10
ANDLD
ANDNOT W374.14
OUT W385.10
LD TR0
LD W385.10
AND W385.14
OR W387.10
ANDLD
ANDNOT W374.14
OUT W387.10
LD TR0
LD P_1s
OR W387.10
ANDLD
AND W385.10
OUT W399.10
; rung 1546: ----- 警報28 -----
LD T0511
AND W396.03
ANDNOT H8.13
TIM 0413 #100
; rung 1547
LD T0511
OUT TR0
LD T0413
OR W385.11
ANDLD
ANDNOT W374.14
OUT W385.11
LD TR0
LD W385.11
AND W385.14
OR W387.11
ANDLD
ANDNOT W374.14
OUT W387.11
LD TR0
LD P_1s
OR W387.11
ANDLD
AND W385.11
OUT W399.11

; rung 1548: ----- 警報29 -----
LD T0511
AND W396.04
ANDNOT H8.13
TIM 0409 #20
; rung 1549
LD T0511
OUT TR0
LD T0409
OR W385.12
ANDLD
ANDNOT W374.14
OUT W385.12
LD TR0
LD W385.12
AND W385.14
OR W387.12
ANDLD
ANDNOT W374.14
OUT W387.12
LD TR0
LD P_1s
OR W387.12
ANDLD
AND W385.12
OUT W399.12
; rung 1550: ----- 警報30 -----
LD T0511
AND W396.06
TIM 0410 #30
; rung 1551
LD T0511
OUT TR0
LD T0410
OR W385.13
ANDLD
ANDNOT W374.14
OUT W385.13
LD TR0
LD W385.13
AND W385.14
OR W387.13
ANDLD
ANDNOT W374.14
OUT W387.13
LD TR0
LD P_1s
OR W387.13
ANDLD
AND W385.13
OUT W399.13
; rung 1552: ----- 警報31 -----
LDNOT 11.10
ANDNOT 11.11
ANDNOT T0171
ANDNOT T0173
ANDNOT W350.01
ANDNOT W350.03
OUTNOT W343.13

; rung 1553
LD T0511
OUT TR0
LD W343.13
OR W344.00
ANDLD
ANDNOT W348.00
OUT W344.00
LD TR0
LD W344.00
AND W385.14
OR W346.00
ANDLD
ANDNOT W348.00
OUT W346.00
AND W374.14
OUT W348.00
LD TR0
LD P_1s
OR W346.00
ANDLD
AND W344.00
OUT W341.00
; rung 1554
LD W344.00
OUT TR0
LD 11.10
OR W343.01
ANDLD
OUT W343.01
LD TR0
LD 11.11
OR W343.02
ANDLD
OUT W343.02
LD TR0
LD T0171
OR W343.10
ANDLD
OUT W343.10
LD TR0
LD T0173
OR W343.12
ANDLD
OUT W343.12
; rung 1555: ----- 警報32 -----
LD W344.01
AND 11.01
OUT 2046.03
; rung 1556
LD T0511
OUT TR0
LD 2049.14
OR W344.01
ANDLD
ANDNOT W374.14
OUT W344.01
LD TR0
LD W344.01
AND W385.14
OR W346.01
ANDLD
ANDNOT W374.14
OUT W346.01
LD TR0
LD P_1s
OR W346.01
ANDLD
AND W344.01
OUT W341.01

; rung 1557: ----- 警報33 -----
LD T0511
AND W395.13
TIM 0411 #20
; rung 1558
LD T0511
OUT TR0
LD T0411
OR W344.02
ANDLD
ANDNOT W374.14
OUT W344.02
LD TR0
LD W344.02
AND W385.14
OR W346.02
ANDLD
ANDNOT W374.14
OUT W346.02
LD TR0
LD P_1s
OR W346.02
ANDLD
AND W344.02
OUT W341.02
; rung 1559: ----- 警報34 -----
LD T0511
AND W395.14
TIM 0412 #20
; rung 1560
LD T0511
OUT TR0
LD T0412
OR W344.03
ANDLD
ANDNOT W374.14
OUT W344.03
LD TR0
LD W344.03
AND W385.14
OR W346.03
ANDLD
ANDNOT W374.14
OUT W346.03
LD TR0
LD P_1s
OR W346.03
ANDLD
AND W344.03
OUT W341.03

; rung 1561: ----- 警報35 -----
LD P_On
OUT TR0
LD W445.04
OR W344.04
ANDLD
ANDNOT W374.14
OUT W344.04
LD TR0
LD W344.04
AND W385.14
OR W346.04
ANDLD
ANDNOT W374.14
OUT W346.04
LD TR0
LD P_1s
OR W346.04
ANDLD
AND W344.04
OUT W341.04
; rung 1562: ----- 警報36 -----
LD T0511
OUT TR0
LDNOT P_On
OR W344.05
ANDLD
ANDNOT W374.14
OUT W344.05
LD TR0
LD W344.05
AND W385.14
OR W346.05
ANDLD
ANDNOT W374.14
OUT W346.05
LD TR0
LD P_1s
OR W346.05
ANDLD
AND W344.05
OUT W341.05
; rung 1563: ----- 警報37 -----
LDNOT P_On
OUT TR0
LDNOT P_On
OR W344.06
ANDLD
ANDNOT W374.14
OUT W344.06
LD TR0
LD W344.06
AND W385.14
OR W346.06
ANDLD
ANDNOT W374.14
OUT W346.06
LD TR0
LD P_1s
OR W346.06
ANDLD
AND W344.06
OUT W341.06
; rung 1564: ----- 警報38 -----
LD T0511
AND W391.13
TIM 0504 #20

; rung 1565
LD T0511
OUT TR0
LD T0504
OR W344.07
ANDLD
ANDNOT W374.14
OUT W344.07
LD TR0
LD W344.07
AND W385.14
OR W346.07
ANDLD
ANDNOT W374.14
OUT W346.07
LD TR0
LD P_1s
OR W346.07
ANDLD
AND W344.07
OUT W341.07
; rung 1566: ----- 警報39 -----
LD T0511
OUT TR0
LDNOT 12.00
ORNOT 12.01
OR W344.08
ANDLD
ANDNOT W374.14
OUT W344.08
LD TR0
LD W344.08
AND W385.14
OR W346.08
ANDLD
ANDNOT W374.14
OUT W346.08
LD TR0
LD P_1s
OR W346.08
ANDLD
AND W344.08
OUT W341.08
; rung 1567
LD W344.08
OUT TR0
LDNOT 12.00
OR W171.14
ANDLD
OUT W171.14
LD TR0
LDNOT 12.01
OR W171.15
ANDLD
OUT W171.15

; rung 1568: ----- 警報40 -----
LD T0511
OUT TR0
LDNOT 10.04
ORNOT 10.03
OR W344.09
ANDLD
ANDNOT W374.14
OUT W344.09
LD TR0
LD W344.09
AND W385.14
OR W346.09
ANDLD
ANDNOT W374.14
OUT W346.09
LD TR0
LD P_1s
OR W346.09
ANDLD
AND W344.09
OUT W341.09
; rung 1569
LD W344.09
OUT TR0
LDNOT 10.04
OR W171.12
ANDLD
OUT W171.12
LD TR0
LDNOT 10.03
OR W171.13
ANDLD
OUT W171.13
; rung 1570: ----- 警報41 -----
LD T0511
ANDNOT W374.14
OUT W362.15
; rung 1571
LD 2102.06
ANDNOT 2108.00
LD 2102.10
ANDNOT 2108.01
ORLD
AND T0021
AND H80.00
AND H2.00
TIM 0100 #40
; rung 1572
LD H80.00
AND H2.00
AND W362.15
OUT TR0
LD 2102.06
ANDNOT 2108.00
AND T0100
OR W12.00
ANDLD
OUT W12.00
LD TR0
LD 2102.10
ANDNOT 2108.01
AND T0100
OR W12.01
ANDLD
OUT W12.01
; rung 1573
LD 2102.07
ANDNOT 2108.02
LD 2102.11
ANDNOT 2108.03
ORLD
AND T0021
AND H80.01
AND H2.01
TIM 0101 #40

; rung 1574
LD H80.01
AND H2.01
AND W362.15
OUT TR0
LD 2102.07
ANDNOT 2108.02
AND T0101
OR W12.02
ANDLD
OUT W12.02
LD TR0
LD 2102.11
ANDNOT 2108.03
AND T0101
OR W12.03
ANDLD
OUT W12.03
; rung 1575
LD 2102.08
ANDNOT 2108.04
LD 2103.05
ANDNOT 2108.05
ORLD
AND T0021
AND H80.02
AND H2.04
TIM 0102 #40
; rung 1576
LD H80.02
AND H2.04
AND W362.15
OUT TR0
LD 2102.08
ANDNOT 2108.04
AND T0102
OR W12.04
ANDLD
OUT W12.04
LD TR0
LD 2103.05
ANDNOT 2108.05
AND T0102
OR W12.05
ANDLD
OUT W12.05
; rung 1577
LD 2102.13
ANDNOT 2108.08
LD 2102.14
ANDNOT 2108.09
ORLD
AND T0021
AND H80.03
AND H9.12
TIM 0103 #40
; rung 1578
LD H80.03
AND H9.12
AND W362.15
OUT TR0
LD 2102.13
ANDNOT 2108.08
AND T0103
OR W12.06
ANDLD
OUT W12.06
LD TR0
LD 2102.14
ANDNOT 2108.09
AND T0103
OR W12.07
ANDLD
OUT W12.07
; rung 1579
LD 2100.15
ANDNOT 2034.00
LD 2101.01
ANDNOT 2034.01
ORLD
AND T0021
AND H80.04
AND H9.04
TIM 0104 #40

; rung 1580
LD P_On
OUT TR0
LD H80.04
AND H9.04
AND W362.15
LD 2100.15
ANDNOT 2034.00
AND T0104
OR W12.08
ANDLD
LD P_On
AND H9.04
AND W362.15
LD=(300) D2200 #30
OR=(300) D2200 #19
OR=(300) D2200 #36
@AND W223.04
ANDNOT 2034.00
OR W12.08
ANDLD
ORLD
ANDLD
OUT W12.08
LD TR0
AND H80.04
AND H9.04
AND W362.15
LD 2101.01
ANDNOT 2034.01
AND T0104
OR W12.09
ANDLD
OUT W12.09
; rung 1581
LD 2103.14
ANDNOT 2110.00
LD 2103.15
ANDNOT 2110.01
ORLD
AND T0021
AND H80.05
AND H9.13
TIM 0105 #40
; rung 1582
LD H80.05
AND H9.13
AND W362.15
OUT TR0
LD 2103.14
ANDNOT 2110.00
AND T0105
OR W12.10
ANDLD
OUT W12.10
LD TR0
LD 2103.15
ANDNOT 2110.01
AND T0105
OR W12.11
ANDLD
OUT W12.11
; rung 1583
LD 2101.03
ANDNOT 2034.02
LD 2101.12
ANDNOT 2034.03
ORLD
AND T0021
AND H80.06
AND H9.05
TIM 0106 #40

; rung 1584
LD P_On
OUT TR0
LD H80.06
AND H9.05
AND W362.15
LD 2101.03
ANDNOT 2034.02
AND T0106
OR W12.12
ANDLD
LD P_On
AND H9.05
AND W362.15
LD=(300) D2200 #30
OR=(300) D2200 #19
@AND W223.04
ANDNOT 2034.02
OR W12.12
ANDLD
ORLD
ANDLD
OUT W12.12
LD TR0
AND H80.06
AND H9.05
AND W362.15
LD 2101.12
ANDNOT 2034.03
AND T0106
OR W12.13
ANDLD
OUT W12.13
; rung 1585
LD 2031.09
ANDNOT 2108.10
LD 2031.10
ANDNOT 2108.11
ORLD
AND T0021
AND H80.07
AND H3.08
TIM 0107 #40
; rung 1586
LD H80.07
AND H3.08
AND W362.15
OUT TR0
LD 2031.09
ANDNOT 2108.10
AND T0107
OR W12.14
ANDLD
OUT W12.14
LD TR0
LD 2031.10
ANDNOT 2108.11
AND T0107
OR W12.15
ANDLD
OUT W12.15
; rung 1587
LD 2031.11
ANDNOT 2108.14
LD 2031.12
ANDNOT 2108.15
ORLD
AND T0021
AND H80.08
AND H3.09
TIM 0108 #40
; rung 1588
LD H80.08
AND H3.09
AND W362.15
OUT TR0
LD 2031.11
ANDNOT 2108.14
AND T0108
OR W13.00
ANDLD
OUT W13.00
LD TR0
LD 2031.12
ANDNOT 2108.15
AND T0108
OR W13.01
ANDLD
OUT W13.01
; rung 1589
LD 2100.04
ANDNOT 2035.02
LD 2100.05
ANDNOT 2035.03
ORLD
AND T0021
AND H80.09
AND H3.12
TIM 0133 #40

; rung 1590
LD H80.09
AND H3.12
AND W362.15
OUT TR0
LD 2100.04
ANDNOT 2035.02
AND T0133
OR W13.02
ANDLD
OUT W13.02
LD TR0
LD 2100.05
ANDNOT 2035.03
AND T0133
OR W13.03
ANDLD
OUT W13.03
; rung 1591
LD 2100.06
ANDNOT 2035.04
LD 2100.07
ANDNOT 2035.05
ORLD
AND T0021
AND H80.10
AND H3.13
TIM 0134 #40
; rung 1592
LD H80.10
AND H3.13
AND W362.15
OUT TR0
LD 2100.06
ANDNOT 2035.04
AND T0134
OR W13.04
ANDLD
OUT W13.04
LD TR0
LD 2100.07
ANDNOT 2035.05
AND T0134
OR W13.05
ANDLD
OUT W13.05
; rung 1593
LD 2101.13
ANDNOT 2034.14
LD 2101.14
ANDNOT 2034.15
ORLD
AND T0021
AND H80.11
AND H7.01
TIM 0135 #40
; rung 1594
LD H80.11
AND H7.01
AND W362.15
OUT TR0
LD 2101.13
ANDNOT 2034.14
AND T0135
OR W13.06
ANDLD
OUT W13.06
LD TR0
LD 2101.14
ANDNOT 2034.15
AND T0135
OR W13.07
ANDLD
OUT W13.07
; rung 1595
LD 2102.01
ANDNOT 2034.04
LD 2102.02
ANDNOT 2034.05
ORLD
AND T0021
AND H60.00
AND H9.00
TIM 0495 #40
; rung 1596
LD H60.00
AND H9.00
AND W362.15
OUT TR0
LD 2102.01
ANDNOT 2034.04
AND T0495
OR W13.08
ANDLD
OUT W13.08
LD TR0
LD 2102.02
ANDNOT 2034.05
AND T0495
OR W13.09
ANDLD
OUT W13.09

; rung 1597
LD 2101.15
ANDNOT 2035.14
LD 2102.00
ANDNOT 2035.15
ORLD
AND T0021
AND H60.01
AND H9.01
TIM 0494 #40
; rung 1598
LD P_On
OUT TR0
LD H60.01
AND H9.01
AND W362.15
LD 2101.15
ANDNOT 2035.14
AND T0494
OR W13.10
ANDLD
LDNOT W170.13
AND H9.01
AND W362.15
LD=(300) D2200 #30
OR=(300) D2200 #19
OR=(300) D2200 #42
@AND W223.04
ANDNOT 2035.14
OR W13.10
ANDLD
ORLD
ANDLD
OUT W13.10
LD TR0
AND H60.01
AND H9.01
AND W362.15
LD 2102.00
ANDNOT 2035.15
AND T0494
OR W13.11
ANDLD
OUT W13.11
; rung 1599
LD 2102.03
ANDNOT 2108.06
LD 2102.12
ANDNOT 2108.07
ORLD
AND T0021
AND H60.02
AND H9.08
TIM 0493 #100
; rung 1600
LD H60.02
AND H9.08
AND W362.15
OUT TR0
LD 2102.03
ANDNOT 2108.06
AND T0493
OR W13.12
ANDLD
OUT W13.12
LD TR0
LD 2102.12
ANDNOT 2108.07
AND T0493
OR W13.13
ANDLD
OUT W13.13
; rung 1601
LD 2103.01
ANDNOT 2109.02
LD 2103.02
ANDNOT 2109.03
ORLD
AND T0021
AND H60.03
AND H9.09
TIM 0492 #100
; rung 1602
LD H60.03
AND H9.09
AND W362.15
OUT TR0
LD 2103.01
ANDNOT 2109.02
AND T0492
OR W13.14
ANDLD
OUT W13.14
LD TR0
LD 2103.02
ANDNOT 2109.03
AND T0492
OR W13.15
ANDLD
OUT W13.15

; rung 1603
LD 2104.04
ANDNOT 2109.14
LD 2104.08
ANDNOT 2109.15
ORLD
AND T0021
AND H60.04
AND H2.08
TIM 0491 #40
; rung 1604
LD H60.04
AND H2.08
AND W362.15
OUT TR0
LD 2104.04
ANDNOT 2109.14
AND T0491
OR W14.00
ANDLD
OUT W14.00
LD TR0
LD 2104.08
ANDNOT 2109.15
AND T0491
OR W14.01
ANDLD
OUT W14.01
; rung 1605
LD 2104.05
ANDNOT 2110.02
LD 2104.09
ANDNOT 2110.04
ORLD
AND T0021
AND H60.05
AND H2.09
TIM 0490 #40
; rung 1606
LD H60.05
AND H2.09
AND W362.15
OUT TR0
LD 2104.05
ANDNOT 2110.02
AND T0490
OR W14.02
ANDLD
OUT W14.02
LD TR0
LD 2104.09
ANDNOT 2110.04
AND T0490
OR W14.03
ANDLD
OUT W14.03
; rung 1607
LD 2104.06
ANDNOT 2110.05
LD 2104.10
ANDNOT 2110.13
ORLD
AND T0021
AND H60.06
AND H2.12
TIM 0477 #40
; rung 1608
LD H60.06
AND H2.12
AND W362.15
OUT TR0
LD 2104.06
ANDNOT 2110.05
AND T0477
OR W14.04
ANDLD
OUT W14.04
LD TR0
LD 2104.10
ANDNOT 2110.13
AND T0477
OR W14.05
ANDLD
OUT W14.05
; rung 1609
LD 2104.07
ANDNOT 2035.12
LD 2104.11
ANDNOT 2035.13
ORLD
AND T0021
AND H60.07
AND H2.13
TIM 0487 #40

; rung 1610
LD H60.07
AND H2.13
AND W362.15
OUT TR0
LD 2104.07
ANDNOT 2035.12
AND T0487
OR W14.06
ANDLD
OUT W14.06
LD TR0
LD 2104.11
ANDNOT 2035.13
AND T0487
OR W14.07
ANDLD
OUT W14.07
; rung 1611
LD 2104.00
ANDNOT 2109.09
LD 2104.01
ANDNOT 2109.12
ORLD
AND T0021
AND H60.08
AND H7.04
TIM 0486 #40  // ﾈｼﾞ入子は出時間又戻時間UPで監視
; rung 1612
LD H60.08
AND H7.04
AND W362.15
OUT TR0
LDNOT 2109.09
AND T1201
OR W14.08
ANDLD
OUT W14.08
LD TR0
LDNOT 2109.12
AND T1203
OR W14.09
ANDLD
OUT W14.09
; rung 1613
LD 2104.02
ANDNOT 2034.06
LD 2104.03
ANDNOT 2034.07
ORLD
AND T0021
AND H60.09
AND H7.05
TIM 0485 #40  // ﾈｼﾞ入子は出時間又戻時間UPで監視
; rung 1614
LD H60.09
AND H7.05
AND W362.15
OUT TR0
LDNOT 2034.06
AND T1205
OR W14.10
ANDLD
OUT W14.10
LD TR0
LDNOT 2034.07
AND T1207
OR W14.11
ANDLD
OUT W14.11
; rung 1615
LDNOT P_On
ORNOT P_On
AND T0021
AND H60.10
TIM 0484 #40
; rung 1616
LD H60.10
AND W362.15
OUT TR0
LDNOT P_On
AND T0484
OR W14.12
ANDLD
OUT W14.12
LD TR0
LDNOT P_On
AND T0484
OR W14.13
ANDLD
OUT W14.13

; rung 1617
LDNOT P_On
ORNOT P_On
AND T0021
AND H60.11
TIM 0483 #40
; rung 1618
LD H60.11
AND W362.15
OUT TR0
LDNOT P_On
AND T0483
OR W14.14
ANDLD
OUT W14.14
LD TR0
LDNOT P_On
AND T0483
OR W14.15
ANDLD
OUT W14.15
; rung 1619
LD T0511
OUT TR0
AND<>(305) W12 #0
OUT W9.00
LD TR0
AND<>(305) W13 #0
OUT W9.01
LD TR0
AND<>(305) W14 #0
OUT W9.02
; rung 1620
LD W9.00
OR W9.01
OR W9.02
OUT W9.03
; rung 1621
LD T0511
OUT TR0
LD W9.03
OR W344.10
ANDLD
ANDNOT W374.14
OUT W344.10
LD TR0
LD W344.10
AND W385.14
OR W346.10
ANDLD
ANDNOT W374.14
OUT W346.10
LD TR0
LD P_1s
OR W346.10
ANDLD
AND W344.10
OUT W341.10
; rung 1622: ----- 警報42 -----
LD 2122.06
ANDNOT 2128.00
LD 2122.10
ANDNOT 2128.01
ORLD
AND T0021
AND H90.00
AND H2.02
TIM 0136 #40

; rung 1623
LD H90.00
AND H2.02
AND W362.15
OUT TR0
LD 2122.06
ANDNOT 2128.00
AND T0136
OR W27.00
ANDLD
OUT W27.00
LD TR0
LD 2122.10
ANDNOT 2128.01
AND T0136
OR W27.01
ANDLD
OUT W27.01
; rung 1624
LD 2122.07
ANDNOT 2128.02
LD 2122.11
ANDNOT 2128.03
ORLD
AND T0021
AND H90.01
AND H2.03
TIM 0137 #40
; rung 1625
LD H90.01
AND H2.03
AND W362.15
OUT TR0
LD 2122.07
ANDNOT 2128.02
AND T0137
OR W27.02
ANDLD
OUT W27.02
LD TR0
LD 2122.11
ANDNOT 2128.03
AND T0137
OR W27.03
ANDLD
OUT W27.03
; rung 1626
LD 2122.08
ANDNOT 2128.04
LD 2123.05
ANDNOT 2128.05
ORLD
AND T0021
AND H90.02
AND H2.06
TIM 0138 #40
; rung 1627
LD H90.02
AND H2.06
AND W362.15
OUT TR0
LD 2122.08
ANDNOT 2128.04
AND T0138
OR W27.04
ANDLD
OUT W27.04
LD TR0
LD 2123.05
ANDNOT 2128.05
AND T0138
OR W27.05
ANDLD
OUT W27.05
; rung 1628
LD 2122.13
ANDNOT 2128.08
LD 2122.14
ANDNOT 2128.09
ORLD
AND T0021
AND H90.03
AND H9.14
TIM 0139 #40
; rung 1629
LD H90.03
AND H9.14
AND W362.15
OUT TR0
LD 2122.13
ANDNOT 2128.08
AND T0139
OR W27.06
ANDLD
OUT W27.06
LD TR0
LD 2122.14
ANDNOT 2128.09
AND T0139
OR W27.07
ANDLD
OUT W27.07

; rung 1630
LD 2120.15
ANDNOT 2036.00
LD 2121.01
ANDNOT 2036.01
ORLD
AND T0021
AND H90.04
AND H9.06
TIM 0140 #40
; rung 1631
LD P_On
OUT TR0
LD H90.04
AND H9.06
AND W362.15
LD 2120.15
ANDNOT 2036.00
AND T0140
OR W27.08
ANDLD
LDNOT W170.13
AND H9.06
AND W362.15
LD=(300) D2200 #30
OR=(300) D2200 #19
OR=(300) D2200 #36
@AND W225.01
ANDNOT 2036.00
OR W27.08
ANDLD
ORLD
ANDLD
OUT W27.08
LD TR0
AND H90.04
AND H9.06
AND W362.15
LD 2121.01
ANDNOT 2036.01
AND T0140
OR W27.09
ANDLD
OUT W27.09
; rung 1632
LD 2123.14
ANDNOT 2130.00
LD 2123.15
ANDNOT 2130.01
ORLD
AND T0021
AND H90.05
AND H9.15
TIM 0141 #40
; rung 1633
LD H90.05
AND H9.15
AND W362.15
OUT TR0
LD 2123.14
ANDNOT 2130.00
AND T0141
OR W27.10
ANDLD
OUT W27.10
LD TR0
LD 2123.15
ANDNOT 2130.01
AND T0141
OR W27.11
ANDLD
OUT W27.11
; rung 1634
LD 2121.03
ANDNOT 2036.02
LD 2121.12
ANDNOT 2036.03
ORLD
AND T0021
AND H90.06
AND H9.07
TIM 0142 #40

; rung 1635
LD P_On
OUT TR0
LD H90.06
AND H9.07
AND W362.15
LD 2121.03
ANDNOT 2036.02
AND T0142
OR W27.12
ANDLD
LD P_On
AND H9.07
AND W362.15
LD=(300) D2200 #30
OR=(300) D2200 #19
@AND W225.01
ANDNOT 2036.02
OR W27.12
ANDLD
ORLD
ANDLD
OUT W27.12
LD TR0
AND H90.06
AND H9.07
AND W362.15
LD 2121.12
ANDNOT 2036.03
AND T0142
OR W27.13
ANDLD
OUT W27.13
; rung 1636
LD 2033.09
ANDNOT 2128.10
LD 2033.10
ANDNOT 2128.11
ORLD
AND T0021
AND H90.07
AND H3.10
TIM 0143 #40
; rung 1637
LD H90.07
AND H3.10
AND W362.15
OUT TR0
LD 2033.09
ANDNOT 2128.10
AND T0143
OR W27.14
ANDLD
OUT W27.14
LD TR0
LD 2033.10
ANDNOT 2128.11
AND T0143
OR W27.15
ANDLD
OUT W27.15
; rung 1638
LD 2033.11
ANDNOT 2128.14
LD 2033.12
ANDNOT 2128.15
ORLD
AND T0021
AND H90.08
AND H3.11
TIM 0147 #40
; rung 1639
LD H90.08
AND H3.11
AND W362.15
OUT TR0
LD 2033.11
ANDNOT 2128.14
AND T0147
OR W28.00
ANDLD
OUT W28.00
LD TR0
LD 2033.12
ANDNOT 2128.15
AND T0147
OR W28.01
ANDLD
OUT W28.01
; rung 1640
LD 2120.04
ANDNOT 2037.02
LD 2120.05
ANDNOT 2037.03
ORLD
AND T0021
AND H90.09
AND H3.14
TIM 0148 #40

; rung 1641
LD H90.09
AND H3.14
AND W362.15
OUT TR0
LD 2120.04
ANDNOT 2037.02
AND T0148
OR W28.02
ANDLD
OUT W28.02
LD TR0
LD 2120.05
ANDNOT 2037.03
AND T0148
OR W28.03
ANDLD
OUT W28.03
; rung 1642
LD 2120.06
ANDNOT 2037.04
LD 2120.07
ANDNOT 2037.05
ORLD
AND T0021
AND H90.10
AND H3.15
TIM 0149 #40
; rung 1643
LD H90.10
AND H3.15
AND W362.15
OUT TR0
LD 2120.06
ANDNOT 2037.04
AND T0149
OR W28.04
ANDLD
OUT W28.04
LD TR0
LD 2120.07
ANDNOT 2037.05
AND T0149
OR W28.05
ANDLD
OUT W28.05
; rung 1644
LD 2121.13
ANDNOT 2036.14
LD 2121.14
ANDNOT 2036.15
ORLD
AND T0021
AND H90.11
AND H7.03
TIM 0156 #40
; rung 1645
LD H90.11
AND H7.03
AND W362.15
OUT TR0
LD 2121.13
ANDNOT 2036.14
AND T0156
OR W28.06
ANDLD
OUT W28.06
LD TR0
LD 2121.14
ANDNOT 2036.15
AND T0156
OR W28.07
ANDLD
OUT W28.07
; rung 1646
LD 2122.01
ANDNOT 2036.04
LD 2122.02
ANDNOT 2036.05
ORLD
AND T0021
AND H70.00
AND H9.02
TIM 0482 #40
; rung 1647
LD H70.00
AND H9.02
AND W362.15
OUT TR0
LD 2122.01
ANDNOT 2036.04
AND T0482
OR W28.08
ANDLD
OUT W28.08
LD TR0
LD 2122.02
ANDNOT 2036.05
AND T0482
OR W28.09
ANDLD
OUT W28.09

; rung 1648
LD 2121.15
ANDNOT 2037.14
LD 2122.00
ANDNOT 2037.15
ORLD
AND T0021
AND H70.01
AND H9.03
TIM 0481 #40
; rung 1649
LD P_On
OUT TR0
LD H70.01
AND H9.03
AND W362.15
LD 2121.15
ANDNOT 2037.14
AND T0481
OR W28.10
ANDLD
LD P_On
AND H9.03
AND W362.15
LD=(300) D2200 #30
OR=(300) D2200 #19
OR=(300) D2200 #42
@AND W225.01
ANDNOT 2037.14
OR W28.10
ANDLD
ORLD
ANDLD
OUT W28.10
LD TR0
AND H70.01
AND H9.03
AND W362.15
LD 2122.00
ANDNOT 2037.15
AND T0481
OR W28.11
ANDLD
OUT W28.11
; rung 1650
LD 2122.03
ANDNOT 2128.06
LD 2122.12
ANDNOT 2128.07
ORLD
AND T0021
AND H70.02
AND H9.10
TIM 0480 #100
; rung 1651
LD H70.02
AND H9.10
AND W362.15
OUT TR0
LD 2122.03
ANDNOT 2128.06
AND T0480
OR W28.12
ANDLD
OUT W28.12
LD TR0
LD 2122.12
ANDNOT 2128.07
AND T0480
OR W28.13
ANDLD
OUT W28.13
; rung 1652
LD 2123.01
ANDNOT 2129.02
LD 2123.02
ANDNOT 2129.03
ORLD
AND T0021
AND H70.03
AND H9.11
TIM 0479 #150
; rung 1653
LD H70.03
AND H9.11
AND W362.15
OUT TR0
LD 2123.01
ANDNOT 2129.02
AND T0479
OR W28.14
ANDLD
OUT W28.14
LD TR0
LD 2123.02
ANDNOT 2129.03
AND T0479
OR W28.15
ANDLD
OUT W28.15

; rung 1654
LD 2124.04
ANDNOT 2129.14
LD 2124.08
ANDNOT 2129.15
ORLD
AND T0021
AND H70.04
AND H2.10
TIM 0445 #40
; rung 1655
LD H70.04
AND H2.10
AND W362.15
OUT TR0
LD 2124.04
ANDNOT 2129.14
AND T0445
OR W29.00
ANDLD
OUT W29.00
LD TR0
LD 2124.08
ANDNOT 2129.15
AND T0445
OR W29.01
ANDLD
OUT W29.01
; rung 1656
LD 2124.05
ANDNOT 2130.02
LD 2124.09
ANDNOT 2130.04
ORLD
AND T0021
AND H70.05
AND H2.11
TIM 0444 #40
; rung 1657
LD H70.05
AND H2.11
AND W362.15
OUT TR0
LD 2124.05
ANDNOT 2130.02
AND T0444
OR W29.02
ANDLD
OUT W29.02
LD TR0
LD 2124.09
ANDNOT 2130.04
AND T0444
OR W29.03
ANDLD
OUT W29.03
; rung 1658
LD 2124.06
ANDNOT 2130.05
LD 2124.10
ANDNOT 2130.13
ORLD
AND T0021
AND H70.06
AND H2.14
TIM 0443 #40
; rung 1659
LD H70.06
AND H2.14
AND W362.15
OUT TR0
LD 2124.06
ANDNOT 2130.05
AND T0443
OR W29.04
ANDLD
OUT W29.04
LD TR0
LD 2124.10
ANDNOT 2130.13
AND T0443
OR W29.05
ANDLD
OUT W29.05
; rung 1660
LD 2124.07
ANDNOT 2037.12
LD 2124.11
ANDNOT 2037.13
ORLD
AND T0021
AND H70.07
AND H2.15
TIM 0442 #40

; rung 1661
LD H70.07
AND H2.15
AND W362.15
OUT TR0
LD 2124.07
ANDNOT 2037.12
AND T0442
OR W29.06
ANDLD
OUT W29.06
LD TR0
LD 2124.11
ANDNOT 2037.13
AND T0442
OR W29.07
ANDLD
OUT W29.07
; rung 1662
LD 2124.00
ANDNOT 2129.09
LD 2124.01
ANDNOT 2129.12
ORLD
AND T0021
AND H70.08
AND H7.06
TIM 0441 #40  // ﾈｼﾞ入子は出時間又戻時間UPで監視
; rung 1663
LD H70.08
AND H7.06
AND W362.15
OUT TR0
LDNOT 2129.09
AND T1401
OR W29.08
ANDLD
OUT W29.08
LD TR0
LDNOT 2129.12
AND T1403
OR W29.09
ANDLD
OUT W29.09
; rung 1664
LD 2124.02
ANDNOT 2036.06
LD 2124.03
ANDNOT 2036.07
ORLD
AND T0021
AND H70.09
AND H7.07
TIM 0440 #40  // ﾈｼﾞ入子は出時間又戻時間UPで監視
; rung 1665
LD H70.09
AND H7.07
AND W362.15
OUT TR0
LDNOT 2036.06
AND T1405
OR W29.10
ANDLD
OUT W29.10
LD TR0
LDNOT 2036.07
AND T1407
OR W29.11
ANDLD
OUT W29.11
; rung 1666
LDNOT P_On
ORNOT P_On
AND T0021
AND H70.10
TIM 0439 #40
; rung 1667
LD H70.10
AND W362.15
OUT TR0
LDNOT P_On
AND T0439
OR W29.12
ANDLD
OUT W29.12
LD TR0
LDNOT P_On
AND T0439
OR W29.13
ANDLD
OUT W29.13

; rung 1668
LDNOT P_On
ORNOT P_On
AND T0021
AND H70.11
TIM 0438 #40
; rung 1669
LD H70.11
AND W362.15
OUT TR0
LDNOT P_On
AND T0438
OR W29.14
ANDLD
OUT W29.14
LD TR0
LDNOT P_On
AND T0438
OR W29.15
ANDLD
OUT W29.15
; rung 1670
LD T0511
OUT TR0
AND<>(305) W27 #0
OUT W26.00
LD TR0
AND<>(305) W28 #0
OUT W26.01
LD TR0
AND<>(305) W29 #0
OUT W26.02
; rung 1671
LD W26.00
OR W26.01
OR W26.02
OUT W26.03
; rung 1672
LD T0511
OUT TR0
LD W26.03
OR W344.11
ANDLD
ANDNOT W374.14
OUT W344.11
LD TR0
LD W344.11
AND W385.14
OR W346.11
ANDLD
ANDNOT W374.14
OUT W346.11
LD TR0
LD P_1s
OR W346.11
ANDLD
AND W344.11
OUT W341.11

; rung 1673: ----- 警報43 -----
LD T0511
OUT TR0
LD 25.11
OR 25.12
OR W344.12
ANDLD
ANDNOT W374.14
OUT W344.12
LD TR0
LD W344.12
AND W385.14
OR W346.12
ANDLD
ANDNOT W374.14
OUT W346.12
LD TR0
LD P_1s
OR W346.12
ANDLD
AND W344.12
OUT W341.12
; rung 1674
LD W344.12
OUT TR0
LD 25.11
OR W165.12
ANDLD
OUT W165.12
LD TR0
LD 25.12
OR W165.13
ANDLD
OUT W165.13
; rung 1675: ----- 警報44 -----
LD T0511
OUT TR0
LD W208.12
OR W208.14
OR T0555
OR W344.13
ANDLD
ANDNOT W374.14
OUT W344.13
LD TR0
LD W344.13
AND W385.14
OR W346.13
ANDLD
ANDNOT W374.14
OUT W346.13
LD TR0
LD P_1s
OR W346.13
ANDLD
AND W344.13
OUT W341.13

; rung 1676
LD W344.13
OUT TR0
LD W208.12
OR T0555
OR W208.08
ANDLD
OUT W208.08
LD TR0
LD W208.14
OR W208.09
ANDLD
OUT W208.09
; rung 1677
LD 13.03
AND 14.12
AND>(320) D274 #1000
AND<(310) D274 #3000
TIM 0555 #40
; rung 1678
@LD W208.12
MOV(021) D600 D1500
MOV(021) D282 D1502
; rung 1679: ----- 警報45 -----
LD P_On
OUT TR0
LD W95.00
OR W95.01
OR W95.02
OR W95.03
OR W95.04
OR W95.05
OR W95.06
OR W95.07
OR W344.14
ANDLD
ANDNOT W374.14
OUT W344.14
LD TR0
LD W344.14
AND W385.14
OR W346.14
ANDLD
ANDNOT W374.14
OUT W346.14
LD TR0
LD P_1s
OR W346.14
ANDLD
AND W344.14
OUT W341.14

; rung 1680
LD P_On
OUT TR0
LD 2101.04
ANDNOT 2109.08
OR W95.00
ANDLD
ANDNOT W374.14
TIM 0220 #30
AND T0220
OUT W95.00
LD TR0
LD 2101.05
ANDNOT 2109.10
OR W95.01
ANDLD
ANDNOT W374.14
TIM 0221 #30
AND T0221
OUT W95.01
LD TR0
LD 2101.06
ANDNOT 2109.11
OR W95.02
ANDLD
ANDNOT W374.14
TIM 0222 #30
AND T0222
OUT W95.02
LD TR0
LD 2103.04
ANDNOT 2109.13
OR W95.03
ANDLD
ANDNOT W374.14
TIM 0223 #30
AND T0223
OUT W95.03
; rung 1681
LD P_On
OUT TR0
LD 2121.04
ANDNOT 2129.08
OR W95.04
ANDLD
ANDNOT W374.14
TIM 0224 #30
AND T0224
OUT W95.04
LD TR0
LD 2121.05
ANDNOT 2129.10
OR W95.05
ANDLD
ANDNOT W374.14
TIM 0225 #30
AND T0225
OUT W95.05
LD TR0
LD 2121.06
ANDNOT 2129.11
OR W95.06
ANDLD
ANDNOT W374.14
TIM 0226 #30
AND T0226
OUT W95.06
LD TR0
LD 2123.04
ANDNOT 2129.13
OR W95.07
ANDLD
ANDNOT W374.14
TIM 0227 #30
AND T0227
OUT W95.07

; rung 1682: ----- 警報46 -----
LDNOT P_On
OUT TR0
LD W95.09
OR W95.10
OR W344.15
ANDLD
ANDNOT W374.14
OUT W344.15
LD TR0
LD W344.15
AND W385.14
OR W346.15
ANDLD
ANDNOT W374.14
OUT W346.15
LD TR0
LD P_1s
OR W346.15
ANDLD
AND W344.15
OUT W341.15
; rung 1683
LD W176.05
ANDNOT W223.00
OR W95.09
ANDNOT W374.14
OUT W95.09
; rung 1684
LD W306.05
ANDNOT W224.13
OR W95.10
ANDNOT W374.14
OUT W95.10
; rung 1685: ----- 警報47 -----
LDNOT P_On
OUT TR0
LD P_On
OR W345.00
ANDLD
ANDNOT W374.14
OUT W345.00
LD TR0
LD W345.00
AND W385.14
OR W347.00
ANDLD
ANDNOT W374.14
OUT W347.00
LD TR0
LD P_1s
OR W347.00
ANDLD
AND W345.00
OUT W342.00
; rung 1686
LD P_On
LD W193.02
AND 424.00
OR W200.02
ANDLD
ANDNOT W193.03
OUT W200.02
; rung 1687
LD P_On
AND 10.14
AND 421.03
OR W200.03
AND 424.00
AND W161.05
OUT W200.03

; rung 1688
LD W200.03
AND 13.03
OUT W200.04
; rung 1689
LD 421.04
OR W200.06
ANDNOT 10.14
OUT W200.06
; rung 1690
LD W193.02
OR W200.07
ANDNOT 10.14
OUT W200.07
; rung 1691
LDNOT W200.03
ANDNOT W200.07
LDNOT 16.04
ORNOT 16.06
ANDLD
ANDNOT W200.06
AND 424.00
OUT W200.08
; rung 1692: ----- 警報48 -----
LD P_On
OUT TR0
LD W200.02
ANDNOT W161.05
OR W200.08
OR W345.01
ANDLD
ANDNOT W374.14
OUT W345.01
LD TR0
LD W345.01
AND W385.14
OR W347.01
ANDLD
ANDNOT W374.14
OUT W347.01
LD TR0
LD P_1s
OR W347.01
ANDLD
AND W345.01
OUT W342.01
; rung 1693: ----- 警報49 -----
LDNOT P_On
OUT TR0
LD P_On
OR W345.02
ANDLD
ANDNOT W374.14
OUT W345.02
LD TR0
LD W345.02
AND W385.14
OR W347.02
ANDLD
ANDNOT W374.14
OUT W347.02
LD TR0
LD P_1s
OR W347.02
ANDLD
AND W345.02
OUT W342.02

; rung 1694: ----- 警報50 -----
LD W190.03
OR W59.08
AND W170.00
AND T0021
ANDNOT W223.04
AND H8.10
ANDNOT H1.03
OUT W59.08
; rung 1695
LD H8.10
ANDNOT H1.03
AND 420.07
AND T0021
AND W165.00
AND W223.01
ANDNOT W183.03
ANDNOT W223.03
ANDNOT W223.04
OUT W59.07
; rung 1696
LD H1.08
AND W189.15
LDNOT H1.08
AND H1.09
AND W303.01
ORLD
LDNOT H1.08
ANDNOT H1.09
AND W183.04
ORLD
ANDNOT 2110.06
AND W59.07
ANDNOT W59.08
OUT W59.06
; rung 1697
LD H1.08
ANDNOT W189.14
LDNOT H1.08
AND H1.09
ANDNOT W187.02
ORLD
LDNOT H1.08
ANDNOT H1.09
ANDNOT W183.03
ORLD
AND W59.05
AND W59.07
TIM 0387 D637
; rung 1698
LD W190.03
OR W59.04
AND W358.05
AND T0021
ANDNOT W225.01
AND H8.10
ANDNOT H1.03
OUT W59.04
; rung 1699
LD H8.10
ANDNOT H1.03
AND 420.07
AND T0021
AND W165.02
AND W224.14
ANDNOT W313.03
ANDNOT W225.00
ANDNOT W225.01
OUT W59.03
; rung 1700
LD H1.10
AND W319.15
LDNOT H1.10
AND H1.11
AND W303.02
ORLD
LDNOT H1.10
ANDNOT H1.11
AND W313.04
ORLD
ANDNOT 2130.06
AND W59.03
ANDNOT W59.04
OUT W59.02
; rung 1701
LD H1.10
ANDNOT W319.14
LDNOT H1.10
AND H1.11
ANDNOT W317.02
ORLD
LDNOT H1.10
ANDNOT H1.11
ANDNOT W313.03
ORLD
AND W59.01
AND W59.03
TIM 0388 D638
; rung 1702
LDNOT W59.06
ANDNOT T0387
ANDNOT W59.02
ANDNOT T0388
OUTNOT W57.06

; rung 1703
LD T0511
OUT TR0
LD W57.06
OR W345.03
ANDLD
ANDNOT W374.14
OUT W345.03
LD TR0
LD W345.03
AND W385.14
OR W347.03
ANDLD
ANDNOT W374.14
OUT W347.03
LD TR0
LD P_1s
OR W347.03
ANDLD
AND W345.03
OUT W342.03
; rung 1704
LD W345.03
OUT TR0
LD W59.06
OR W58.09
ANDLD
OUT W58.09
LD TR0
LD T0387
OR W58.10
ANDLD
OUT W58.10
LD TR0
LD W59.02
OR W58.11
ANDLD
OUT W58.11
LD TR0
LD T0388
OR W58.12
ANDLD
OUT W58.12
; rung 1705: ----- 警報51 -----
LD 14.12
OR W53.06
AND T0021
AND W181.12
ANDNOT 16.05
OUT W53.06
TIM 0009 #50
; rung 1706
LD 14.13
OR W53.07
AND T0021
AND W181.14
ANDNOT 16.04
OUT W53.07
TIM 0010 #50

; rung 1707
LD T0021
OUT TR0
AND 14.12
TIM 0540 #170
TIM 0552 #160
TIM 0553 #60
LD TR0
AND 14.13
TIM 0541 #170
LD TR0
AND 2103.12
TIM 0544 #50
LD TR0
AND W360.00
ANDNOT 16.05
TIM 0546 #10
LD TR0
AND W360.02
ANDNOT 16.04
TIM 0548 #20
; rung 1708
LD T0511
OUT TR0
LD T0009
OR T0010
OR T0540
OR T0541
OR T0534
OR T0544
OR T0546
OR T0548
OR W345.04
ANDLD
ANDNOT W374.14
OUT W345.04
LD TR0
LD W345.04
AND W385.14
OR W347.04
ANDLD
ANDNOT W374.14
OUT W347.04
LD TR0
LD P_1s
OR W347.04
ANDLD
AND W345.04
OUT W342.04

; rung 1709
LD W345.04
OUT TR0
LD T0009
OR W57.07
ANDLD
OUT W57.07
LD TR0
LD T0010
OR W57.08
ANDLD
OUT W57.08
LD TR0
LD T0540
OR W68.00
ANDLD
OUT W68.00
LD TR0
LD T0541
OR W68.01
ANDLD
OUT W68.01
; rung 1710
LD T0009
OR W345.04
@MOV(021) D273 D2100
; rung 1711
LD T0540
OR W68.00
@MOV(021) D273 D2102
; rung 1712
LD W345.04
OUT TR0
LD T0534
OR W68.02
ANDLD
OUT W68.02
LD TR0
LD T0544
OR W68.03
ANDLD
OUT W68.03
LD TR0
LD T0546
OR W68.04
ANDLD
OUT W68.04
LD TR0
LD T0548
OR W68.05
ANDLD
OUT W68.05
; rung 1713: ----- 警報52 -----
LD 14.14
OR W53.08
AND T0021
AND W311.12
ANDNOT 16.07
OUT W53.08
TIM 0013 #50

; rung 1714
LD 14.15
OR W53.09
AND T0021
AND W311.14
ANDNOT 16.06
OUT W53.09
TIM 0014 #50
; rung 1715
LD T0021
OUT TR0
AND 14.14
TIM 0542 #170
LD TR0
AND 14.15
TIM 0543 #170
LD TR0
AND 2123.12
TIM 0545 #50
LD TR0
AND W360.01
ANDNOT 16.07
TIM 0547 #10
LD TR0
AND W360.03
ANDNOT 16.06
TIM 0549 #20
; rung 1716
LD T0511
OUT TR0
LD T0013
OR T0014
OR T0542
OR T0543
OR T0539
OR T0545
OR T0547
OR T0549
OR W345.05
ANDLD
ANDNOT W374.14
OUT W345.05
LD TR0
LD W345.05
AND W385.14
OR W347.05
ANDLD
ANDNOT W374.14
OUT W347.05
LD TR0
LD P_1s
OR W347.05
ANDLD
AND W345.05
OUT W342.05

; rung 1717
LD W345.05
OUT TR0
LD T0013
OR W57.09
ANDLD
OUT W57.09
LD TR0
LD T0014
OR W57.10
ANDLD
OUT W57.10
LD TR0
LD T0542
OR W68.06
ANDLD
OUT W68.06
LD TR0
LD T0543
OR W68.07
ANDLD
OUT W68.07
; rung 1718
LD W345.05
OUT TR0
LD T0539
OR W68.08
ANDLD
OUT W68.08
LD TR0
LD T0545
OR W68.09
ANDLD
OUT W68.09
LD TR0
LD T0547
OR W68.10
ANDLD
OUT W68.10
LD TR0
LD T0549
OR W68.11
ANDLD
OUT W68.11
; rung 1719: ----- 警報53 -----
LD P_On
OUT TR0
@LD W363.11
OR W345.06
ANDLD
ANDNOT W374.14
OUT W345.06
LD TR0
LD W345.06
AND W385.14
OR W347.06
ANDLD
ANDNOT W374.14
OUT W347.06
LD TR0
LD P_1s
OR W347.06
ANDLD
AND W345.06
OUT W342.06

; rung 1720: ----- 警報54 -----
LDNOT 423.00
OR W345.07
OUT TR0
LD P_On
OR W345.07
ANDLD
ANDNOT W374.14
OUT W345.07
LD TR0
LD W345.07
AND W385.14
OR W347.07
ANDLD
ANDNOT W374.14
OUT W347.07
LD TR0
LD P_1s
OR W347.07
ANDLD
AND W345.07
OUT W342.07
; rung 1721: ----- 警報55 -----
LD P_On
OUT TR0
LD T0600
OR T0601
OR W345.08
ANDLD
ANDNOT W374.14
OUT W345.08
LD TR0
LD W345.08
AND W385.14
OR W347.08
ANDLD
ANDNOT W374.14
OUT W347.08
LD TR0
LD P_1s
OR W347.08
ANDLD
AND W345.08
OUT W342.08
; rung 1722
LD 20.08
OR T0600
ANDNOT W452.02
ANDNOT W374.14
TIM 0600 #30
AND T0600
OUT W452.01
; rung 1723
LD 20.09
OR T0601
ANDNOT W452.02
ANDNOT W374.14
TIM 0601 #30
AND T0601
OUT W452.00

; rung 1724: ----- 警報56 -----
LD T0511
OUT TR0
LD 470.05
OR W345.09
ANDLD
ANDNOT W374.14
OUT W345.09
LD TR0
LD W345.09
AND W385.14
OR W347.09
ANDLD
ANDNOT W374.14
OUT W347.09
LD TR0
LD P_1s
OR W347.09
ANDLD
AND W345.09
OUT W342.09
; rung 1725
LDNOT P_On
OR W303.05
AND W345.09
OUT W303.05
; rung 1726: ----- 警報57 -----
LDNOT 26.03
ANDNOT 26.04
ANDNOT 26.05
ANDNOT 26.06
ANDNOT 20.04
OUTNOT W302.15
; rung 1727
LD H8.15
AND T0511
OUT TR0
LD W302.15
OR W345.10
ANDLD
ANDNOT W374.14
OUT W345.10
LD TR0
LD W345.10
AND W385.14
OR W347.10
ANDLD
ANDNOT W374.14
OUT W347.10
LD TR0
LD P_1s
OR W347.10
ANDLD
AND W345.10
OUT W342.10

; rung 1728
LD W345.10
OUT TR0
LD 26.03
OR W303.06
ANDLD
OUT W303.06
LD TR0
LD 26.04
OR W303.07
ANDLD
OUT W303.07
LD TR0
LD 26.05
OR W303.08
ANDLD
OUT W303.08
LD TR0
LD 26.06
OR W303.09
ANDLD
OUT W303.09
LD TR0
LD 20.04
OR W303.10
ANDLD
OUT W303.10
; rung 1729: ----- 警報58 -----
LD T0511
OUT TR0
LD T0031
ANDNOT 26.13
OR W345.11
ANDLD
ANDNOT W374.14
OUT W345.11
LD TR0
LD W345.11
AND W385.14
OR W347.11
ANDLD
ANDNOT W374.14
OUT W347.11
LD TR0
LD P_1s
OR W347.11
ANDLD
AND W345.11
OUT W342.11
; rung 1730: ----- 警報59 -----
LD T0511
OUT TR0
LDNOT 10.02
OR W345.12
ANDLD
ANDNOT W374.14
OUT W345.12
LD TR0
LD W345.12
AND W385.14
OR W347.12
ANDLD
ANDNOT W374.14
OUT W347.12
LD TR0
LD P_1s
OR W347.12
ANDLD
AND W345.12
OUT W342.12

; rung 1731: ----- 警報60 -----
LD P_On
OUT TR0
LD 24.08
OR W345.13
ANDLD
ANDNOT W374.14
OUT W345.13
LD TR0
LD W345.13
AND W385.14
OR W347.13
ANDLD
ANDNOT W374.14
OUT W347.13
LD TR0
LD P_1s
OR W347.13
ANDLD
AND W345.13
OUT W342.13
; rung 1732: ----- 警報61 -----
LD P_On
OUT TR0
LD H5.08
AND W94.01
ANDNOT 2034.11
OR W142.00
ANDLD
ANDNOT W374.14
OUT W142.00
LD TR0
LD W142.00
AND W385.14
OR W144.00
ANDLD
ANDNOT W374.14
OUT W144.00
LD TR0
LD P_1s
OR W144.00
ANDLD
AND W142.00
OUT W140.00
; rung 1733: ----- 警報62 -----
LD P_On
OUT TR0
LD H5.10
AND W94.05
ANDNOT 2036.11
OR W142.01
ANDLD
ANDNOT W374.14
OUT W142.01
LD TR0
LD W142.01
AND W385.14
OR W144.01
ANDLD
ANDNOT W374.14
OUT W144.01
LD TR0
LD P_1s
OR W144.01
ANDLD
AND W142.01
OUT W140.01

; rung 1734: ----- 警報63 -----
LD P_On
OUT TR0
LDNOT 20.11
OR W142.02
ANDLD
ANDNOT W374.14
OUT W142.02
LD TR0
LD W142.02
AND W385.14
OR W144.02
ANDLD
ANDNOT W374.14
OUT W144.02
LD TR0
LD P_1s
OR W144.02
ANDLD
AND W142.02
OUT W140.02
; rung 1735: ----- 警報64 -----
LD P_On
OUT TR0
LDNOT 20.12
OR W142.03
ANDLD
ANDNOT W374.14
OUT W142.03
LD TR0
LD W142.03
AND W385.14
OR W144.03
ANDLD
ANDNOT W374.14
OUT W144.03
LD TR0
LD P_1s
OR W144.03
ANDLD
AND W142.03
OUT W140.03
; rung 1736: ----- 警報65 -----
LDNOT P_On
OUT TR0
LD W470.10
OR W142.04
ANDLD
ANDNOT W374.14
OUT W142.04
LD TR0
LD W142.04
AND W385.14
OR W144.04
ANDLD
ANDNOT W374.14
OUT W144.04
LD TR0
LD P_1s
OR W144.04
ANDLD
AND W142.04
OUT W140.04

; rung 1737: ----- 警報66 -----
LD 16.11
OR 16.10
AND 13.03
AND P_On
OUT TR0
LDNOT 2035.11
AND 15.02
ANDNOT 2031.05
ANDNOT W48.12
LDNOT 2130.14
AND 15.03
ANDNOT 2033.05
ANDNOT W48.13
ORLD
LD H5.09
ANDNOT W101.06
ANDNOT 2031.05
ANDNOT W48.12
ANDNOT 2035.11
ORLD
LD H5.11
ANDNOT W111.06
ANDNOT 2033.05
ANDNOT W48.13
ANDNOT 2130.14
ORLD
OR W142.05
ANDLD
ANDNOT W374.14
OUT W142.05
LD TR0
LD W142.05
AND W385.14
OR W144.05
ANDLD
ANDNOT W374.14
OUT W144.05
LD TR0
LD P_1s
OR W144.05
ANDLD
AND W142.05
OUT W140.05
; rung 1738
LD P_On
OUT TR0
LDNOT 2035.11
AND 15.02
LDNOT 15.02
AND H5.09
ANDNOT 2035.11
ORLD
OR W470.12
ANDLD
ANDNOT W374.14
AND W142.05
OUT W470.12
LD TR0
LDNOT 2130.14
AND 15.03
LDNOT 15.03
AND H5.11
ANDNOT 2130.14
ORLD
OR W470.13
ANDLD
ANDNOT W374.14
AND W142.05
OUT W470.13
; rung 1739: ----- 警報67 -----
LD P_On
OUT TR0
LD W201.01
OR W201.02
OR W142.06
ANDLD
ANDNOT W374.14
OUT W142.06
LD TR0
LD W142.06
AND W385.14
OR W144.06
ANDLD
ANDNOT W374.14
OUT W144.06
LD TR0
LD P_1s
OR W144.06
ANDLD
AND W142.06
OUT W140.06

; rung 1740: ----- 警報68 -----
LD P_On
OUT TR0
LD W269.07
OR W269.05
OR W142.07
ANDLD
ANDNOT W374.14
OUT W142.07
LD TR0
LD W142.07
AND W385.14
OR W144.07
ANDLD
ANDNOT W374.14
OUT W144.07
LD TR0
LD P_1s
OR W144.07
ANDLD
AND W142.07
OUT W140.07
; rung 1741: ----- 警報69 -----
LD P_On
OUT TR0
LD W476.15
OR W142.08
ANDLD
ANDNOT W374.14
OUT W142.08
LD TR0
LD W142.08
AND W385.14
OR W144.08
ANDLD
ANDNOT W374.14
OUT W144.08
LD TR0
LD P_1s
OR W144.08
ANDLD
AND W142.08
OUT W140.08
; rung 1742
LDNOT W476.00
ANDNOT W476.01
ANDNOT W476.02
ANDNOT W476.03
ANDNOT W476.04
ANDNOT W476.05
ANDNOT W476.06
ANDNOT W476.07
OUTNOT W476.15
; rung 1743: ----- 警報70 -----
LDNOT P_On
OUT TR0
LD P_On
OR W142.09
ANDLD
ANDNOT W374.14
OUT W142.09
LD TR0
LD W142.09
AND W385.14
OR W144.09
ANDLD
ANDNOT W374.14
OUT W144.09
LD TR0
LD P_1s
OR W144.09
ANDLD
AND W142.09
OUT W140.09

; rung 1744: ----- 警報71 -----
LDNOT P_On
OUT TR0
LD P_On
OR W142.10
ANDLD
ANDNOT W374.14
OUT W142.10
LD TR0
LD W142.10
AND W385.14
OR W144.10
ANDLD
ANDNOT W374.14
OUT W144.10
LD TR0
LD P_1s
OR W144.10
ANDLD
AND W142.10
OUT W140.10
; rung 1745: ----- 警報72 -----
LDNOT P_On
OUT TR0
LD P_On
OR W142.11
ANDLD
ANDNOT W374.14
OUT W142.11
LD TR0
LD W142.11
AND W385.14
OR W144.11
ANDLD
ANDNOT W374.14
OUT W144.11
LD TR0
LD P_1s
OR W144.11
ANDLD
AND W142.11
OUT W140.11
; rung 1746: ----- 警報73 -----
LDNOT P_On
OUT TR0
LD P_On
OR W142.12
ANDLD
ANDNOT W374.14
OUT W142.12
LD TR0
LD W142.12
AND W385.14
OR W144.12
ANDLD
ANDNOT W374.14
OUT W144.12
LD TR0
LD P_1s
OR W144.12
ANDLD
AND W142.12
OUT W140.12

; rung 1747: ----- 警報74 -----
LDNOT P_On
OUT TR0
LD P_On
OR W142.13
ANDLD
ANDNOT W374.14
OUT W142.13
LD TR0
LD W142.13
AND W385.14
OR W144.13
ANDLD
ANDNOT W374.14
OUT W144.13
LD TR0
LD P_1s
OR W144.13
ANDLD
AND W142.13
OUT W140.13
; rung 1748: ----- 警報75 -----
LDNOT P_On
OUT TR0
LD P_On
OR W142.14
ANDLD
ANDNOT W374.14
OUT W142.14
LD TR0
LD W142.14
AND W385.14
OR W144.14
ANDLD
ANDNOT W374.14
OUT W144.14
LD TR0
LD P_1s
OR W144.14
ANDLD
AND W142.14
OUT W140.14
; rung 1749: ----- 警報76 -----
LDNOT P_On
OUT TR0
LD P_On
OR W142.15
ANDLD
ANDNOT W374.14
OUT W142.15
LD TR0
LD W142.15
AND W385.14
OR W144.15
ANDLD
ANDNOT W374.14
OUT W144.15
LD TR0
LD P_1s
OR W144.15
ANDLD
AND W142.15
OUT W140.15

; rung 1750: ----- 警報77 -----
LDNOT P_On
OUT TR0
LD P_On
OR W143.00
ANDLD
ANDNOT W374.14
OUT W143.00
LD TR0
LD W143.00
AND W385.14
OR W145.00
ANDLD
ANDNOT W374.14
OUT W145.00
LD TR0
LD P_1s
OR W145.00
ANDLD
AND W143.00
OUT W141.00
; rung 1751: ----- 警報78 -----
LDNOT P_On
OUT TR0
LD P_On
OR W143.01
ANDLD
ANDNOT W374.14
OUT W143.01
LD TR0
LD W143.01
AND W385.14
OR W145.01
ANDLD
ANDNOT W374.14
OUT W145.01
LD TR0
LD P_1s
OR W145.01
ANDLD
AND W143.01
OUT W141.01
; rung 1752: ----- 警報79 -----
LDNOT P_On
OUT TR0
LD P_On
OR W143.02
ANDLD
ANDNOT W374.14
OUT W143.02
LD TR0
LD W143.02
AND W385.14
OR W145.02
ANDLD
ANDNOT W374.14
OUT W145.02
LD TR0
LD P_1s
OR W145.02
ANDLD
AND W143.02
OUT W141.02

; rung 1753: ----- 警報80 -----
LDNOT P_On
OUT TR0
LD P_On
OR W143.03
ANDLD
ANDNOT W374.14
OUT W143.03
LD TR0
LD W143.03
AND W385.14
OR W145.03
ANDLD
ANDNOT W374.14
OUT W145.03
LD TR0
LD P_1s
OR W145.03
ANDLD
AND W143.03
OUT W141.03
; rung 1754: ----- 警報81 -----
LDNOT P_On
OUT TR0
LD P_On
OR W143.04
ANDLD
ANDNOT W374.14
OUT W143.04
LD TR0
LD W143.04
AND W385.14
OR W145.04
ANDLD
ANDNOT W374.14
OUT W145.04
LD TR0
LD P_1s
OR W145.04
ANDLD
AND W143.04
OUT W141.04
; rung 1755: ----- 警報82 -----
LDNOT P_On
OUT TR0
LD P_On
OR W143.05
ANDLD
ANDNOT W374.14
OUT W143.05
LD TR0
LD W143.05
AND W385.14
OR W145.05
ANDLD
ANDNOT W374.14
OUT W145.05
LD TR0
LD P_1s
OR W145.05
ANDLD
AND W143.05
OUT W141.05

; rung 1756: ----- 警報83 -----
LDNOT P_On
OUT TR0
LD P_On
OR W143.06
ANDLD
ANDNOT W374.14
OUT W143.06
LD TR0
LD W143.06
AND W385.14
OR W145.06
ANDLD
ANDNOT W374.14
OUT W145.06
LD TR0
LD P_1s
OR W145.06
ANDLD
AND W143.06
OUT W141.06
; rung 1757: ----- 警報84 -----
LDNOT P_On
OUT TR0
LD P_On
OR W143.07
ANDLD
ANDNOT W374.14
OUT W143.07
LD TR0
LD W143.07
AND W385.14
OR W145.07
ANDLD
ANDNOT W374.14
OUT W145.07
LD TR0
LD P_1s
OR W145.07
ANDLD
AND W143.07
OUT W141.07
; rung 1758: ----- 警報85 -----
LDNOT P_On
OUT TR0
LD P_On
OR W143.08
ANDLD
ANDNOT W374.14
OUT W143.08
LD TR0
LD W143.08
AND W385.14
OR W145.08
ANDLD
ANDNOT W374.14
OUT W145.08
LD TR0
LD P_1s
OR W145.08
ANDLD
AND W143.08
OUT W141.08

; rung 1759: ----- 警報86 -----
LDNOT P_On
OUT TR0
LD P_On
OR W143.09
ANDLD
ANDNOT W374.14
OUT W143.09
LD TR0
LD W143.09
AND W385.14
OR W145.09
ANDLD
ANDNOT W374.14
OUT W145.09
LD TR0
LD P_1s
OR W145.09
ANDLD
AND W143.09
OUT W141.09
; rung 1760: ----- 警報87 -----
LDNOT P_On
OUT TR0
LD P_On
OR W143.10
ANDLD
ANDNOT W374.14
OUT W143.10
LD TR0
LD W143.10
AND W385.14
OR W145.10
ANDLD
ANDNOT W374.14
OUT W145.10
LD TR0
LD P_1s
OR W145.10
ANDLD
AND W143.10
OUT W141.10
; rung 1761: ----- 警報88 -----
LDNOT P_On
OUT TR0
LD P_On
OR W143.11
ANDLD
ANDNOT W374.14
OUT W143.11
LD TR0
LD W143.11
AND W385.14
OR W145.11
ANDLD
ANDNOT W374.14
OUT W145.11
LD TR0
LD P_1s
OR W145.11
ANDLD
AND W143.11
OUT W141.11

; rung 1762: ----- 警報89 -----
LDNOT P_On
OUT TR0
LD P_On
OR W143.12
ANDLD
ANDNOT W374.14
OUT W143.12
LD TR0
LD W143.12
AND W385.14
OR W145.12
ANDLD
ANDNOT W374.14
OUT W145.12
LD TR0
LD P_1s
OR W145.12
ANDLD
AND W143.12
OUT W141.12
; rung 1763: ----- 警報90 -----
LDNOT P_On
OUT TR0
LD P_On
OR W143.13
ANDLD
ANDNOT W374.14
OUT W143.13
LD TR0
LD W143.13
AND W385.14
OR W145.13
ANDLD
ANDNOT W374.14
OUT W145.13
LD TR0
LD P_1s
OR W145.13
ANDLD
AND W143.13
OUT W141.13
; rung 1764: ********** パトライト処理 ********** / 今回成形機操作盤のパトライトRYは肉調PLC / 赤：非常停止     黄：異常発生     緑：捨打ち及び段取     青：自動運転中     白：未使用
LDNOT W384.00
ANDNOT W384.01
ANDNOT W384.02
ANDNOT W384.03
ANDNOT W384.04
ANDNOT W384.05
ANDNOT W384.06
ANDNOT W384.07
ANDNOT W384.08
ANDNOT W384.09
ANDNOT W384.10
ANDNOT W384.11
ANDNOT W384.12
ANDNOT W384.13
ANDNOT W384.14
ANDNOT W384.15
OUTNOT W375.10
; rung 1765
LDNOT W385.00
ANDNOT W385.01
ANDNOT W385.02
ANDNOT W385.03
ANDNOT W385.04
ANDNOT W385.05
ANDNOT W385.06
ANDNOT W385.07
ANDNOT W385.08
ANDNOT W385.09
ANDNOT W385.10
ANDNOT W385.11
ANDNOT W385.12
ANDNOT W385.13
OUTNOT W375.11
; rung 1766
LDNOT W344.00
ANDNOT W344.01
ANDNOT W344.02
ANDNOT W344.03
ANDNOT W344.04
ANDNOT W344.05
ANDNOT W344.06
ANDNOT W344.07
ANDNOT W344.08
ANDNOT W344.09
ANDNOT W344.10
ANDNOT W344.11
ANDNOT W344.12
ANDNOT W344.13
ANDNOT W344.14
ANDNOT W344.15
OUTNOT W343.15
; rung 1767
LDNOT W345.00
ANDNOT W345.01
ANDNOT W345.02
ANDNOT W345.03
ANDNOT W345.04
ANDNOT W345.05
ANDNOT W345.06
ANDNOT W345.07
ANDNOT W345.08
ANDNOT W345.09
ANDNOT W345.10
ANDNOT W345.11
ANDNOT W345.12
ANDNOT W345.13
OUTNOT W374.11
; rung 1768
LDNOT W142.00
ANDNOT W142.01
ANDNOT W142.02
ANDNOT W142.03
ANDNOT W142.04
ANDNOT W142.05
ANDNOT W142.06
ANDNOT W142.07
ANDNOT W142.08
ANDNOT W142.09
ANDNOT W142.10
ANDNOT W142.11
ANDNOT W142.12
ANDNOT W142.13
ANDNOT W142.14
ANDNOT W142.15
OUTNOT W362.14
; rung 1769
LDNOT W143.00
ANDNOT W143.01
ANDNOT W143.02
ANDNOT W143.03
ANDNOT W143.04
ANDNOT W143.05
ANDNOT W143.06
ANDNOT W143.07
ANDNOT W143.08
ANDNOT W143.09
ANDNOT W143.10
ANDNOT W143.11
ANDNOT W143.12
ANDNOT W143.13
OUTNOT W362.13

; rung 1770
LD W375.10
OR W375.11
OR W343.15
OR W374.11
OR W362.14
OR W362.13
AND T0511
OUT W375.12
AND P_1s
OUT W374.13
; rung 1771
LD T0511
AND P_1s
OUT TR0
LD W375.10
OR W375.11
ANDLD
OUT W374.09
LD TR0
LD W343.15
OR W374.11
ANDLD
OUT W343.00
LD TR0
LD W362.14
OR W362.13
ANDLD
OUT W374.08
; rung 1772
LD W375.12
OR 427.15
OR 456.02
OR 428.00
LD 11.02
OR W375.15
ANDLD
OUT W375.15
; rung 1773
LD W375.12
OR 427.15
OR 456.02
OR 428.00
LD P_1s
OR W375.15
ANDLD
OUT W361.15
OUT 2044.09
; rung 1774: ********** ブザー処理 **********
LDNOT W384.00
OR W386.00
LDNOT W384.01
OR W386.01
ANDLD
LDNOT W384.02
OR W386.02
ANDLD
LDNOT W384.03
OR W386.03
ANDLD
LDNOT W384.04
OR W386.04
ANDLD
LDNOT W384.07
OR W386.07
ANDLD
LDNOT W384.08
OR W386.08
ANDLD
LDNOT W384.09
OR W386.09
ANDLD
LDNOT W384.10
OR W386.10
ANDLD
LDNOT W384.11
OR W386.11
ANDLD
LDNOT W384.12
OR W386.12
ANDLD
LDNOT W384.13
OR W386.13
ANDLD
LDNOT W384.14
OR W386.14
ANDLD
LDNOT W384.15
OR W386.15
ANDLD
OUTNOT W375.13

; rung 1775
LDNOT W385.00
OR W387.00
LDNOT W385.01
OR W387.01
ANDLD
LDNOT W385.02
OR W387.02
ANDLD
LDNOT W385.03
OR W387.03
ANDLD
LDNOT W385.05
OR W387.05
ANDLD
LDNOT W385.07
OR W387.07
ANDLD
LDNOT W385.06
OR W387.06
ANDLD
LDNOT W385.08
OR W387.08
ANDLD
LDNOT W385.09
OR W387.09
ANDLD
LDNOT W385.10
OR W387.10
ANDLD
LDNOT W385.11
OR W387.11
ANDLD
LDNOT W385.12
OR W387.12
ANDLD
LDNOT W385.13
OR W387.13
ANDLD
OUTNOT W375.14
; rung 1776
LDNOT W344.02
OR W346.02
LDNOT W344.03
OR W346.03
ANDLD
LDNOT W344.05
OR W346.05
ANDLD
LDNOT W344.07
OR W346.07
ANDLD
LDNOT W344.08
OR W346.08
ANDLD
LDNOT W344.10
OR W346.10
ANDLD
LDNOT W344.11
OR W346.11
ANDLD
LDNOT W344.12
OR W346.12
ANDLD
LDNOT W344.13
OR W346.13
ANDLD
LDNOT W344.14
OR W346.14
ANDLD
LDNOT W344.15
OR W346.15
ANDLD
OUTNOT W343.14
; rung 1777
LDNOT W345.00
OR W347.00
LDNOT W345.01
OR W347.01
ANDLD
LDNOT W345.02
OR W347.02
ANDLD
LDNOT W345.03
OR W347.03
ANDLD
LDNOT W345.04
OR W347.04
ANDLD
LDNOT W345.05
OR W347.05
ANDLD
LDNOT W345.06
OR W347.06
ANDLD
LDNOT W345.07
OR W347.07
ANDLD
LDNOT W345.08
OR W347.08
ANDLD
LDNOT W345.09
OR W347.09
ANDLD
LDNOT W345.10
OR W347.10
ANDLD
LDNOT W345.11
OR W347.11
ANDLD
LDNOT W345.12
OR W347.12
ANDLD
OUTNOT W374.10
; rung 1778
LDNOT W142.00
OR W144.00
LDNOT W142.01
OR W144.01
ANDLD
LDNOT W142.02
OR W144.02
ANDLD
LDNOT W142.03
OR W144.03
ANDLD
LDNOT W142.04
OR W144.04
ANDLD
LDNOT W142.05
OR W144.05
ANDLD
LDNOT W142.06
OR W144.06
ANDLD
LDNOT W142.07
OR W144.07
ANDLD
LDNOT W142.08
OR W144.08
ANDLD
LDNOT W142.09
OR W144.09
ANDLD
LDNOT W142.10
OR W144.10
ANDLD
LDNOT W142.11
OR W144.11
ANDLD
LDNOT W142.12
OR W144.12
ANDLD
LDNOT W142.13
OR W144.13
ANDLD
LDNOT W142.14
OR W144.14
ANDLD
LDNOT W142.15
OR W144.15
ANDLD
OUTNOT W362.12
; rung 1779
LDNOT W143.00
OR W145.00
LDNOT W143.01
OR W145.01
ANDLD
LDNOT W143.02
OR W145.02
ANDLD
LDNOT W143.03
OR W145.03
ANDLD
LDNOT W143.04
OR W145.04
ANDLD
LDNOT W143.05
OR W145.05
ANDLD
LDNOT W143.06
OR W145.06
ANDLD
LDNOT W143.07
OR W145.07
ANDLD
LDNOT W143.08
OR W145.08
ANDLD
LDNOT W143.09
OR W145.09
ANDLD
LDNOT W143.10
OR W145.10
ANDLD
LDNOT W143.11
OR W145.11
ANDLD
LDNOT W143.12
OR W145.12
ANDLD
LDNOT W143.13
OR W145.13
ANDLD
OUTNOT W362.11
; rung 1780
LDNOT W375.13
ANDNOT W375.14
ANDNOT W343.14
ANDNOT W374.10
ANDNOT W362.12
ANDNOT W362.11
OUTNOT W362.10
; rung 1781
LDNOT W384.05
OR W386.05
LDNOT W384.06
OR W386.06
ANDLD
LDNOT W385.04
OR W387.04
ANDLD
LDNOT W344.00
OR W346.00
ANDLD
LDNOT W344.01
OR W346.01
ANDLD
LDNOT W344.04
OR W346.04
ANDLD
LDNOT W344.06
OR W346.06
ANDLD
LDNOT W344.09
OR W346.09
ANDLD
LDNOT W345.13
OR W347.13
ANDLD
OUTNOT W363.10
; rung 1782
@LD W193.05
OR H86.00
ANDNOT W200.15
OUT W200.14

; rung 1783
@LD W200.14
@OR W200.15
ANDNOT H86.00
@LD W200.15
AND H86.00
KEEP(011) H86.00
; rung 1784
LD P_On
ANDNOT 11.01
OUT TR0
@LD W311.00
@OR W311.03
OR W363.12
ANDLD
AND W200.14
OUT W363.12
LD TR0
@LD W311.01
@OR W311.02
OR W363.13
ANDLD
AND W200.14
OUT W363.13
LD TR0
@LD W181.04
@OR W178.00
OR W363.14
ANDLD
AND W200.14
OUT W363.14
LD TR0
@LD W181.05
@OR W178.01
OR W363.15
ANDLD
AND W200.14
OUT W363.15
; rung 1785
LD W363.12
OR W363.13
OR W363.14
OR W363.15
OUT W363.11
; rung 1786
LD 413.15
OR W58.00
ANDNOT 11.02
OUT W58.00

; rung 1787
LD W363.10
LD 426.09
ANDNOT 413.15
ORLD
LD 426.09
AND 413.15
OR W58.00
AND P_1s
ORLD
OR 456.01
OR 429.11
OR 470.15
LD W193.05
ANDNOT T0021
ORLD
OR W300.00
AND H1.07
AND T0511
OUT 13.06
; rung 1788
@LD 431.00
OR W300.00
ANDNOT 11.02
OUT W300.00
; rung 1789
LD W362.10
OR 462.10
OR 428.01
OR 427.14
AND H1.07
AND T0511
OUT 23.06

; rung 1790
LD W362.10
OR W363.10
OR 426.09
OR 427.14
OR 456.01
OR 462.10
OR 428.01
OR 429.11
OR 470.15
LD W171.11
AND P_1s
ORLD
LD W193.05
ANDNOT T0021
ORLD
AND H1.07
AND T0511
OUT 2044.10
; rung 1791: ********** ランプ表示 ********** / 成形機操作盤ﾊﾟﾄﾗｲﾄは下記事項でON / 赤：非常停止     黄：異常発生     緑：捨打ち及び段取     青：自動運転中     白：未使用
LD W384.00
OUT 19.00
; rung 1792
LD W361.15
OUT 19.01
; rung 1793
LD 15.07
OR W374.12
OUT 19.02
; rung 1794
LD W193.05
OUT 19.03
; rung 1795
LDNOT P_On
OUT 19.04
; rung 1796
LD W193.00
AND T0511
OUT 19.05
; rung 1797
LD W190.00
OR W358.05
LD W320.00
OR W358.04
ANDLD
AND T0511
OUT 19.06

; rung 1798
LDNOT P_On
OUT 19.07
; rung 1799
LD W165.04
AND T0511
OUT 19.08
; rung 1800
LD 15.07
OUT 19.09
; rung 1801
LDNOT P_On
OUT 19.10
OUT 19.11
; rung 1802
LD W361.15
OUT 19.12
; rung 1803: --- 成形機制御盤ﾗﾝﾌﾟ ---
LD 10.07
AND T0511
OUT 13.00
OUT 400.15
; rung 1804
LD 13.08
AND 13.09
AND 22.12
AND 22.13
AND P_1s
OR T0020
AND T0511
OUT 13.01
; rung 1805
LD 2043.00
AND P_1s
OR T0036
AND T0511
OUT 13.02
; rung 1806
LD W193.02
OR H1.05
AND P_1s
LDNOT W193.02
ANDNOT H1.05
ORLD
AND W193.05
AND T0511
OUT 13.03

; rung 1807
LD 17.00
ANDNOT 17.01
LD 17.01
OR 17.02
AND P_1s
ORLD
LD W134.05  ; Kaeser BYPASS
ANDNOT 2109.06
ANDNOT 2129.06
ORLD
OUT 15.00
; rung 1808
LD 17.02
ANDNOT 17.03
LD 22.14
AND P_1s
ORLD
LD W134.05  ; Kaeser BYPASS
ANDNOT 2109.06
ANDNOT 2129.06
ORLD
OUT 15.01
; rung 1809
LD 17.04
ANDNOT 17.05
LD 17.04
AND 17.05
AND P_1s
ORLD
OUT 15.02
; rung 1810
LD 17.06
ANDNOT 17.07
LD 17.06
AND 17.07
AND P_1s
ORLD
OUT 15.03
; rung 1811
LD 2110.07
ANDNOT 2110.08
LD 2110.08
LDNOT P_On
AND W161.03
ORLD
AND P_1s
ORLD
LD 17.02
OR W134.05  ; Kaeser BYPASS
ANDLD
AND 17.04
OUT 15.04
; rung 1812
LD 17.08
LD 17.02
OR W134.05  ; Kaeser BYPASS
ANDLD
AND 17.04
DIFU(013) W170.12
; rung 1813
LD W170.12
ANDNOT W161.03
OR W171.02
ANDNOT W171.03
ANDNOT 2110.07
ANDNOT 2110.08
OUT W171.02
; rung 1814
LD W170.12
OR W171.03
AND W161.03
OUT W171.03

; rung 1815
LD W171.02
OR W161.03
ANDNOT W171.03
ANDNOT 2110.07
ANDNOT 2110.08
OUT W161.03
; rung 1816
LD 2130.07
OR W511.15
ANDNOT 2130.08
LD 2130.08
LDNOT P_On
AND W161.02
ORLD
AND P_1s
ORLD
LD 17.02
OR W134.05  ; Kaeser BYPASS
ANDLD
AND 17.06
OUT 15.05
; rung 1817
LD 17.09
LD 17.02
OR W134.05  ; Kaeser BYPASS
ANDLD
AND 17.06
DIFU(013) W170.11
; rung 1818
LD W170.11
ANDNOT W161.02
OR W171.00
ANDNOT W171.01
ANDNOT 2130.07
ANDNOT 2130.08
ANDNOT W511.15
OUT W171.00
; rung 1819
LD W170.11
OR W171.01
AND W161.02
OUT W171.01
; rung 1820
LD W171.00
OR W161.02
ANDNOT W171.01
ANDNOT 2130.07
ANDNOT 2130.08
ANDNOT W511.15
OUT W161.02
; rung 1821
LD 17.10
AND 17.11
ANDNOT 18.07
OUT 15.06
; rung 1822
LD W177.00
ANDNOT W161.09
LD W161.09
AND P_1s
ORLD
OUT 15.07
OUT 2045.02
; rung 1823
LD W59.09
OUT 15.09

; rung 1824: --- 左成形機操作盤ﾗﾝﾌﾟ ---
LD W165.00
LD 14.12
AND P_1s
ORLD
AND T0511
OUT 2063.11

; rung 1825
LD P_On
OUT TR0
LD 2031.04
OR W451.00
AND 2063.10
ANDNOT P_On
LD 2033.04
OR W451.00
AND 2083.10
ORLD
ANDLD
OUT W451.00
LD TR0
AND W451.00
TIM 2000 #9999
LD TR0
LD W182.02
ANDNOT P_On
OR W312.02
LD 2120.12
AND W312.02
ANDNOT P_On
ORLD
ANDLD
DIFU(013) W451.01
LD TR0
LD T0167
AND W182.03
LD 2101.02
AND W182.02
ORLD
ANDNOT P_On
LD 2121.02
AND W312.02
ORLD
ANDLD
DIFU(013) W451.02
LD TR0
LD W182.03
ANDNOT P_On
OR W312.03
LD 2120.14
AND W312.02
ANDNOT P_On
ORLD
ANDLD
DIFU(013) W451.03
LD TR0
LD W183.15
ANDNOT P_On
OR W313.15
ANDLD
DIFU(013) W451.04
LD TR0
AND W451.01
MOV(021) T2000 D6140
LD TR0
AND W451.02
MOV(021) T2000 D6141
LD TR0
AND W451.03
MOV(021) T2000 D6143
LD TR0
AND W451.04
ANDNOT P_On
MOV(021) T2000 D6144
LD TR0
AND W312.02
@MOV(021) 2027 D6144

; rung 1826
LD W165.01
LD 14.13
AND P_1s
ORLD
AND T0511
OUT 2063.10
; rung 1827
LD T0511
OUT TR0
AND W223.00
OUT 2062.14
LD TR0
AND W223.04
OUT 2062.15
; rung 1828
LD T0511
OUT TR0
LD 2109.10
LD 2101.05
AND P_1s
ORLD
ANDLD
OUT 2060.02
LD TR0
LD 2109.08
LD 2101.04
AND P_1s
ORLD
ANDLD
OUT 2060.03
LD TR0
LD 2109.13
LD 2103.04
AND P_1s
ORLD
ANDLD
OUT 2060.04
LD TR0
LD 2109.11
LD 2101.06
AND P_1s
ORLD
ANDLD
OUT 2060.05
; rung 1829
LD T0511
OUT TR0
LD 428.03
AND 428.05
LD 406.10
AND P_1s
ORLD
ANDLD
OUT 2060.00
LD TR0
LD 428.04
AND 428.06
LD 406.11
AND P_1s
ORLD
ANDLD
OUT 2060.01
; rung 1830
LD T0511
OUT TR0
LD W190.11
LD 2100.10
AND P_1s
ORLD
ANDLD
OUT 2060.12
LD TR0
AND 2100.11
OUT 2060.13
; rung 1831
LD T0511
OUT TR0
LD 2109.00
AND 2109.01
LD 2100.09
AND P_1s
ORLD
ANDLD
OUT 2063.00
LD TR0
AND 2108.12
AND 2108.13
OUT 2063.01

; rung 1832
LDNOT H80.00
AND 2102.10
LD 2102.10
AND P_1s
OR 2108.01
AND H80.00
ORLD
OUT 2060.06
; rung 1833
LDNOT H80.00
AND 2102.06
LD 2102.06
AND P_1s
OR 2108.00
AND H80.00
ORLD
OUT 2060.07
; rung 1834
LDNOT H80.01
AND 2102.11
LD 2102.11
AND P_1s
OR 2108.03
AND H80.01
ORLD
OUT 2060.08
; rung 1835
LDNOT H80.01
AND 2102.07
LD 2102.07
AND P_1s
OR 2108.02
AND H80.01
ORLD
OUT 2060.09
; rung 1836
LDNOT H80.02
AND 2103.05
LD 2103.05
AND P_1s
OR 2108.05
AND H80.02
ORLD
OUT 2060.10
; rung 1837
LDNOT H80.02
AND 2102.08
LD 2102.08
AND P_1s
OR 2108.04
AND H80.02
ORLD
OUT 2060.11
; rung 1838
LDNOT H60.04
AND 2104.08
LD 2104.08
AND P_1s
OR 2109.15
AND H60.04
ORLD
OUT 2064.00

; rung 1839
LDNOT H60.04
AND 2104.04
LD 2104.04
AND P_1s
OR 2109.14
AND H60.04
ORLD
OUT 2064.01
; rung 1840
LDNOT H60.05
AND 2104.09
LD 2104.09
AND P_1s
OR 2110.04
AND H60.05
ORLD
OUT 2064.02
; rung 1841
LDNOT H60.05
AND 2104.05
LD 2104.05
AND P_1s
OR 2110.02
AND H60.05
ORLD
OUT 2064.03
; rung 1842
LDNOT H60.06
AND 2104.10
LD 2104.10
AND P_1s
OR 2110.13
AND H60.06
ORLD
OUT 2064.04
; rung 1843
LDNOT H60.06
AND 2104.06
LD 2104.06
AND P_1s
OR 2110.05
AND H60.06
ORLD
OUT 2064.05
; rung 1844
LDNOT H60.07
AND 2104.11
LD 2104.11
AND P_1s
OR 2035.13
AND H60.07
ORLD
OUT 2064.06
; rung 1845
LDNOT H60.07
AND 2104.07
LD 2104.07
AND P_1s
OR 2035.12
AND H60.07
ORLD
OUT 2064.07

; rung 1846
LDNOT H60.08
AND 2104.01
LD 2104.01
AND P_1s
OR 2109.12
AND H60.08
ORLD
OUT 2065.00
; rung 1847
LDNOT H60.08
AND 2104.00
LD 2104.00
AND P_1s
OR 2109.09
AND H60.08
ORLD
OUT 2065.01
; rung 1848
LD 22.02
AND P_1s
LDNOT H60.09
AND 2104.03
LD 2104.03
AND P_1s
OR 2034.07
AND H60.09
ORLD
AND P_Off
ORLD
OUT 2065.02
; rung 1849
LD 22.03
AND P_1s
LDNOT H60.09
AND 2104.02
LD 2104.02
AND P_1s
OR 2034.06
AND H60.09
ORLD
AND P_Off
ORLD
OUT 2065.03
; rung 1850
LD T0511
OUT TR0
AND 2101.11
OUT 2060.14
LD TR0
AND 2031.07
OUT 2060.15
LD TR0
AND 2030.09
OUT 2061.02
LD TR0
AND 2030.10
OUT 2061.04
LD TR0
AND 2030.11
OUT 2061.06
LD TR0
AND 2030.06
OUT 2061.03
LD TR0
AND 2030.07
OUT 2061.05
LD TR0
AND 2030.08
OUT 2061.07

; rung 1851
LD T0511
OUT TR0
AND 2030.12
OUT 2064.08
LD TR0
AND 2030.13
OUT 2064.10
LD TR0
AND 2030.14
OUT 2064.12
LD TR0
AND 2030.15
OUT 2064.14
LD TR0
AND 2030.00
OUT 2064.09
LD TR0
AND 2030.01
OUT 2064.11
LD TR0
AND 2030.02
OUT 2064.13
LD TR0
AND 2030.03
OUT 2064.15
; rung 1852
LD T0511
OUT TR0
LD 2030.05
AND P_Off
LD 22.00
AND P_1s
ORLD
ANDLD
OUT 2062.02
LD TR0
LD 2030.04
AND P_Off
LD 22.01
AND P_1s
ORLD
ANDLD
OUT 2062.03
LD TR0
AND P_1s
OUT TR0
AND 2103.07
OUT 2061.00
LD TR0
AND 2103.06
OUT 2061.01
; rung 1853
LDNOT H80.03
AND 2102.14
LD 2102.14
AND P_1s
OR 2108.09
AND H80.03
ORLD
OUT 2061.10
; rung 1854
LDNOT H80.03
AND 2102.13
LD 2102.13
AND P_1s
OR 2108.08
AND H80.03
ORLD
OUT 2061.11
; rung 1855
LDNOT H80.04
AND 2101.01
LD 2101.01
AND P_1s
OR 2034.01
AND H80.04
ORLD
OUT 2061.12

; rung 1856
LDNOT H80.04
AND 2100.15
LD 2100.15
AND P_1s
OR 2034.00
AND H80.04
ORLD
OUT 2061.13
; rung 1857
LDNOT H80.05
AND 2103.15
LD 2103.15
AND P_1s
OR 2110.01
AND H80.05
ORLD
OUT 2062.06
; rung 1858
LDNOT H80.05
AND 2103.14
LD 2103.14
AND P_1s
OR 2110.00
AND H80.05
ORLD
OUT 2062.07
; rung 1859
LDNOT H80.06
AND 2101.12
LD 2101.12
AND P_1s
OR 2034.03
AND H80.06
ORLD
OUT 2062.08
; rung 1860
LDNOT H80.06
AND 2101.03
LD 2101.03
AND P_1s
OR 2034.02
AND H80.06
ORLD
OUT 2062.09
; rung 1861
LDNOT H80.07
AND 2031.10
LD 2031.10
AND P_1s
OR 2108.11
AND H80.07
ORLD
OUT 2063.02
; rung 1862
LDNOT H80.07
AND 2031.09
LD 2031.09
AND P_1s
OR 2108.10
AND H80.07
ORLD
OUT 2063.03

; rung 1863
LDNOT H80.08
AND 2031.12
LD 2031.12
AND P_1s
OR 2108.15
AND H80.08
ORLD
OUT 2063.04
; rung 1864
LDNOT H80.08
AND 2031.11
LD 2031.11
AND P_1s
OR 2108.14
AND H80.08
ORLD
OUT 2063.05
; rung 1865
LDNOT H80.09
AND 2100.05
LD 2100.05
AND P_1s
OR 2035.03
AND H80.09
ORLD
OUT 2063.06
; rung 1866
LDNOT H80.09
AND 2100.04
LD 2100.04
AND P_1s
OR 2035.02
AND H80.09
ORLD
OUT 2063.07
; rung 1867
LDNOT H80.10
AND 2100.07
LD 2100.07
AND P_1s
OR 2035.05
AND H80.10
ORLD
OUT 2063.08
; rung 1868
LDNOT H80.10
AND 2100.06
LD 2100.06
AND P_1s
OR 2035.04
AND H80.10
ORLD
OUT 2063.09
; rung 1869
LDNOT H80.11
AND 2101.14
LD 2101.14
AND P_1s
OR 2034.15
AND H80.11
ORLD
OUT 2062.12

; rung 1870
LDNOT H80.11
AND 2101.13
LD 2101.13
AND P_1s
OR 2034.14
AND H80.11
ORLD
OUT 2062.13
; rung 1871
LDNOT H60.00
AND 2102.02
LD 2102.02
AND P_1s
OR 2034.05
AND H60.00
ORLD
OUT 2061.14
; rung 1872
LDNOT H60.00
AND 2102.01
LD 2102.01
AND P_1s
OR 2034.04
AND H60.00
ORLD
OUT 2061.15
; rung 1873
LDNOT H60.01
AND 2102.00
LD 2102.00
AND P_1s
OR 2035.15
AND H60.01
ORLD
OUT 2062.10
; rung 1874
LDNOT H60.01
AND 2101.15
LD 2101.15
AND P_1s
OR 2035.14
AND H60.01
ORLD
OUT 2062.11
; rung 1875
LDNOT H60.02
AND 2102.12
LD 2102.12
AND P_1s
OR 2108.07
AND H60.02
ORLD
OUT 2061.08
; rung 1876
LDNOT H60.02
AND 2102.03
LD 2102.03
AND P_1s
OR 2108.06
AND H60.02
ORLD
OUT 2061.09

; rung 1877
LDNOT H60.03
AND 2103.02
LD 2103.02
AND P_1s
OR 2109.03
AND H60.03
ORLD
OUT 2062.04
; rung 1878
LDNOT H60.03
AND 2103.01
LD 2103.01
AND P_1s
OR 2109.02
AND H60.03
ORLD
OUT 2062.05
; rung 1879
LD T0511
OUT TR0
LD 2103.03
AND P_1s
OR 2110.09
ANDLD
OUT 2063.12
LD TR0
LD 2103.12
AND P_1s
OR 2110.10
ANDLD
OUT 2063.13
; rung 1880
LD T0511
OUT TR0
LD 407.15
AND P_1s
OR 428.15
OR 461.06
OR 403.08
ANDLD
OUT 2063.14
LD TR0
LD 407.14
AND P_1s
OR 428.14
ANDLD
OUT 2063.15
; rung 1881
LD T0511
OUT TR0
LD 407.15
OR 428.15
ANDLD
AND P_1s
OUT 2065.06
OUT 2065.07
LD TR0
LD 407.14
AND P_1s
LD 428.14
OR W293.01
ORLD
ANDLD
OUT 2065.04
OUT 2065.05

; rung 1882: --- 右成形機操作盤ﾗﾝﾌﾟ ---
LD W165.02
LD 14.14
AND P_1s
ORLD
AND T0511
OUT 2083.11
; rung 1883
LD W165.03
LD 14.15
AND P_1s
ORLD
AND T0511
OUT 2083.10
; rung 1884
LD T0511
OUT TR0
AND W224.13
OUT 2082.14
LD TR0
AND W225.01
OUT 2082.15
; rung 1885
LD T0511
OUT TR0
LD 2129.10
LD 2121.05
AND P_1s
ORLD
ANDLD
OUT 2080.02
LD TR0
LD 2129.08
LD 2121.04
AND P_1s
ORLD
ANDLD
OUT 2080.03
LD TR0
LD 2129.13
LD 2123.04
AND P_1s
ORLD
ANDLD
OUT 2080.04
LD TR0
LD 2129.11
LD 2121.06
AND P_1s
ORLD
ANDLD
OUT 2080.05
; rung 1886
LD T0511
OUT TR0
LD 429.03
AND 429.05
LD 406.12
AND P_1s
ORLD
ANDLD
OUT 2080.00
LD TR0
LD 429.04
AND 429.06
LD 406.13
AND P_1s
ORLD
ANDLD
OUT 2080.01
; rung 1887
LD T0511
OUT TR0
LD W190.12
LD 2120.10
AND P_1s
ORLD
ANDLD
OUT 2080.12
LD TR0
AND 2120.11
OUT 2080.13

; rung 1888
LD T0511
OUT TR0
LD 2129.00
AND 2129.01
LD 2120.09
AND P_1s
ORLD
ANDLD
OUT 2083.00
LD TR0
AND 2128.12
AND 2128.13
OUT 2083.01
; rung 1889
LDNOT H90.00
AND 2122.10
LD 2122.10
AND P_1s
OR 2128.01
AND H90.00
ORLD
OUT 2080.06
; rung 1890
LDNOT H90.00
AND 2122.06
LD 2122.06
AND P_1s
OR 2128.00
AND H90.00
ORLD
OUT 2080.07
; rung 1891
LDNOT H90.01
AND 2122.11
LD 2122.11
AND P_1s
OR 2128.03
AND H90.01
ORLD
OUT 2080.08
; rung 1892
LDNOT H90.01
AND 2122.07
LD 2122.07
AND P_1s
OR 2128.02
AND H90.01
ORLD
OUT 2080.09
; rung 1893
LDNOT H90.02
AND 2123.05
LD 2123.05
AND P_1s
OR 2128.05
AND H90.02
ORLD
OUT 2080.10
; rung 1894
LDNOT H90.02
AND 2122.08
LD 2122.08
AND P_1s
OR 2128.04
AND H90.02
ORLD
OUT 2080.11

; rung 1895
LDNOT H70.04
AND 2124.08
LD 2124.08
AND P_1s
OR 2129.15
AND H70.04
ORLD
OUT 2084.00
; rung 1896
LDNOT H70.04
AND 2124.04
LD 2124.04
AND P_1s
OR 2129.14
AND H70.04
ORLD
OUT 2084.01
; rung 1897
LDNOT H70.05
AND 2124.09
LD 2124.09
AND P_1s
OR 2130.04
AND H70.05
ORLD
OUT 2084.02
; rung 1898
LDNOT H70.05
AND 2124.05
LD 2124.05
AND P_1s
OR 2130.02
AND H70.05
ORLD
OUT 2084.03
; rung 1899
LDNOT H70.06
AND 2124.10
LD 2124.10
AND P_1s
OR 2130.13
AND H70.06
ORLD
OUT 2084.04
; rung 1900
LDNOT H70.06
AND 2124.06
LD 2124.06
AND P_1s
OR 2130.05
AND H70.06
ORLD
OUT 2084.05
; rung 1901
LDNOT H70.07
AND 2124.11
LD 2124.11
AND P_1s
OR 2037.13
AND H70.07
ORLD
OUT 2084.06

; rung 1902
LDNOT H70.07
AND 2124.07
LD 2124.07
AND P_1s
OR 2037.12
AND H70.07
ORLD
OUT 2084.07
; rung 1903
LDNOT H70.08
AND 2124.01
LD 2124.01
AND P_1s
OR 2129.12
AND H70.08
ORLD
OUT 2085.00
; rung 1904
LDNOT H70.08
AND 2124.00
LD 2124.00
AND P_1s
OR 2129.09
AND H70.08
ORLD
OUT 2085.01
; rung 1905
LD 22.06
AND P_1s
LDNOT H70.09
AND 2124.03
LD 2124.03
AND P_1s
OR 2036.07
AND H70.09
ORLD
AND P_Off
ORLD
OUT 2085.02
; rung 1906
LD 22.07
AND P_1s
LDNOT H70.09
AND 2124.02
LD 2124.02
AND P_1s
OR 2036.06
AND H70.09
ORLD
AND P_Off
ORLD
OUT 2085.03

; rung 1907
LD T0511
OUT TR0
AND 2121.11
OUT 2080.14
LD TR0
AND 2033.07
OUT 2080.15
LD TR0
AND 2032.09
OUT 2081.02
LD TR0
AND 2032.10
OUT 2081.04
LD TR0
AND 2032.11
OUT 2081.06
LD TR0
AND 2032.06
OUT 2081.03
LD TR0
AND 2032.07
OUT 2081.05
LD TR0
AND 2032.08
OUT 2081.07
; rung 1908
LD T0511
OUT TR0
AND 2032.12
OUT 2084.08
LD TR0
AND 2032.13
OUT 2084.10
LD TR0
AND 2032.14
OUT 2084.12
LD TR0
AND 2032.15
OUT 2084.14
LD TR0
AND 2032.00
OUT 2084.09
LD TR0
AND 2032.01
OUT 2084.11
LD TR0
AND 2032.02
OUT 2084.13
LD TR0
AND 2032.03
OUT 2084.15
; rung 1909
LD T0511
OUT TR0
LD 2032.05
AND P_Off
LD 22.04
AND P_1s
ORLD
ANDLD
OUT 2082.02
LD TR0
LD 2032.04
AND P_Off
LD 22.05
AND P_1s
ORLD
ANDLD
OUT 2082.03
LD TR0
AND P_1s
OUT TR0
AND 2123.07
OUT 2081.00
LD TR0
AND 2123.06
OUT 2081.01
; rung 1910
LDNOT H90.03
AND 2122.14
LD 2122.14
AND P_1s
OR 2128.09
AND H90.03
ORLD
OUT 2081.10

; rung 1911
LDNOT H90.03
AND 2122.13
LD 2122.13
AND P_1s
OR 2128.08
AND H90.03
ORLD
OUT 2081.11
; rung 1912
LDNOT H90.04
AND 2121.01
LD 2121.01
AND P_1s
OR 2036.01
AND H90.04
ORLD
OUT 2081.12
; rung 1913
LDNOT H90.04
AND 2120.15
LD 2120.15
AND P_1s
OR 2036.00
AND H90.04
ORLD
OUT 2081.13
; rung 1914
LDNOT H90.05
AND 2123.15
LD 2123.15
AND P_1s
OR 2130.01
AND H90.05
ORLD
OUT 2082.06
; rung 1915
LDNOT H90.05
AND 2123.14
LD 2123.14
AND P_1s
OR 2130.00
AND H90.05
ORLD
OUT 2082.07
; rung 1916
LDNOT H90.06
AND 2121.12
LD 2121.12
AND P_1s
OR 2036.03
AND H90.06
ORLD
OUT 2082.08
; rung 1917
LDNOT H90.06
AND 2121.03
LD 2121.03
AND P_1s
OR 2036.02
AND H90.06
ORLD
OUT 2082.09

; rung 1918
LDNOT H90.07
AND 2033.10
LD 2033.10
AND P_1s
OR 2128.11
AND H90.07
ORLD
OUT 2083.02
; rung 1919
LDNOT H90.07
AND 2033.09
LD 2033.09
AND P_1s
OR 2128.10
AND H90.07
ORLD
OUT 2083.03
; rung 1920
LDNOT H90.08
AND 2033.12
LD 2033.12
AND P_1s
OR 2128.15
AND H90.08
ORLD
OUT 2083.04
; rung 1921
LDNOT H90.08
AND 2033.11
LD 2033.11
AND P_1s
OR 2128.14
AND H90.08
ORLD
OUT 2083.05
; rung 1922
LDNOT H90.09
AND 2120.05
LD 2120.05
AND P_1s
OR 2037.03
AND H90.09
ORLD
OUT 2083.06
; rung 1923
LDNOT H90.09
AND 2120.04
LD 2120.04
AND P_1s
OR 2037.02
AND H90.09
ORLD
OUT 2083.07
; rung 1924
LDNOT H90.10
AND 2120.07
LD 2120.07
AND P_1s
OR 2037.05
AND H90.10
ORLD
OUT 2083.08

; rung 1925
LDNOT H90.10
AND 2120.06
LD 2120.06
AND P_1s
OR 2037.04
AND H90.10
ORLD
OUT 2083.09
; rung 1926
LDNOT H90.11
AND 2121.14
LD 2121.14
AND P_1s
OR 2036.15
AND H90.11
ORLD
OUT 2082.12
; rung 1927
LDNOT H90.11
AND 2121.13
LD 2121.13
AND P_1s
OR 2036.14
AND H90.11
ORLD
OUT 2082.13
; rung 1928
LDNOT H70.00
AND 2122.02
LD 2122.02
AND P_1s
OR 2036.05
AND H70.00
ORLD
OUT 2081.14
; rung 1929
LDNOT H70.00
AND 2122.01
LD 2122.01
AND P_1s
OR 2036.04
AND H70.00
ORLD
OUT 2081.15
; rung 1930
LDNOT H70.01
AND 2122.00
LD 2122.00
AND P_1s
OR 2037.15
AND H70.01
ORLD
OUT 2082.10
; rung 1931
LDNOT H70.01
AND 2121.15
LD 2121.15
AND P_1s
OR 2037.14
AND H70.01
ORLD
OUT 2082.11

; rung 1932
LDNOT H70.02
AND 2122.12
LD 2122.12
AND P_1s
OR 2128.07
AND H70.02
ORLD
OUT 2081.08
; rung 1933
LDNOT H70.02
AND 2122.03
LD 2122.03
AND P_1s
OR 2128.06
AND H70.02
ORLD
OUT 2081.09
; rung 1934
LDNOT H70.03
AND 2123.02
LD 2123.02
AND P_1s
OR 2129.03
AND H70.03
ORLD
OUT 2082.04
; rung 1935
LDNOT H70.03
AND 2123.01
LD 2123.01
AND P_1s
OR 2129.02
AND H70.03
ORLD
OUT 2082.05
; rung 1936
LD T0511
OUT TR0
LD 2123.03
AND P_1s
OR 2130.09
ANDLD
OUT 2083.12
LD TR0
LD 2123.12
AND P_1s
OR 2130.10
ANDLD
OUT 2083.13
; rung 1937
LD T0511
OUT TR0
LD 408.15
AND P_1s
OR 429.15
OR 461.07
OR 403.09
ANDLD
OUT 2083.14
LD TR0
LD 408.14
AND P_1s
OR 429.14
ANDLD
OUT 2083.15

; rung 1938
LD T0511
OUT TR0
LD 408.15
AND P_1s
OR 429.15
ANDLD
OUT 2085.06
OUT 2085.07
LD TR0
LD 408.14
AND P_1s
OR 429.14
OR W293.00
ANDLD
OUT 2085.04
OUT 2085.05
; rung 1939: --- ﾊﾟﾘｿﾝ取出機操作盤ﾗﾝﾌﾟ ---
LD 2054.01
LD 2046.05
AND P_1s
ORLD
OUT 2044.00
; rung 1940
LD 2054.00
LD 2046.04
AND P_1s
ORLD
OUT 2044.01
; rung 1941
LD 2054.02
LDNOT H98.14
AND P_1s
ORLD
OUT 2044.02
; rung 1942
LD 2043.04
OUT 2044.03
; rung 1943
LD 2048.09
LD 2042.14
AND P_1s
ORLD
OUT 2044.04
; rung 1944
LD 2048.08
LD 2042.15
AND P_1s
ORLD
OUT 2044.05
; rung 1945
LD 2054.00
AND 2055.07
OR W336.15
AND 15.07
ANDNOT 2055.06
OUT TR0
AND P_1s
OUT 2044.07
LD TR0
ANDNOT 2054.01
OUT W336.15

; rung 1946
LD W193.02
OR H1.05
AND P_1s
LDNOT W193.02
ANDNOT H1.05
ORLD
AND W193.05
LD W171.11
AND P_1s
ORLD
AND T0511
OUT 2044.08
; rung 1947
LD 2045.00
ANDNOT 2055.11
AND P_1s
OR 2055.11
OUT 2044.14
; rung 1948
LD 2045.01
ANDNOT 2055.12
AND P_1s
OR 2055.12
OUT 2044.15
; rung 1949
LD 15.07
OUT 2044.11
; rung 1950
LD 421.02
OUT 2044.12
; rung 1951
LD 421.04
OUT 2044.13
; rung 1952: --- 後部ｼｬｯﾀｰ4点BOX ---
LD T0511
OUT TR0
AND 12.13
OUT 15.14
LD TR0
LDNOT 12.15
OR H1.02
ANDLD
OUT 15.15
; rung 1953: ********** ドライ処理 **********
LD 16.10
OUT W193.01
; rung 1954: ********** ＮＴ画面処理プログラム **********
LD P_First_Cycle
MOV(021) #1 W400

; rung 1955
LD P_On
BIN(023) W400 D290
MLPX(076) D290 #10 W378
; rung 1956
LD W379.00
AND W378.01
ANDNOT W509.15
@MOV(021) #1 W400
; rung 1957
LD W371.15
OUT TR0
AND W371.13
@MOV(021) #50 W400
LD TR0
AND W371.12
@MOV(021) #66 W400
LD TR0
AND W371.11
@MOV(021) #55 W400
LD TR0
AND W371.08
@MOV(021) #202 W400
LD TR0
AND W371.14
@MOV(021) #320 W400
; rung 1958
LD W208.10
AND W208.11
@MOV(021) #54 W400
; rung 1959
LD W227.14
AND W227.15
@MOV(021) #25 W400
; rung 1960
LD W227.01
OR H0.13
ANDNOT W227.00
ANDNOT W445.02
OUT H0.13
OUTNOT H0.12

; rung 1961
LD W371.15
AND W59.12
@MOV(021) #21 W400
; rung 1962
LD P_On
AND>=(325) W400 #256
OUT W509.15
; rung 1963: ********** 現在時刻設定 **********
LD P_On
MLPX(076) A354 #10 W496
MOVD(083) A353 #10 D644
MOVD(083) A352 #12 D645
MOVD(083) A352 #10 D646
MOVD(083) A351 #12 D647
MOVD(083) A351 #10 D648
; rung 1964
LD W379.03
AND W378.15
ANDNOT W509.15
@MOV(021) A351 D640
@MOV(021) A352 D641
@MOV(021) A353 D642
@MOV(021) A354 D643

; rung 1965
LD W371.03
@DATE(735) D640
; rung 1966: ********** タイマー画面 ********** / NT631Cｼﾘｰｽﾞはﾀｲﾏﾓﾆﾀ値を表示出来るのでDM転送処理削除
LD T0021
OUT TR0
ANDNOT W189.03
ANDNOT W176.11
OUT W371.10
LD TR0
ANDNOT W319.03
ANDNOT W306.11
OUT W371.09
; rung 1967: ********** タイマ１モニタ タイムアップ表示処理 **********
LD T1100
OR W384.04
OUT W100.00
; rung 1968
LD W371.10
OUT TR0
LD T1101
OR W100.01
ANDLD
OUT W100.01
LD TR0
LD T1102
OR W100.02
ANDLD
OUT W100.02
LD TR0
LD T1103
OR W100.03
ANDLD
OUT W100.03
LD TR0
LD T1104
OR W100.04
ANDLD
OUT W100.04

; rung 1969
LD W371.10
OUT TR0
LD T1105
OR W100.05
ANDLD
OUT W100.05
LD TR0
LD T1106
OR W100.06
ANDLD
OUT W100.06
LD TR0
LD T1107
OR W100.07
ANDLD
OUT W100.07
LD TR0
LD T1108
OR W100.08
ANDLD
OUT W100.08
LD TR0
LD T1109
OR W100.09
ANDLD
OUT W100.09
; rung 1970
LD T1300
OR W384.04
OUT W110.00
; rung 1971
LD W371.09
OUT TR0
LD T1301
OR W110.01
ANDLD
OUT W110.01
LD TR0
LD T1302
OR W110.02
ANDLD
OUT W110.02
LD TR0
LD T1303
OR W110.03
ANDLD
OUT W110.03
LD TR0
LD T1304
OR W110.04
ANDLD
OUT W110.04

; rung 1972
LD W371.09
OUT TR0
LD T1305
OR W110.05
ANDLD
OUT W110.05
LD TR0
LD T1306
OR W110.06
ANDLD
OUT W110.06
LD TR0
LD T1307
OR W110.07
ANDLD
OUT W110.07
LD TR0
LD T1308
OR W110.08
ANDLD
OUT W110.08
LD TR0
LD T1309
OR W110.09
ANDLD
OUT W110.09
; rung 1973: ********** タイマ２モニタ タイムアップ表示処理 **********
LD W371.10
OUT TR0
LD T1110
OR W100.10
ANDLD
OUT W100.10
LD TR0
LD T1111
OR W100.11
ANDLD
OUT W100.11
LD TR0
LD T1112
OR W100.12
ANDLD
OUT W100.12
LD TR0
LD T1113
OR W100.13
ANDLD
OUT W100.13
LD TR0
LD T1114
OR W100.14
ANDLD
OUT W100.14

; rung 1974
LD W371.10
OUT TR0
LD T1115
OR W100.15
ANDLD
OUT W100.15
LD TR0
LD T1116
OR W101.00
ANDLD
OUT W101.00
LD TR0
LD T1117
OR W101.01
ANDLD
OUT W101.01
LD TR0
LD T1118
OR W101.02
ANDLD
OUT W101.02
LD TR0
LD T1119
OR W101.03
ANDLD
OUT W101.03
; rung 1975
LD W371.09
OUT TR0
LD T1310
OR W110.10
ANDLD
OUT W110.10
LD TR0
LD T1311
OR W110.11
ANDLD
OUT W110.11
LD TR0
LD T1312
OR W110.12
ANDLD
OUT W110.12
LD TR0
LD T1313
OR W110.13
ANDLD
OUT W110.13
LD TR0
LD T1314
OR W110.14
ANDLD
OUT W110.14

; rung 1976
LD W371.09
OUT TR0
LD T1315
OR W110.15
ANDLD
OUT W110.15
LD TR0
LD T1316
OR W111.00
ANDLD
OUT W111.00
LD TR0
LD T1317
OR W111.01
ANDLD
OUT W111.01
LD TR0
LD T1318
OR W111.02
ANDLD
OUT W111.02
LD TR0
LD T1319
OR W111.03
ANDLD
OUT W111.03
; rung 1977: ********** タイマ３モニタ タイムアップ表示処理 **********
LD W371.10
OUT TR0
LD T1120
OR W101.04
ANDLD
OUT W101.04
LD TR0
LD T1121
OR W101.05
ANDLD
OUT W101.05
LD TR0
LD T1122
OR W101.06
ANDLD
OUT W101.06
LD TR0
LD T1123
OR W101.07
ANDLD
OUT W101.07
LD TR0
LD T1124
OR W101.08
ANDLD
OUT W101.08

; rung 1978
LD W371.10
OUT TR0
LD T1125
OR W101.09
ANDLD
OUT W101.09
LD TR0
LD T1126
OR W101.10
ANDLD
OUT W101.10
LD TR0
LD T1127
OR W101.11
ANDLD
OUT W101.11
LD TR0
LD T1128
OR W101.12
ANDLD
OUT W101.12
LD TR0
LD T1129
OR W101.13
ANDLD
OUT W101.13
; rung 1979
LD W371.09
OUT TR0
LD T1320
OR W111.04
ANDLD
OUT W111.04
LD TR0
LD T1321
OR W111.05
ANDLD
OUT W111.05
LD TR0
LD T1322
OR W111.06
ANDLD
OUT W111.06
LD TR0
LD T1323
OR W111.07
ANDLD
OUT W111.07
LD TR0
LD T1324
OR W111.08
ANDLD
OUT W111.08

; rung 1980
LD W371.09
OUT TR0
LD T1325
OR W111.09
ANDLD
OUT W111.09
LD TR0
LD T1326
OR W111.10
ANDLD
OUT W111.10
LD TR0
LD T1327
OR W111.11
ANDLD
OUT W111.11
LD TR0
LD T1328
OR W111.12
ANDLD
OUT W111.12
LD TR0
LD T1329
OR W111.13
ANDLD
OUT W111.13
; rung 1981: ********** タイマ４モニタ タイムアップ表示処理 **********
LD W371.10
OUT TR0
LD T1130
OR W101.14
ANDLD
OUT W101.14
LD TR0
LD T1131
OR W101.15
ANDLD
OUT W101.15
LD TR0
LD T1132
OR W102.00
ANDLD
OUT W102.00
LD TR0
LD T1133
OR W102.01
ANDLD
OUT W102.01
LD TR0
LD T1134
OR W102.02
ANDLD
OUT W102.02

; rung 1982
LD W371.10
OUT TR0
LD T1135
OR W102.03
ANDLD
OUT W102.03
LD TR0
LD T1136
OR W102.04
ANDLD
OUT W102.04
LD TR0
LD T1137
OR W102.05
ANDLD
OUT W102.05
LD TR0
LD T1138
OR W102.06
ANDLD
OUT W102.06
LD TR0
LD T1139
OR W102.07
ANDLD
OUT W102.07
; rung 1983
LD W371.09
OUT TR0
LD T1330
OR W111.14
ANDLD
OUT W111.14
LD TR0
LD T1331
OR W111.15
ANDLD
OUT W111.15
LD TR0
LD T1332
OR W112.00
ANDLD
OUT W112.00
LD TR0
LD T1333
OR W112.01
ANDLD
OUT W112.01
LD TR0
LD T1334
OR W112.02
ANDLD
OUT W112.02

; rung 1984
LD W371.09
OUT TR0
LD T1335
OR W112.03
ANDLD
OUT W112.03
LD TR0
LD T1336
OR W112.04
ANDLD
OUT W112.04
LD TR0
LD T1337
OR W112.05
ANDLD
OUT W112.05
LD TR0
LD T1338
OR W112.06
ANDLD
OUT W112.06
LD TR0
LD T1339
OR W112.07
ANDLD
OUT W112.07
; rung 1985: ********** タイマ５モニタ タイムアップ表示処理 **********
LD W371.10
OUT TR0
LD T1140
OR W102.08
ANDLD
OUT W102.08
LD TR0
LD T1141
OR W102.09
ANDLD
OUT W102.09
LD TR0
LD T1142
OR W102.10
ANDLD
OUT W102.10
LD TR0
LD T1143
OR W102.11
ANDLD
OUT W102.11
LD TR0
LD T1144
OR W102.12
ANDLD
OUT W102.12

; rung 1986
LD W371.10
OUT TR0
LD T1145
OR W102.13
ANDLD
OUT W102.13
LD TR0
LD T1146
OR W102.14
ANDLD
OUT W102.14
LD TR0
LD T1147
OR W102.15
ANDLD
OUT W102.15
LD TR0
LD T1148
OR W103.00
ANDLD
OUT W103.00
LD TR0
LD T1149
OR W103.01
ANDLD
OUT W103.01
; rung 1987
LD W371.09
OUT TR0
LD T1340
OR W112.08
ANDLD
OUT W112.08
LD TR0
LD T1341
OR W112.09
ANDLD
OUT W112.09
LD TR0
LD T1342
OR W112.10
ANDLD
OUT W112.10
LD TR0
LD T1343
OR W112.11
ANDLD
OUT W112.11
LD TR0
LD T1344
OR W112.12
ANDLD
OUT W112.12

; rung 1988
LD W371.09
OUT TR0
LD T1345
OR W112.13
ANDLD
OUT W112.13
LD TR0
LD T1346
OR W112.14
ANDLD
OUT W112.14
LD TR0
LD T1347
OR W112.15
ANDLD
OUT W112.15
LD TR0
LD T1348
OR W113.00
ANDLD
OUT W113.00
LD TR0
LD T1349
OR W113.01
ANDLD
OUT W113.01
; rung 1989: ********** タイマ６モニタ タイムアップ表示処理 **********
LD W371.10
OUT TR0
LD T1150
OR W103.02
ANDLD
OUT W103.02
LD TR0
LD T1151
OR W103.03
ANDLD
OUT W103.03
LD TR0
LD T1152
OR W103.04
ANDLD
OUT W103.04
LD TR0
LD T1153
OR W103.05
ANDLD
OUT W103.05
LD TR0
LD T1154
OR W103.06
ANDLD
OUT W103.06

; rung 1990
LD W371.10
OUT TR0
LD T1155
OR W103.07
ANDLD
OUT W103.07
LD TR0
LD T1156
OR W103.08
ANDLD
OUT W103.08
LD TR0
LD T1157
OR W103.09
ANDLD
ANDNOT 2110.10
OUT W103.09
LD TR0
LD T1158
OR W103.10
ANDLD
OUT W103.10
LD TR0
LD T1159
OR W103.11
ANDLD
OUT W103.11
; rung 1991
LD W371.09
OUT TR0
LD T1350
OR W113.02
ANDLD
OUT W113.02
LD TR0
LD T1351
OR W113.03
ANDLD
OUT W113.03
LD TR0
LD T1352
OR W113.04
ANDLD
OUT W113.04
LD TR0
LD T1353
OR W113.05
ANDLD
OUT W113.05
LD TR0
LD T1354
OR W113.06
ANDLD
OUT W113.06

; rung 1992
LD W371.09
OUT TR0
LD T1355
OR W113.07
ANDLD
OUT W113.07
LD TR0
LD T1356
OR W113.08
ANDLD
OUT W113.08
LD TR0
LD T1357
OR W113.09
ANDLD
ANDNOT 2130.10
OUT W113.09
LD TR0
LD T1358
OR W113.10
ANDLD
OUT W113.10
LD TR0
LD T1359
OR W113.11
ANDLD
OUT W113.11
; rung 1993: ********** タイマ７モニタ　タイムアップ表示処理 **********
LD W371.10
OUT TR0
LD T1160
OR W103.12
ANDLD
OUT W103.12
LD TR0
LD T1161
OR W103.13
ANDLD
OUT W103.13
LD TR0
LD T1162
OR W103.14
ANDLD
OUT W103.14
LD TR0
LD T1163
OR W103.15
ANDLD
OUT W103.15
LD TR0
LD T1164
OR W104.00
ANDLD
OUT W104.00

; rung 1994
LD W371.10
OUT TR0
LD T1165
OR W104.01
ANDLD
OUT W104.01
LD TR0
LD T1166
OR W104.02
ANDLD
OUT W104.02
LD TR0
LD T1167
OR W104.03
ANDLD
OUT W104.03
LD TR0
LD T1168
OR W104.04
ANDLD
OUT W104.04
LD TR0
LD T1169
OR W104.05
ANDLD
OUT W104.05
; rung 1995
LD W371.09
OUT TR0
LD T1360
OR W113.12
ANDLD
OUT W113.12
LD TR0
LD T1361
OR W113.13
ANDLD
OUT W113.13
LD TR0
LD T1362
OR W113.14
ANDLD
OUT W113.14
LD TR0
LD T1363
OR W113.15
ANDLD
OUT W113.15
LD TR0
LD T1364
OR W114.00
ANDLD
OUT W114.00

; rung 1996
LD W371.09
OUT TR0
LD T1365
OR W114.01
ANDLD
OUT W114.01
LD TR0
LD T1366
OR W114.02
ANDLD
OUT W114.02
LD TR0
LD T1367
OR W114.03
ANDLD
OUT W114.03
LD TR0
LD T1368
OR W114.04
ANDLD
OUT W114.04
LD TR0
LD T1369
OR W114.05
ANDLD
OUT W114.05
; rung 1997: ********** タイマ８モニタ　タイムアップ表示処理 **********
LD W371.10
OUT TR0
LD T1170
OR W104.06
ANDLD
OUT W104.06
LD TR0
LD T1171
OR W104.07
ANDLD
OUT W104.07
LD TR0
LD T1172
OR W104.08
ANDLD
OUT W104.08
LD TR0
LD T1173
OR W104.09
ANDLD
OUT W104.09
LD TR0
LD T1174
OR W104.10
ANDLD
OUT W104.10

; rung 1998
LD W371.10
OUT TR0
LD T1175
OR W104.11
ANDLD
OUT W104.11
LD TR0
LD T1176
OR W104.12
ANDLD
OUT W104.12
LD TR0
LD T1177
OR W104.13
ANDLD
OUT W104.13
LD TR0
LD T1178
OR W104.14
ANDLD
OUT W104.14
LD TR0
LD T1179
OR W104.15
ANDLD
OUT W104.15
; rung 1999
LD W371.09
OUT TR0
LD T1370
OR W114.06
ANDLD
OUT W114.06
LD TR0
LD T1371
OR W114.07
ANDLD
OUT W114.07
LD TR0
LD T1372
OR W114.08
ANDLD
OUT W114.08
LD TR0
LD T1373
OR W114.09
ANDLD
OUT W114.09
LD TR0
LD T1374
OR W114.10
ANDLD
OUT W114.10

; rung 2000
LD W371.09
OUT TR0
LD T1375
OR W114.11
ANDLD
OUT W114.11
LD TR0
LD T1376
OR W114.12
ANDLD
OUT W114.12
LD TR0
LD T1377
OR W114.13
ANDLD
OUT W114.13
LD TR0
LD T1378
OR W114.14
ANDLD
OUT W114.14
LD TR0
LD T1379
OR W114.15
ANDLD
OUT W114.15
; rung 2001: ********** タイマ９モニタ　タイムアップ表示処理 **********
LD W371.10
OUT TR0
LD T1180
OR W105.00
ANDLD
OUT W105.00
LD TR0
LD T1181
OR W105.01
ANDLD
OUT W105.01
LD TR0
LD T1182
OR W105.02
ANDLD
OUT W105.02
LD TR0
LD T1183
OR W105.03
ANDLD
OUT W105.03
LD TR0
LD T1184
OR W105.04
ANDLD
OUT W105.04

; rung 2002
LD W371.10
OUT TR0
LD T1185
OR W105.05
ANDLD
OUT W105.05
LD TR0
LD T1186
OR W105.06
ANDLD
OUT W105.06
LD TR0
LD T1187
OR W105.07
ANDLD
OUT W105.07
LD TR0
LD T1188
OR W105.08
ANDLD
OUT W105.08
LD TR0
LD T1189
OR W105.09
ANDLD
OUT W105.09
; rung 2003
LD W371.09
OUT TR0
LD T1380
OR W115.00
ANDLD
OUT W115.00
LD TR0
LD T1381
OR W115.01
ANDLD
OUT W115.01
LD TR0
LD T1382
OR W115.02
ANDLD
OUT W115.02
LD TR0
LD T1383
OR W115.03
ANDLD
OUT W115.03
LD TR0
LD T1384
OR W115.04
ANDLD
OUT W115.04

; rung 2004
LD W371.09
OUT TR0
LD T1385
OR W115.05
ANDLD
OUT W115.05
LD TR0
LD T1386
OR W115.06
ANDLD
OUT W115.06
LD TR0
LD T1387
OR W115.07
ANDLD
OUT W115.07
LD TR0
LD T1388
OR W115.08
ANDLD
OUT W115.08
LD TR0
LD T1389
OR W115.09
ANDLD
OUT W115.09
; rung 2005: ********** タイマ１０モニタ　タイムアップ表示処理 **********
LD W371.10
OUT TR0
LD T1190
OR W105.10
ANDLD
OUT W105.10
LD TR0
LD T1191
OR W105.11
ANDLD
OUT W105.11
LD TR0
LD T1192
OR W105.12
ANDLD
OUT W105.12
LD TR0
LD T1193
OR W105.13
ANDLD
OUT W105.13
LD TR0
LD T1194
OR W105.14
ANDLD
OUT W105.14

; rung 2006
LD W371.10
OUT TR0
LD T1195
OR W105.15
ANDLD
OUT W105.15
LD TR0
LD T1196
OR W106.00
ANDLD
OUT W106.00
LD TR0
LD T1197
OR W106.01
ANDLD
OUT W106.01
LD TR0
LD T1198
OR W106.02
ANDLD
OUT W106.02
LD TR0
LD T1199
OR W106.03
ANDLD
OUT W106.03
; rung 2007
LD W371.09
OUT TR0
LD T1390
OR W115.10
ANDLD
OUT W115.10
LD TR0
LD T1391
OR W115.11
ANDLD
OUT W115.11
LD TR0
LD T1392
OR W115.12
ANDLD
OUT W115.12
LD TR0
LD T1393
OR W115.13
ANDLD
OUT W115.13
LD TR0
LD T1394
OR W115.14
ANDLD
OUT W115.14

; rung 2008
LD W371.09
OUT TR0
LD T1395
OR W115.15
ANDLD
OUT W115.15
LD TR0
LD T1396
OR W116.00
ANDLD
OUT W116.00
LD TR0
LD T1397
OR W116.01
ANDLD
OUT W116.01
LD TR0
LD T1398
OR W116.02
ANDLD
OUT W116.02
LD TR0
LD T1399
OR W116.03
ANDLD
OUT W116.03
; rung 2009: ********** タイマ１１モニタ　タイムアップ表示処理 **********
LD W371.10
OUT TR0
LD T1200
OR W106.04
ANDLD
OUT W106.04
LD TR0
LD T1201
OR W106.05
ANDLD
OUT W106.05
LD TR0
LD T1202
OR W106.06
ANDLD
OUT W106.06
LD TR0
LD T1203
OR W106.07
ANDLD
OUT W106.07
LD TR0
LD T1204
OR W106.08
ANDLD
OUT W106.08

; rung 2010
LD W371.10
OUT TR0
LD T1205
OR W106.09
ANDLD
OUT W106.09
LD TR0
LD T1206
OR W106.10
ANDLD
OUT W106.10
LD TR0
LD T1207
OR W106.11
ANDLD
OUT W106.11
LD TR0
LD T1208
OR W106.12
ANDLD
OUT W106.12
LD TR0
LD T1209
OR W106.13
ANDLD
OUT W106.13
; rung 2011
LD W371.09
OUT TR0
LD T1400
OR W116.04
ANDLD
OUT W116.04
LD TR0
LD T1401
OR W116.05
ANDLD
OUT W116.05
LD TR0
LD T1402
OR W116.06
ANDLD
OUT W116.06
LD TR0
LD T1403
OR W116.07
ANDLD
OUT W116.07
LD TR0
LD T1404
OR W116.08
ANDLD
OUT W116.08

; rung 2012
LD W371.09
OUT TR0
LD T1405
OR W116.09
ANDLD
OUT W116.09
LD TR0
LD T1406
OR W116.10
ANDLD
OUT W116.10
LD TR0
LD T1407
OR W116.11
ANDLD
OUT W116.11
LD TR0
LD T1408
OR W116.12
ANDLD
OUT W116.12
LD TR0
LD T1409
OR W116.13
ANDLD
OUT W116.13
; rung 2013: ********** タイマ１2モニタ　タイムアップ表示処理 **********
LD W371.10
OUT TR0
LD T1210
OR W106.14
ANDLD
OUT W106.14
LD TR0
LD T1211
OR W106.15
ANDLD
OUT W106.15
LD TR0
LD T1212
OR W107.00
ANDLD
OUT W107.00
LD TR0
LD T1213
OR W107.01
ANDLD
OUT W107.01
LD TR0
LD T1214
OR W107.02
ANDLD
OUT W107.02

; rung 2014
LD W371.10
OUT TR0
LD T1215
OR W107.03
ANDLD
OUT W107.03
LD TR0
LD T1216
OR W107.04
ANDLD
OUT W107.04
LD TR0
LD T1217
OR W107.05
ANDLD
OUT W107.05
LD TR0
LD T1218
OR W107.06
ANDLD
OUT W107.06
LD TR0
LD T1219
OR W107.07
ANDLD
OUT W107.07
; rung 2015
LD W371.09
OUT TR0
LD T1410
OR W116.14
ANDLD
OUT W116.14
LD TR0
LD T1411
OR W116.15
ANDLD
OUT W116.15
LD TR0
LD T1412
OR W117.00
ANDLD
OUT W117.00
LD TR0
LD T1413
OR W117.01
ANDLD
OUT W117.01
LD TR0
LD T1414
OR W117.02
ANDLD
OUT W117.02

; rung 2016
LD W371.09
OUT TR0
LD T1415
OR W117.03
ANDLD
OUT W117.03
LD TR0
LD T1416
OR W117.04
ANDLD
OUT W117.04
LD TR0
LD T1417
OR W117.05
ANDLD
OUT W117.05
LD TR0
LD T1418
OR W117.06
ANDLD
OUT W117.06
LD TR0
LD T1419
OR W117.07
ANDLD
OUT W117.07
; rung 2017: ********** タイマ１3モニタ　タイムアップ表示処理 **********
LD W371.10
OUT TR0
LD T1220
OR W107.08
ANDLD
OUT W107.08
LD TR0
LD T1221
OR W107.09
ANDLD
OUT W107.09
LD TR0
LD T1222
OR W107.10
ANDLD
OUT W107.10
LD TR0
LD T1223
OR W107.11
ANDLD
OUT W107.11
LD TR0
LD T1224
OR W107.12
ANDLD
OUT W107.12

; rung 2018
LD W371.10
OUT TR0
LD T1225
OR W107.13
ANDLD
OUT W107.13
LD TR0
LD T1226
OR W107.14
ANDLD
OUT W107.14
LD TR0
LD T1227
OR W107.15
ANDLD
OUT W107.15
LD TR0
LD T1228
OR W108.00
ANDLD
OUT W108.00
LD TR0
LD T1229
OR W108.01
ANDLD
OUT W108.01
; rung 2019
LD W371.09
OUT TR0
LD T1420
OR W117.08
ANDLD
OUT W117.08
LD TR0
LD T1421
OR W117.09
ANDLD
OUT W117.09
LD TR0
LD T1422
OR W117.10
ANDLD
OUT W117.10
LD TR0
LD T1423
OR W117.11
ANDLD
OUT W117.11
LD TR0
LD T1424
OR W117.12
ANDLD
OUT W117.12

; rung 2020
LD W371.09
OUT TR0
LD T1425
OR W117.13
ANDLD
OUT W117.13
LD TR0
LD T1426
OR W117.14
ANDLD
OUT W117.14
LD TR0
LD T1427
OR W117.15
ANDLD
OUT W117.15
LD TR0
LD T1428
OR W118.00
ANDLD
OUT W118.00
LD TR0
LD T1429
OR W118.01
ANDLD
OUT W118.01
; rung 2021: ********** タイマ１４モニタ タイムアップ表示処理 **********
LD W371.10
OR W371.09
OUT TR0
LD T1000
OR W109.00
ANDLD
OUT W109.00
LD TR0
LD T1001
OR W109.01
ANDLD
OUT W109.01
LD TR0
LD T1002
OR W109.02
ANDLD
OUT W109.02
LD TR0
LD T1003
OR W109.03
ANDLD
OUT W109.03
LD TR0
LD T1004
OR W109.04
ANDLD
OUT W109.04

; rung 2022
LD W371.10
OR W371.09
OUT TR0
LD T1005
OR W109.05
ANDLD
OUT W109.05
LD TR0
LD T1008
OR W109.08
ANDLD
OUT W109.08
LD TR0
LD T1009
OR W109.09
ANDLD
OUT W109.09
; rung 2023: ********** 動作選択 ********** / ***** 動作選択１選択中 *****
LDNOT W250.00
ANDNOT W250.01
ANDNOT W250.02
ANDNOT W250.03
ANDNOT W250.04
ANDNOT W250.05
ANDNOT W250.06
ANDNOT W250.07
ANDNOT W250.08
ANDNOT W250.09
ANDNOT W250.10
ANDNOT W250.11
ANDNOT W250.12
ANDNOT W250.13
ANDNOT W250.14
ANDNOT W250.15
OUTNOT W338.00
; rung 2024
LDNOT W80.00
ANDNOT W80.01
ANDNOT W80.02
ANDNOT W80.03
ANDNOT W80.04
ANDNOT W80.05
ANDNOT W80.06
ANDNOT W80.07
ANDNOT W80.08
ANDNOT W80.09
ANDNOT W80.10
ANDNOT W80.11
ANDNOT W80.12
ANDNOT W80.13
ANDNOT W80.14
ANDNOT W80.15
OUT W338.01
; rung 2025
LD W338.00
AND W338.01
OUT W337.00
; rung 2026: ***** 動作選択２選択中 *****
LDNOT W251.00
ANDNOT W251.01
ANDNOT W251.02
ANDNOT W251.03
ANDNOT W251.04
ANDNOT W251.05
ANDNOT W251.06
ANDNOT W251.07
ANDNOT W251.08
ANDNOT W251.09
ANDNOT W251.10
ANDNOT W251.11
ANDNOT W251.12
ANDNOT W251.13
ANDNOT W251.14
ANDNOT W251.15
OUTNOT W338.02
; rung 2027
LDNOT W81.00
ANDNOT W81.01
ANDNOT W81.02
ANDNOT W81.03
ANDNOT W81.04
ANDNOT W81.05
ANDNOT W81.06
ANDNOT W81.07
ANDNOT W81.08
ANDNOT W81.09
ANDNOT W81.10
ANDNOT W81.11
ANDNOT W81.12
ANDNOT W81.13
ANDNOT W81.14
ANDNOT W81.15
OUT W338.03
; rung 2028
LD W338.02
AND W338.03
OUT W337.01
; rung 2029: ***** 動作選択３選択中 *****
LDNOT W252.00
ANDNOT W252.01
ANDNOT W252.02
ANDNOT W252.03
ANDNOT W252.04
ANDNOT W252.05
ANDNOT W252.06
ANDNOT W252.07
ANDNOT W252.08
ANDNOT W252.09
ANDNOT W252.10
ANDNOT W252.11
ANDNOT W252.12
ANDNOT W252.13
ANDNOT W252.14
ANDNOT W252.15
OUTNOT W338.04
; rung 2030
LDNOT W82.00
ANDNOT W82.01
ANDNOT W82.02
ANDNOT W82.03
ANDNOT W82.04
ANDNOT W82.05
ANDNOT W82.06
ANDNOT W82.07
ANDNOT W82.08
ANDNOT W82.09
ANDNOT W82.10
ANDNOT W82.11
ANDNOT W82.12
ANDNOT W82.13
ANDNOT W82.14
ANDNOT W82.15
OUT W338.05
; rung 2031
LD W338.04
AND W338.05
OUT W337.02

; rung 2032: ***** 動作選択４選択中 *****
LDNOT W253.00
ANDNOT W253.01
ANDNOT W253.02
ANDNOT W253.03
ANDNOT W253.04
ANDNOT W253.05
ANDNOT W253.06
ANDNOT W253.07
ANDNOT W253.08
ANDNOT W253.09
ANDNOT W253.10
ANDNOT W253.11
ANDNOT W253.12
ANDNOT W253.13
ANDNOT W253.14
ANDNOT W253.15
OUTNOT W338.06
; rung 2033
LDNOT W83.00
ANDNOT W83.01
ANDNOT W83.02
ANDNOT W83.03
ANDNOT W83.04
ANDNOT W83.05
ANDNOT W83.06
ANDNOT W83.07
ANDNOT W83.08
ANDNOT W83.09
ANDNOT W83.10
ANDNOT W83.11
ANDNOT W83.12
ANDNOT W83.13
ANDNOT W83.14
ANDNOT W83.15
OUT W338.07
; rung 2034
LD W338.06
AND W338.07
OUT W337.03
; rung 2035: ***** 動作選択５選択中 *****
LDNOT W254.00
ANDNOT W254.01
ANDNOT W254.02
ANDNOT W254.03
ANDNOT W254.04
ANDNOT W254.05
ANDNOT W254.06
ANDNOT W254.07
ANDNOT W254.08
ANDNOT W254.09
ANDNOT W254.10
ANDNOT W254.11
ANDNOT W254.12
ANDNOT W254.13
ANDNOT W254.14
ANDNOT W254.15
OUTNOT W338.08
; rung 2036
LDNOT W84.00
ANDNOT W84.01
ANDNOT W84.03
ANDNOT W84.02
ANDNOT W84.04
ANDNOT W84.05
ANDNOT W84.06
ANDNOT W84.07
ANDNOT W84.08
ANDNOT W84.09
ANDNOT W84.10
ANDNOT W84.11
ANDNOT W84.12
ANDNOT W84.13
ANDNOT W84.14
ANDNOT W84.15
OUT W338.09
; rung 2037
LD W338.08
AND W338.09
OUT W337.04
; rung 2038: ***** 動作選択６選択中 *****
LDNOT W255.00
ANDNOT W255.01
ANDNOT W255.02
ANDNOT W255.03
ANDNOT W255.04
ANDNOT W255.05
ANDNOT W255.06
ANDNOT W255.07
ANDNOT W255.08
ANDNOT W255.09
ANDNOT W255.10
ANDNOT W255.11
ANDNOT W255.12
ANDNOT W255.13
ANDNOT W255.14
ANDNOT W255.15
OUTNOT W338.10
; rung 2039
LDNOT W85.00
ANDNOT W85.01
ANDNOT W85.02
ANDNOT W85.03
ANDNOT W85.04
ANDNOT W85.05
ANDNOT W85.06
ANDNOT W85.07
ANDNOT W85.08
ANDNOT W85.09
ANDNOT W85.10
ANDNOT W85.11
ANDNOT W85.12
ANDNOT W85.13
ANDNOT W85.14
ANDNOT W85.15
OUT W338.11
; rung 2040
LD W338.10
AND W338.11
OUT W337.05
; rung 2041: ***** 動作選択７選択中 *****
LDNOT W256.00
ANDNOT W256.01
ANDNOT W256.02
ANDNOT W256.03
ANDNOT W256.04
ANDNOT W256.05
ANDNOT W256.06
ANDNOT W256.07
ANDNOT W256.08
ANDNOT W256.09
ANDNOT W256.10
ANDNOT W256.11
ANDNOT W256.12
ANDNOT W256.13
ANDNOT W256.14
ANDNOT W256.15
OUTNOT W338.12
; rung 2042
LDNOT W86.00
ANDNOT W86.01
ANDNOT W86.02
ANDNOT W86.03
ANDNOT W86.04
ANDNOT W86.05
ANDNOT W86.06
ANDNOT W86.07
ANDNOT W86.08
ANDNOT W86.09
ANDNOT W86.10
ANDNOT W86.11
ANDNOT W86.12
ANDNOT W86.13
ANDNOT W86.14
ANDNOT W86.15
OUT W338.13
; rung 2043
LD W338.12
AND W338.13
OUT W337.06

; rung 2044: ***** 動作選択８選択中 *****
LDNOT W257.00
ANDNOT W257.01
ANDNOT W257.02
ANDNOT W257.03
ANDNOT W257.04
ANDNOT W257.05
ANDNOT W257.06
ANDNOT W257.07
ANDNOT W257.08
ANDNOT W257.09
ANDNOT W257.10
ANDNOT W257.11
ANDNOT W257.12
ANDNOT W257.13
ANDNOT W257.14
ANDNOT W257.15
OUTNOT W338.14
; rung 2045
LDNOT W87.00
ANDNOT W87.01
ANDNOT W87.02
ANDNOT W87.03
ANDNOT W87.04
ANDNOT W87.05
ANDNOT W87.06
ANDNOT W87.07
ANDNOT W87.08
ANDNOT W87.09
ANDNOT W87.10
ANDNOT W87.11
ANDNOT W87.12
ANDNOT W87.13
ANDNOT W87.14
ANDNOT W87.15
OUT W338.15
; rung 2046
LD W338.14
AND W338.15
OUT W337.07
; rung 2047: ***** 動作選択９選択中 *****
LDNOT W258.00
ANDNOT W258.01
ANDNOT W258.02
ANDNOT W258.03
ANDNOT W258.04
ANDNOT W258.05
ANDNOT W258.06
ANDNOT W258.07
ANDNOT W258.08
ANDNOT W258.09
ANDNOT W258.10
ANDNOT W258.11
ANDNOT W258.12
ANDNOT W258.13
ANDNOT W258.14
ANDNOT W258.15
OUTNOT W339.00
; rung 2048
LDNOT W88.00
ANDNOT W88.01
ANDNOT W88.02
ANDNOT W88.03
ANDNOT W88.04
ANDNOT W88.05
ANDNOT W88.06
ANDNOT W88.07
ANDNOT W88.08
ANDNOT W88.09
ANDNOT W88.10
ANDNOT W88.11
ANDNOT W88.12
ANDNOT W88.13
ANDNOT W88.14
ANDNOT W88.15
OUT W339.01
; rung 2049
LD W339.00
AND W339.01
OUT W337.08
; rung 2050: ***** 動作選択10選択中 *****
LDNOT W259.00
ANDNOT W259.01
ANDNOT W259.02
ANDNOT W259.03
ANDNOT W259.04
ANDNOT W259.05
ANDNOT W259.06
ANDNOT W259.07
ANDNOT W259.08
ANDNOT W259.09
ANDNOT W259.10
ANDNOT W259.11
ANDNOT W259.12
ANDNOT W259.13
ANDNOT W259.14
ANDNOT W259.15
OUTNOT W339.02
; rung 2051
LDNOT W89.00
ANDNOT W89.01
ANDNOT W89.02
ANDNOT W89.03
ANDNOT W89.04
ANDNOT W89.05
ANDNOT W89.06
ANDNOT W89.07
ANDNOT W89.08
ANDNOT W89.09
ANDNOT W89.10
ANDNOT W89.11
ANDNOT W89.12
ANDNOT W89.13
ANDNOT W89.14
ANDNOT W89.15
OUT W339.03
; rung 2052
LD W339.02
AND W339.03
OUT W337.09
; rung 2053: ***** 動作選択11選択中 *****
LDNOT W260.00
ANDNOT W260.01
ANDNOT W260.02
ANDNOT W260.03
ANDNOT W260.04
ANDNOT W260.05
ANDNOT W260.06
ANDNOT W260.07
ANDNOT W260.08
ANDNOT W260.09
ANDNOT W260.10
ANDNOT W260.11
ANDNOT W260.12
ANDNOT W260.13
ANDNOT W260.14
ANDNOT W260.15
OUTNOT W339.04
; rung 2054
LDNOT W90.00
ANDNOT W90.01
ANDNOT W90.02
ANDNOT W90.03
ANDNOT W90.04
ANDNOT W90.05
ANDNOT W90.06
ANDNOT W90.07
ANDNOT W90.08
ANDNOT W90.09
ANDNOT W90.10
ANDNOT W90.11
ANDNOT W90.12
ANDNOT W90.13
ANDNOT W90.14
ANDNOT W90.15
OUT W339.05
; rung 2055
LD W339.04
AND W339.05
OUT W337.10

; rung 2056: ***** 動作選択12選択中 *****
LDNOT W261.00
ANDNOT W261.01
ANDNOT W261.02
ANDNOT W261.03
ANDNOT W261.04
ANDNOT W261.05
ANDNOT W261.06
ANDNOT W261.07
ANDNOT W261.08
ANDNOT W261.09
ANDNOT W261.10
ANDNOT W261.11
ANDNOT W261.12
ANDNOT W261.13
ANDNOT W261.14
ANDNOT W261.15
OUTNOT W339.06
; rung 2057
LDNOT W91.00
ANDNOT W91.01
ANDNOT W91.02
ANDNOT W91.03
ANDNOT W91.04
ANDNOT W91.05
ANDNOT W91.06
ANDNOT W91.07
ANDNOT W91.08
ANDNOT W91.09
ANDNOT W91.10
ANDNOT W91.11
ANDNOT W91.12
ANDNOT W91.13
ANDNOT W91.14
ANDNOT W91.15
OUT W339.07
; rung 2058
LD W339.06
AND W339.07
OUT W337.11
; rung 2059: ***** 動作選択13選択中 *****
LDNOT W262.00
ANDNOT W262.01
ANDNOT W262.02
ANDNOT W262.03
ANDNOT W262.04
ANDNOT W262.05
ANDNOT W262.06
ANDNOT W262.07
ANDNOT W262.08
ANDNOT W262.09
ANDNOT W262.10
ANDNOT W262.11
ANDNOT W262.12
ANDNOT W262.13
ANDNOT W262.14
ANDNOT W262.15
OUTNOT W339.08
; rung 2060
LDNOT W92.00
ANDNOT W92.01
ANDNOT W92.02
ANDNOT W92.03
ANDNOT W92.04
ANDNOT W92.05
ANDNOT W92.06
ANDNOT W92.07
ANDNOT W92.08
ANDNOT W92.09
ANDNOT W92.10
ANDNOT W92.11
ANDNOT W92.12
ANDNOT W92.13
ANDNOT W92.14
ANDNOT W92.15
OUT W339.09
; rung 2061
LD W339.08
AND W339.09
OUT W337.12
; rung 2062: ***** 動作選択14選択中 *****
LDNOT W263.00
ANDNOT W263.01
ANDNOT W263.02
ANDNOT W263.03
ANDNOT W263.04
ANDNOT W263.05
ANDNOT W263.06
ANDNOT W263.07
ANDNOT W263.08
ANDNOT W263.09
ANDNOT W263.10
ANDNOT W263.11
ANDNOT W263.12
ANDNOT W263.13
ANDNOT W263.14
ANDNOT W263.15
OUTNOT W339.10
; rung 2063
LDNOT W93.00
ANDNOT W93.01
ANDNOT W93.02
ANDNOT W93.03
ANDNOT W93.04
ANDNOT W93.05
ANDNOT W93.06
ANDNOT W93.07
ANDNOT W93.08
ANDNOT W93.09
ANDNOT W93.10
ANDNOT W93.11
ANDNOT W93.12
ANDNOT W93.13
ANDNOT W93.14
ANDNOT W93.15
OUT W339.11
; rung 2064
LD W339.10
AND W339.11
OUT W337.13
; rung 2065
LDNOT W337.00
ANDNOT W337.01
ANDNOT W337.02
ANDNOT W337.03
ANDNOT W337.04
ANDNOT W337.05
ANDNOT W337.06
ANDNOT W337.07
ANDNOT W337.08
ANDNOT W337.09
ANDNOT W337.10
ANDNOT W337.11
ANDNOT W337.12
ANDNOT W337.13
OUTNOT W337.15
; rung 2066
LD W337.15
TIM 0039 #100

; rung 2067: ***** 動作選択１選択 *****
LD W379.02
AND W378.00
LD W378.13
OR W378.11
AND W379.01
ORLD
ANDNOT W509.15
OUT W375.00
; rung 2068
LD W375.00
OUT TR0
LD W80.01
OR W250.01
ANDLD
ANDNOT H1.00
ANDNOT T0039
ANDNOT W250.00
ANDNOT W80.00
OUT W250.01
LD TR0
LD W250.01
AND P_0_2s
OR H1.00
ANDLD
OUT W120.01
LD TR0
LD W80.00
OR W250.00
ANDLD
AND H1.00
ANDNOT T0039
ANDNOT W250.01
ANDNOT W80.01
OUT W250.00
LD TR0
LD W250.00
AND P_0_2s
ORNOT H1.00
ANDLD
OUT W120.00
; rung 2069
LD W250.01
AND W374.15
OR H1.00
LDNOT W250.00
ORNOT W374.15
ANDLD
OUT H1.00
; rung 2070
LD W375.00
OUT TR0
LD W80.03
OR W250.03
ANDLD
ANDNOT H1.01
ANDNOT T0039
ANDNOT W250.02
ANDNOT W80.02
OUT W250.03
LD TR0
LD W250.03
ANDNOT P_0_2s
OR H1.01
ANDLD
OUT W120.03
LD TR0
LD W80.02
OR W250.02
ANDLD
AND H1.01
ANDNOT T0039
ANDNOT W250.03
ANDNOT W80.03
OUT W250.02
LD TR0
LD W250.02
AND P_0_2s
ORNOT H1.01
ANDLD
OUT W120.02
; rung 2071
LD W250.03
AND W374.15
OR H1.01
LDNOT W250.02
ORNOT W374.15
ANDLD
OUT H1.01

; rung 2072
LD W375.00
OUT TR0
LD W80.05
OR W250.05
ANDLD
ANDNOT H1.02
ANDNOT T0039
ANDNOT W250.04
ANDNOT W80.04
OUT W250.05
LD TR0
LD W250.05
AND P_0_2s
OR H1.02
ANDLD
OUT W120.05
LD TR0
LD W80.04
OR W250.04
ANDLD
AND H1.02
ANDNOT T0039
ANDNOT W250.05
ANDNOT W80.05
OUT W250.04
LD TR0
LD W250.04
AND P_0_2s
ORNOT H1.02
ANDLD
OUT W120.04
; rung 2073
LD W250.05
AND W374.15
OR H1.02
LDNOT W250.04
ORNOT W374.15
ANDLD
OUT H1.02
; rung 2074
LD W375.00
OUT TR0
LD W80.07
OR W250.07
ANDLD
ANDNOT H1.03
ANDNOT T0039
ANDNOT W250.06
ANDNOT W80.06
OUT W250.07
LD TR0
LD W250.07
AND P_0_2s
OR H1.03
ANDLD
OUT W120.07
LD TR0
LD W80.06
OR W250.06
ANDLD
AND H1.03
ANDNOT T0039
ANDNOT W250.07
ANDNOT W80.07
OUT W250.06
LD TR0
LD W250.06
AND P_0_2s
ORNOT H1.03
ANDLD
OUT W120.06
; rung 2075
LD W250.07
AND W374.15
OR H1.03
LDNOT W250.06
ORNOT W374.15
ANDLD
OUT H1.03

; rung 2076
LD W375.00
ANDNOT H1.00
OUT TR0
LD W80.09
OR W250.09
ANDLD
ANDNOT H1.04
ANDNOT T0039
ANDNOT W250.08
ANDNOT W80.08
OUT W250.09
LD TR0
LD W250.09
AND P_0_2s
OR H1.04
ANDLD
OUT W120.09
LD TR0
LD W80.08
OR W250.08
ANDLD
AND H1.04
ANDNOT T0039
ANDNOT W250.09
ANDNOT W80.09
OUT W250.08
LD TR0
LD W250.08
AND P_0_2s
ORNOT H1.04
ANDLD
OUT W120.08
; rung 2077
LD W250.09
AND W374.15
OR H1.04
LDNOT W250.08
ORNOT W374.15
ANDLD
ANDNOT H1.00
OUT H1.04
; rung 2078
LD W375.00
OUT TR0
LD W170.09
AND W80.10
AND W80.11
OR W250.11
ANDLD
ANDNOT H1.05
ANDNOT T0039
ANDNOT W250.10
OUT W250.11
LD TR0
LD W250.11
AND P_0_2s
OR H1.05
ANDLD
OUT W120.11
LD TR0
LD W80.10
OR W250.10
ANDLD
AND H1.05
ANDNOT T0039
ANDNOT W250.11
ANDNOT W80.11
OUT W250.10
LD TR0
LD W250.10
AND P_0_2s
ORNOT H1.05
ANDLD
OUT W120.10
; rung 2079
LD W250.11
AND W374.15
LD W170.09
AND H1.05
ANDNOT H1.00
ORLD
LDNOT W250.10
ORNOT W374.15
ANDLD
OUT H1.05

; rung 2080
LD W375.00
OUT TR0
LD 16.10
AND W80.12
AND W80.13
OR W250.13
ANDLD
ANDNOT H1.06
ANDNOT T0039
ANDNOT W250.12
OUT W250.13
LD TR0
LD W250.13
AND P_0_2s
OR H1.06
ANDLD
OUT W120.13
LD TR0
LD W80.12
OR W250.12
ANDLD
AND H1.06
ANDNOT T0039
ANDNOT W250.13
ANDNOT W80.13
OUT W250.12
LD TR0
LD W250.12
AND P_0_2s
ORNOT H1.06
ANDLD
OUT W120.12
; rung 2081
LD W250.13
AND W374.15
LD H1.06
AND 16.10
ORLD
LDNOT W250.12
ORNOT W374.15
ANDLD
OUT H1.06
; rung 2082
LD W375.00
OUT TR0
LD W80.15
OR W250.15
ANDLD
ANDNOT H1.07
ANDNOT T0039
ANDNOT W250.14
ANDNOT W80.14
OUT W250.15
LD TR0
LD W250.15
AND P_0_2s
OR H1.07
ANDLD
OUT W120.15
LD TR0
LD W80.14
OR W250.14
ANDLD
AND H1.07
ANDNOT T0039
ANDNOT W250.15
ANDNOT W80.15
OUT W250.14
LD TR0
LD W250.14
AND P_0_2s
ORNOT H1.07
ANDLD
OUT W120.14
; rung 2083
LD W250.15
AND W374.15
OR H1.07
LDNOT W250.14
ORNOT W374.15
ANDLD
OUT H1.07
; rung 2084: ***** 動作選択２ *****
LD W379.02
AND W378.01
LD W378.13
OR W378.11
AND W379.01
ORLD
ANDNOT W509.15
OUT W375.01

; rung 2085
LD W375.01
OUT TR0
LD W81.01
OR W251.01
ANDLD
ANDNOT H1.08
ANDNOT T0039
ANDNOT W251.00
ANDNOT W81.00
OUT W251.01
LD TR0
LD W251.01
AND P_0_2s
OR H1.08
ANDLD
OUT W121.01
LD TR0
LD W81.00
OR W251.00
ANDLD
AND H1.08
ANDNOT T0039
ANDNOT W251.01
ANDNOT W81.01
OUT W251.00
LD TR0
LD W251.00
AND P_0_2s
ORNOT H1.08
ANDLD
OUT W121.00
; rung 2086
LD W251.01
AND W374.15
OR H1.08
LDNOT W251.00
ORNOT W374.15
ANDLD
OUT H1.08
; rung 2087
LD W375.01
OUT TR0
LD W81.03
OR W251.03
ANDLD
ANDNOT H1.09
ANDNOT T0039
ANDNOT W251.02
ANDNOT W81.02
OUT W251.03
LD TR0
LD W251.03
AND P_0_2s
OR H1.09
ANDLD
OUT W121.03
LD TR0
LD W81.02
OR W251.02
ANDLD
AND H1.09
ANDNOT T0039
ANDNOT W251.03
ANDNOT W81.03
OUT W251.02
LD TR0
LD W251.02
AND P_0_2s
ORNOT H1.09
ANDLD
OUT W121.02
; rung 2088
LD W251.03
AND W374.15
OR H1.09
LDNOT W251.02
ORNOT W374.15
ANDLD
OUT H1.09

; rung 2089
LD W375.01
OUT TR0
LD W81.05
OR W251.05
ANDLD
ANDNOT H1.10
ANDNOT T0039
ANDNOT W251.04
ANDNOT W81.04
OUT W251.05
LD TR0
LD W251.05
AND P_0_2s
OR H1.10
ANDLD
OUT W121.05
LD TR0
LD W81.04
OR W251.04
ANDLD
AND H1.10
ANDNOT T0039
ANDNOT W251.05
ANDNOT W81.05
OUT W251.04
LD TR0
LD W251.04
AND P_0_2s
ORNOT H1.10
ANDLD
OUT W121.04
; rung 2090
LD W251.05
AND W374.15
OR H1.10
LDNOT W251.04
ORNOT W374.15
ANDLD
OUT H1.10
; rung 2091
LD W375.01
OUT TR0
LD W81.07
OR W251.07
ANDLD
ANDNOT H1.11
ANDNOT T0039
ANDNOT W251.06
ANDNOT W81.06
OUT W251.07
LD TR0
LD W251.07
AND P_0_2s
OR H1.11
ANDLD
OUT W121.07
LD TR0
LD W81.06
OR W251.06
ANDLD
AND H1.11
ANDNOT T0039
ANDNOT W251.07
ANDNOT W81.07
OUT W251.06
LD TR0
LD W251.06
AND P_0_2s
ORNOT H1.11
ANDLD
OUT W121.06
; rung 2092
LD W251.07
AND W374.15
OR H1.11
LDNOT W251.06
ORNOT W374.15
ANDLD
OUT H1.11

; rung 2093
LD W375.01
OUT TR0
LD W81.09
OR W251.09
ANDLD
ANDNOT H1.12
ANDNOT T0039
ANDNOT W251.08
ANDNOT W81.08
OUT W251.09
LD TR0
LD W251.09
AND P_0_2s
OR H1.12
ANDLD
OUT W121.09
LD TR0
LD W81.08
OR W251.08
ANDLD
AND H1.12
ANDNOT T0039
ANDNOT W251.09
ANDNOT W81.09
OUT W251.08
LD TR0
LD W251.08
AND P_0_2s
ORNOT H1.12
ANDLD
OUT W121.08
; rung 2094
LD W251.09
AND W374.15
OR H1.12
LDNOT W251.08
ORNOT W374.15
ANDLD
OUT H1.12
; rung 2095
LD W375.01
OUT TR0
LD W81.11
OR W251.11
ANDLD
ANDNOT H1.13
ANDNOT T0039
ANDNOT W251.10
ANDNOT W81.10
OUT W251.11
LD TR0
LD W251.11
AND P_0_2s
OR H1.13
ANDLD
OUT W121.11
LD TR0
LD W81.10
OR W251.10
ANDLD
AND H1.13
ANDNOT T0039
ANDNOT W251.11
ANDNOT W81.11
OUT W251.10
LD TR0
LD W251.10
AND P_0_2s
ORNOT H1.13
ANDLD
OUT W121.10
; rung 2096
LD W251.11
AND W374.15
OR H1.13
LDNOT W251.10
ORNOT W374.15
ANDLD
OUT H1.13

; rung 2097
LD W375.01
OUT TR0
LD W81.13
OR W251.13
ANDLD
ANDNOT H1.14
ANDNOT T0039
ANDNOT W251.12
ANDNOT W81.12
OUT W251.13
LD TR0
LD W251.13
AND P_0_2s
OR H1.14
ANDLD
OUT W121.13
LD TR0
LD W81.12
OR W251.12
ANDLD
AND H1.14
ANDNOT T0039
ANDNOT W251.13
ANDNOT W81.13
OUT W251.12
LD TR0
LD W251.12
AND P_0_2s
ORNOT H1.14
ANDLD
OUT W121.12
; rung 2098
LD W251.13
AND W374.15
OR H1.14
LDNOT W251.12
ORNOT W374.15
ANDLD
OUT H1.14
; rung 2099
LD W375.01
OUT TR0
LD W81.15
OR W251.15
ANDLD
ANDNOT H1.15
ANDNOT T0039
ANDNOT W251.14
ANDNOT W81.14
OUT W251.15
LD TR0
LD W251.15
AND P_0_2s
OR H1.15
ANDLD
OUT W121.15
LD TR0
LD W81.14
OR W251.14
ANDLD
AND H1.15
ANDNOT T0039
ANDNOT W251.15
ANDNOT W81.15
OUT W251.14
LD TR0
LD W251.14
AND P_0_2s
ORNOT H1.15
ANDLD
OUT W121.14
; rung 2100
LD W251.15
AND W374.15
OR H1.15
LDNOT W251.14
ORNOT W374.15
ANDLD
OUT H1.15
; rung 2101: ***** 動作選択３ *****
LD W379.02
AND W378.02
LD W378.13
OR W378.11
AND W379.01
ORLD
ANDNOT W509.15
OUT W375.02

; rung 2102
LD W375.02
OUT TR0
LD W82.01
OR W252.01
ANDLD
ANDNOT H2.00
ANDNOT T0039
ANDNOT W252.00
ANDNOT W82.00
OUT W252.01
LD TR0
LD W252.01
AND P_0_2s
OR H2.00
ANDLD
OUT W122.01
LD TR0
LD W82.00
OR W252.00
ANDLD
AND H2.00
ANDNOT T0039
ANDNOT W252.01
ANDNOT W82.01
OUT W252.00
LD TR0
LD W252.00
AND P_0_2s
ORNOT H2.00
ANDLD
OUT W122.00
; rung 2103
LD W252.01
AND W374.15
OR H2.00
LDNOT W252.00
ORNOT W374.15
ANDLD
OUT H2.00
; rung 2104
LD W375.02
OUT TR0
LD W82.03
OR W252.03
ANDLD
ANDNOT H2.01
ANDNOT T0039
ANDNOT W252.02
ANDNOT W82.02
OUT W252.03
LD TR0
LD W252.03
AND P_0_2s
OR H2.01
ANDLD
OUT W122.03
LD TR0
LD W82.02
OR W252.02
ANDLD
AND H2.01
ANDNOT T0039
ANDNOT W252.03
ANDNOT W82.03
OUT W252.02
LD TR0
LD W252.02
AND P_0_2s
ORNOT H2.01
ANDLD
OUT W122.02
; rung 2105
LD W252.03
AND W374.15
OR H2.01
LDNOT W252.02
ORNOT W374.15
ANDLD
OUT H2.01

; rung 2106
LD W375.02
OUT TR0
LD W82.05
OR W252.05
ANDLD
ANDNOT H2.02
ANDNOT T0039
ANDNOT W252.04
ANDNOT W82.04
OUT W252.05
LD TR0
LD W252.05
AND P_0_2s
OR H2.02
ANDLD
OUT W122.05
LD TR0
LD W82.04
OR W252.04
ANDLD
AND H2.02
ANDNOT T0039
ANDNOT W252.05
ANDNOT W82.05
OUT W252.04
LD TR0
LD W252.04
AND P_0_2s
ORNOT H2.02
ANDLD
OUT W122.04
; rung 2107
LD W252.05
AND W374.15
OR H2.02
LDNOT W252.04
ORNOT W374.15
ANDLD
OUT H2.02
; rung 2108
LD W375.02
OUT TR0
LD W82.07
OR W252.07
ANDLD
ANDNOT H2.03
ANDNOT T0039
ANDNOT W252.06
ANDNOT W82.06
OUT W252.07
LD TR0
LD W252.07
AND P_0_2s
OR H2.03
ANDLD
OUT W122.07
LD TR0
LD W82.06
OR W252.06
ANDLD
AND H2.03
ANDNOT T0039
ANDNOT W252.07
ANDNOT W82.07
OUT W252.06
LD TR0
LD W252.06
AND P_0_2s
ORNOT H2.03
ANDLD
OUT W122.06
; rung 2109
LD W252.07
AND W374.15
OR H2.03
LDNOT W252.06
ORNOT W374.15
ANDLD
OUT H2.03

; rung 2110
LD W375.02
OUT TR0
LD W82.09
OR W252.09
ANDLD
ANDNOT H2.04
ANDNOT T0039
ANDNOT W252.08
ANDNOT W82.08
OUT W252.09
LD TR0
LD W252.09
AND P_0_2s
OR H2.04
ANDLD
OUT W122.09
LD TR0
LD W82.08
OR W252.08
ANDLD
AND H2.04
ANDNOT T0039
ANDNOT W252.09
ANDNOT W82.09
OUT W252.08
LD TR0
LD W252.08
AND P_0_2s
ORNOT H2.04
ANDLD
OUT W122.08
; rung 2111
LD W252.09
AND W374.15
OR H2.04
LDNOT W252.08
ORNOT W374.15
ANDLD
OUT H2.04
; rung 2112
LD W375.02
OUT TR0
LD W82.11
OR W252.11
ANDLD
ANDNOT H2.05
ANDNOT T0039
ANDNOT W252.10
ANDNOT W82.10
OUT W252.11
LD TR0
LD W252.11
AND P_0_2s
OR H2.05
ANDLD
OUT W122.11
LD TR0
LD W82.10
OR W252.10
ANDLD
AND H2.05
ANDNOT T0039
ANDNOT W252.11
ANDNOT W82.11
OUT W252.10
LD TR0
LD W252.10
AND P_0_2s
ORNOT H2.05
ANDLD
OUT W122.10
; rung 2113
LD W252.11
AND W374.15
OR H2.05
LDNOT W252.10
ORNOT W374.15
ANDLD
OUT H2.05

; rung 2114
LD W375.02
OUT TR0
LD W82.13
OR W252.13
ANDLD
ANDNOT H2.06
ANDNOT T0039
ANDNOT W252.12
ANDNOT W82.12
OUT W252.13
LD TR0
LD W252.13
AND P_0_2s
OR H2.06
ANDLD
OUT W122.13
LD TR0
LD W82.12
OR W252.12
ANDLD
AND H2.06
ANDNOT T0039
ANDNOT W252.13
ANDNOT W82.13
OUT W252.12
LD TR0
LD W252.12
AND P_0_2s
ORNOT H2.06
ANDLD
OUT W122.12
; rung 2115
LD W252.13
AND W374.15
OR H2.06
LDNOT W252.12
ORNOT W374.15
ANDLD
OUT H2.06
; rung 2116
LD W375.02
OUT TR0
LD W82.15
OR W252.15
ANDLD
ANDNOT H2.07
ANDNOT T0039
ANDNOT W252.14
ANDNOT W82.14
OUT W252.15
LD TR0
LD W252.15
AND P_0_2s
OR H2.07
ANDLD
OUT W122.15
LD TR0
LD W82.14
OR W252.14
ANDLD
AND H2.07
ANDNOT T0039
ANDNOT W252.15
ANDNOT W82.15
OUT W252.14
LD TR0
LD W252.14
AND P_0_2s
ORNOT H2.07
ANDLD
OUT W122.14
; rung 2117
LD W252.15
AND W374.15
OR H2.07
LDNOT W252.14
ORNOT W374.15
ANDLD
OUT H2.07
; rung 2118: ***** 動作選択４ *****
LD W379.02
AND W378.03
LD W378.13
OR W378.11
AND W379.01
ORLD
ANDNOT W509.15
OUT W375.03

; rung 2119
LD W375.03
OUT TR0
LD W83.01
OR W253.01
ANDLD
ANDNOT H2.08
ANDNOT T0039
ANDNOT W253.00
ANDNOT W83.00
OUT W253.01
LD TR0
LD W253.01
AND P_0_2s
OR H2.08
ANDLD
OUT W123.01
LD TR0
LD W83.00
OR W253.00
ANDLD
AND H2.08
ANDNOT T0039
ANDNOT W253.01
ANDNOT W83.01
OUT W253.00
LD TR0
LD W253.00
AND P_0_2s
ORNOT H2.08
ANDLD
OUT W123.00
; rung 2120
LD W253.01
AND W374.15
OR H2.08
LDNOT W253.00
ORNOT W374.15
ANDLD
OUT H2.08
; rung 2121
LD W375.03
OUT TR0
LD W83.03
OR W253.03
ANDLD
ANDNOT H2.09
ANDNOT T0039
ANDNOT W253.02
ANDNOT W83.02
OUT W253.03
LD TR0
LD W253.03
AND P_0_2s
OR H2.09
ANDLD
OUT W123.03
LD TR0
LD W83.02
OR W253.02
ANDLD
AND H2.09
ANDNOT T0039
ANDNOT W253.03
ANDNOT W83.03
OUT W253.02
LD TR0
LD W253.02
AND P_0_2s
ORNOT H2.09
ANDLD
OUT W123.02
; rung 2122
LD W253.03
AND W374.15
OR H2.09
LDNOT W253.02
ORNOT W374.15
ANDLD
OUT H2.09

; rung 2123
LD W375.03
OUT TR0
LD W83.05
OR W253.05
ANDLD
ANDNOT H2.10
ANDNOT T0039
ANDNOT W253.04
ANDNOT W83.04
OUT W253.05
LD TR0
LD W253.05
AND P_0_2s
OR H2.10
ANDLD
OUT W123.05
LD TR0
LD W83.04
OR W253.04
ANDLD
AND H2.10
ANDNOT T0039
ANDNOT W253.05
ANDNOT W83.05
OUT W253.04
LD TR0
LD W253.04
AND P_0_2s
ORNOT H2.10
ANDLD
OUT W123.04
; rung 2124
LD W253.05
AND W374.15
OR H2.10
LDNOT W253.04
ORNOT W374.15
ANDLD
OUT H2.10
; rung 2125
LD W375.03
OUT TR0
LD W83.07
OR W253.07
ANDLD
ANDNOT H2.11
ANDNOT T0039
ANDNOT W253.06
ANDNOT W83.06
OUT W253.07
LD TR0
LD W253.07
AND P_0_2s
OR H2.11
ANDLD
OUT W123.07
LD TR0
LD W83.06
OR W253.06
ANDLD
AND H2.11
ANDNOT T0039
ANDNOT W253.07
ANDNOT W83.07
OUT W253.06
LD TR0
LD W253.06
AND P_0_2s
ORNOT H2.11
ANDLD
OUT W123.06
; rung 2126
LD W253.07
AND W374.15
OR H2.11
LDNOT W253.06
ORNOT W374.15
ANDLD
OUT H2.11

; rung 2127
LD W375.03
OUT TR0
LD W83.09
OR W253.09
ANDLD
ANDNOT H2.12
ANDNOT T0039
ANDNOT W253.08
ANDNOT W83.08
OUT W253.09
LD TR0
LD W253.09
AND P_0_2s
OR H2.12
ANDLD
OUT W123.09
LD TR0
LD W83.08
OR W253.08
ANDLD
AND H2.12
ANDNOT T0039
ANDNOT W253.09
ANDNOT W83.09
OUT W253.08
LD TR0
LD W253.08
AND P_0_2s
ORNOT H2.12
ANDLD
OUT W123.08
; rung 2128
LD W253.09
AND W374.15
OR H2.12
LDNOT W253.08
ORNOT W374.15
ANDLD
OUT H2.12
; rung 2129
LD W375.03
OUT TR0
LD W83.11
OR W253.11
ANDLD
ANDNOT H2.13
ANDNOT T0039
ANDNOT W253.10
ANDNOT W83.10
OUT W253.11
LD TR0
LD W253.11
AND P_0_2s
OR H2.13
ANDLD
OUT W123.11
LD TR0
LD W83.10
OR W253.10
ANDLD
AND H2.13
ANDNOT T0039
ANDNOT W253.11
ANDNOT W83.11
OUT W253.10
LD TR0
LD W253.10
AND P_0_2s
ORNOT H2.13
ANDLD
OUT W123.10
; rung 2130
LD W253.11
AND W374.15
OR H2.13
LDNOT W253.10
ORNOT W374.15
ANDLD
OUT H2.13

; rung 2131
LD W375.03
OUT TR0
LD W83.13
OR W253.13
ANDLD
ANDNOT H2.14
ANDNOT T0039
ANDNOT W253.12
ANDNOT W83.12
OUT W253.13
LD TR0
LD W253.13
AND P_0_2s
OR H2.14
ANDLD
OUT W123.13
LD TR0
LD W83.12
OR W253.12
ANDLD
AND H2.14
ANDNOT T0039
ANDNOT W253.13
ANDNOT W83.13
OUT W253.12
LD TR0
LD W253.12
AND P_0_2s
ORNOT H2.14
ANDLD
OUT W123.12
; rung 2132
LD W253.13
AND W374.15
OR H2.14
LDNOT W253.12
ORNOT W374.15
ANDLD
OUT H2.14
; rung 2133
LD W375.03
OUT TR0
LD W83.15
OR W253.15
ANDLD
ANDNOT H2.15
ANDNOT T0039
ANDNOT W253.14
ANDNOT W83.14
OUT W253.15
LD TR0
LD W253.15
AND P_0_2s
OR H2.15
ANDLD
OUT W123.15
LD TR0
LD W83.14
OR W253.14
ANDLD
AND H2.15
ANDNOT T0039
ANDNOT W253.15
ANDNOT W83.15
OUT W253.14
LD TR0
LD W253.14
AND P_0_2s
ORNOT H2.15
ANDLD
OUT W123.14
; rung 2134
LD W253.15
AND W374.15
OR H2.15
LDNOT W253.14
ORNOT W374.15
ANDLD
OUT H2.15
; rung 2135: ***** 動作選択５ *****
LD W379.02
AND W378.04
LD W378.13
OR W378.11
AND W379.01
ORLD
ANDNOT W509.15
OUT W375.04

; rung 2136
LD W375.04
OUT TR0
LD W84.01
OR W254.01
ANDLD
ANDNOT H3.00
ANDNOT T0039
ANDNOT W254.00
ANDNOT W84.00
OUT W254.01
LD TR0
LD W254.01
AND P_0_2s
OR H3.00
ANDLD
OUT W124.01
LD TR0
LD W84.00
OR W254.00
ANDLD
AND H3.00
ANDNOT T0039
ANDNOT W254.01
ANDNOT W84.01
OUT W254.00
LD TR0
LD W254.00
AND P_0_2s
ORNOT H3.00
ANDLD
OUT W124.00
; rung 2137
LD W254.01
AND W374.15
OR H3.00
LDNOT W254.00
ORNOT W374.15
ANDLD
OUT H3.00
; rung 2138
LD W375.04
OUT TR0
LD W84.03
OR W254.03
ANDLD
ANDNOT H3.01
ANDNOT T0039
ANDNOT W254.02
ANDNOT W84.02
OUT W254.03
LD TR0
LD W254.03
AND P_0_2s
OR H3.01
ANDLD
OUT W124.03
LD TR0
LD W84.02
OR W254.02
ANDLD
AND H3.01
ANDNOT T0039
ANDNOT W254.03
ANDNOT W84.03
OUT W254.02
LD TR0
LD W254.02
AND P_0_2s
ORNOT H3.01
ANDLD
OUT W124.02
; rung 2139
LD W254.03
AND W374.15
OR H3.01
LDNOT W254.02
ORNOT W374.15
ANDLD
OUT H3.01

; rung 2140
LD W375.04
OUT TR0
LD W84.05
OR W254.05
ANDLD
ANDNOT H3.02
ANDNOT T0039
ANDNOT W254.04
ANDNOT W84.04
OUT W254.05
LD TR0
LD W254.05
AND P_0_2s
OR H3.02
ANDLD
OUT W124.05
LD TR0
LD W84.04
OR W254.04
ANDLD
AND H3.02
ANDNOT T0039
ANDNOT W254.05
ANDNOT W84.05
OUT W254.04
LD TR0
LD W254.04
AND P_0_2s
ORNOT H3.02
ANDLD
OUT W124.04
; rung 2141
LD W254.05
AND W374.15
OR H3.02
LDNOT W254.04
ORNOT W374.15
ANDLD
OUT H3.02
; rung 2142
LD W375.04
OUT TR0
LD W84.07
OR W254.07
ANDLD
ANDNOT H3.03
ANDNOT T0039
ANDNOT W254.06
ANDNOT W84.06
OUT W254.07
LD TR0
LD W254.07
AND P_0_2s
OR H3.03
ANDLD
OUT W124.07
LD TR0
LD W84.06
OR W254.06
ANDLD
AND H3.03
ANDNOT T0039
ANDNOT W254.07
ANDNOT W84.07
OUT W254.06
LD TR0
LD W254.06
AND P_0_2s
ORNOT H3.03
ANDLD
OUT W124.06
; rung 2143
LD W254.07
AND W374.15
OR H3.03
LDNOT W254.06
ORNOT W374.15
ANDLD
OUT H3.03

; rung 2144
LD W375.04
OUT TR0
LD W84.09
OR W254.09
ANDLD
ANDNOT H3.04
ANDNOT T0039
ANDNOT W254.08
ANDNOT W84.08
OUT W254.09
LD TR0
LD W254.09
AND P_0_2s
OR H3.04
ANDLD
OUT W124.09
LD TR0
LD W84.08
OR W254.08
ANDLD
AND H3.04
ANDNOT T0039
ANDNOT W254.09
ANDNOT W84.09
OUT W254.08
LD TR0
LD W254.08
AND P_0_2s
ORNOT H3.04
ANDLD
OUT W124.08
; rung 2145
LD W254.09
AND W374.15
OR H3.04
LDNOT W254.08
ORNOT W374.15
ANDLD
OUT H3.04
; rung 2146
LD W375.04
OUT TR0
LD W84.11
OR W254.11
ANDLD
ANDNOT H3.05
ANDNOT T0039
ANDNOT W254.10
ANDNOT W84.10
OUT W254.11
LD TR0
LD W254.11
AND P_0_2s
OR H3.05
ANDLD
OUT W124.11
LD TR0
LD W84.10
OR W254.10
ANDLD
AND H3.05
ANDNOT T0039
ANDNOT W254.11
ANDNOT W84.11
OUT W254.10
LD TR0
LD W254.10
AND P_0_2s
ORNOT H3.05
ANDLD
OUT W124.10
; rung 2147
LD W254.11
AND W374.15
OR H3.05
LDNOT W254.10
ORNOT W374.15
ANDLD
OUT H3.05

; rung 2148
LD W375.04
OUT TR0
LD W84.13
OR W254.13
ANDLD
ANDNOT H3.06
ANDNOT T0039
ANDNOT W254.12
ANDNOT W84.12
OUT W254.13
LD TR0
LD W254.13
AND P_0_2s
OR H3.06
ANDLD
OUT W124.13
LD TR0
LD W84.12
OR W254.12
ANDLD
AND H3.06
ANDNOT T0039
ANDNOT W254.13
ANDNOT W84.13
OUT W254.12
LD TR0
LD W254.12
AND P_0_2s
ORNOT H3.06
ANDLD
OUT W124.12
; rung 2149
LD W254.13
AND W374.15
OR H3.06
LDNOT W254.12
ORNOT W374.15
ANDLD
OUT H3.06
; rung 2150
LD W375.04
OUT TR0
LD W84.15
OR W254.15
ANDLD
ANDNOT H3.07
ANDNOT T0039
ANDNOT W254.14
ANDNOT W84.14
OUT W254.15
LD TR0
LD W254.15
AND P_0_2s
OR H3.07
ANDLD
OUT W124.15
LD TR0
LD W84.14
OR W254.14
ANDLD
AND H3.07
ANDNOT T0039
ANDNOT W254.15
ANDNOT W84.15
OUT W254.14
LD TR0
LD W254.14
AND P_0_2s
ORNOT H3.07
ANDLD
OUT W124.14
; rung 2151
LD W254.15
AND W374.15
OR H3.07
LDNOT W254.14
ORNOT W374.15
ANDLD
OUT H3.07
; rung 2152: ***** 動作選択６ *****
LD W379.02
AND W378.05
LD W378.13
OR W378.11
AND W379.01
ORLD
ANDNOT W509.15
OUT W375.05

; rung 2153
LD W375.05
OUT TR0
LD W85.01
OR W255.01
ANDLD
ANDNOT H3.08
ANDNOT T0039
ANDNOT W255.00
ANDNOT W85.00
OUT W255.01
LD TR0
LD W255.01
AND P_0_2s
OR H3.08
ANDLD
OUT W125.01
LD TR0
LD W85.00
OR W255.00
ANDLD
AND H3.08
ANDNOT T0039
ANDNOT W255.01
ANDNOT W85.01
OUT W255.00
LD TR0
LD W255.00
AND P_0_2s
ORNOT H3.08
ANDLD
OUT W125.00
; rung 2154
LD W255.01
AND W374.15
OR H3.08
LDNOT W255.00
ORNOT W374.15
ANDLD
OUT H3.08
; rung 2155
LD W375.05
OUT TR0
LD W85.03
OR W255.03
ANDLD
ANDNOT H3.09
ANDNOT T0039
ANDNOT W255.02
ANDNOT W85.02
OUT W255.03
LD TR0
LD W255.03
AND P_0_2s
OR H3.09
ANDLD
OUT W125.03
LD TR0
LD W85.02
OR W255.02
ANDLD
AND H3.09
ANDNOT T0039
ANDNOT W255.03
ANDNOT W85.03
OUT W255.02
LD TR0
LD W255.02
AND P_0_2s
ORNOT H3.09
ANDLD
OUT W125.02
; rung 2156
LD W255.03
AND W374.15
OR H3.09
LDNOT W255.02
ORNOT W374.15
ANDLD
OUT H3.09

; rung 2157
LD W375.05
OUT TR0
LD W85.05
OR W255.05
ANDLD
ANDNOT H3.10
ANDNOT T0039
ANDNOT W255.04
ANDNOT W85.04
OUT W255.05
LD TR0
LD W255.05
AND P_0_2s
OR H3.10
ANDLD
OUT W125.05
LD TR0
LD W85.04
OR W255.04
ANDLD
AND H3.10
ANDNOT T0039
ANDNOT W255.05
ANDNOT W85.05
OUT W255.04
LD TR0
LD W255.04
AND P_0_2s
ORNOT H3.10
ANDLD
OUT W125.04
; rung 2158
LD W255.05
AND W374.15
OR H3.10
LDNOT W255.04
ORNOT W374.15
ANDLD
OUT H3.10
; rung 2159
LD W375.05
OUT TR0
LD W85.07
OR W255.07
ANDLD
ANDNOT H3.11
ANDNOT T0039
ANDNOT W255.06
ANDNOT W85.06
OUT W255.07
LD TR0
LD W255.07
AND P_0_2s
OR H3.11
ANDLD
OUT W125.07
LD TR0
LD W85.06
OR W255.06
ANDLD
AND H3.11
ANDNOT T0039
ANDNOT W255.07
ANDNOT W85.07
OUT W255.06
LD TR0
LD W255.06
AND P_0_2s
ORNOT H3.11
ANDLD
OUT W125.06
; rung 2160
LD W255.07
AND W374.15
OR H3.11
LDNOT W255.06
ORNOT W374.15
ANDLD
OUT H3.11

; rung 2161
LD W375.05
OUT TR0
LD W85.09
OR W255.09
ANDLD
ANDNOT H3.12
ANDNOT T0039
ANDNOT W255.08
ANDNOT W85.08
OUT W255.09
LD TR0
LD W255.09
AND P_0_2s
OR H3.12
ANDLD
OUT W125.09
LD TR0
LD W85.08
OR W255.08
ANDLD
AND H3.12
ANDNOT T0039
ANDNOT W255.09
ANDNOT W85.09
OUT W255.08
LD TR0
LD W255.08
AND P_0_2s
ORNOT H3.12
ANDLD
OUT W125.08
; rung 2162
LD W255.09
AND W374.15
OR H3.12
LDNOT W255.08
ORNOT W374.15
ANDLD
OUT H3.12
; rung 2163
LD W375.05
OUT TR0
LD W85.11
OR W255.11
ANDLD
ANDNOT H3.13
ANDNOT T0039
ANDNOT W255.10
ANDNOT W85.10
OUT W255.11
LD TR0
LD W255.11
AND P_0_2s
OR H3.13
ANDLD
OUT W125.11
LD TR0
LD W85.10
OR W255.10
ANDLD
AND H3.13
ANDNOT T0039
ANDNOT W255.11
ANDNOT W85.11
OUT W255.10
LD TR0
LD W255.10
AND P_0_2s
ORNOT H3.13
ANDLD
OUT W125.10
; rung 2164
LD W255.11
AND W374.15
OR H3.13
LDNOT W255.10
ORNOT W374.15
ANDLD
OUT H3.13

; rung 2165
LD W375.05
OUT TR0
LD W85.13
OR W255.13
ANDLD
ANDNOT H3.14
ANDNOT T0039
ANDNOT W255.12
ANDNOT W85.12
OUT W255.13
LD TR0
LD W255.13
AND P_0_2s
OR H3.14
ANDLD
OUT W125.13
LD TR0
LD W85.12
OR W255.12
ANDLD
AND H3.14
ANDNOT T0039
ANDNOT W255.13
ANDNOT W85.13
OUT W255.12
LD TR0
LD W255.12
AND P_0_2s
ORNOT H3.14
ANDLD
OUT W125.12
; rung 2166
LD W255.13
AND W374.15
OR H3.14
LDNOT W255.12
ORNOT W374.15
ANDLD
OUT H3.14
; rung 2167
LD W375.05
OUT TR0
LD W85.15
OR W255.15
ANDLD
ANDNOT H3.15
ANDNOT T0039
ANDNOT W255.14
ANDNOT W85.14
OUT W255.15
LD TR0
LD W255.15
AND P_0_2s
OR H3.15
ANDLD
OUT W125.15
LD TR0
LD W85.14
OR W255.14
ANDLD
AND H3.15
ANDNOT T0039
ANDNOT W255.15
ANDNOT W85.15
OUT W255.14
LD TR0
LD W255.14
AND P_0_2s
ORNOT H3.15
ANDLD
OUT W125.14
; rung 2168
LD W255.15
AND W374.15
OR H3.15
LDNOT W255.14
ORNOT W374.15
ANDLD
OUT H3.15
; rung 2169: ***** 動作選択７ *****
LD W379.02
AND W378.06
LD W378.14
OR W378.12
AND W379.01
ORLD
ANDNOT W509.15
OUT W375.06

; rung 2170
LD W375.06
OUT TR0
LD W86.01
OR W256.01
ANDLD
ANDNOT H7.00
ANDNOT T0039
ANDNOT W256.00
ANDNOT W86.00
OUT W256.01
LD TR0
LD W256.01
AND P_0_2s
OR H7.00
ANDLD
OUT W126.01
LD TR0
LD W86.00
OR W256.00
ANDLD
AND H7.00
ANDNOT T0039
ANDNOT W256.01
ANDNOT W86.01
OUT W256.00
LD TR0
LD W256.00
AND P_0_2s
ORNOT H7.00
ANDLD
OUT W126.00
; rung 2171
LD W256.01
AND W374.15
OR H7.00
LDNOT W256.00
ORNOT W374.15
ANDLD
OUT H7.00
; rung 2172
LD W375.06
OUT TR0
LD W86.03
OR W256.03
ANDLD
ANDNOT H7.01
ANDNOT T0039
ANDNOT W256.02
ANDNOT W86.02
OUT W256.03
LD TR0
LD W256.03
AND P_0_2s
OR H7.01
ANDLD
OUT W126.03
LD TR0
LD W86.02
OR W256.02
ANDLD
AND H7.01
ANDNOT T0039
ANDNOT W256.03
ANDNOT W86.03
OUT W256.02
LD TR0
LD W256.02
AND P_0_2s
ORNOT H7.01
ANDLD
OUT W126.02
; rung 2173
LD W256.03
AND W374.15
OR H7.01
LDNOT W256.02
ORNOT W374.15
ANDLD
OUT H7.01

; rung 2174
LD W375.06
OUT TR0
LD W86.05
OR W256.05
ANDLD
ANDNOT H7.02
ANDNOT T0039
ANDNOT W256.04
ANDNOT W86.04
OUT W256.05
LD TR0
LD W256.05
AND P_0_2s
OR H7.02
ANDLD
OUT W126.05
LD TR0
LD W86.04
OR W256.04
ANDLD
AND H7.02
ANDNOT T0039
ANDNOT W256.05
ANDNOT W86.05
OUT W256.04
LD TR0
LD W256.04
AND P_0_2s
ORNOT H7.02
ANDLD
OUT W126.04
; rung 2175
LD W256.05
AND W374.15
OR H7.02
LDNOT W256.04
ORNOT W374.15
ANDLD
OUT H7.02
; rung 2176
LD W375.06
OUT TR0
LD W86.07
OR W256.07
ANDLD
ANDNOT H7.03
ANDNOT T0039
ANDNOT W256.06
ANDNOT W86.06
OUT W256.07
LD TR0
LD W256.07
AND P_0_2s
OR H7.03
ANDLD
OUT W126.07
LD TR0
LD W86.06
OR W256.06
ANDLD
AND H7.03
ANDNOT T0039
ANDNOT W256.07
ANDNOT W86.07
OUT W256.06
LD TR0
LD W256.06
AND P_0_2s
ORNOT H7.03
ANDLD
OUT W126.06
; rung 2177
LD W256.07
AND W374.15
OR H7.03
LDNOT W256.06
ORNOT W374.15
ANDLD
OUT H7.03

; rung 2178
LD W375.06
OUT TR0
LD W86.09
OR W256.09
ANDLD
ANDNOT H7.04
ANDNOT T0039
ANDNOT W256.08
ANDNOT W86.08
OUT W256.09
LD TR0
LD W256.09
AND P_0_2s
OR H7.04
ANDLD
OUT W126.09
LD TR0
LD W86.08
OR W256.08
ANDLD
AND H7.04
ANDNOT T0039
ANDNOT W256.09
ANDNOT W86.09
OUT W256.08
LD TR0
LD W256.08
AND P_0_2s
ORNOT H7.04
ANDLD
OUT W126.08
; rung 2179
LD W256.09
AND W374.15
OR H7.04
LDNOT W256.08
ORNOT W374.15
ANDLD
OUT H7.04
OUT 23.00
; rung 2180
LD W375.06
OUT TR0
LD W86.11
OR W256.11
ANDLD
ANDNOT H7.05
ANDNOT T0039
ANDNOT W256.10
ANDNOT W86.10
OUT W256.11
LD TR0
LD W256.11
AND P_0_2s
OR H7.05
ANDLD
OUT W126.11
LD TR0
LD W86.10
OR W256.10
ANDLD
AND H7.05
ANDNOT T0039
ANDNOT W256.11
ANDNOT W86.11
OUT W256.10
LD TR0
LD W256.10
AND P_0_2s
ORNOT H7.05
ANDLD
OUT W126.10
; rung 2181
LD W256.11
AND W374.15
OR H7.05
LDNOT W256.10
ORNOT W374.15
ANDLD
OUT H7.05
OUT 23.01

; rung 2182
LD W375.06
OUT TR0
LD W86.13
OR W256.13
ANDLD
ANDNOT H7.06
ANDNOT T0039
ANDNOT W256.12
ANDNOT W86.12
OUT W256.13
LD TR0
LD W256.13
AND P_0_2s
OR H7.06
ANDLD
OUT W126.13
LD TR0
LD W86.12
OR W256.12
ANDLD
AND H7.06
ANDNOT T0039
ANDNOT W256.13
ANDNOT W86.13
OUT W256.12
LD TR0
LD W256.12
AND P_0_2s
ORNOT H7.06
ANDLD
OUT W126.12
; rung 2183
LD W256.13
AND W374.15
OR H7.06
LDNOT W256.12
ORNOT W374.15
ANDLD
OUT H7.06
OUT 23.02
; rung 2184
LD W375.06
OUT TR0
LD W86.15
OR W256.15
ANDLD
ANDNOT H7.07
ANDNOT T0039
ANDNOT W256.14
ANDNOT W86.14
OUT W256.15
LD TR0
LD W256.15
AND P_0_2s
OR H7.07
ANDLD
OUT W126.15
LD TR0
LD W86.14
OR W256.14
ANDLD
AND H7.07
ANDNOT T0039
ANDNOT W256.15
ANDNOT W86.15
OUT W256.14
LD TR0
LD W256.14
AND P_0_2s
ORNOT H7.07
ANDLD
OUT W126.14
; rung 2185
LD W256.15
AND W374.15
OR H7.07
LDNOT W256.14
ORNOT W374.15
ANDLD
OUT H7.07
OUT 23.03
; rung 2186: ***** 動作選択８ *****
LD W379.02
AND W378.07
LD W378.14
OR W378.12
AND W379.01
ORLD
ANDNOT W509.15
OUT W375.07

; rung 2187
LD W375.07
OUT TR0
LD W87.01
OR W257.01
ANDLD
ANDNOT H7.08
ANDNOT T0039
ANDNOT W257.00
ANDNOT W87.00
OUT W257.01
LD TR0
LD W257.01
AND P_0_2s
OR H7.08
ANDLD
OUT W127.01
LD TR0
LD W87.00
OR W257.00
ANDLD
AND H7.08
ANDNOT T0039
ANDNOT W257.01
ANDNOT W87.01
OUT W257.00
LD TR0
LD W257.00
AND P_0_2s
ORNOT H7.08
ANDLD
OUT W127.00
; rung 2188
LD W257.01
AND W374.15
OR H7.08
LDNOT W257.00
ORNOT W374.15
ANDLD
OUT H7.08
; rung 2189
LD W375.07
OUT TR0
LD W87.03
OR W257.03
ANDLD
ANDNOT H7.09
ANDNOT T0039
ANDNOT W257.02
ANDNOT W87.02
OUT W257.03
LD TR0
LD W257.03
AND P_0_2s
OR H7.09
ANDLD
OUT W127.03
LD TR0
LD W87.02
OR W257.02
ANDLD
AND H7.09
ANDNOT T0039
ANDNOT W257.03
ANDNOT W87.03
OUT W257.02
LD TR0
LD W257.02
AND P_0_2s
ORNOT H7.09
ANDLD
OUT W127.02
; rung 2190
LD W257.03
AND W374.15
OR H7.09
LDNOT W257.02
ORNOT W374.15
ANDLD
OUT H7.09

; rung 2191
LD W375.07
OUT TR0
LD W87.05
OR W257.05
ANDLD
ANDNOT H7.10
ANDNOT T0039
ANDNOT W257.04
ANDNOT W87.04
OUT W257.05
LD TR0
LD W257.05
AND P_0_2s
OR H7.10
ANDLD
OUT W127.05
LD TR0
LD W87.04
OR W257.04
ANDLD
AND H7.10
ANDNOT T0039
ANDNOT W257.05
ANDNOT W87.05
OUT W257.04
LD TR0
LD W257.04
AND P_0_2s
ORNOT H7.10
ANDLD
OUT W127.04
; rung 2192
LD W257.05
AND W374.15
OR H7.10
LDNOT W257.04
ORNOT W374.15
ANDLD
OUT H7.10
; rung 2193
LD W375.07
OUT TR0
LD W87.07
OR W257.07
ANDLD
ANDNOT H7.11
ANDNOT T0039
ANDNOT W257.06
ANDNOT W87.06
OUT W257.07
LD TR0
LD W257.07
AND P_0_2s
OR H7.11
ANDLD
OUT W127.07
LD TR0
LD W87.06
OR W257.06
ANDLD
AND H7.11
ANDNOT T0039
ANDNOT W257.07
ANDNOT W87.07
OUT W257.06
LD TR0
LD W257.06
AND P_0_2s
ORNOT H7.11
ANDLD
OUT W127.06
; rung 2194
LD W257.07
AND W374.15
OR H7.11
LDNOT W257.06
ORNOT W374.15
ANDLD
OUT H7.11

; rung 2195
LD W375.07
OUT TR0
LD W87.09
OR W257.09
ANDLD
ANDNOT H7.12
ANDNOT T0039
ANDNOT W257.08
ANDNOT W87.08
OUT W257.09
LD TR0
LD W257.09
AND P_0_2s
OR H7.12
ANDLD
OUT W127.09
LD TR0
LD W87.08
OR W257.08
ANDLD
AND H7.12
ANDNOT T0039
ANDNOT W257.09
ANDNOT W87.09
OUT W257.08
LD TR0
LD W257.08
AND P_0_2s
ORNOT H7.12
ANDLD
OUT W127.08
; rung 2196
LD W257.09
AND W374.15
OR H7.12
LDNOT W257.08
ORNOT W374.15
ANDLD
OUT H7.12
; rung 2197
LD W375.07
OUT TR0
LD W87.11
OR W257.11
ANDLD
ANDNOT H7.13
ANDNOT T0039
ANDNOT W257.10
ANDNOT W87.10
OUT W257.11
LD TR0
LD W257.11
AND P_0_2s
OR H7.13
ANDLD
OUT W127.11
LD TR0
LD W87.10
OR W257.10
ANDLD
AND H7.13
ANDNOT T0039
ANDNOT W257.11
ANDNOT W87.11
OUT W257.10
LD TR0
LD W257.10
AND P_0_2s
ORNOT H7.13
ANDLD
OUT W127.10
; rung 2198
LD W257.11
AND W374.15
OR H7.13
LDNOT W257.10
ORNOT W374.15
ANDLD
OUT H7.13

; rung 2199
LD W375.07
OUT TR0
LD W87.13
OR W257.13
ANDLD
ANDNOT H7.14
ANDNOT T0039
ANDNOT W257.12
ANDNOT W87.12
OUT W257.13
LD TR0
LD W257.13
AND P_0_2s
OR H7.14
ANDLD
OUT W127.13
LD TR0
LD W87.12
OR W257.12
ANDLD
AND H7.14
ANDNOT T0039
ANDNOT W257.13
ANDNOT W87.13
OUT W257.12
LD TR0
LD W257.12
AND P_0_2s
ORNOT H7.14
ANDLD
OUT W127.12
; rung 2200
LD W257.13
AND W374.15
OR H7.14
LDNOT W257.12
ORNOT W374.15
ANDLD
OUT H7.14
; rung 2201
LD W375.07
OUT TR0
LD W87.15
OR W257.15
ANDLD
ANDNOT H7.15
ANDNOT T0039
ANDNOT W257.14
ANDNOT W87.14
OUT W257.15
LD TR0
LD W257.15
AND P_0_2s
OR H7.15
ANDLD
OUT W127.15
LD TR0
LD W87.14
OR W257.14
ANDLD
AND H7.15
ANDNOT T0039
ANDNOT W257.15
ANDNOT W87.15
OUT W257.14
LD TR0
LD W257.14
AND P_0_2s
ORNOT H7.15
ANDLD
OUT W127.14
; rung 2202
LD W257.15
AND W374.15
OR H7.15
LDNOT W257.14
ORNOT W374.15
ANDLD
OUT H7.15
; rung 2203: ***** 動作選択９ *****
LD W379.05
AND W378.10
LD W378.14
OR W378.12
AND W379.01
ORLD
ANDNOT W509.15
OUT W375.08

; rung 2204
LD W375.08
OUT TR0
LD W88.01
OR W258.01
ANDLD
ANDNOT H8.00
ANDNOT T0039
ANDNOT W258.00
ANDNOT W88.00
OUT W258.01
LD TR0
LD W258.01
AND P_0_2s
OR H8.00
ANDLD
OUT W128.01
LD TR0
LD W88.00
OR W258.00
ANDLD
AND H8.00
ANDNOT T0039
ANDNOT W258.01
ANDNOT W88.01
OUT W258.00
LD TR0
LD W258.00
AND P_0_2s
ORNOT H8.00
ANDLD
OUT W128.00
; rung 2205
LD W258.01
AND W374.15
OR H8.00
LDNOT W258.00
ORNOT W374.15
ANDLD
OUT H8.00
; rung 2206
LD W375.08
OUT TR0
LD W88.03
OR W258.03
ANDLD
ANDNOT H8.01
ANDNOT T0039
ANDNOT W258.02
ANDNOT W88.02
OUT W258.03
LD TR0
LD W258.03
AND P_0_2s
OR H8.01
ANDLD
OUT W128.03
LD TR0
LD W88.02
OR W258.02
ANDLD
AND H8.01
ANDNOT T0039
ANDNOT W258.03
ANDNOT W88.03
OUT W258.02
LD TR0
LD W258.02
AND P_0_2s
ORNOT H8.01
ANDLD
OUT W128.02
; rung 2207
LD W258.03
AND W374.15
OR H8.01
LDNOT W258.02
ORNOT W374.15
ANDLD
OUT H8.01

; rung 2208
LD W375.08
OUT TR0
LD W88.05
OR W258.05
ANDLD
ANDNOT H8.02
ANDNOT T0039
ANDNOT W258.04
ANDNOT W88.04
OUT W258.05
LD TR0
LD W258.05
AND P_0_2s
OR H8.02
ANDLD
OUT W128.05
LD TR0
LD W88.04
OR W258.04
ANDLD
AND H8.02
ANDNOT T0039
ANDNOT W258.05
ANDNOT W88.05
OUT W258.04
LD TR0
LD W258.04
AND P_0_2s
ORNOT H8.02
ANDLD
OUT W128.04
; rung 2209
LD W258.05
AND W374.15
OR H8.02
LDNOT W258.04
ORNOT W374.15
ANDLD
OUT H8.02
; rung 2210
LD W375.08
OUT TR0
LD W88.07
OR W258.07
ANDLD
ANDNOT H8.03
ANDNOT T0039
ANDNOT W258.06
ANDNOT W88.06
OUT W258.07
LD TR0
LD W258.07
AND P_0_2s
OR H8.03
ANDLD
OUT W128.07
LD TR0
LD W88.06
OR W258.06
ANDLD
AND H8.03
ANDNOT T0039
ANDNOT W258.07
ANDNOT W88.07
OUT W258.06
LD TR0
LD W258.06
AND P_0_2s
ORNOT H8.03
ANDLD
OUT W128.06
; rung 2211
LD W258.07
AND W374.15
OR H8.03
LDNOT W258.06
ORNOT W374.15
ANDLD
OUT H8.03

; rung 2212
LD W375.08
OUT TR0
LD W88.09
OR W258.09
ANDLD
ANDNOT H8.04
ANDNOT T0039
ANDNOT W258.08
ANDNOT W88.08
OUT W258.09
LD TR0
LD W258.09
AND P_0_2s
OR H8.04
ANDLD
OUT W128.09
LD TR0
LD W88.08
OR W258.08
ANDLD
AND H8.04
ANDNOT T0039
ANDNOT W258.09
ANDNOT W88.09
OUT W258.08
LD TR0
LD W258.08
AND P_0_2s
ORNOT H8.04
ANDLD
OUT W128.08
; rung 2213
LD W258.09
AND W374.15
OR H8.04
LDNOT W258.08
ORNOT W374.15
ANDLD
OUT H8.04
; rung 2214
LD W375.08
OUT TR0
LD W88.11
OR W258.11
ANDLD
ANDNOT H8.05
ANDNOT T0039
ANDNOT W258.10
ANDNOT W88.10
OUT W258.11
LD TR0
LD W258.11
AND P_0_2s
OR H8.05
ANDLD
OUT W128.11
LD TR0
LD W88.10
OR W258.10
ANDLD
AND H8.05
ANDNOT T0039
ANDNOT W258.11
ANDNOT W88.11
OUT W258.10
LD TR0
LD W258.10
AND P_0_2s
ORNOT H8.05
ANDLD
OUT W128.10
; rung 2215
LD W258.11
AND W374.15
OR H8.05
LDNOT W258.10
ORNOT W374.15
ANDLD
OUT H8.05

; rung 2216
LD W375.08
OUT TR0
LD W88.13
OR W258.13
ANDLD
ANDNOT H8.06
ANDNOT T0039
ANDNOT W258.12
ANDNOT W88.12
OUT W258.13
LD TR0
LD W258.13
AND P_0_2s
OR H8.06
ANDLD
OUT W128.13
LD TR0
LD W88.12
OR W258.12
ANDLD
AND H8.06
ANDNOT T0039
ANDNOT W258.13
ANDNOT W88.13
OUT W258.12
LD TR0
LD W258.12
AND P_0_2s
ORNOT H8.06
ANDLD
OUT W128.12
; rung 2217
LD W258.13
AND W374.15
OR H8.06
LDNOT W258.12
ORNOT W374.15
ANDLD
OUT H8.06
; rung 2218
LD W375.08
OUT TR0
LD W88.15
OR W258.15
ANDLD
ANDNOT H8.07
ANDNOT T0039
ANDNOT W258.14
ANDNOT W88.14
OUT W258.15
LD TR0
LD W258.15
AND P_0_2s
OR H8.07
ANDLD
OUT W128.15
LD TR0
LD W88.14
OR W258.14
ANDLD
AND H8.07
ANDNOT T0039
ANDNOT W258.15
ANDNOT W88.15
OUT W258.14
LD TR0
LD W258.14
AND P_0_2s
ORNOT H8.07
ANDLD
OUT W128.14
; rung 2219
LD W258.15
AND W374.15
OR H8.07
LDNOT W258.14
ORNOT W374.15
ANDLD
OUT H8.07
; rung 2220: ***** 動作選択10 *****
LD W379.05
AND W378.11
LD W378.14
OR W378.12
AND W379.01
ORLD
ANDNOT W509.15
OUT W375.09

; rung 2221
LD W375.09
OUT TR0
LD W89.01
OR W259.01
ANDLD
ANDNOT H8.08
ANDNOT T0039
ANDNOT W259.00
ANDNOT W89.00
OUT W259.01
LD TR0
LD W259.01
AND P_0_2s
OR H8.08
ANDLD
OUT W129.01
LD TR0
LD W89.00
OR W259.00
ANDLD
AND H8.08
ANDNOT T0039
ANDNOT W259.01
ANDNOT W89.01
OUT W259.00
LD TR0
LD W259.00
AND P_0_2s
ORNOT H8.08
ANDLD
OUT W129.00
; rung 2222
LD W259.01
AND W374.15
OR H8.08
LDNOT W259.00
ORNOT W374.15
ANDLD
OUT H8.08
; rung 2223
LD W375.09
OUT TR0
LD W89.03
OR W259.03
ANDLD
ANDNOT H8.09
ANDNOT T0039
ANDNOT W259.02
ANDNOT W89.02
OUT W259.03
LD TR0
LD W259.03
AND P_0_2s
OR H8.09
ANDLD
OUT W129.03
LD TR0
LD W89.02
OR W259.02
ANDLD
AND H8.09
ANDNOT T0039
ANDNOT W259.03
ANDNOT W89.03
OUT W259.02
LD TR0
LD W259.02
AND P_0_2s
ORNOT H8.09
ANDLD
OUT W129.02
; rung 2224
LD W259.03
AND W374.15
OR H8.09
LDNOT W259.02
ORNOT W374.15
ANDLD
OUT H8.09

; rung 2225
LD W375.09
OUT TR0
LD W89.05
OR W259.05
ANDLD
ANDNOT H8.10
ANDNOT T0039
ANDNOT W259.04
ANDNOT W89.04
OUT W259.05
LD TR0
LD W259.05
AND P_0_2s
OR H8.10
ANDLD
OUT W129.05
LD TR0
LD W89.04
OR W259.04
ANDLD
AND H8.10
ANDNOT T0039
ANDNOT W259.05
ANDNOT W89.05
OUT W259.04
LD TR0
LD W259.04
AND P_0_2s
ORNOT H8.10
ANDLD
OUT W129.04
; rung 2226
LD W259.05
AND W374.15
OR H8.10
LDNOT W259.04
ORNOT W374.15
ANDLD
OUT H8.10
; rung 2227
LD W375.09
OUT TR0
LD W89.07
OR W259.07
ANDLD
ANDNOT H8.11
ANDNOT T0039
ANDNOT W259.06
ANDNOT W89.06
OUT W259.07
LD TR0
LD W259.07
AND P_0_2s
OR H8.11
ANDLD
OUT W129.07
LD TR0
LD W89.06
OR W259.06
ANDLD
AND H8.11
ANDNOT T0039
ANDNOT W259.07
ANDNOT W89.07
OUT W259.06
LD TR0
LD W259.06
AND P_0_2s
ORNOT H8.11
ANDLD
OUT W129.06
; rung 2228
LD W259.07
AND W374.15
OR H8.11
LDNOT W259.06
ORNOT W374.15
ANDLD
OUT H8.11

; rung 2229
LD W375.09
OUT TR0
LD W89.09
OR W259.09
ANDLD
ANDNOT H8.12
ANDNOT T0039
ANDNOT W259.08
ANDNOT W89.08
OUT W259.09
LD TR0
LD W259.09
AND P_0_2s
OR H8.12
ANDLD
OUT W129.09
LD TR0
LD W89.08
OR W259.08
ANDLD
AND H8.12
ANDNOT T0039
ANDNOT W259.09
ANDNOT W89.09
OUT W259.08
LD TR0
LD W259.08
AND P_0_2s
ORNOT H8.12
ANDLD
OUT W129.08
; rung 2230
LD W259.09
AND W374.15
OR H8.12
LDNOT W259.08
ORNOT W374.15
ANDLD
OUT H8.12
; rung 2231
LD W375.09
OUT TR0
LD W89.11
OR W259.11
ANDLD
ANDNOT H8.13
ANDNOT T0039
ANDNOT W259.10
ANDNOT W89.10
OUT W259.11
LD TR0
LD W259.11
AND P_0_2s
OR H8.13
ANDLD
OUT W129.11
LD TR0
LD W89.10
OR W259.10
ANDLD
AND H8.13
ANDNOT T0039
ANDNOT W259.11
ANDNOT W89.11
OUT W259.10
LD TR0
LD W259.10
AND P_0_2s
ORNOT H8.13
ANDLD
OUT W129.10
; rung 2232
LD W259.11
AND W374.15
LD H8.13
ANDNOT W57.14
ANDNOT W240.00
ORLD
LD W57.15
ANDNOT W240.03
ORLD
LD W240.02
OR W240.01
AND W240.03
ORLD
LDNOT W259.10
ORNOT W374.15
ANDLD
AND W49.00
AND W49.01
ANDNOT T0021
OUT H8.13

; rung 2233
LD W375.09
OUT TR0
LD W89.13
OR W259.13
ANDLD
ANDNOT H8.14
ANDNOT T0039
ANDNOT W259.12
ANDNOT W89.12
OUT W259.13
LD TR0
LD W259.13
AND P_0_2s
OR H8.14
ANDLD
OUT W129.13
LD TR0
LD W89.12
OR W259.12
ANDLD
AND H8.14
ANDNOT T0039
ANDNOT W259.13
ANDNOT W89.13
OUT W259.12
LD TR0
LD W259.12
AND P_0_2s
ORNOT H8.14
ANDLD
OUT W129.12
; rung 2234
LD W259.13
AND W374.15
LD H8.14
ANDNOT W57.14
ORLD
LDNOT W259.12
ORNOT W374.15
ANDLD
LDNOT H8.13
OR P_On
ANDLD
ANDNOT T0021
OUT H8.14
; rung 2235
LD W375.09
OUT TR0
LD W89.15
OR W259.15
ANDLD
ANDNOT H8.15
ANDNOT T0039
ANDNOT W259.14
ANDNOT W89.14
OUT W259.15
LD TR0
LD W259.15
AND P_0_2s
OR H8.15
ANDLD
OUT W129.15
LD TR0
LD W89.14
OR W259.14
ANDLD
AND H8.15
ANDNOT T0039
ANDNOT W259.15
ANDNOT W89.15
OUT W259.14
LD TR0
LD W259.14
AND P_0_2s
ORNOT H8.15
ANDLD
OUT W129.14
; rung 2236
LD W259.15
AND W374.15
OR H8.15
LDNOT W259.14
ORNOT W374.15
ANDLD
OUT H8.15
; rung 2237: ***** 動作選択11 *****
LD W379.05
AND W378.12
LD W378.14
OR W378.12
AND W379.01
ORLD
ANDNOT W509.15
OUT W371.06

; rung 2238
LD W371.06
OUT TR0
LD W90.01
OR W260.01
ANDLD
ANDNOT H9.00
ANDNOT T0039
ANDNOT W260.00
ANDNOT W90.00
OUT W260.01
LD TR0
LD W260.01
AND P_0_2s
OR H9.00
ANDLD
OUT W130.01
LD TR0
LD W90.00
OR W260.00
ANDLD
AND H9.00
ANDNOT T0039
ANDNOT W260.01
ANDNOT W90.01
OUT W260.00
LD TR0
LD W260.00
AND P_0_2s
ORNOT H9.00
ANDLD
OUT W130.00
; rung 2239
LD W260.01
AND W374.15
OR H9.00
LDNOT W260.00
ORNOT W374.15
ANDLD
OUT H9.00
; rung 2240
LD W371.06
OUT TR0
LD W90.03
OR W260.03
ANDLD
ANDNOT H9.01
ANDNOT T0039
ANDNOT W260.02
ANDNOT W90.02
OUT W260.03
LD TR0
LD W260.03
AND P_0_2s
OR H9.01
ANDLD
OUT W130.03
LD TR0
LD W90.02
OR W260.02
ANDLD
AND H9.01
ANDNOT T0039
ANDNOT W260.03
ANDNOT W90.03
OUT W260.02
LD TR0
LD W260.02
AND P_0_2s
ORNOT H9.01
ANDLD
OUT W130.02
; rung 2241
LD W260.03
AND W374.15
OR H9.01
LDNOT W260.02
ORNOT W374.15
ANDLD
OUT H9.01

; rung 2242
LD W371.06
OUT TR0
LD W90.05
OR W260.05
ANDLD
ANDNOT H9.02
ANDNOT T0039
ANDNOT W260.04
ANDNOT W90.04
OUT W260.05
LD TR0
LD W260.05
AND P_0_2s
OR H9.02
ANDLD
OUT W130.05
LD TR0
LD W90.04
OR W260.04
ANDLD
AND H9.02
ANDNOT T0039
ANDNOT W260.05
ANDNOT W90.05
OUT W260.04
LD TR0
LD W260.04
AND P_0_2s
ORNOT H9.02
ANDLD
OUT W130.04
; rung 2243
LD W260.05
AND W374.15
OR H9.02
LDNOT W260.04
ORNOT W374.15
ANDLD
OUT H9.02
; rung 2244
LD W371.06
OUT TR0
LD W90.07
OR W260.07
ANDLD
ANDNOT H9.03
ANDNOT T0039
ANDNOT W260.06
ANDNOT W90.06
OUT W260.07
LD TR0
LD W260.07
AND P_0_2s
OR H9.03
ANDLD
OUT W130.07
LD TR0
LD W90.06
OR W260.06
ANDLD
AND H9.03
ANDNOT T0039
ANDNOT W260.07
ANDNOT W90.07
OUT W260.06
LD TR0
LD W260.06
AND P_0_2s
ORNOT H9.03
ANDLD
OUT W130.06
; rung 2245
LD W260.07
AND W374.15
OR H9.03
LDNOT W260.06
ORNOT W374.15
ANDLD
OUT H9.03

; rung 2246
LD W371.06
OUT TR0
LD W90.09
OR W260.09
ANDLD
ANDNOT H9.04
ANDNOT T0039
ANDNOT W260.08
ANDNOT W90.08
OUT W260.09
LD TR0
LD W260.09
AND P_0_2s
OR H9.04
ANDLD
OUT W130.09
LD TR0
LD W90.08
OR W260.08
ANDLD
AND H9.04
ANDNOT T0039
ANDNOT W260.09
ANDNOT W90.09
OUT W260.08
LD TR0
LD W260.08
AND P_0_2s
ORNOT H9.04
ANDLD
OUT W130.08
; rung 2247
LD W260.09
AND W374.15
OR H9.04
LDNOT W260.08
ORNOT W374.15
ANDLD
OUT H9.04
; rung 2248
LD W371.06
OUT TR0
LD W90.11
OR W260.11
ANDLD
ANDNOT H9.05
ANDNOT T0039
ANDNOT W260.10
ANDNOT W90.10
OUT W260.11
LD TR0
LD W260.11
AND P_0_2s
OR H9.05
ANDLD
OUT W130.11
LD TR0
LD W90.10
OR W260.10
ANDLD
AND H9.05
ANDNOT T0039
ANDNOT W260.11
ANDNOT W90.11
OUT W260.10
LD TR0
LD W260.10
AND P_0_2s
ORNOT H9.05
ANDLD
OUT W130.10
; rung 2249
LD W260.11
AND W374.15
OR H9.05
LDNOT W260.10
ORNOT W374.15
ANDLD
OUT H9.05

; rung 2250
LD W371.06
OUT TR0
LD W90.13
OR W260.13
ANDLD
ANDNOT H9.06
ANDNOT T0039
ANDNOT W260.12
ANDNOT W90.12
OUT W260.13
LD TR0
LD W260.13
AND P_0_2s
OR H9.06
ANDLD
OUT W130.13
LD TR0
LD W90.12
OR W260.12
ANDLD
AND H9.06
ANDNOT T0039
ANDNOT W260.13
ANDNOT W90.13
OUT W260.12
LD TR0
LD W260.12
AND P_0_2s
ORNOT H9.06
ANDLD
OUT W130.12
; rung 2251
LD W260.13
AND W374.15
OR H9.06
LDNOT W260.12
ORNOT W374.15
ANDLD
OUT H9.06
; rung 2252
LD W371.06
OUT TR0
LD W90.15
OR W260.15
ANDLD
ANDNOT H9.07
ANDNOT T0039
ANDNOT W260.14
ANDNOT W90.14
OUT W260.15
LD TR0
LD W260.15
AND P_0_2s
OR H9.07
ANDLD
OUT W130.15
LD TR0
LD W90.14
OR W260.14
ANDLD
AND H9.07
ANDNOT T0039
ANDNOT W260.15
ANDNOT W90.15
OUT W260.14
LD TR0
LD W260.14
AND P_0_2s
ORNOT H9.07
ANDLD
OUT W130.14
; rung 2253
LD W260.15
AND W374.15
OR H9.07
LDNOT W260.14
ORNOT W374.15
ANDLD
OUT H9.07
; rung 2254: ----- 動作11-1ﾓｰﾄﾞ選択 -----
LD W221.00
OR H11.00
ANDNOT W221.01
ANDNOT W221.02
OUT H11.00

; rung 2255
LD W221.01
OR H11.01
ANDNOT W221.00
ANDNOT W221.02
OUT H11.01
; rung 2256
LD W221.02
OR H11.02
ANDNOT W221.00
ANDNOT W221.01
OUT H11.02
; rung 2257: ----- 動作11-2ﾓｰﾄﾞ選択 -----
LD W221.03
OR H11.03
ANDNOT W221.04
ANDNOT W221.05
OUT H11.03
; rung 2258
LD W221.04
OR H11.04
ANDNOT W221.03
ANDNOT W221.05
OUT H11.04
; rung 2259
LD W221.05
OR H11.05
ANDNOT W221.03
ANDNOT W221.04
OUT H11.05
; rung 2260: ----- 動作11-3ﾓｰﾄﾞ選択 -----
LD W221.06
OR H11.06
ANDNOT W221.07
ANDNOT W221.08
OUT H11.06
; rung 2261
LD W221.07
OR H11.07
ANDNOT W221.06
ANDNOT W221.08
OUT H11.07
; rung 2262
LD W221.08
OR H11.08
ANDNOT W221.06
ANDNOT W221.07
OUT H11.08

; rung 2263: ----- 動作11-4ﾓｰﾄﾞ選択 -----
LD W221.09
OR H11.09
ANDNOT W221.10
ANDNOT W221.11
OUT H11.09
; rung 2264
LD W221.10
OR H11.10
ANDNOT W221.09
ANDNOT W221.11
OUT H11.10
; rung 2265
LD W221.11
OR H11.11
ANDNOT W221.09
ANDNOT W221.10
OUT H11.11
; rung 2266: ----- 動作11-5ﾓｰﾄﾞ選択 -----
LD W159.00
OR H11.12
ANDNOT W159.01
ANDNOT W159.02
OUT H11.12
; rung 2267
LD W159.01
OR H11.13
ANDNOT W159.00
ANDNOT W159.02
OUT H11.13
; rung 2268
LD W159.02
OR H11.14
ANDNOT W159.00
ANDNOT W159.01
OUT H11.14
; rung 2269: ----- 動作11-6ﾓｰﾄﾞ選択 -----
LD W159.03
OR H11.15
ANDNOT W159.04
ANDNOT W159.05
OUT H11.15
; rung 2270
LD W159.04
OR H12.00
ANDNOT W159.03
ANDNOT W159.05
OUT H12.00

; rung 2271
LD W159.05
OR H12.01
ANDNOT W159.03
ANDNOT W159.04
OUT H12.01
; rung 2272: ----- 動作11-7ﾓｰﾄﾞ選択 -----
LD W159.06
OR H12.02
ANDNOT W159.07
ANDNOT W159.08
OUT H12.02
; rung 2273
LD W159.07
OR H12.03
ANDNOT W159.06
ANDNOT W159.08
OUT H12.03
; rung 2274
LD W159.08
OR H12.04
ANDNOT W159.06
ANDNOT W159.07
OUT H12.04
; rung 2275: ----- 動作11-8ﾓｰﾄﾞ選択 -----
LD W159.09
OR H12.05
ANDNOT W159.10
ANDNOT W159.11
OUT H12.05
; rung 2276
LD W159.10
OR H12.06
ANDNOT W159.09
ANDNOT W159.11
OUT H12.06
; rung 2277
LD W159.11
OR H12.07
ANDNOT W159.09
ANDNOT W159.10
OUT H12.07
; rung 2278: ***** 動作選択12 *****
LD W379.05
AND W378.13
LD W378.14
OR W378.12
AND W379.01
ORLD
ANDNOT W509.15
OUT W371.07

; rung 2279
LD W371.07
OUT TR0
LD W91.01
OR W261.01
ANDLD
ANDNOT H9.08
ANDNOT T0039
ANDNOT W261.00
ANDNOT W91.00
OUT W261.01
LD TR0
LD W261.01
AND P_0_2s
OR H9.08
ANDLD
OUT W131.01
LD TR0
LD W91.00
OR W261.00
ANDLD
AND H9.08
ANDNOT T0039
ANDNOT W261.01
ANDNOT W91.01
OUT W261.00
LD TR0
LD W261.00
AND P_0_2s
ORNOT H9.08
ANDLD
OUT W131.00
; rung 2280
LD W261.01
AND W374.15
OR H9.08
LDNOT W261.00
ORNOT W374.15
ANDLD
OUT H9.08
; rung 2281
LD W371.07
OUT TR0
LD W91.03
OR W261.03
ANDLD
ANDNOT H9.09
ANDNOT T0039
ANDNOT W261.02
ANDNOT W91.02
OUT W261.03
LD TR0
LD W261.03
AND P_0_2s
OR H9.09
ANDLD
OUT W131.03
LD TR0
LD W91.02
OR W261.02
ANDLD
AND H9.09
ANDNOT T0039
ANDNOT W261.03
ANDNOT W91.03
OUT W261.02
LD TR0
LD W261.02
AND P_0_2s
ORNOT H9.09
ANDLD
OUT W131.02
; rung 2282
LD W261.03
AND W374.15
OR H9.09
LDNOT W261.02
ORNOT W374.15
ANDLD
OUT H9.09

; rung 2283
LD W371.07
OUT TR0
LD W91.05
OR W261.05
ANDLD
ANDNOT H9.10
ANDNOT T0039
ANDNOT W261.04
ANDNOT W91.04
OUT W261.05
LD TR0
LD W261.05
AND P_0_2s
OR H9.10
ANDLD
OUT W131.05
LD TR0
LD W91.04
OR W261.04
ANDLD
AND H9.10
ANDNOT T0039
ANDNOT W261.05
ANDNOT W91.05
OUT W261.04
LD TR0
LD W261.04
AND P_0_2s
ORNOT H9.10
ANDLD
OUT W131.04
; rung 2284
LD W261.05
AND W374.15
OR H9.10
LDNOT W261.04
ORNOT W374.15
ANDLD
OUT H9.10
; rung 2285
LD W371.07
OUT TR0
LD W91.07
OR W261.07
ANDLD
ANDNOT H9.11
ANDNOT T0039
ANDNOT W261.06
ANDNOT W91.06
OUT W261.07
LD TR0
LD W261.07
AND P_0_2s
OR H9.11
ANDLD
OUT W131.07
LD TR0
LD W91.06
OR W261.06
ANDLD
AND H9.11
ANDNOT T0039
ANDNOT W261.07
ANDNOT W91.07
OUT W261.06
LD TR0
LD W261.06
AND P_0_2s
ORNOT H9.11
ANDLD
OUT W131.06
; rung 2286
LD W261.07
AND W374.15
OR H9.11
LDNOT W261.06
ORNOT W374.15
ANDLD
OUT H9.11

; rung 2287
LD W371.07
OUT TR0
LD W91.09
OR W261.09
ANDLD
ANDNOT H9.12
ANDNOT T0039
ANDNOT W261.08
ANDNOT W91.08
OUT W261.09
LD TR0
LD W261.09
AND P_0_2s
OR H9.12
ANDLD
OUT W131.09
LD TR0
LD W91.08
OR W261.08
ANDLD
AND H9.12
ANDNOT T0039
ANDNOT W261.09
ANDNOT W91.09
OUT W261.08
LD TR0
LD W261.08
AND P_0_2s
ORNOT H9.12
ANDLD
OUT W131.08
; rung 2288
LD W261.09
AND W374.15
OR H9.12
LDNOT W261.08
ORNOT W374.15
ANDLD
OUT H9.12
; rung 2289
LD W371.07
OUT TR0
LD W91.11
OR W261.11
ANDLD
ANDNOT H9.13
ANDNOT T0039
ANDNOT W261.10
ANDNOT W91.10
OUT W261.11
LD TR0
LD W261.11
AND P_0_2s
OR H9.13
ANDLD
OUT W131.11
LD TR0
LD W91.10
OR W261.10
ANDLD
AND H9.13
ANDNOT T0039
ANDNOT W261.11
ANDNOT W91.11
OUT W261.10
LD TR0
LD W261.10
AND P_0_2s
ORNOT H9.13
ANDLD
OUT W131.10
; rung 2290
LD W261.11
AND W374.15
OR H9.13
LDNOT W261.10
ORNOT W374.15
ANDLD
OUT H9.13

; rung 2291
LD W371.07
OUT TR0
LD W91.13
OR W261.13
ANDLD
ANDNOT H9.14
ANDNOT T0039
ANDNOT W261.12
ANDNOT W91.12
OUT W261.13
LD TR0
LD W261.13
AND P_0_2s
OR H9.14
ANDLD
OUT W131.13
LD TR0
LD W91.12
OR W261.12
ANDLD
AND H9.14
ANDNOT T0039
ANDNOT W261.13
ANDNOT W91.13
OUT W261.12
LD TR0
LD W261.12
AND P_0_2s
ORNOT H9.14
ANDLD
OUT W131.12
; rung 2292
LD W261.13
AND W374.15
OR H9.14
LDNOT W261.12
ORNOT W374.15
ANDLD
OUT H9.14
; rung 2293
LD W371.07
OUT TR0
LD W91.15
OR W261.15
ANDLD
ANDNOT H9.15
ANDNOT T0039
ANDNOT W261.14
ANDNOT W91.14
OUT W261.15
LD TR0
LD W261.15
AND P_0_2s
OR H9.15
ANDLD
OUT W131.15
LD TR0
LD W91.14
OR W261.14
ANDLD
AND H9.15
ANDNOT T0039
ANDNOT W261.15
ANDNOT W91.15
OUT W261.14
LD TR0
LD W261.14
AND P_0_2s
ORNOT H9.15
ANDLD
OUT W131.14
; rung 2294
LD W261.15
AND W374.15
OR H9.15
LDNOT W261.14
ORNOT W374.15
ANDLD
OUT H9.15
; rung 2295: ***** 動作選択13 *****
LD W379.05
AND W378.14
LD W378.15
AND W379.01
ORLD
LD W378.05
AND W379.04
ORLD
ANDNOT W509.15
OUT W374.00

; rung 2296
LD W374.00
OUT TR0
LD W92.01
OR W262.01
ANDLD
ANDNOT H5.00
ANDNOT T0039
ANDNOT W262.00
ANDNOT W92.00
OUT W262.01
LD TR0
LD W262.01
AND P_0_2s
OR H5.00
ANDLD
OUT W132.01
LD TR0
LD W92.00
OR W262.00
ANDLD
AND H5.00
ANDNOT T0039
ANDNOT W262.01
ANDNOT W92.01
OUT W262.00
LD TR0
LD W262.00
AND P_0_2s
ORNOT H5.00
ANDLD
OUT W132.00
; rung 2297
LD W262.01
AND W374.15
OR H5.00
LDNOT W262.00
ORNOT W374.15
ANDLD
OUT H5.00
; rung 2298
LD W374.00
OUT TR0
LD W92.03
OR W262.03
ANDLD
ANDNOT H5.01
ANDNOT T0039
ANDNOT W262.02
ANDNOT W92.02
OUT W262.03
LD TR0
LD W262.03
AND P_0_2s
OR H5.01
ANDLD
OUT W132.03
LD TR0
LD W92.02
OR W262.02
ANDLD
AND H5.01
ANDNOT T0039
ANDNOT W262.03
ANDNOT W92.03
OUT W262.02
LD TR0
LD W262.02
AND P_0_2s
ORNOT H5.01
ANDLD
OUT W132.02
; rung 2299
LD W262.03
AND W374.15
OR H5.01
LDNOT W262.02
ORNOT W374.15
ANDLD
OUT H5.01

; rung 2300
LD W374.00
OUT TR0
LD W92.05
OR W262.05
ANDLD
ANDNOT H5.02
ANDNOT T0039
ANDNOT W262.04
ANDNOT W92.04
OUT W262.05
LD TR0
LD W262.05
AND P_0_2s
OR H5.02
ANDLD
OUT W132.05
LD TR0
LD W92.04
OR W262.04
ANDLD
AND H5.02
ANDNOT T0039
ANDNOT W262.05
ANDNOT W92.05
OUT W262.04
LD TR0
LD W262.04
AND P_0_2s
ORNOT H5.02
ANDLD
OUT W132.04
; rung 2301
LD W262.05
AND W374.15
OR H5.02
LDNOT W262.04
ORNOT W374.15
ANDLD
OUT H5.02
; rung 2302
LD W374.00
OUT TR0
LD W92.07
OR W262.07
ANDLD
ANDNOT H5.03
ANDNOT T0039
ANDNOT W262.06
ANDNOT W92.06
OUT W262.07
LD TR0
LD W262.07
AND P_0_2s
OR H5.03
ANDLD
OUT W132.07
LD TR0
LD W92.06
OR W262.06
ANDLD
AND H5.03
ANDNOT T0039
ANDNOT W262.07
ANDNOT W92.07
OUT W262.06
LD TR0
LD W262.06
AND P_0_2s
ORNOT H5.03
ANDLD
OUT W132.06
; rung 2303
LD W262.07
AND W374.15
OR H5.03
LDNOT W262.06
ORNOT W374.15
ANDLD
OUT H5.03

; rung 2304
LD W374.00
OUT TR0
LD W92.09
OR W262.09
ANDLD
ANDNOT H5.04
ANDNOT T0039
ANDNOT W262.08
ANDNOT W92.08
OUT W262.09
LD TR0
LD W262.09
AND P_0_2s
OR H5.04
ANDLD
OUT W132.09
LD TR0
LD W92.08
OR W262.08
ANDLD
AND H5.04
ANDNOT T0039
ANDNOT W262.09
ANDNOT W92.09
OUT W262.08
LD TR0
LD W262.08
AND P_0_2s
ORNOT H5.04
ANDLD
OUT W132.08
; rung 2305
LD W262.09
AND W374.15
OR H5.04
LDNOT W262.08
ORNOT W374.15
ANDLD
OUT H5.04
; rung 2306
LD W374.00
OUT TR0
LD W92.11
OR W262.11
ANDLD
ANDNOT H5.05
ANDNOT T0039
ANDNOT W262.10
ANDNOT W92.10
OUT W262.11
LD TR0
LD W262.11
AND P_0_2s
OR H5.05
ANDLD
OUT W132.11
LD TR0
LD W92.10
OR W262.10
ANDLD
AND H5.05
ANDNOT T0039
ANDNOT W262.11
ANDNOT W92.11
OUT W262.10
LD TR0
LD W262.10
AND P_0_2s
ORNOT H5.05
ANDLD
OUT W132.10
; rung 2307
LD W262.11
AND W374.15
OR H5.05
LDNOT W262.10
ORNOT W374.15
ANDLD
OUT H5.05

; rung 2308
LD W374.00
OUT TR0
LD W92.13
OR W262.13
ANDLD
ANDNOT H5.06
ANDNOT T0039
ANDNOT W262.12
ANDNOT W92.12
OUT W262.13
LD TR0
LD W262.13
AND P_0_2s
OR H5.06
ANDLD
OUT W132.13
LD TR0
LD W92.12
OR W262.12
ANDLD
AND H5.06
ANDNOT T0039
ANDNOT W262.13
ANDNOT W92.13
OUT W262.12
LD TR0
LD W262.12
AND P_0_2s
ORNOT H5.06
ANDLD
OUT W132.12
; rung 2309
LD W262.13
AND W374.15
OR H5.06
LDNOT W262.12
ORNOT W374.15
ANDLD
OUT H5.06
; rung 2310
LD W374.00
OUT TR0
LD W92.15
OR W262.15
ANDLD
ANDNOT H5.07
ANDNOT T0039
ANDNOT W262.14
ANDNOT W92.14
OUT W262.15
LD TR0
LD W262.15
AND P_0_2s
OR H5.07
ANDLD
OUT W132.15
LD TR0
LD W92.14
OR W262.14
ANDLD
AND H5.07
ANDNOT T0039
ANDNOT W262.15
ANDNOT W92.15
OUT W262.14
LD TR0
LD W262.14
AND P_0_2s
ORNOT H5.07
ANDLD
OUT W132.14
; rung 2311
LD W262.15
AND W374.15
OR H5.07
LDNOT W262.14
ORNOT W374.15
ANDLD
OUT H5.07
; rung 2312: ***** 動作選択14 *****
LD W379.06
AND W378.03
LD W378.15
AND W379.01
ORLD
LD W378.05
AND W379.04
ORLD
ANDNOT W509.15
OUT W374.01

; rung 2313
LD W374.01
OUT TR0
LD W93.01
OR W263.01
ANDLD
ANDNOT H5.08
ANDNOT T0039
ANDNOT W263.00
ANDNOT W93.00
OUT W263.01
LD TR0
LD W263.01
AND P_0_2s
OR H5.08
ANDLD
OUT W133.01
LD TR0
LD W93.00
OR W263.00
ANDLD
AND H5.08
ANDNOT T0039
ANDNOT W263.01
ANDNOT W93.01
OUT W263.00
LD TR0
LD W263.00
AND P_0_2s
ORNOT H5.08
ANDLD
OUT W133.00
; rung 2314
LD W263.01
AND W374.15
OR H5.08
LDNOT W263.00
ORNOT W374.15
ANDLD
OUT H5.08
; rung 2315
LD W374.01
OUT TR0
LD W93.03
OR W263.03
ANDLD
ANDNOT H5.09
ANDNOT T0039
ANDNOT W263.02
ANDNOT W93.02
OUT W263.03
LD TR0
LD W263.03
AND P_0_2s
OR H5.09
ANDLD
OUT W133.03
LD TR0
LD W93.02
OR W263.02
ANDLD
AND H5.09
ANDNOT T0039
ANDNOT W263.03
ANDNOT W93.03
OUT W263.02
LD TR0
LD W263.02
AND P_0_2s
ORNOT H5.09
ANDLD
OUT W133.02
; rung 2316
LD W263.03
AND W374.15
OR H5.09
LDNOT W263.02
ORNOT W374.15
ANDLD
OUT H5.09

; rung 2317
LD W374.01
OUT TR0
LD W93.05
OR W263.05
ANDLD
ANDNOT H5.10
ANDNOT T0039
ANDNOT W263.04
ANDNOT W93.04
OUT W263.05
LD TR0
LD W263.05
AND P_0_2s
OR H5.10
ANDLD
OUT W133.05
LD TR0
LD W93.04
OR W263.04
ANDLD
AND H5.10
ANDNOT T0039
ANDNOT W263.05
ANDNOT W93.05
OUT W263.04
LD TR0
LD W263.04
AND P_0_2s
ORNOT H5.10
ANDLD
OUT W133.04
; rung 2318
LD W263.05
AND W374.15
OR H5.10
LDNOT W263.04
ORNOT W374.15
ANDLD
OUT H5.10
; rung 2319
LD W374.01
OUT TR0
LD W93.07
OR W263.07
ANDLD
ANDNOT H5.11
ANDNOT T0039
ANDNOT W263.06
ANDNOT W93.06
OUT W263.07
LD TR0
LD W263.07
AND P_0_2s
OR H5.11
ANDLD
OUT W133.07
LD TR0
LD W93.06
OR W263.06
ANDLD
AND H5.11
ANDNOT T0039
ANDNOT W263.07
ANDNOT W93.07
OUT W263.06
LD TR0
LD W263.06
AND P_0_2s
ORNOT H5.11
ANDLD
OUT W133.06
; rung 2320
LD W263.07
AND W374.15
OR H5.11
LDNOT W263.06
ORNOT W374.15
ANDLD
OUT H5.11

; rung 2321
LD W374.01
OUT TR0
LD W93.09
OR W263.09
ANDLD
ANDNOT H5.12
ANDNOT T0039
ANDNOT W263.08
ANDNOT W93.08
OUT W263.09
LD TR0
LD W263.09
AND P_0_2s
OR H5.12
ANDLD
OUT W133.09
LD TR0
LD W93.08
OR W263.08
ANDLD
AND H5.12
ANDNOT T0039
ANDNOT W263.09
ANDNOT W93.09
OUT W263.08
LD TR0
LD W263.08
AND P_0_2s
ORNOT H5.12
ANDLD
OUT W133.08
; rung 2322
LD W263.09
AND W374.15
OR H5.12
LDNOT W263.08
ORNOT W374.15
ANDLD
OUT H5.12
; rung 2323
LD W374.01
OUT TR0
LD W93.11
OR W263.11
ANDLD
ANDNOT H5.13
ANDNOT T0039
ANDNOT W263.10
ANDNOT W93.10
OUT W263.11
LD TR0
LD W263.11
AND P_0_2s
OR H5.13
ANDLD
OUT W133.11
LD TR0
LD W93.10
OR W263.10
ANDLD
AND H5.13
ANDNOT T0039
ANDNOT W263.11
ANDNOT W93.11
OUT W263.10
LD TR0
LD W263.10
AND P_0_2s
ORNOT H5.13
ANDLD
OUT W133.10
; rung 2324
LD W263.11
AND W374.15
OR H5.13
LDNOT W263.10
ORNOT W374.15
ANDLD
OUT H5.13

; rung 2325
LD W374.01
OUT TR0
LD W93.13
OR W263.13
ANDLD
ANDNOT H5.14
ANDNOT T0039
ANDNOT W263.12
ANDNOT W93.12
OUT W263.13
LD TR0
LD W263.13
AND P_0_2s
OR H5.14
ANDLD
OUT W133.13
LD TR0
LD W93.12
OR W263.12
ANDLD
AND H5.14
ANDNOT T0039
ANDNOT W263.13
ANDNOT W93.13
OUT W263.12
LD TR0
LD W263.12
AND P_0_2s
ORNOT H5.14
ANDLD
OUT W133.12
; rung 2326
LD W263.13
AND W374.15
OR H5.14
LDNOT W263.12
ORNOT W374.15
ANDLD
OUT H5.14
; rung 2327
LD W374.01
OUT TR0
LD W93.15
OR W263.15
ANDLD
ANDNOT H5.15
ANDNOT T0039
ANDNOT W263.14
ANDNOT W93.14
OUT W263.15
LD TR0
LD W263.15
AND P_0_2s
OR H5.15
ANDLD
OUT W133.15
LD TR0
LD W93.14
OR W263.14
ANDLD
AND H5.15
ANDNOT T0039
ANDNOT W263.15
ANDNOT W93.15
OUT W263.14
LD TR0
LD W263.14
AND P_0_2s
ORNOT H5.15
ANDLD
OUT W133.14
; rung 2328
LD W263.15
AND W374.15
OR H5.15
LDNOT W263.14
ORNOT W374.15
ANDLD
OUT H5.15

; rung 2329
LD P_On
OUT TR0
LD W98.01
OR W264.01
ANDLD
ANDNOT H6.00
ANDNOT T0039
ANDNOT W264.00
ANDNOT W98.00
OUT W264.01
LD TR0
LD W264.01
AND P_0_2s
OR H6.00
ANDLD
OUT W134.01
LD TR0
LD W98.00
OR W264.00
ANDLD
AND H6.00
ANDNOT T0039
ANDNOT W264.01
ANDNOT W98.01
OUT W264.00
LD TR0
LD W264.00
AND P_0_2s
ORNOT H6.00
ANDLD
OUT W134.00
; rung 2330
LD W264.01
AND W374.15
OR H6.00
LDNOT W264.00
ORNOT W374.15
ANDLD
OUT H6.00
; rung 2331
LD P_On
OUT TR0
LD W98.03
OR W264.03
ANDLD
ANDNOT H6.01
ANDNOT T0039
ANDNOT W264.02
ANDNOT W98.02
OUT W264.03
LD TR0
LD W264.03
AND P_0_2s
OR H6.01
ANDLD
OUT W134.03
LD TR0
LD W98.02
OR W264.02
ANDLD
AND H6.01
ANDNOT T0039
ANDNOT W264.03
ANDNOT W98.03
OUT W264.02
LD TR0
LD W264.02
AND P_0_2s
ORNOT H6.01
ANDLD
OUT W134.02
; rung 2332
LD W264.03
AND W374.15
OR H6.01
LDNOT W264.02
ORNOT W374.15
ANDLD
OUT H6.01

; rung 2333
LD P_On
OUT TR0
LD W98.09
OR W264.09
ANDLD
ANDNOT H6.04
ANDNOT T0039
ANDNOT W264.08
ANDNOT W98.08
OUT W264.09
LD TR0
LD W264.09
AND P_0_2s
OR H6.04
ANDLD
OUT W134.09
LD TR0
LD W98.08
OR W264.08
ANDLD
AND H6.04
ANDNOT T0039
ANDNOT W264.09
ANDNOT W98.09
OUT W264.08
LD TR0
LD W264.08
AND P_0_2s
ORNOT H6.04
ANDLD
OUT W134.08
; rung 2334
LD W264.09
AND W374.15
OR H6.04
LDNOT W264.08
ORNOT W374.15
ANDLD
OUT H6.04
; rung 2335
LD P_On
OUT TR0
LD W98.05
OR W264.10
ANDLD
ANDNOT H6.04
ANDNOT W264.11
ANDNOT W98.04
OUT W264.10
LD TR0
LD W264.10
AND P_0_2s
OR W264.12
ANDLD
OUT W134.05  ; Kaeser BYPASS
LD TR0
LD W98.04
OR W264.11
ANDLD
AND W264.12
ANDNOT W264.10
ANDNOT W98.05
OUT W264.11
LD TR0
LD W264.11
AND P_0_2s
ORNOT W264.12
ANDLD
OUT W134.04
; rung 2336
LD W264.10
AND W374.15
OR W264.12
LDNOT W264.11
ORNOT W374.15
ANDLD
OUT W264.12
; rung 2337: ********** 左型開閉 ********** / 状態設定１項目を増やす場合以下定数#0010を増やす事
LD W358.00
@XFER(070) &10 D530 D260

; rung 2338
LD W379.05
AND W378.00
ANDNOT W509.15
OUT W361.14
; rung 2339: ***** 左型開閉調整処理 *****
LD P_On
AND=(300) W400 #50
OUT W197.12
; rung 2340
LD W396.10
OR W397.00
AND W170.13
ANDNOT W396.11
AND T0020
AND W197.12
OUT W397.00
; rung 2341
LD W397.00
AND W396.08
TIM 0510 #20
; rung 2342
LD T0510
@MOV(021) D594 D604
; rung 2343
LD W397.00
AND W396.09
TIM 0509 #20
; rung 2344
LD T0509
@MOV(021) D594 D602
; rung 2345
LD W397.00
MOV(021) #0 D601
MOV(021) D605 D603

; rung 2346
LD P_On
OUT TR0
MOV(021) 2002 D594
SCL(194) D594 D601 D600
AND<=(315) D600 #0
MOV(021) #0 D600
LD TR0
AND<(310) D605 D600
MOV(021) D605 D600
LD TR0
MOV(021) D600 D596
; rung 2347: ----- 型開設定値大小関係CHECK ----- / 型開≦予備型閉／型開≦型開高速／型開≦打込／型開≦吹込／型開≦予備３／型開≦予備４
LD W361.14
OUT TR0
CMP(020) D530 D261
LD P_GT
OR W372.00
ANDLD
ANDNOT T0070
OUT W372.00
LD TR0
LD P_EQ
OR P_LT
ANDLD
OUT W372.01
LD TR0
CMP(020) D530 D262
LD P_GT
OR W198.00
ANDLD
ANDNOT T0070
OUT W198.00
LD TR0
LD P_EQ
OR P_LT
ANDLD
OUT W199.07

; rung 2348
LD W361.14
OUT TR0
CMP(020) D530 D266
LD P_GT
OR W199.08
ANDLD
ANDNOT T0070
OUT W199.08
LD TR0
LD P_EQ
OR P_LT
ANDLD
OUT W199.09
LD TR0
CMP(020) D530 D267
LD P_GT
OR W199.10
ANDLD
ANDNOT T0070
OUT W199.10
LD TR0
LD P_EQ
OR P_LT
ANDLD
OUT W199.11
; rung 2349
LD W361.14
OUT TR0
CMP(020) D530 D268
LD P_GT
OR W199.12
ANDLD
ANDNOT T0070
OUT W199.12
LD TR0
LD P_LT
OR P_EQ
ANDLD
OUT W199.13
LD TR0
CMP(020) D530 D269  // 本項目型開制限として大小関係外している
LD P_GT
OR W199.14
ANDLD
ANDNOT T0070
ANDNOT P_On
OUT W199.14  // 注意！！
LD TR0
LD P_LT
OR P_EQ
OR P_On
ANDLD
OUT W199.15  // 注意！！

; rung 2350
LD W361.14
OUT TR0
LD W372.00
OR W198.00
OR W199.08
OR W199.10
OR W199.12
OR W199.14
ANDLD
MOV(021) D260 D530
LD TR0
AND W372.01
AND W199.07
AND W199.09
AND W199.11
AND W199.13
AND W199.15
MOV(021) D530 D260
; rung 2351: ----- 予備型閉設定値大小関係CHECK ----- / 予備型閉≦型閉徐行／型開≦予備型閉
LD W361.14
OUT TR0
CMP(020) D531 D263
LD P_GT
OR W372.02
ANDLD
ANDNOT T0070
OUT W372.02
LD TR0
LD P_EQ
OR P_LT
ANDLD
OUT W372.03
LD TR0
CMP(020) D260 D531
LD P_GT
OR W372.02
OR W198.01
ANDLD
MOV(021) D261 D531
ANDNOT T0070
OUT W198.01
LD TR0
LD P_EQ
OR P_LT
ANDLD
AND W372.03
MOV(021) D531 D261

; rung 2352: ----- 型閉徐行設定値大小関係CHECK ----- / 型閉徐行≦型閉／予備型閉≦型閉徐行
LD W361.14
OUT TR0
CMP(020) D533 D264
LD P_GT
OR W372.04
ANDLD
ANDNOT T0070
OUT W372.04
LD TR0
LD P_EQ
OR P_LT
ANDLD
OUT W372.05
LD TR0
CMP(020) D261 D533
LD P_GT
OR W372.04
OR W198.03
ANDLD
MOV(021) D263 D533
ANDNOT T0070
OUT W198.03
LD TR0
LD P_EQ
OR P_LT
ANDLD
AND W372.05
MOV(021) D533 D263
; rung 2353: ----- 型閉設定値大小関係CHECK ----- / 型閉徐行≦型閉／割型開≦型閉／打込≦型閉／吹込≦型閉／予備３≦型閉／予備４≦型閉
LD W361.14
OUT TR0
CMP(020) D263 D534
LD P_GT
OR W372.06
ANDLD
ANDNOT T0070
OUT W372.06
LD TR0
LD P_EQ
OR P_LT
ANDLD
OUT W372.07
LD TR0
CMP(020) D265 D534
LD P_GT
OR W372.12
ANDLD
ANDNOT T0070
OUT W372.12
LD TR0
LD P_EQ
OR P_LT
ANDLD
OUT W199.00

; rung 2354
LD W361.14
OUT TR0
CMP(020) D266 D534
LD P_GT
OR W199.01
ANDLD
ANDNOT T0070
OUT W199.01
LD TR0
LD P_LT
OR P_EQ
ANDLD
OUT W199.02
LD TR0
CMP(020) D267 D534
LD P_GT
OR W199.03
ANDLD
ANDNOT T0070
OUT W199.03
LD TR0
LD P_LT
OR P_EQ
ANDLD
OUT W199.04
; rung 2355
LD W361.14
OUT TR0
CMP(020) D268 D534
LD P_GT
OR W199.05
ANDLD
ANDNOT T0070
OUT W199.05
LD TR0
LD P_LT
OR P_EQ
ANDLD
OUT W199.06
LD TR0
CMP(020) D269 D534  // 本項目、型開制限として大小関係外してある
LD P_GT
OR W197.10
ANDLD
ANDNOT T0070
ANDNOT P_On
OUT W197.10  // 注意！！
LD TR0
LD P_LT
OR P_EQ
OR P_On
ANDLD
OUT W197.11  // 注意！！

; rung 2356
LD W361.14
OUT TR0
LD W372.06
OR W372.12
OR W199.01
OR W199.03
OR W199.05
OR W197.10
ANDLD
MOV(021) D264 D534
LD TR0
AND W372.07
AND W199.00
AND W199.02
AND W199.04
AND W199.06
AND W197.11
MOV(021) D534 D264
; rung 2357
LD W361.14
CMP(020) D534 D605
LD P_EQ
OR P_GT
ANDLD
MOV(021) D605 D534
; rung 2358: ----- 型開高速設定値大小関係CHECK ----- / 型開高速≦割型開／型開≦型開高速
LD W361.14
OUT TR0
CMP(020) D532 D265
LD P_GT
OR W372.08
ANDLD
ANDNOT T0070
OUT W372.08
LD TR0
LD P_EQ
OR P_LT
ANDLD
OUT W372.09
LD TR0
CMP(020) D260 D532
LD P_GT
OR W372.08
OR W198.02
ANDLD
MOV(021) D262 D532
ANDNOT T0070
OUT W198.02
LD TR0
LD P_EQ
OR P_LT
ANDLD
AND W372.09
MOV(021) D532 D262

; rung 2359: ----- 割型閉位置設定値大小関係CHECK ----- / 割型開≦型閉／型開高速≦割型開
LD W361.14
OUT TR0
CMP(020) D535 D264
LD P_GT
OR W372.14
ANDLD
ANDNOT T0070
OUT W372.14
LD TR0
LD P_EQ
OR P_LT
ANDLD
OUT W372.15
LD TR0
CMP(020) D262 D535
LD P_GT
OR W372.14
OR W198.05
ANDLD
MOV(021) D265 D535
ANDNOT T0070
OUT W198.05
LD TR0
LD P_EQ
OR P_LT
ANDLD
AND W372.15
MOV(021) D535 D265
; rung 2360: ----- 左打込設定値大小関係CHECK ----- / 型開≦打込／打込≦型閉
LD W361.14
OUT TR0
CMP(020) D536 D264
LD P_GT
OR W198.06
ANDLD
ANDNOT T0070
OUT W198.06
LD TR0
LD P_EQ
OR P_LT
ANDLD
OUT W198.07
LD TR0
CMP(020) D260 D536
LD P_GT
OR W198.06
OR W198.08
ANDLD
MOV(021) D266 D536
ANDNOT T0070
OUT W198.08
LD TR0
LD P_EQ
OR P_LT
ANDLD
AND W198.07
MOV(021) D536 D266

; rung 2361: ----- 左吹込設定値大小関係CHECK ----- / 型開≦吹込／吹込≦型閉
LD W361.14
OUT TR0
CMP(020) D537 D264
LD P_GT
OR W198.09
ANDLD
ANDNOT T0070
OUT W198.09
LD TR0
LD P_EQ
OR P_LT
ANDLD
OUT W198.10
LD TR0
CMP(020) D260 D537
LD P_GT
OR W198.09
OR W198.11
ANDLD
MOV(021) D267 D537
ANDNOT T0070
OUT W198.11
LD TR0
LD P_EQ
OR P_LT
ANDLD
AND W198.10
MOV(021) D537 D267
; rung 2362: ----- 予備３設定値大小関係CHECK ---- / 型開≦予備３／予備３≦型閉
LD W361.14
OUT TR0
CMP(020) D538 D264
LD P_GT
OR W198.12
ANDLD
ANDNOT T0070
OUT W198.12
LD TR0
LD P_EQ
OR P_LT
ANDLD
OUT W198.13
LD TR0
CMP(020) D260 D538
LD P_GT
OR W198.12
OR W198.14
ANDLD
MOV(021) D268 D538
ANDNOT T0070
OUT W198.14
LD TR0
LD P_EQ
OR P_LT
ANDLD
AND W198.13
MOV(021) D538 D268

; rung 2363: ----- 予備４設定値大小関係CHECK ---- / 型開≦予備／予備≦型閉 / 本工事では型開制限位置として使用。位置大小関係を見ていないので注意！！
LD W361.14
ANDNOT P_On
OUT TR0
CMP(020) D539 D264
LD P_GT
OR W197.07
ANDLD
ANDNOT T0070
OUT W197.07
LD TR0
LD P_EQ
OR P_LT
ANDLD
OUT W197.08
LD TR0
CMP(020) D260 D539
LD P_GT
OR W197.07
OR W197.09
ANDLD
MOV(021) D269 D539
ANDNOT T0070
OUT W197.09
LD TR0
LD P_EQ
OR P_LT
ANDLD
AND W197.08
MOV(021) D539 D269
; rung 2364
LDNOT W372.00
ANDNOT W198.00
ANDNOT W372.02
ANDNOT W198.01
ANDNOT W372.04
ANDNOT W198.02
ANDNOT W372.06
ANDNOT W198.03
ANDNOT W372.08
ANDNOT W372.12
ANDNOT W372.14
ANDNOT W198.05
ANDNOT W198.06
ANDNOT W198.08
ANDNOT W198.09
ANDNOT W198.11
ANDNOT W198.12
ANDNOT W198.14
ANDNOT W197.07
ANDNOT W197.09
ANDNOT W199.08
ANDNOT W199.10
ANDNOT W199.12
ANDNOT W199.14
ANDNOT W199.01
ANDNOT W199.03
ANDNOT W199.05
ANDNOT W197.10
OUTNOT W197.06
; rung 2365
LD W197.06
AND W361.14
TIM 0070 #20
; rung 2366: ----- 現在位置判別 -----
LD P_On
OUT TR0
AND>=(325) D260 D600  // 型開位置(通常)比較
OUT W197.01
LD TR0
AND>=(325) #70 D600  // 型前回位置(5.0mm)比較
OUT W197.02
LD TR0
AND>=(325) #300 D600  // 型開許可範囲(ﾌﾟﾗﾃﾝｱﾝﾛｯｸ以外型開許可範囲30.0mm）
OUT W197.00

; rung 2367
LD 16.09
OR W170.09
AND W197.01
ANDNOT H1.01
ANDNOT H1.05
LD 16.08
OR H1.05
OR H1.01
AND W197.02
ORLD
OUT W223.00
; rung 2368
LD P_On
OUT TR0
CMP(020) D261 #300
LD P_EQ
OR P_GT
ANDLD
CLC(041)
-BC(416) D261 #300 D291
LD TR0
AND P_LT
MOV(021) #0 D291
; rung 2369
LD P_On
OUT TR0
AND<=(315) D291 D600
ANDNOT W223.01
OUT W180.15
LD TR0
LD<=(315) D261 D600
LDNOT P_On
AND>(320) D600 #780
AND<(310) D600 #850
ORLD
OR W223.01
ANDLD
ANDNOT W182.02
ANDNOT W182.03
ANDNOT W165.15
OUT TR1
AND T0110
OUT W223.01
LD TR1
TIM 0110 #0
LD TR0
AND>=(325) D262 D600
ANDNOT W189.01
ANDNOT W183.07
ANDNOT W183.00
ANDNOT W183.03
ANDNOT W53.00
OUT W223.02
LD TR0
MOV(021) D600 D549
; rung 2370
LD P_On
CLC(041)
-BC(416) D263 #300 D292
AND<=(315) D292 D600
ANDNOT W223.03
OUT W181.10

; rung 2371
LD P_On
OUT TR0
AND<=(315) D263 D600
OUT W223.03
LD TR0
AND<=(315) D264 D600
OUT W223.04
LD TR0
AND>=(325) #1000 D600
OUT W197.04
LD TR0
AND>=(325) #20 D600
OUT W197.05
LD TR0
AND>=(325) D265 D600
ANDNOT W189.01
ANDNOT W183.07
ANDNOT W183.00
ANDNOT W183.03
ANDNOT W53.00
OUT W223.05
; rung 2372
LD P_On
CLC(041)
+BC(406) D530 #500 D595
; rung 2373
LD P_On
OUT TR0
LD W170.09
OR 16.09
ANDLD
CMP(020) D595 D600
LD TR0
AND 16.08
CMP(020) #500 D600
LD TR0
LD P_GT
OR P_EQ
ANDLD
OUT W197.03
; rung 2374
LD P_On
OUT TR0
AND<=(315) D266 D600
OUT W223.06
LD TR0
AND<=(315) D267 D600
ANDNOT W182.02
ANDNOT W182.03
ANDNOT W165.15
OUT W223.07
LD TR0
AND<=(315) D268 D600
OUT W223.08
; rung 2375: ********** 右型開閉 **********
LD W358.00
@XFER(070) &10 D560 D250

; rung 2376: ***** 右型開閉調整処理 *****
LD P_On
AND=(300) W400 #51
OUT W194.12
; rung 2377
LD W397.06
OR W397.12
AND W170.13
ANDNOT W397.07
AND T0020
AND W194.12
OUT W397.12
; rung 2378
LD W397.12
AND W397.04
TIM 0507 #20
; rung 2379
LD T0507
@MOV(021) D597 D610
; rung 2380
LD W397.12
AND W397.05
TIM 0508 #20
; rung 2381
LD T0508
@MOV(021) D597 D608
; rung 2382
LD W397.12
MOV(021) #0 D607
MOV(021) D611 D609

; rung 2383
LD P_On
OUT TR0
MOV(021) 2004 D597
SCL(194) D597 D607 D606
AND<=(315) D606 #0
MOV(021) #0 D606
LD TR0
AND<(310) D611 D606
MOV(021) D611 D606
LD TR0
MOV(021) D606 D599
; rung 2384: ----- 型開設定値大小関係CHECK ----- / 型開≦予備型閉／型開≦型開高速／型開≦打込／型開≦吹込／型開≦予備３／型開≦予備４
LD W361.14
OUT TR0
CMP(020) D560 D251
LD P_GT
OR W373.00
ANDLD
ANDNOT T0060
OUT W373.00
LD TR0
LD P_EQ
OR P_LT
ANDLD
OUT W373.01
LD TR0
CMP(020) D560 D252
LD P_GT
OR W195.00
ANDLD
ANDNOT T0060
OUT W195.00
LD TR0
LD P_EQ
OR P_LT
ANDLD
OUT W196.07

; rung 2385
LD W361.14
OUT TR0
CMP(020) D560 D256
LD P_GT
OR W196.08
ANDLD
ANDNOT T0060
OUT W196.08
LD TR0
LD P_EQ
OR P_LT
ANDLD
OUT W196.09
LD TR0
CMP(020) D560 D257
LD P_GT
OR W196.10
ANDLD
ANDNOT T0060
OUT W196.10
LD TR0
LD P_EQ
OR P_LT
ANDLD
OUT W196.11
; rung 2386
LD W361.14
OUT TR0
CMP(020) D560 D258
LD P_GT
OR W196.12
ANDLD
ANDNOT T0060
OUT W196.12
LD TR0
LD P_LT
OR P_EQ
ANDLD
OUT W196.13
LD TR0
CMP(020) D560 D259  // 本項目、型開制限として大小関係外している
LD P_GT
OR W196.14
ANDLD
ANDNOT T0060
ANDNOT P_On
OUT W196.14  // 注意！！
LD TR0
LD P_LT
OR P_EQ
OR P_On
ANDLD
OUT W196.15  // 注意！！

; rung 2387
LD W361.14
OUT TR0
LD W373.00
OR W195.00
OR W196.08
OR W196.10
OR W196.12
OR W196.14
ANDLD
MOV(021) D250 D560
LD TR0
AND W373.01
AND W196.07
AND W196.09
AND W196.11
AND W196.13
AND W196.15
MOV(021) D560 D250
; rung 2388: '----- 予備型閉設定値大小関係CHECK ----- / 予備型閉≦型閉徐行／型開≦予備型閉
LD W361.14
OUT TR0
CMP(020) D561 D253
LD P_GT
OR W373.02
ANDLD
ANDNOT T0060
OUT W373.02
LD TR0
LD P_EQ
OR P_LT
ANDLD
OUT W373.03
LD TR0
CMP(020) D250 D561
LD P_GT
OR W373.02
OR W195.01
ANDLD
MOV(021) D251 D561
ANDNOT T0060
OUT W195.01
LD TR0
LD P_EQ
OR P_LT
ANDLD
AND W373.03
MOV(021) D561 D251

; rung 2389: ----- 型閉徐行設定値大小関係CHECK ----- / 型閉徐行≦型閉／予備型閉≦型閉徐行
LD W361.14
OUT TR0
CMP(020) D563 D254
LD P_GT
OR W373.04
ANDLD
ANDNOT T0060
OUT W373.04
LD TR0
LD P_EQ
OR P_LT
ANDLD
OUT W373.05
LD TR0
CMP(020) D251 D563
LD P_GT
OR W373.04
OR W195.03
ANDLD
MOV(021) D253 D563
ANDNOT T0060
OUT W195.03
LD TR0
LD P_EQ
OR P_LT
ANDLD
AND W373.05
MOV(021) D563 D253
; rung 2390: ----- 型閉設定値大小関係CHECK ----- / 型閉徐行≦型閉／割型開≦型閉／打込≦型閉／吹込≦型閉／予備３≦型閉／予備４≦型閉
LD W361.14
OUT TR0
CMP(020) D253 D564
LD P_GT
OR W372.06
ANDLD
ANDNOT T0060
OUT W373.06
LD TR0
LD P_EQ
OR P_LT
ANDLD
OUT W373.07
LD TR0
CMP(020) D255 D564
LD P_GT
OR W373.12
ANDLD
ANDNOT T0060
OUT W373.12
LD TR0
LD P_EQ
OR P_LT
ANDLD
OUT W196.00

; rung 2391
LD W361.14
OUT TR0
CMP(020) D256 D564
LD P_GT
OR W196.01
ANDLD
ANDNOT T0060
OUT W196.01
LD TR0
LD P_LT
OR P_EQ
ANDLD
OUT W196.02
LD TR0
CMP(020) D257 D564
LD P_GT
OR W196.03
ANDLD
ANDNOT T0060
OUT W196.03
LD TR0
LD P_LT
OR P_EQ
ANDLD
OUT W196.04
; rung 2392
LD W361.14
OUT TR0
CMP(020) D258 D564
LD P_GT
OR W196.05
ANDLD
ANDNOT T0060
OUT W196.05
LD TR0
LD P_LT
OR P_EQ
ANDLD
OUT W196.06
LD TR0
CMP(020) D259 D564  // 本項目、型開制限として大小関係外してある
LD P_GT
OR W194.10
ANDLD
ANDNOT T0060
ANDNOT P_On
OUT W194.10  // 注意！！
LD TR0
LD P_LT
OR P_EQ
OR P_On
ANDLD
OUT W194.11  // 注意！！

; rung 2393
LD W361.14
OUT TR0
LD W373.06
OR W373.12
OR W196.01
OR W196.03
OR W196.05
OR W194.10
ANDLD
MOV(021) D254 D564
LD TR0
AND W373.07
AND W196.00
AND W196.02
AND W196.04
AND W196.06
AND W194.11
MOV(021) D564 D254
; rung 2394: ----- 型開高速設定値大小関係CHECK ----- / 型開高速≦割型開／型開≦型開高速
LD W361.14
CMP(020) D564 D611
LD P_EQ
OR P_GT
ANDLD
MOV(021) D611 D564
; rung 2395
LD W361.14
OUT TR0
CMP(020) D562 D255
LD P_GT
OR W373.08
ANDLD
ANDNOT T0060
OUT W373.08
LD TR0
LD P_EQ
OR P_LT
ANDLD
OUT W373.09
LD TR0
CMP(020) D250 D562
LD P_GT
OR W373.08
OR W195.02
ANDLD
MOV(021) D252 D562
ANDNOT T0070
OUT W195.02
LD TR0
LD P_EQ
OR P_LT
ANDLD
AND W373.09
MOV(021) D562 D252

; rung 2396: ----- 割型開位置設定値大小関係CHECK ----- / 割型開≦型閉／型開高速≦割型開
LD W361.14
OUT TR0
CMP(020) D565 D254
LD P_GT
OR W373.14
ANDLD
ANDNOT T0060
OUT W373.14
LD TR0
LD P_EQ
OR P_LT
ANDLD
OUT W373.15
LD TR0
CMP(020) D252 D565
LD P_GT
OR W373.14
OR W195.05
ANDLD
MOV(021) D255 D565
ANDNOT T0060
OUT W195.05
LD TR0
LD P_EQ
OR P_LT
ANDLD
AND W373.15
MOV(021) D565 D255
; rung 2397: ----- 打込位置設定値大小関係CHECK -----
LD W361.14
OUT TR0
CMP(020) D566 D254
LD P_GT
OR W195.06
ANDLD
ANDNOT T0060
OUT W195.06
LD TR0
LD P_EQ
OR P_LT
ANDLD
OUT W195.07
LD TR0
CMP(020) D250 D566
LD P_GT
OR W195.06
OR W195.08
ANDLD
MOV(021) D256 D566
ANDNOT T0060
OUT W195.08
LD TR0
LD P_EQ
OR P_LT
ANDLD
AND W195.07
MOV(021) D566 D256

; rung 2398: ----- 吹込設定値大小関係CHECK ----- / 型開≦吹込／吹込≦型閉
LD W361.14
OUT TR0
CMP(020) D567 D254
LD P_GT
OR W195.09
ANDLD
ANDNOT T0060
OUT W195.09
LD TR0
LD P_EQ
OR P_LT
ANDLD
OUT W195.10
LD TR0
CMP(020) D250 D567
LD P_GT
OR W195.09
OR W195.11
ANDLD
MOV(021) D257 D567
ANDNOT T0060
OUT W195.11
LD TR0
LD P_EQ
OR P_LT
ANDLD
AND W195.10
MOV(021) D567 D257
; rung 2399: ----- 予備３設定値大小関係CHECK ----- / 型開≦予備３／予備３≦型閉
LD W361.14
OUT TR0
CMP(020) D568 D254
LD P_GT
OR W195.12
ANDLD
ANDNOT T0060
OUT W195.12
LD TR0
LD P_EQ
OR P_LT
ANDLD
OUT W195.13
LD TR0
CMP(020) D250 D568
LD P_GT
OR W195.12
OR W195.14
ANDLD
MOV(021) D258 D568
ANDNOT T0060
OUT W195.14
LD TR0
LD P_EQ
OR P_LT
ANDLD
AND W195.13
MOV(021) D568 D258

; rung 2400: ----- 予備設定値大小関係CHECK ----- / 型開≦予備／予備≦型閉 / 本工事では型開制限位置として使用。位置大小関係を見ていないので注意！！
LD W361.14
ANDNOT P_On
OUT TR0
CMP(020) D569 D254
LD P_GT
OR W194.07
ANDLD
ANDNOT T0060
OUT W194.07
LD TR0
LD P_EQ
OR P_LT
ANDLD
OUT W194.08
LD TR0
CMP(020) D250 D569
LD P_GT
OR W194.07
OR W194.09
ANDLD
MOV(021) D259 D569
ANDNOT T0060
OUT W194.09
LD TR0
LD P_EQ
OR P_LT
ANDLD
AND W194.08
MOV(021) D569 D259
; rung 2401
LDNOT W373.00
ANDNOT W195.00
ANDNOT W373.02
ANDNOT W195.01
ANDNOT W373.04
ANDNOT W195.02
ANDNOT W373.06
ANDNOT W195.03
ANDNOT W373.08
ANDNOT W373.12
ANDNOT W373.14
ANDNOT W195.05
ANDNOT W195.06
ANDNOT W196.08
ANDNOT W195.09
ANDNOT W195.11
ANDNOT W195.12
ANDNOT W195.14
ANDNOT W194.07
ANDNOT W194.09
ANDNOT W196.08
ANDNOT W196.10
ANDNOT W196.12
ANDNOT W196.14
ANDNOT W196.01
ANDNOT W196.03
ANDNOT W196.05
ANDNOT W194.10
OUTNOT W194.06
; rung 2402
LD W194.06
AND W361.14
TIM 0060 #20
; rung 2403: ----- 現在位置判別 -----
LD P_On
OUT TR0
AND>=(325) D250 D606  // 型開位置(通常)比較
OUT W194.01
LD TR0
AND>=(325) #50 D606  // 型全開位置(5.0mm)比較
OUT W194.02
LD TR0
AND>=(325) #300 D606  // 型開許可範囲(ﾌﾟﾗﾃﾝｱﾝﾛｯｸ以外型開許可範囲30.0mm）
OUT W194.00

; rung 2404
LD 16.09
OR W170.09
AND W194.01
ANDNOT H1.01
ANDNOT H1.05
LD 16.08
OR H1.05
OR H1.01
AND W194.02
ORLD
OUT W224.13
; rung 2405
LD P_On
OUT TR0
CMP(020) D251 #300
LD P_EQ
OR P_GT
ANDLD
CLC(041)
-BC(416) D251 #300 D271
LD TR0
AND P_LT
MOV(021) #0 D271
; rung 2406
LD P_On
OUT TR0
AND<=(315) D271 D606
ANDNOT W224.14
OUT W310.15
LD TR0
LD<=(315) D251 D606
LDNOT P_Off
AND>(320) D606 #500
AND<(310) D606 #1000
ORLD
ANDLD
ANDNOT W312.02
ANDNOT W312.03
ANDNOT W166.15
OUT TR1
AND T0111
OUT W224.14
LD TR1
TIM 0111 #5
LD TR0
AND>=(325) D252 D606
ANDNOT W319.01
ANDNOT W313.07
ANDNOT W313.00
ANDNOT W313.03
ANDNOT W53.01
OUT W224.15
LD TR0
MOV(021) D606 D579
; rung 2407
LD P_On
CLC(041)
-BC(416) D253 #300 D272
AND<=(315) D272 D606
ANDNOT W225.00
OUT W311.10

; rung 2408
LD P_On
OUT TR0
AND<=(315) D253 D606
OUT W225.00
LD TR0
AND<=(315) D254 D606
OUT W225.01
LD TR0
AND>=(325) #1000 D606
OUT W194.04
LD TR0
AND>=(325) #20 D606
OUT W194.05
LD TR0
AND>=(325) D255 D606
ANDNOT W319.01
ANDNOT W313.07
ANDNOT W313.00
ANDNOT W313.03
ANDNOT W53.01
OUT W225.02
; rung 2409
LD P_On
CLC(041)
+BC(406) D560 #500 D598
; rung 2410
LD P_On
OUT TR0
LD W170.09
OR 16.09
ANDLD
CMP(020) D598 D606
LD TR0
AND 16.08
CMP(020) #500 D606
LD TR0
LD P_GT
OR P_EQ
ANDLD
OUT W194.03
; rung 2411
LD P_On
OUT TR0
AND<=(315) D256 D606
OUT W225.03
LD TR0
AND<=(315) D257 D606
ANDNOT W312.02
ANDNOT W312.03
ANDNOT W166.15
OUT W225.04
LD TR0
AND<=(315) D258 D606
OUT W225.05
; rung 2412: ********** ｽﾗｲﾀﾞ戻時型開制限処理 **********
LD W361.14
AND W221.14
AND W221.15
@MOV(021) #83 W400

; rung 2413
LD W379.05
AND W378.03
ANDNOT W509.15
OUT W226.14
; rung 2414
LDNOT W226.14
RSET W221.13
RSET W221.12
; rung 2415
LD W221.13
OUT W226.15
; rung 2416
LDNOT 458.00
ORNOT 458.01
ANDNOT W226.15
AND>=(325) D539 D549
OUT W226.13
; rung 2417
LD W221.12
OUT W226.12
; rung 2418
LDNOT 458.02
ORNOT 458.03
ANDNOT W226.12
AND>=(325) D569 D579
OUT W226.11
; rung 2419: ********** 金型内動作ｲﾝﾀｰﾛｯｸ処理 ********** 特殊仕様
LD W358.00
LD W378.06
OR W378.11
AND W379.14
ANDNOT W509.15
ORLD
OUT W307.11

; rung 2420
LD W307.11
MOV(021) H80 W3
COM(029) W3
MOV(021) H60 W16
COM(029) W16
MOV(021) H90 W4
COM(029) W4
MOV(021) H70 W17
COM(029) W17
; rung 2421: ---------- 左型開ｲﾝﾀｰﾛｯｸ有効範囲判別 ---------- / １号機は常時判別処理していたがｻｲｸﾙﾀｲﾑを短縮する為、INL.有効時のみ判別
LD H82.00
OUT TR0
AND>(320) D2400 D2401
MOV(021) D2400 D2401
LD TR0
AND>=(325) D549 D2400
AND<=(315) D549 D2401
OUT W5.00
; rung 2422
LD H82.01
OUT TR0
AND>(320) D2402 D2403
MOV(021) D2402 D2403
LD TR0
AND>=(325) D549 D2402
AND<=(315) D549 D2403
OUT W5.01
; rung 2423
LD H82.02
OUT TR0
AND>(320) D2404 D2405
MOV(021) D2404 D2405
LD TR0
AND>=(325) D549 D2404
AND<=(315) D549 D2405
OUT W5.02

; rung 2424
LD H82.03
OUT TR0
AND>(320) D2406 D2407
MOV(021) D2406 D2407
LD TR0
AND>=(325) D549 D2406
AND<=(315) D549 D2407
OUT W5.03
; rung 2425
LD H82.04
OUT TR0
AND>(320) D2408 D2409
MOV(021) D2408 D2409
LD TR0
AND>=(325) D549 D2408
AND<=(315) D549 D2409
OUT W5.04
; rung 2426
LD H82.05
OUT TR0
AND>(320) D2410 D2411
MOV(021) D2410 D2411
LD TR0
AND>=(325) D549 D2410
AND<=(315) D549 D2411
OUT W5.05
; rung 2427
LD H82.06
OUT TR0
AND>(320) D2412 D2413
MOV(021) D2412 D2413
LD TR0
AND>=(325) D549 D2412
AND<=(315) D549 D2413
OUT W5.06
; rung 2428
LD H82.07
OUT TR0
AND>(320) D2414 D2415
MOV(021) D2414 D2415
LD TR0
AND>=(325) D549 D2414
AND<=(315) D549 D2415
OUT W5.07
; rung 2429
LD H82.08
OUT TR0
AND>(320) D2416 D2417
MOV(021) D2416 D2417
LD TR0
AND>=(325) D549 D2416
AND<=(315) D549 D2417
OUT W5.08

; rung 2430
LD H82.09
OUT TR0
AND>(320) D2418 D2419
MOV(021) D2418 D2419
LD TR0
AND>=(325) D549 D2418
AND<=(315) D549 D2419
OUT W5.09
; rung 2431
LD H82.10
OUT TR0
AND>(320) D2420 D2421
MOV(021) D2420 D2421
LD TR0
AND>=(325) D549 D2420
AND<=(315) D549 D2421
OUT W5.10
; rung 2432
LD H82.11
OUT TR0
AND>(320) D2422 D2423
MOV(021) D2422 D2423
LD TR0
AND>=(325) D549 D2422
AND<=(315) D549 D2423
OUT W5.11
; rung 2433
LD H62.00
OUT TR0
AND>(320) D2500 D2501
MOV(021) D2500 D2501
LD TR0
AND>=(325) D549 D2500
AND<=(315) D549 D2501
OUT W18.00
; rung 2434
LD H62.01
OUT TR0
AND>(320) D2502 D2503
MOV(021) D2502 D2503
LD TR0
AND>=(325) D549 D2502
AND<=(315) D549 D2503
OUT W18.01
; rung 2435
LD H62.02
OUT TR0
AND>(320) D2504 D2505
MOV(021) D2504 D2505
LD TR0
AND>=(325) D549 D2504
AND<=(315) D549 D2505
OUT W18.02

; rung 2436
LD H62.03
OUT TR0
AND>(320) D2506 D2507
MOV(021) D2506 D2507
LD TR0
AND>=(325) D549 D2506
AND<=(315) D549 D2507
OUT W18.03
; rung 2437
LD H62.04
OUT TR0
AND>(320) D2508 D2509
MOV(021) D2508 D2509
LD TR0
AND>=(325) D549 D2508
AND<=(315) D549 D2509
OUT W18.04
; rung 2438
LD H62.05
OUT TR0
AND>(320) D2510 D2511
MOV(021) D2510 D2511
LD TR0
AND>=(325) D549 D2510
AND<=(315) D549 D2511
OUT W18.05
; rung 2439
LD H62.06
OUT TR0
AND>(320) D2512 D2513
MOV(021) D2512 D2513
LD TR0
AND>=(325) D549 D2512
AND<=(315) D549 D2513
OUT W18.06
; rung 2440
LD H62.07
OUT TR0
AND>(320) D2514 D2515
MOV(021) D2514 D2515
LD TR0
AND>=(325) D549 D2514
AND<=(315) D549 D2515
OUT W18.07
; rung 2441
LD H62.08
OUT TR0
AND>(320) D2516 D2517
MOV(021) D2516 D2517
LD TR0
AND>=(325) D549 D2516
AND<=(315) D549 D2517
OUT W18.08

; rung 2442
LD H62.09
OUT TR0
AND>(320) D2518 D2519
MOV(021) D2518 D2519
LD TR0
AND>=(325) D549 D2518
AND<=(315) D549 D2519
OUT W18.09
; rung 2443
LD H62.10
OUT TR0
AND>(320) D2520 D2521
MOV(021) D2520 D2521
LD TR0
AND>=(325) D549 D2520
AND<=(315) D549 D2521
OUT W18.10
; rung 2444
LD H62.11
OUT TR0
AND>(320) D2522 D2523
MOV(021) D2522 D2523
LD TR0
AND>=(325) D549 D2522
AND<=(315) D549 D2523
OUT W18.11
; rung 2445: ---------- 右型開ｲﾝﾀｰﾛｯｸ有効範囲判別 ---------- / １号機は常時判別処理していたがｻｲｸﾙﾀｲﾑを短縮する為、INL.有効時のみ判別
LD H92.00
OUT TR0
AND>(320) D2424 D2425
MOV(021) D2424 D2425
LD TR0
AND>=(325) D579 D2424
AND<=(315) D579 D2425
OUT W6.00
; rung 2446
LD H92.01
OUT TR0
AND>(320) D2426 D2427
MOV(021) D2426 D2427
LD TR0
AND>=(325) D579 D2426
AND<=(315) D579 D2427
OUT W6.01
; rung 2447
LD H92.02
OUT TR0
AND>(320) D2428 D2429
MOV(021) D2428 D2429
LD TR0
AND>=(325) D579 D2428
AND<=(315) D579 D2429
OUT W6.02

; rung 2448
LD H92.03
OUT TR0
AND>(320) D2430 D2431
MOV(021) D2430 D2431
LD TR0
AND>=(325) D579 D2430
AND<=(315) D579 D2431
OUT W6.03
; rung 2449
LD H92.04
OUT TR0
AND>(320) D2432 D2433
MOV(021) D2432 D2433
LD TR0
AND>=(325) D579 D2432
AND<=(315) D579 D2433
OUT W6.04
; rung 2450
LD H92.05
OUT TR0
AND>(320) D2434 D2435
MOV(021) D2434 D2435
LD TR0
AND>=(325) D579 D2434
AND<=(315) D579 D2435
OUT W6.05
; rung 2451
LD H92.06
OUT TR0
AND>(320) D2436 D2437
MOV(021) D2436 D2437
LD TR0
AND>=(325) D579 D2436
AND<=(315) D579 D2437
OUT W6.06
; rung 2452
LD H92.07
OUT TR0
AND>(320) D2438 D2439
MOV(021) D2438 D2439
LD TR0
AND>=(325) D579 D2438
AND<=(315) D579 D2439
OUT W6.07
; rung 2453
LD H92.08
OUT TR0
AND>(320) D2440 D2441
MOV(021) D2440 D2441
LD TR0
AND>=(325) D579 D2440
AND<=(315) D579 D2441
OUT W6.08

; rung 2454
LD H92.09
OUT TR0
AND>(320) D2442 D2443
MOV(021) D2442 D2443
LD TR0
AND>=(325) D579 D2442
AND<=(315) D579 D2443
OUT W6.09
; rung 2455
LD H92.10
OUT TR0
AND>(320) D2444 D2445
MOV(021) D2444 D2445
LD TR0
AND>=(325) D579 D2444
AND<=(315) D579 D2445
OUT W6.10
; rung 2456
LD H92.11
OUT TR0
AND>(320) D2446 D2447
MOV(021) D2446 D2447
LD TR0
AND>=(325) D579 D2446
AND<=(315) D579 D2447
OUT W6.11
; rung 2457
LD H72.00
OUT TR0
AND>(320) D2524 D2525
MOV(021) D2524 D2525
LD TR0
AND>=(325) D579 D2524
AND<=(315) D579 D2525
OUT W19.00
; rung 2458
LD H72.01
OUT TR0
AND>(320) D2526 D2527
MOV(021) D2526 D2527
LD TR0
AND>=(325) D579 D2526
AND<=(315) D579 D2527
OUT W19.01
; rung 2459
LD H72.02
OUT TR0
AND>(320) D2528 D2529
MOV(021) D2528 D2529
LD TR0
AND>=(325) D579 D2528
AND<=(315) D579 D2529
OUT W19.02

; rung 2460
LD H72.03
OUT TR0
AND>(320) D2530 D2531
MOV(021) D2530 D2531
LD TR0
AND>=(325) D579 D2530
AND<=(315) D579 D2531
OUT W19.03
; rung 2461
LD H72.04
OUT TR0
AND>(320) D2532 D2533
MOV(021) D2532 D2533
LD TR0
AND>=(325) D579 D2532
AND<=(315) D579 D2533
OUT W19.04
; rung 2462
LD H72.05
OUT TR0
AND>(320) D2534 D2535
MOV(021) D2534 D2535
LD TR0
AND>=(325) D579 D2534
AND<=(315) D579 D2535
OUT W19.05
; rung 2463
LD H72.06
OUT TR0
AND>(320) D2536 D2537
MOV(021) D2536 D2537
LD TR0
AND>=(325) D579 D2536
AND<=(315) D579 D2537
OUT W19.06
; rung 2464
LD H72.07
OUT TR0
AND>(320) D2538 D2539
MOV(021) D2538 D2539
LD TR0
AND>=(325) D579 D2538
AND<=(315) D579 D2539
OUT W19.07
; rung 2465
LD H72.08
OUT TR0
AND>(320) D2540 D2541
MOV(021) D2540 D2541
LD TR0
AND>=(325) D579 D2540
AND<=(315) D579 D2541
OUT W19.08

; rung 2466
LD H72.09
OUT TR0
AND>(320) D2542 D2543
MOV(021) D2542 D2543
LD TR0
AND>=(325) D579 D2542
AND<=(315) D579 D2543
OUT W19.09
; rung 2467
LD H72.10
OUT TR0
AND>(320) D2544 D2545
MOV(021) D2544 D2545
LD TR0
AND>=(325) D579 D2544
AND<=(315) D579 D2545
OUT W19.10
; rung 2468
LD H72.11
OUT TR0
AND>(320) D2546 D2547
MOV(021) D2546 D2547
LD TR0
AND>=(325) D579 D2546
AND<=(315) D579 D2547
OUT W19.11
; rung 2469: ---------- 左型閉ｲﾝﾀｰﾛｯｸ有効範囲判別 ----------
LD H81.00
OUT TR0
AND>(320) D2448 D2449
MOV(021) D2448 D2449
LD TR0
AND>=(325) D549 D2448
AND<=(315) D549 D2449
OUT W7.00
; rung 2470
LD H81.01
OUT TR0
AND>(320) D2450 D2451
MOV(021) D2450 D2451
LD TR0
AND>=(325) D549 D2450
AND<=(315) D549 D2451
OUT W7.01
; rung 2471
LD H81.02
OUT TR0
AND>(320) D2452 D2453
MOV(021) D2452 D2453
LD TR0
AND>=(325) D549 D2452
AND<=(315) D549 D2453
OUT W7.02

; rung 2472
LD H81.03
OUT TR0
AND>(320) D2454 D2455
MOV(021) D2454 D2455
LD TR0
AND>=(325) D549 D2454
AND<=(315) D549 D2455
OUT W7.03
; rung 2473
LD H81.04
OUT TR0
AND>(320) D2456 D2457
MOV(021) D2456 D2457
LD TR0
AND>=(325) D549 D2456
AND<=(315) D549 D2457
OUT W7.04
; rung 2474
LD H81.05
OUT TR0
AND>(320) D2458 D2459
MOV(021) D2458 D2459
LD TR0
AND>=(325) D549 D2458
AND<=(315) D549 D2459
OUT W7.05
; rung 2475
LD H81.06
OUT TR0
AND>(320) D2460 D2461
MOV(021) D2460 D2461
LD TR0
AND>=(325) D549 D2460
AND<=(315) D549 D2461
OUT W7.06
; rung 2476
LD H81.07
OUT TR0
AND>(320) D2462 D2463
MOV(021) D2462 D2463
LD TR0
AND>=(325) D549 D2462
AND<=(315) D549 D2463
OUT W7.07
; rung 2477
LD H81.08
OUT TR0
AND>(320) D2464 D2465
MOV(021) D2464 D2465
LD TR0
AND>=(325) D549 D2464
AND<=(315) D549 D2465
OUT W7.08

; rung 2478
LD H81.09
OUT TR0
AND>(320) D2466 D2467
MOV(021) D2466 D2467
LD TR0
AND>=(325) D549 D2466
AND<=(315) D549 D2467
OUT W7.09
; rung 2479
LD H81.10
OUT TR0
AND>(320) D2468 D2469
MOV(021) D2468 D2469
LD TR0
AND>=(325) D549 D2468
AND<=(315) D549 D2469
OUT W7.10
; rung 2480
LD H81.11
OUT TR0
AND>(320) D2470 D2471
MOV(021) D2470 D2471
LD TR0
AND>=(325) D549 D2470
AND<=(315) D549 D2471
OUT W7.11
; rung 2481
LD H61.00
OUT TR0
AND>(320) D2548 D2549
MOV(021) D2548 D2549
LD TR0
AND>=(325) D549 D2548
AND<=(315) D549 D2549
OUT W20.00
; rung 2482
LD H61.01
OUT TR0
AND>(320) D2550 D2551
MOV(021) D2550 D2551
LD TR0
AND>=(325) D549 D2550
AND<=(315) D549 D2551
OUT W20.01
; rung 2483
LD H61.02
OUT TR0
AND>(320) D2552 D2553
MOV(021) D2552 D2553
LD TR0
AND>=(325) D549 D2552
AND<=(315) D549 D2553
OUT W20.02

; rung 2484
LD H61.03
OUT TR0
AND>(320) D2554 D2555
MOV(021) D2554 D2555
LD TR0
AND>=(325) D549 D2554
AND<=(315) D549 D2555
OUT W20.03
; rung 2485
LD H61.04
OUT TR0
AND>(320) D2556 D2557
MOV(021) D2556 D2557
LD TR0
AND>=(325) D549 D2556
AND<=(315) D549 D2557
OUT W20.04
; rung 2486
LD H61.05
OUT TR0
AND>(320) D2558 D2559
MOV(021) D2558 D2559
LD TR0
AND>=(325) D549 D2558
AND<=(315) D549 D2559
OUT W20.05
; rung 2487
LD H61.06
OUT TR0
AND>(320) D2560 D2561
MOV(021) D2560 D2561
LD TR0
AND>=(325) D549 D2560
AND<=(315) D549 D2561
OUT W20.06
; rung 2488
LD H61.07
OUT TR0
AND>(320) D2562 D2563
MOV(021) D2562 D2563
LD TR0
AND>=(325) D549 D2562
AND<=(315) D549 D2563
OUT W20.07
; rung 2489
LD H61.08
OUT TR0
AND>(320) D2564 D2565
MOV(021) D2564 D2565
LD TR0
AND>=(325) D549 D2564
AND<=(315) D549 D2565
OUT W20.08

; rung 2490
LD H61.09
OUT TR0
AND>(320) D2566 D2567
MOV(021) D2566 D2567
LD TR0
AND>=(325) D549 D2566
AND<=(315) D549 D2567
OUT W20.09
; rung 2491
LD H61.10
OUT TR0
AND>(320) D2568 D2569
MOV(021) D2568 D2569
LD TR0
AND>=(325) D549 D2568
AND<=(315) D549 D2569
OUT W20.10
; rung 2492
LD H61.11
OUT TR0
AND>(320) D2570 D2571
MOV(021) D2570 D2571
LD TR0
AND>=(325) D549 D2570
AND<=(315) D549 D2571
OUT W20.11
; rung 2493: ---------- 右型閉ｲﾝﾀｰﾛｯｸ有効範囲判別 ----------
LD H91.00
OUT TR0
AND>(320) D2472 D2473
MOV(021) D2472 D2473
LD TR0
AND>=(325) D579 D2472
AND<=(315) D579 D2473
OUT W8.00
; rung 2494
LD H91.01
OUT TR0
AND>(320) D2474 D2475
MOV(021) D2474 D2475
LD TR0
AND>=(325) D579 D2474
AND<=(315) D579 D2475
OUT W8.01
; rung 2495
LD H91.02
OUT TR0
AND>(320) D2476 D2477
MOV(021) D2476 D2477
LD TR0
AND>=(325) D579 D2476
AND<=(315) D579 D2477
OUT W8.02

; rung 2496
LD H91.03
OUT TR0
AND>(320) D2478 D2479
MOV(021) D2478 D2479
LD TR0
AND>=(325) D579 D2478
AND<=(315) D579 D2479
OUT W8.03
; rung 2497
LD H91.04
OUT TR0
AND>(320) D2480 D2481
MOV(021) D2480 D2481
LD TR0
AND>=(325) D579 D2480
AND<=(315) D579 D2481
OUT W8.04
; rung 2498
LD H91.05
OUT TR0
AND>(320) D2482 D2483
MOV(021) D2482 D2483
LD TR0
AND>=(325) D579 D2482
AND<=(315) D579 D2483
OUT W8.05
; rung 2499
LD H91.06
OUT TR0
AND>(320) D2484 D2485
MOV(021) D2484 D2485
LD TR0
AND>=(325) D579 D2484
AND<=(315) D579 D2485
OUT W8.06
; rung 2500
LD H91.07
OUT TR0
AND>(320) D2486 D2487
MOV(021) D2486 D2487
LD TR0
AND>=(325) D579 D2486
AND<=(315) D579 D2487
OUT W8.07
; rung 2501
LD H91.08
OUT TR0
AND>(320) D2488 D2489
MOV(021) D2488 D2489
LD TR0
AND>=(325) D579 D2488
AND<=(315) D579 D2489
OUT W8.08

; rung 2502
LD H91.09
OUT TR0
AND>(320) D2490 D2491
MOV(021) D2490 D2491
LD TR0
AND>=(325) D579 D2490
AND<=(315) D579 D2491
OUT W8.09
; rung 2503
LD H91.10
OUT TR0
AND>(320) D2492 D2493
MOV(021) D2492 D2493
LD TR0
AND>=(325) D579 D2492
AND<=(315) D579 D2493
OUT W8.10
; rung 2504
LD H91.11
OUT TR0
AND>(320) D2494 D2495
MOV(021) D2494 D2495
LD TR0
AND>=(325) D579 D2494
AND<=(315) D579 D2495
OUT W8.11
; rung 2505
LD H71.00
OUT TR0
AND>(320) D2572 D2573
MOV(021) D2572 D2573
LD TR0
AND>=(325) D579 D2572
AND<=(315) D579 D2573
OUT W21.00
; rung 2506
LD H71.01
OUT TR0
AND>(320) D2574 D2575
MOV(021) D2574 D2575
LD TR0
AND>=(325) D579 D2574
AND<=(315) D579 D2575
OUT W21.01
; rung 2507
LD H71.02
OUT TR0
AND>(320) D2576 D2577
MOV(021) D2576 D2577
LD TR0
AND>=(325) D579 D2576
AND<=(315) D579 D2577
OUT W21.02

; rung 2508
LD H71.03
OUT TR0
AND>(320) D2578 D2579
MOV(021) D2578 D2579
LD TR0
AND>=(325) D579 D2578
AND<=(315) D579 D2579
OUT W21.03
; rung 2509
LD H71.04
OUT TR0
AND>(320) D2580 D2581
MOV(021) D2580 D2581
LD TR0
AND>=(325) D579 D2580
AND<=(315) D579 D2581
OUT W21.04
; rung 2510
LD H71.05
OUT TR0
AND>(320) D2582 D2583
MOV(021) D2582 D2583
LD TR0
AND>=(325) D579 D2582
AND<=(315) D579 D2583
OUT W21.05
; rung 2511
LD H71.06
OUT TR0
AND>(320) D2584 D2585
MOV(021) D2584 D2585
LD TR0
AND>=(325) D579 D2584
AND<=(315) D579 D2585
OUT W21.06
; rung 2512
LD H71.07
OUT TR0
AND>(320) D2586 D2587
MOV(021) D2586 D2587
LD TR0
AND>=(325) D579 D2586
AND<=(315) D579 D2587
OUT W21.07
; rung 2513
LD H71.08
OUT TR0
AND>(320) D2588 D2589
MOV(021) D2588 D2589
LD TR0
AND>=(325) D579 D2588
AND<=(315) D579 D2589
OUT W21.08

; rung 2514
LD H71.09
OUT TR0
AND>(320) D2590 D2591
MOV(021) D2590 D2591
LD TR0
AND>=(325) D579 D2590
AND<=(315) D579 D2591
OUT W21.09
; rung 2515
LD H71.10
OUT TR0
AND>(320) D2592 D2593
MOV(021) D2592 D2593
LD TR0
AND>=(325) D579 D2592
AND<=(315) D579 D2593
OUT W21.10
; rung 2516
LD H71.11
OUT TR0
AND>(320) D2594 D2595
MOV(021) D2594 D2595
LD TR0
AND>=(325) D579 D2594
AND<=(315) D579 D2595
OUT W21.11
; rung 2517: ---------- 型動作判別 ----------
LD W189.01
OR W183.03
OR W183.07
OR W343.07
ANDNOT W223.04
ANDNOT W397.00
OUT W9.15
; rung 2518
LD W182.02
OR W182.03
ANDNOT W223.00
ANDNOT W397.00
OUT W9.14
; rung 2519
LD W319.01
OR W313.03
OR W313.07
OR W343.08
ANDNOT W225.01
ANDNOT W397.12
OUT W9.13

; rung 2520
LD W312.02
OR W312.03
ANDNOT W224.13
ANDNOT W397.12
OUT W9.12
; rung 2521: ---------- 左型閉ｲﾝﾀｰﾛｯｸ作動確認 ----------
LD H83.00
ANDNOT 2108.00
LD H83.01
ANDNOT 2108.01
ORLD
AND H81.00
AND W7.00
LD H83.02
ANDNOT 2108.02
LD H83.03
ANDNOT 2108.03
ORLD
AND H81.01
AND W7.01
ORLD
LD H83.04
ANDNOT 2108.04
LD H83.05
ANDNOT 2108.05
ORLD
AND H81.02
AND W7.02
ORLD
LD H83.06
ANDNOT 2108.08
LD H83.07
ANDNOT 2108.09
ORLD
AND H81.03
AND W7.03
ORLD
LD H83.08
ANDNOT 2034.00
LD H83.09
ANDNOT 2034.01
ORLD
AND H81.04
AND W7.04
ORLD
LD H83.10
ANDNOT 2110.00
LD H83.11
ANDNOT 2110.01
ORLD
AND H81.05
AND W7.05
ORLD
AND W9.15
OUT W9.11

; rung 2522
LD H83.12
ANDNOT 2034.02
LD H83.13
ANDNOT 2034.03
ORLD
AND H81.06
AND W7.06
LD H83.14
ANDNOT 2108.10
LD H83.15
ANDNOT 2108.11
ORLD
AND H81.07
AND W7.07
ORLD
LD H84.00
ANDNOT 2108.14
LD H84.01
ANDNOT 2108.15
ORLD
AND H81.08
AND W7.08
ORLD
LD H84.02
ANDNOT 2035.02
LD H84.03
ANDNOT 2035.03
ORLD
AND H81.09
AND W7.09
ORLD
LD H84.04
ANDNOT 2035.04
LD H84.05
ANDNOT 2035.05
ORLD
AND H81.10
AND W7.10
ORLD
LD H84.06
ANDNOT 2034.14
LD H84.07
ANDNOT 2034.15
ORLD
AND H81.11
AND W7.11
ORLD
AND W9.15
OUT W9.10
; rung 2523
LD H63.00
ANDNOT 2034.04
LD H63.01
ANDNOT 2034.05
ORLD
AND H61.00
AND W20.00
LD H63.02
ANDNOT 2035.14
LD H63.03
ANDNOT 2035.15
ORLD
AND H61.01
AND W20.01
ORLD
LD H63.04
ANDNOT 2108.06
LD H63.05
ANDNOT 2108.07
ORLD
AND H61.02
AND W20.02
ORLD
LD H63.06
ANDNOT 2109.02
LD H63.07
ANDNOT 2109.03
ORLD
AND H61.03
AND W20.03
ORLD
LD H63.08
ANDNOT 2109.14
LD H63.09
ANDNOT 2109.15
ORLD
AND H61.04
AND W20.04
ORLD
LD H63.10
ANDNOT 2110.02
LD H63.11
ANDNOT 2110.04
ORLD
AND H61.05
AND W20.05
ORLD
AND W9.15
OUT W7.14

; rung 2524
LD H63.12
ANDNOT 2110.05
LD H63.13
ANDNOT 2110.13
ORLD
AND H61.06
AND W20.06
LD H63.14
ANDNOT 2035.12
LD H63.15
ANDNOT 2035.13
ORLD
AND H61.07
AND W20.07
ORLD
LD H64.00
ANDNOT 2109.09
LD H64.01
ANDNOT 2109.12
ORLD
AND H61.08
AND W20.08
ORLD
LD H64.02
ANDNOT 2034.06
LD H64.03
ANDNOT 2034.07
ORLD
AND H61.09
AND W20.09
ORLD
LD H64.04
OR H64.05
ANDNOT P_On
AND H61.10
AND W20.10
ORLD
LD H64.06
OR H64.07
ANDNOT P_On
AND H61.11
AND W20.11
ORLD
AND W9.15
OUT W7.15
; rung 2525
LD W9.11
OR W9.10
OR W7.14
OR W7.15
OUT W9.09

; rung 2526: ---------- 左型開ｲﾝﾀｰﾛｯｸ作動確認 ----------
LD H84.08
ANDNOT 2108.00
LD H84.09
ANDNOT 2108.01
ORLD
AND H82.00
AND W5.00
LD H84.10
ANDNOT 2108.02
LD H84.11
ANDNOT 2108.03
ORLD
AND H82.01
AND W5.01
ORLD
LD H84.12
ANDNOT 2108.04
LD H84.13
ANDNOT 2108.05
ORLD
AND H82.02
AND W5.02
ORLD
LD H84.14
ANDNOT 2108.08
LD H84.15
ANDNOT 2108.09
ORLD
AND H82.03
AND W5.03
ORLD
LD H85.00
ANDNOT 2034.00
LD H85.01
ANDNOT 2034.01
ORLD
AND H82.04
AND W5.04
ORLD
LD H85.02
ANDNOT 2110.00
LD H85.03
ANDNOT 2110.01
ORLD
AND H82.05
AND W5.05
ORLD
AND W9.14
OUT W9.08
; rung 2527
LD H85.04
ANDNOT 2034.02
LD H85.05
ANDNOT 2034.03
ORLD
AND H82.06
AND W5.06
LD H85.06
ANDNOT 2108.10
LD H85.07
ANDNOT 2108.11
ORLD
AND H82.07
AND W5.07
ORLD
LD H85.08
ANDNOT 2108.14
LD H85.09
ANDNOT 2108.15
ORLD
AND H82.08
AND W5.08
ORLD
LD H85.10
ANDNOT 2035.02
LD H85.11
ANDNOT 2035.03
ORLD
AND H82.09
AND W5.09
ORLD
LD H85.12
ANDNOT 2035.04
LD H85.13
ANDNOT 2035.05
ORLD
AND H82.10
AND W5.10
ORLD
LD H85.14
ANDNOT 2034.14
LD H85.15
ANDNOT 2034.15
ORLD
AND H82.11
AND W5.11
ORLD
AND W9.14
OUT W9.07

; rung 2528
LD H64.08
ANDNOT 2034.04
LD H64.09
ANDNOT 2034.05
ORLD
AND H62.00
AND W18.00
LD H64.10
ANDNOT 2035.14
LD H64.11
ANDNOT 2035.15
ORLD
AND H62.01
AND W18.01
ORLD
LD H64.12
ANDNOT 2108.06
LD H64.13
ANDNOT 2108.07
ORLD
AND H62.02
AND W18.02
ORLD
LD H64.14
ANDNOT 2109.02
LD H64.15
ANDNOT 2109.03
ORLD
AND H62.03
AND W18.03
ORLD
LD H65.00
ANDNOT 2109.14
LD H65.01
ANDNOT 2109.15
ORLD
AND H62.04
AND W18.04
ORLD
LD H65.02
ANDNOT 2110.02
LD H65.03
ANDNOT 2110.04
ORLD
AND H62.05
AND W18.05
ORLD
AND W9.14
OUT W5.14
; rung 2529
LD H65.04
ANDNOT 2110.05
LD H65.05
ANDNOT 2110.13
ORLD
AND H62.06
AND W18.06
LD H65.06
ANDNOT 2037.12
LD H65.07
ANDNOT 2037.13
ORLD
AND H62.07
AND W18.07
ORLD
LD H65.08
ANDNOT 2109.09
LD H65.09
ANDNOT 2109.12
ORLD
AND H62.08
AND W18.08
ORLD
LD H65.10
ANDNOT 2034.06
LD H65.11
ANDNOT 2034.07
ORLD
AND H62.09
AND W18.09
ORLD
LD H65.12
OR H65.13
ANDNOT P_On
AND H62.10
AND W18.10
ORLD
LD H65.14
OR H65.15
ANDNOT P_On
AND H62.11
AND W18.11
ORLD
AND W9.14
OUT W5.15

; rung 2530
LD W9.08
OR W9.07
OR W5.14
OR W5.15
OUT W9.06
; rung 2531: ---------- 右型閉ｲﾝﾀｰﾛｯｸ作動確認 ----------
LD H93.00
ANDNOT 2128.00
LD H93.01
ANDNOT 2128.01
ORLD
AND H91.00
AND W8.00
LD H93.02
ANDNOT 2128.02
LD H93.03
ANDNOT 2128.03
ORLD
AND H91.01
AND W8.01
ORLD
LD H93.04
ANDNOT 2128.04
LD H93.05
ANDNOT 2128.05
ORLD
AND H91.02
AND W8.02
ORLD
LD H93.06
ANDNOT 2128.08
LD H93.07
ANDNOT 2128.09
ORLD
AND H91.03
AND W8.03
ORLD
LD H93.08
ANDNOT 2036.00
LD H93.09
ANDNOT 2036.01
ORLD
AND H91.04
AND W8.04
ORLD
LD H93.10
ANDNOT 2130.00
LD H93.11
ANDNOT 2130.01
ORLD
AND H91.05
AND W8.05
ORLD
AND W9.13
OUT W15.00

; rung 2532
LD H93.12
ANDNOT 2036.02
LD H93.13
ANDNOT 2036.03
ORLD
AND H91.06
AND W8.06
LD H93.14
ANDNOT 2128.10
LD H93.15
ANDNOT 2128.11
ORLD
AND H91.07
AND W8.07
ORLD
LD H94.00
ANDNOT 2128.14
LD H94.01
ANDNOT 2128.15
ORLD
AND H91.08
AND W8.08
ORLD
LD H94.02
ANDNOT 2037.02
LD H94.03
ANDNOT 2037.03
ORLD
AND H91.09
AND W8.09
ORLD
LD H94.04
ANDNOT 2037.04
LD H94.05
ANDNOT 2037.05
ORLD
AND H91.10
AND W8.10
ORLD
LD H94.06
ANDNOT 2036.14
LD H94.07
ANDNOT 2036.15
ORLD
AND H91.11
AND W8.11
ORLD
AND W9.13
OUT W15.01
; rung 2533
LD H73.00
ANDNOT 2036.04
LD H73.01
ANDNOT 2036.05
ORLD
AND H71.00
AND W21.00
LD H73.02
ANDNOT 2037.14
LD H73.03
ANDNOT 2037.15
ORLD
AND H71.01
AND W21.01
ORLD
LD H73.04
ANDNOT 2128.06
LD H73.05
ANDNOT 2128.07
ORLD
AND H71.02
AND W21.02
ORLD
LD H73.06
ANDNOT 2129.02
LD H73.07
ANDNOT 2129.03
ORLD
AND H71.03
AND W21.03
ORLD
LD H73.08
ANDNOT 2129.14
LD H73.09
ANDNOT 2129.15
ORLD
AND H71.04
AND W21.04
ORLD
LD H73.10
ANDNOT 2130.02
LD H73.11
ANDNOT 2130.04
ORLD
AND H71.05
AND W21.05
ORLD
AND W9.13
OUT W8.14

; rung 2534
LD H73.12
ANDNOT 2130.05
LD H73.13
ANDNOT 2130.13
ORLD
AND H71.06
AND W21.06
LD H73.14
ANDNOT 2037.12
LD H73.15
ANDNOT 2037.13
ORLD
AND H71.07
AND W21.07
ORLD
LD H74.00
ANDNOT 2129.09
LD H74.01
ANDNOT 2129.12
ORLD
AND H71.08
AND W21.08
ORLD
LD H74.02
ANDNOT 2036.06
LD H74.03
ANDNOT 2036.07
ORLD
AND H71.09
AND W21.09
ORLD
LD H74.04
OR H74.05
ANDNOT P_On
AND H71.10
AND W21.10
ORLD
LD H74.06
OR H74.07
ANDNOT P_On
AND H71.11
AND W21.11
ORLD
AND W9.13
OUT W8.15
; rung 2535
LD W15.00
OR W15.01
OR W8.14
OR W8.15
OUT W15.02

; rung 2536: ---------- 右型開ｲﾝﾀｰﾛｯｸ作動確認 ----------
LD H94.08
ANDNOT 2128.00
LD H94.09
ANDNOT 2128.01
ORLD
AND H92.00
AND W6.00
LD H94.10
ANDNOT 2128.02
LD H94.11
ANDNOT 2128.03
ORLD
AND H92.01
AND W6.01
ORLD
LD H94.12
ANDNOT 2128.04
LD H94.13
ANDNOT 2128.05
ORLD
AND H92.02
AND W6.02
ORLD
LD H94.14
ANDNOT 2128.08
LD H94.15
ANDNOT 2128.09
ORLD
AND H92.03
AND W6.03
ORLD
LD H95.00
ANDNOT 2036.00
LD H95.01
ANDNOT 2036.01
ORLD
AND H92.04
AND W6.04
ORLD
LD H95.02
ANDNOT 2130.00
LD H95.03
ANDNOT 2130.01
ORLD
AND H92.05
AND W6.05
ORLD
AND W9.12
OUT W15.03
; rung 2537
LD H95.04
ANDNOT 2036.02
LD H95.05
ANDNOT 2036.03
ORLD
AND H92.06
AND W6.06
LD H95.06
ANDNOT 2128.10
LD H95.07
ANDNOT 2128.11
ORLD
AND H92.07
AND W6.07
ORLD
LD H95.08
ANDNOT 2128.14
LD H95.09
ANDNOT 2128.15
ORLD
AND H92.08
AND W6.08
ORLD
LD H95.10
ANDNOT 2037.02
LD H95.11
ANDNOT 2037.03
ORLD
AND H92.09
AND W6.09
ORLD
LD H95.12
ANDNOT 2037.04
LD H95.13
ANDNOT 2037.05
ORLD
AND H92.10
AND W6.10
ORLD
LD H95.14
ANDNOT 2036.14
LD H95.15
ANDNOT 2036.15
ORLD
AND H92.11
AND W6.11
ORLD
AND W9.12
OUT W15.04

; rung 2538
LD H74.08
ANDNOT 2036.04
LD H74.09
ANDNOT 2036.05
ORLD
AND H72.00
AND W19.00
LD H74.10
ANDNOT 2037.14
LD H74.11
ANDNOT 2037.15
ORLD
AND H72.01
AND W19.01
ORLD
LD H74.12
ANDNOT 2128.06
LD H74.13
ANDNOT 2128.07
ORLD
AND H72.02
AND W19.02
ORLD
LD H74.14
ANDNOT 2129.02
LD H74.15
ANDNOT 2129.03
ORLD
AND H72.03
AND W19.03
ORLD
LD H75.00
ANDNOT 2129.14
LD H75.01
ANDNOT 2129.15
ORLD
AND H72.04
AND W19.04
ORLD
LD H75.02
ANDNOT 2130.02
LD H75.03
ANDNOT 2130.04
ORLD
AND H72.05
AND W19.05
ORLD
AND W9.12
OUT W6.14
; rung 2539
LD H75.04
ANDNOT 2130.05
LD H75.05
ANDNOT 2130.13
ORLD
AND H72.06
AND W19.06
LD H75.06
ANDNOT 2037.12
LD H75.07
ANDNOT 2037.13
ORLD
AND H72.07
AND W19.07
ORLD
LD H75.08
ANDNOT 2129.09
LD H75.09
ANDNOT 2129.12
ORLD
AND H72.08
AND W19.08
ORLD
LD H75.10
ANDNOT 2036.06
LD H75.11
ANDNOT 2036.07
ORLD
AND H72.09
AND W19.09
ORLD
LD H75.12
OR H75.13
ANDNOT P_On
AND H72.10
AND W19.10
ORLD
LD H75.14
OR H75.15
ANDNOT P_On
AND H72.11
AND W19.11
ORLD
AND W9.12
OUT W6.15

; rung 2540
LD W15.03
OR W15.04
OR W6.14
OR W6.15
OUT W15.05
; rung 2541: ********** 移送調整処理 **********
LD P_On
AND=(300) W400 #65
OUT W181.15
; rung 2542
LD W182.11
OR W182.13
AND W170.13
ANDNOT W182.12
AND W181.15
AND T0020
OUT W182.13
; rung 2543
LD W181.15
MOV(021) D274 D985
MOV(021) D224 D995

; rung 2544
LD W182.13
OUT TR0
AND W182.14
TIM 0503 #20
LD TR0
AND W182.15
TIM 0502 #20
LD TR0
AND W307.07
TIM 0428 #20
LD TR0
AND W307.08
TIM 0429 #20
LD TR0
AND W307.09
TIM 0430 #20
LD TR0
AND W307.10
TIM 0431 #20
LD TR0
MOV(021) #0 D986
MOV(021) #4000 D988
; rung 2545
LD T0428
@MOV(021) D232 D3065
; rung 2546
LD T0429
@MOV(021) D232 D3066
; rung 2547
LD T0430
@MOV(021) D282 D3072
; rung 2548
LD T0431
@MOV(021) D282 D3073

; rung 2549
LD T0502
@MOV(021) D273 D989
; rung 2550
LD T0503
@MOV(021) D273 D987
; rung 2551: --- 左成形機旋回POT.AD取込値SCL ---
LD P_On
OUT TR0
MOV(021) 2001 D273
SCL(194) D273 D986 D274
AND<(310) #4000 D274
MOV(021) #4000 D274
LD TR0
AND>=(325) #0 D274
MOV(021) #0 D274
; rung 2552: --- 左旋回位置変換 ---
LD P_On
*B(424) D274 #2500 D280
MOV(021) D281 D282
AND<(310) #999 D282
MOV(021) #999 D282

; rung 2553: --- 左成形機位置判別 ---
LD P_On
OUT TR0
CMP(020) D200 D282
LD P_EQ
OR P_GT
ANDLD
OUT W181.12
LD TR0
AND<=(315) #2 D282
AND 22.08
OUT TR1
AND T0434
OUT W181.04
LD TR1
TIM 0434 #10
LD TR0
CMP(020) D201 D282
LD P_EQ
OR P_GT
OR W181.13
ANDLD
OUT TR0
ANDNOT W181.12
ANDNOT W176.00
OUT W181.13
LD TR0
OUTNOT W181.09
; rung 2554
LDNOT P_On
LD<=(315) D273 #104
OR>=(325) D273 #10A
ANDLD
AND 22.08
OUT TR0
AND T0446
OUT W178.00
LD TR0
TIM 0446 #20
; rung 2555
LD P_On
OUT TR0
CMP(020) D202 D282
LD P_EQ
OR P_LT
LDNOT 14.12
AND W181.14
ORLD
ANDLD
OUT W181.14
LD TR0
AND>=(325) #996 D282
AND 22.09
OUT TR0
AND T0435
OUT W181.05
LD TR0
TIM 0435 #10

; rung 2556
LDNOT P_On
LD<=(315) D273 #F4A
OR>=(325) D273 #F51
ANDLD
AND 22.09
OUT TR0
AND T0447
OUT W178.01
LD TR0
TIM 0447 #50
; rung 2557
LD W182.13
OUT TR0
AND W312.14
TIM 0403 #20
LD TR0
AND W312.15
TIM 0402 #20
LD TR0
MOV(021) #0 D996
MOV(021) #4000 D998
; rung 2558
LD T0402
@MOV(021) D223 D999
; rung 2559
LD T0403
@MOV(021) D223 D997
; rung 2560: --- 右成形機旋回POT.AD取込値SCL ---
LD P_On
OUT TR0
MOV(021) 2003 D223
SCL(194) D223 D996 D224
AND<(310) #4000 D224
MOV(021) #4000 D224
LD TR0
AND>=(325) #0 D224
MOV(021) #0 D224

; rung 2561: --- 右旋回位置変換 ---
LD P_On
*B(424) D224 #2500 D230
MOV(021) D231 D232
AND<(310) #999 D232
MOV(021) #999 D232
; rung 2562: --- 右成形位置判別 ---
LD P_On
OUT TR0
CMP(020) D205 D232
LD P_EQ
OR P_GT
ANDLD
OUT W311.12
LD TR0
AND<=(315) #2 D232
AND 22.10
OUT TR1
AND T0432
OUT W311.00
LD TR1
TIM 0432 #10
LD TR0
CMP(020) D206 D232
LD P_EQ
OR P_GT
OR W311.13
ANDLD
OUT TR0
ANDNOT W311.12
ANDNOT W306.00
OUT W311.13
LD TR0
OUTNOT W311.09
; rung 2563
LDNOT P_On
LD<=(315) D223 #E09
OR>=(325) D223 #E10
ANDLD
AND 22.11
OUT TR0
AND T0436
OUT W311.02
LD TR0
TIM 0436 #50

; rung 2564
LD P_On
OUT TR0
CMP(020) D207 D232
LD P_EQ
OR P_LT
LDNOT 14.14
AND W311.14
ORLD
ANDLD
OUT W311.14
LD TR0
AND>=(325) #996 D232
AND 22.11
OUT TR0
AND T0433
OUT W311.01
LD TR0
TIM 0433 #10
; rung 2565
LDNOT P_On
LD<=(315) D223 #DA
OR>=(325) D223 #E2
ANDLD
AND 22.10
OUT TR0
AND T0437
OUT W311.03
LD TR0
TIM 0437 #20
; rung 2566: '***** ﾀﾞｲ位置設定ﾌﾟﾛｸﾞﾗﾑ ***** / ｴﾝｺｰﾀﾞからの値取込（ﾃﾞｰﾀ転送）はシーケンサのｻｲｸﾙﾀｲﾑ毎に取り込んでいる / この為CPUが違うと障害発生する可能性有り
LD P_First_Cycle
MOV(021) #125 D3046
MOV(021) #0 D3047
MOV(021) #188 D3048
MOV(021) #0 D3049
; rung 2567
LD 18.00
OR 18.01
OR 18.02
OR 18.03
OR 18.04
OR 18.05
AND T0511
ANDNOT W384.00
ANDNOT W331.15
AND W374.12
LDNOT W35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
